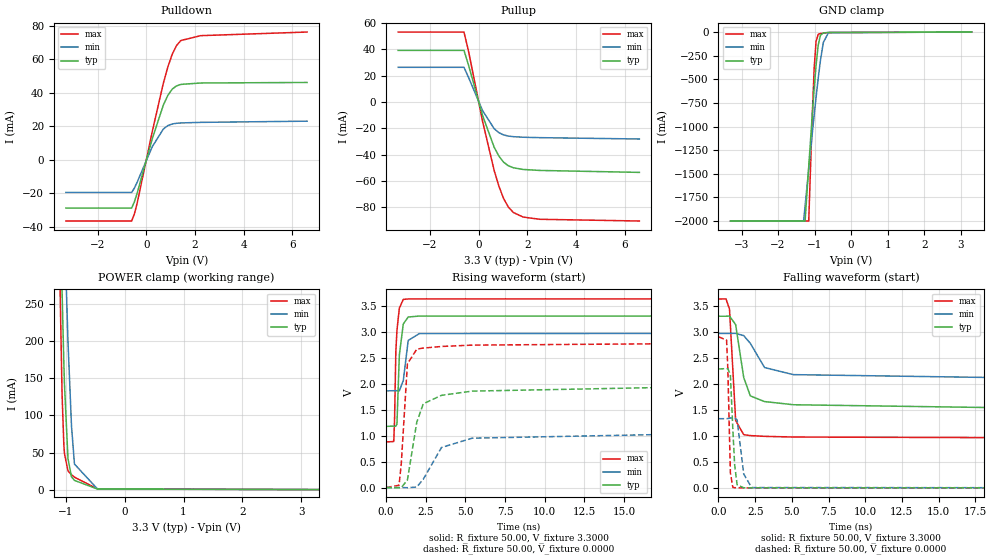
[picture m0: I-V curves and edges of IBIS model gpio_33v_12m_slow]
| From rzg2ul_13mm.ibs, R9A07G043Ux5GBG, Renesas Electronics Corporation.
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[Model]   gpio_33v_12m_slow
Model_type   I/O
Polarity   Non-Inverting
Enable   Active-Low
Vinl  =   0.8000V
Vinh  =   2.0000V
Vmeas =   1.6500V
Cref  =   15.00pF
| variable   typ   min   max
C_comp   2.126e-12  1.947e-12  2.126e-12
[Model Spec]
| Subparameter   typ   min   max
| Thresholds
Vinh   2.0000   NA   NA
Vinl   0.8000   NA   NA
| Timing Thresholds
Vmeas   1.6500   1.4850   1.8150
| variable   typ   min   max
[Temperature Range]   25.000   125.000   -40.000
| variable   typ   min   max
[Voltage Range]   3.300V   2.970V   3.630V
| variable   typ   min   max
[Pullup Reference]   3.300V   2.970V   3.630V
| variable   typ   min   max
[Pulldown Reference]   0.000V   0.000V   0.000V
| variable   typ   min   max
[POWER Clamp Reference] 3.300V   2.970V   3.630V
| variable   typ   min   max
[GND Clamp Reference]   0.000V   0.000V   0.000V
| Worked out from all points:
|   slope of the pulldown table from 0 to 0.495 V, typ, clamps not added: 20.4 ohm
|   slope of the pullup table from 0 to 0.495 V, typ, clamps not added: 17.6 ohm
|   GND clamp passes 1 mA (typ) near -0.48 V on its own axis
|   POWER clamp passes 1 mA (typ) near -0.48 V on its own axis
|   rising waveform, R_fixture 50.00, V_fixture 3.3000: 20-80 % time 190ps typ, 235ps min, 155ps max; typ from 1.18 V to 3.3 V
|   rising waveform, R_fixture 50.00, V_fixture 0.0000: 20-80 % time 3.08ns typ, 11ns min, 341ps max; typ from 0 V to 2.29 V
|   falling waveform, R_fixture 50.00, V_fixture 3.3000: 20-80 % time 3.61ns typ, 14.9ns min, 289ps max; typ from 3.3 V to 1.18 V
|   falling waveform, R_fixture 50.00, V_fixture 0.0000: 20-80 % time 209ps typ, 312ps min, 143ps max; typ from 2.29 V to 0 V
[Pulldown]
| gpio_33v_12m_slow Pulldown S28FDSIO_IBIS
| Wed Sep  2 14:14:57 2020
| voltage   I(typ)   I(min)   I(max)
-3.3V     -28.69mA   -19.38mA   -36.41mA
-600mV    -28.69mA   -19.38mA   -36.41mA
-490mV    -25.1mA    -16.85mA   -32.31mA
-380mV    -20.16mA   -13.49mA   -26.24mA
250mV     12.74mA    7.933mA    17.12mA
700mV     32.62mA    18.36mA    45.59mA
890mV     38.56mA    20.47mA    55.56mA
1.07V     42.21mA    21.4mA     63.08mA
1.24V     44.05mA    21.79mA    68.06mA
1.42V     44.96mA    22mA       71.09mA
2.23V     45.79mA    22.34mA    73.99mA
6.6V      46.12mA    23.06mA    76.15mA
[Pullup]
| gpio_33v_12m_slow Pullup S28FDSIO_IBIS
| Wed Sep  2 14:14:57 2020
| voltage   I(typ)   I(min)   I(max)
-3.3V     39.32mA    26.46mA    53.29mA
-600mV    39.32mA    26.46mA    53.29mA
-410mV    27.92mA    18.66mA    38.41mA
160mV     -10.03mA   -6.399mA   -14.38mA
640mV     -34.41mA   -20.27mA   -52.11mA
840mV     -41.31mA   -23.36mA   -64.39mA
1.03V     -45.78mA   -25.01mA   -73.49mA
1.22V     -48.45mA   -25.86mA   -79.84mA
1.43V     -50.01mA   -26.33mA   -84.05mA
1.83V     -51.27mA   -26.75mA   -87.5mA
2.51V     -52.02mA   -27.07mA   -89.19mA
6.6V      -53.5mA    -28.1mA    -90.5mA
[GND Clamp]
| gpio_33v_12m_slow GNDClamp S28FDSIO_IBIS
| Wed Sep  2 14:14:57 2020
| voltage   I(typ)   I(min)   I(max)
-3.3V     -2A        -2A        -2A
-1.3V     -2A        -2A        -2A
-1.26V    -2A        -1.843A    -2A
-1.16V    -1.422A    -1.447A    -2A
-1.06V    -856.1mA   -1.062A    -851.2mA
-1.01V    -593.2mA   -874.6mA   -376.4mA
-960mV    -356.1mA   -693.5mA   -100.4mA
-900mV    -137mA     -487.4mA   -24.05mA
-840mV    -34mA      -301mA     -16.13mA
-760mV    -9.995mA   -109.9mA   -12.09mA
-620mV    -4.238mA   -6.791mA   -5.995mA
3.3V      0A         0A         0A
[POWER Clamp]
| gpio_33v_12m_slow PWRClamp S28FDSIO_IBIS
| Wed Sep  2 14:14:57 2020
| voltage   I(typ)   I(min)   I(max)
-3.3V     2A         2A         2A
-1.12V    504.1mA    667.9mA    429.5mA
-1.1V     420.1mA    602.4mA    307.9mA
-1.09V    379.7mA    570.1mA    254.2mA
-1.06V    266.9mA    475.7mA    128.4mA
-1.03V    170.6mA    385.5mA    60.65mA
-1.02V    143.4mA    356.6mA    48.83mA
-960mV    41.76mA    199.8mA    25.26mA
-900mV    17.19mA    85.7mA     20.05mA
-850mV    12.44mA    34.48mA    16.76mA
-460mV    730.6uA    884.4uA    935.7uA
3.3V      0A         0A         0A
[Ramp]
dV/dt_r   1.372/3.069n   0.798/10.939n   1.743/340.627p
dV/dt_f   1.274/3.587n   0.667/14.805n   1.652/287.868p
R_load = 50.00ohm
[Rising Waveform]
| gpio_33v_12m_slow Rising-High S28FDSIO_IBIS
| Wed Sep  2 14:14:57 2020
R_fixture = 50.00
V_fixture = 3.3000
V_fixture_min = 2.9700
V_fixture_max = 3.6300
C_fixture = 0.00pF
| Time   V(typ)   V(min)   V(max)
0s        1.177V     1.859V     876.6mV
480ps     1.181V     1.863V     885.3mV
530ps     1.18V      1.864V     1.312V
610ps     1.18V      1.864V     2.619V
680ps     1.221V     1.862V     3.022V
830ps     2.547V     1.862V     3.449V
1.08ns    3.147V     2.057V     3.62V
1.39ns    3.281V     2.83V      3.628V
2.09ns    3.299V     2.962V     3.63V
40ns      3.3V       2.97V      3.63V
[Rising Waveform]
| gpio_33v_12m_slow Rising-Low S28FDSIO_IBIS
| Wed Sep  2 14:14:57 2020
R_fixture = 50.00
V_fixture = 0.0000
C_fixture = 0.00pF
| Time   V(typ)   V(min)   V(max)
0s        0V         0V         0V
810ps     -6.5mV     0V         42.6mV
950ps     -3.5mV     100uV      444.3mV
1.34ns    143.8mV    -4.1mV     2.38V
1.93ns    1.256V     8.5mV      2.662V
2.34ns    1.612V     159.3mV    2.683V
3.49ns    1.774V     771mV      2.714V
5.42ns    1.855V     949.2mV    2.74V
40ns      2.057V     1.155V     2.815V
40ns      2.286V     1.33V      2.904V
[Falling Waveform]
| gpio_33v_12m_slow Falling-High S28FDSIO_IBIS
| Wed Sep  2 14:14:57 2020
R_fixture = 50.00
V_fixture = 3.3000
V_fixture_min = 2.9700
V_fixture_max = 3.6300
C_fixture = 0.00pF
| Time   V(typ)   V(min)   V(max)
0s        3.3V       2.97V      3.63V
510ps     3.3V       2.97V      3.634V
750ps     3.303V     2.97V      3.438V
1.17ns    3.138V     2.971V     1.293V
1.72ns    2.121V     2.927V     1.023V
2.17ns    1.769V     2.779V     1.005V
3.14ns    1.659V     2.313V     990.3mV
5.11ns    1.598V     2.177V     977.2mV
40ns      1.457V     2.034V     945.7mV
40ns      1.177V     1.859V     876.6mV
[Falling Waveform]
| gpio_33v_12m_slow Falling-Low S28FDSIO_IBIS
| Wed Sep  2 14:14:57 2020
R_fixture = 50.00
V_fixture = 0.0000
C_fixture = 0.00pF
| Time   V(typ)   V(min)   V(max)
0s        2.286V     1.33V      2.904V
550ps     2.293V     1.33V      2.84V
640ps     2.292V     1.332V     2.268V
810ps     2.177V     1.343V     291.8mV
980ps     1.111V     1.34V      7.63mV
1.1ns     449.1mV    1.34V      3.08mV
1.27ns    56.35mV    1.307V     1.23mV
1.72ns    1.367mV    266.2mV    200uV
2.26ns    320uV      5.782mV    100uV
40ns      0V         0V         0V
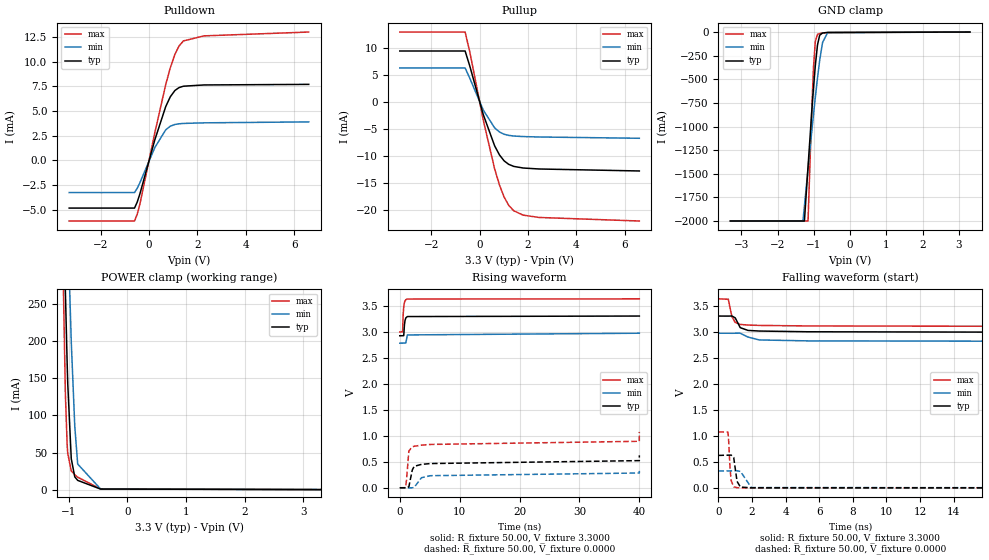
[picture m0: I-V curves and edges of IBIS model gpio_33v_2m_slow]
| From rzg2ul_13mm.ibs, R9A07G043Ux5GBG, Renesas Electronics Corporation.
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[Model]   gpio_33v_2m_slow
Model_type   I/O
Polarity   Non-Inverting
Enable   Active-Low
Vinl  =   0.8000V
Vinh  =   2.0000V
Vmeas =   1.6500V
Cref  =   15.00pF
| variable   typ   min   max
C_comp   2.126e-12  1.947e-12  2.126e-12
[Model Spec]
| Subparameter   typ   min   max
| Thresholds
Vinh   2.0000   NA   NA
Vinl   0.8000   NA   NA
| Timing Thresholds
Vmeas   1.6500   1.4850   1.8150
| variable   typ   min   max
[Temperature Range]   25.000   125.000   -40.000
| variable   typ   min   max
[Voltage Range]   3.300V   2.970V   3.630V
| variable   typ   min   max
[Pullup Reference]   3.300V   2.970V   3.630V
| variable   typ   min   max
[Pulldown Reference]   0.000V   0.000V   0.000V
| variable   typ   min   max
[POWER Clamp Reference] 3.300V   2.970V   3.630V
| variable   typ   min   max
[GND Clamp Reference]   0.000V   0.000V   0.000V
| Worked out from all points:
|   slope of the pulldown table from 0 to 0.495 V, typ, clamps not added: 120 ohm
|   slope of the pullup table from 0 to 0.495 V, typ, clamps not added: 72.9 ohm
|   GND clamp passes 1 mA (typ) near -0.48 V on its own axis
|   POWER clamp passes 1 mA (typ) near -0.48 V on its own axis
|   rising waveform, R_fixture 50.00, V_fixture 3.3000: 20-80 % time 192ps typ, 199ps min, 176ps max; typ from 2.92 V to 3.3 V
|   rising waveform, R_fixture 50.00, V_fixture 0.0000: 20-80 % time 14.7ns typ, 9.12ns min, 10.6ns max; typ from 0 V to 0.623 V
|   falling waveform, R_fixture 50.00, V_fixture 3.3000: 20-80 % time 5.13ns typ, 6.85ns min, 1.61ns max; typ from 3.3 V to 2.92 V
|   falling waveform, R_fixture 50.00, V_fixture 0.0000: 20-80 % time 154ps typ, 232ps min, 111ps max; typ from 0.623 V to 0 V
[Pulldown]
| gpio_33v_2m_slow Pulldown S28FDSIO_IBIS
| Wed Sep  2 14:14:57 2020
| voltage   I(typ)   I(min)   I(max)
-3.3V     -4.843mA   -3.271mA   -6.154mA
-600mV    -4.843mA   -3.271mA   -6.154mA
-490mV    -4.248mA   -2.848mA   -5.476mA
-380mV    -3.424mA   -2.285mA   -4.468mA
240mV     2.077mA    1.294mA    2.803mA
690mV     5.444mA    3.087mA    7.674mA
880mV     6.443mA    3.458mA    9.39mA
1.07V     7.077mA    3.631mA    10.75mA
1.24V     7.369mA    3.699mA    11.59mA
1.42V     7.509mA    3.735mA    12.1mA
2.27V     7.636mA    3.796mA    12.61mA
6.6V      7.695mA    3.892mA    13mA
[Pullup]
| gpio_33v_2m_slow Pullup S28FDSIO_IBIS
| Wed Sep  2 14:14:57 2020
| voltage   I(typ)   I(min)   I(max)
-3.3V     9.532mA    6.373mA    13.06mA
-600mV    9.532mA    6.373mA    13.06mA
-410mV    6.783mA    4.5mA      9.437mA
150mV     -2.286mA   -1.45mA    -3.313mA
620mV     -8.112mA   -4.766mA   -12.4mA
820mV     -9.803mA   -5.538mA   -15.41mA
1.01V     -10.9mA    -5.954mA   -17.63mA
1.2V      -11.55mA   -6.168mA   -19.17mA
1.41V     -11.94mA   -6.288mA   -20.19mA
1.8V      -12.24mA   -6.39mA    -21.01mA
2.46V     -12.42mA   -6.468mA   -21.44mA
6.6V      -12.79mA   -6.706mA   -22.1mA
[GND Clamp]
| gpio_33v_2m_slow GNDClamp S28FDSIO_IBIS
| Wed Sep  2 14:14:57 2020
| voltage   I(typ)   I(min)   I(max)
-3.3V     -2A        -2A        -2A
-1.3V     -2A        -2A        -2A
-1.26V    -2A        -1.843A    -2A
-1.16V    -1.422A    -1.447A    -2A
-1.06V    -856.1mA   -1.062A    -851.2mA
-1.01V    -593.2mA   -874.6mA   -376.4mA
-960mV    -356.1mA   -693.5mA   -100.4mA
-900mV    -137mA     -487.4mA   -24.05mA
-840mV    -34mA      -301mA     -16.13mA
-760mV    -9.995mA   -109.9mA   -12.09mA
-620mV    -4.238mA   -6.791mA   -5.995mA
3.3V      0A         0A         0A
[POWER Clamp]
| gpio_33v_2m_slow PWRClamp S28FDSIO_IBIS
| Wed Sep  2 14:14:57 2020
| voltage   I(typ)   I(min)   I(max)
-3.3V     2A         2A         2A
-1.12V    504.1mA    667.9mA    429.5mA
-1.1V     420.1mA    602.4mA    308mA
-1.09V    379.7mA    570.1mA    254.2mA
-1.06V    266.9mA    475.7mA    128.4mA
-1.03V    170.6mA    385.5mA    60.65mA
-1.02V    143.4mA    356.6mA    48.83mA
-960mV    41.76mA    199.8mA    25.26mA
-900mV    17.19mA    85.7mA     20.05mA
-850mV    12.44mA    34.49mA    16.76mA
-460mV    730.7uA    884.4uA    935.7uA
3.3V      0A         0A         0A
[Ramp]
dV/dt_r   0.374/14.433n   0.195/8.962n   0.645/10.520n
dV/dt_f   0.227/4.939n   0.114/6.648n   0.381/1.601n
R_load = 50.00ohm
[Rising Waveform]
| gpio_33v_2m_slow Rising-High S28FDSIO_IBIS
| Wed Sep  2 14:14:57 2020
R_fixture = 50.00
V_fixture = 3.3000
V_fixture_min = 2.9700
V_fixture_max = 3.6300
C_fixture = 0.00pF
| Time   V(typ)   V(min)   V(max)
0s        2.921V     2.779V     2.994V
470ps     2.922V     2.779V     2.997V
570ps     2.923V     2.78V      3.332V
660ps     2.923V     2.78V      3.478V
700ps     2.99V      2.78V      3.515V
780ps     3.131V     2.78V      3.562V
880ps     3.216V     2.781V     3.593V
1.01ns    3.264V     2.784V     3.615V
1.27ns    3.29V      2.937V     3.627V
40ns      3.3V       2.97V      3.63V
[Rising Waveform]
| gpio_33v_2m_slow Rising-Low S28FDSIO_IBIS
| Wed Sep  2 14:14:57 2020
R_fixture = 50.00
V_fixture = 0.0000
C_fixture = 0.00pF
| Time   V(typ)   V(min)   V(max)
0s        0V         0V         0V
960ps     -300uV     100uV      2.8mV
1.11ns    -100uV     -1.4mV     132.7mV
1.52ns    19.6mV     0V         708.6mV
2.09ns    342.2mV    0V         787.9mV
2.4ns     411.4mV    6mV        797.9mV
3.62ns    449.7mV    193.5mV    819.1mV
5.12ns    465.3mV    232.2mV    832.8mV
40ns      521.7mV    283.8mV    893.1mV
40ns      623.3mV    324.2mV    1.074V
[Falling Waveform]
| gpio_33v_2m_slow Falling-High S28FDSIO_IBIS
| Wed Sep  2 14:14:57 2020
R_fixture = 50.00
V_fixture = 3.3000
V_fixture_min = 2.9700
V_fixture_max = 3.6300
C_fixture = 0.00pF
| Time   V(typ)   V(min)   V(max)
0s        3.3V       2.97V      3.63V
590ps     3.299V     2.97V      3.623V
800ps     3.301V     2.969V     3.291V
1ns       3.265V     2.97V      3.178V
1.3ns     3.077V     2.971V     3.139V
1.76ns    3.024V     2.897V     3.127V
2.43ns    3.012V     2.841V     3.12V
5.31ns    2.998V     2.823V     3.11V
40ns      2.977V     2.804V     3.09V
40ns      2.921V     2.779V     2.994V
[Falling Waveform]
| gpio_33v_2m_slow Falling-Low S28FDSIO_IBIS
| Wed Sep  2 14:14:57 2020
R_fixture = 50.00
V_fixture = 0.0000
C_fixture = 0.00pF
| Time   V(typ)   V(min)   V(max)
0s        623.3mV    324.2mV    1.074V
560ps     627.4mV    324.2mV    1.072V
600ps     628.3mV    324mV      973.1mV
690ps     628.3mV    325.4mV    388.1mV
760ps     629.8mV    326.7mV    141mV
910ps     584.6mV    327.5mV    20.39mV
1.11ns    124.4mV    327.2mV    3.78mV
1.31ns    15.06mV    316.6mV    1.39mV
1.96ns    502uV      5.691mV    146uV
40ns      0V         0V         0V
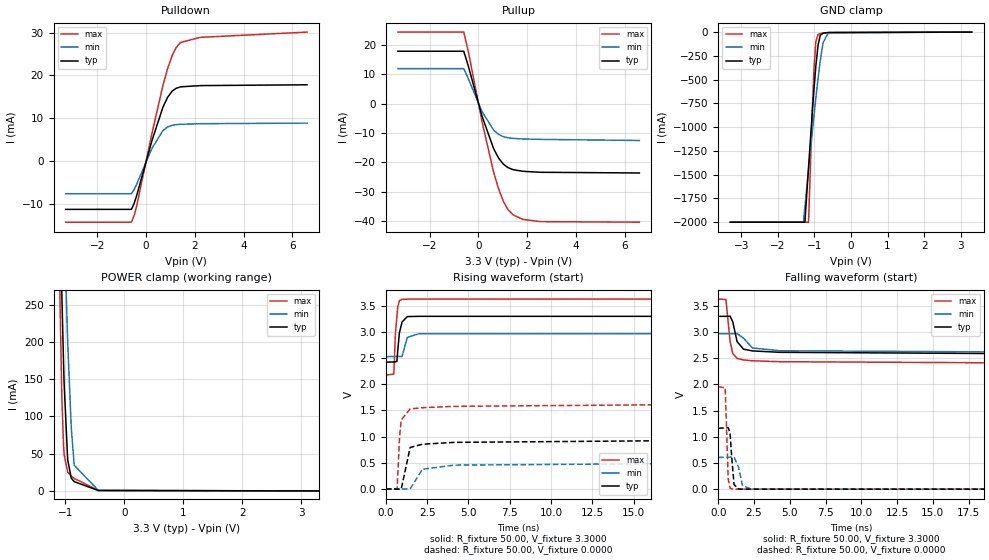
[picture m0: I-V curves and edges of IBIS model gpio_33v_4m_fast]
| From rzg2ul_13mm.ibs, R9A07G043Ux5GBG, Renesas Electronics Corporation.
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[Model]   gpio_33v_4m_fast
Model_type   I/O
Polarity   Non-Inverting
Enable   Active-Low
Vinl  =   0.8000V
Vinh  =   2.0000V
Vmeas =   1.6500V
Cref  =   15.00pF
| variable   typ   min   max
C_comp   2.126e-12  1.947e-12  2.126e-12
[Model Spec]
| Subparameter   typ   min   max
| Thresholds
Vinh   2.0000   NA   NA
Vinl   0.8000   NA   NA
| Timing Thresholds
Vmeas   1.6500   1.4850   1.8150
| variable   typ   min   max
[Temperature Range]   25.000   125.000   -40.000
| variable   typ   min   max
[Voltage Range]   3.300V   2.970V   3.630V
| variable   typ   min   max
[Pullup Reference]   3.300V   2.970V   3.630V
| variable   typ   min   max
[Pulldown Reference]   0.000V   0.000V   0.000V
| variable   typ   min   max
[POWER Clamp Reference] 3.300V   2.970V   3.630V
| variable   typ   min   max
[GND Clamp Reference]   0.000V   0.000V   0.000V
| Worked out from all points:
|   slope of the pulldown table from 0 to 0.495 V, typ, clamps not added: 52.2 ohm
|   slope of the pullup table from 0 to 0.495 V, typ, clamps not added: 38.8 ohm
|   GND clamp passes 1 mA (typ) near -0.48 V on its own axis
|   POWER clamp passes 1 mA (typ) near -0.48 V on its own axis
|   rising waveform, R_fixture 50.00, V_fixture 3.3000: 20-80 % time 199ps typ, 208ps min, 169ps max; typ from 2.42 V to 3.3 V
|   rising waveform, R_fixture 50.00, V_fixture 0.0000: 20-80 % time 10.2ns typ, 6.58ns min, 2.11ns max; typ from 0 V to 1.16 V
|   falling waveform, R_fixture 50.00, V_fixture 3.3000: 20-80 % time 5.57ns typ, 8.04ns min, 1.06ns max; typ from 3.3 V to 2.42 V
|   falling waveform, R_fixture 50.00, V_fixture 0.0000: 20-80 % time 164ps typ, 252ps min, 112ps max; typ from 1.16 V to 0 V
[Pulldown]
| gpio_33v_4m_fast Pulldown S28FDSIO_IBIS
| Wed Sep  2 14:14:57 2020
| voltage   I(typ)   I(min)   I(max)
-3.3V     -11.23mA   -7.582mA   -14.22mA
-600mV    -11.23mA   -7.582mA   -14.22mA
-490mV    -9.838mA   -6.599mA   -12.64mA
-390mV    -8.113mA   -5.423mA   -10.55mA
240mV     4.79mA     2.992mA    6.447mA
690mV     12.57mA    7.131mA    17.63mA
880mV     14.88mA    7.986mA    21.55mA
1.07V     16.35mA    8.381mA    24.65mA
1.24V     17.03mA    8.536mA    26.56mA
1.42V     17.35mA    8.617mA    27.72mA
2.23V     17.64mA    8.751mA    28.89mA
6.6V      17.83mA    8.888mA    30.12mA
[Pullup]
| gpio_33v_4m_fast Pullup S28FDSIO_IBIS
| Wed Sep  2 14:14:57 2020
| voltage   I(typ)   I(min)   I(max)
-3.3V     17.9mA     11.97mA    24.44mA
-600mV    17.9mA     11.97mA    24.44mA
-410mV    12.74mA    8.452mA    17.66mA
150mV     -4.295mA   -2.723mA   -6.199mA
630mV     -15.44mA   -9.049mA   -23.51mA
830mV     -18.57mA   -10.47mA   -29.1mA
1.02V     -20.59mA   -11.22mA   -33.21mA
1.21V     -21.79mA   -11.61mA   -36.05mA
1.42V     -22.49mA   -11.83mA   -37.92mA
1.83V     -23.06mA   -12.02mA   -39.47mA
2.54V     -23.39mA   -12.17mA   -40.23mA
6.6V      -23.63mA   -12.54mA   -40.42mA
[GND Clamp]
| gpio_33v_4m_fast GNDClamp S28FDSIO_IBIS
| Wed Sep  2 14:14:57 2020
| voltage   I(typ)   I(min)   I(max)
-3.3V     -2A        -2A        -2A
-1.3V     -2A        -2A        -2A
-1.26V    -2A        -1.843A    -2A
-1.16V    -1.422A    -1.447A    -2A
-1.06V    -856.1mA   -1.062A    -851.2mA
-1.01V    -593.2mA   -874.6mA   -376.4mA
-960mV    -356.1mA   -693.5mA   -100.4mA
-900mV    -137mA     -487.4mA   -24.05mA
-840mV    -34mA      -301mA     -16.13mA
-760mV    -9.995mA   -109.9mA   -12.09mA
-620mV    -4.238mA   -6.791mA   -5.995mA
3.3V      0A         0A         0A
[POWER Clamp]
| gpio_33v_4m_fast PWRClamp S28FDSIO_IBIS
| Wed Sep  2 14:14:57 2020
| voltage   I(typ)   I(min)   I(max)
-3.3V     2A         2A         2A
-1.12V    504.1mA    667.9mA    429.5mA
-1.1V     420.1mA    602.4mA    307.9mA
-1.09V    379.7mA    570.1mA    254.2mA
-1.06V    266.9mA    475.7mA    128.4mA
-1.03V    170.6mA    385.5mA    60.64mA
-1.02V    143.4mA    356.6mA    48.82mA
-960mV    41.76mA    199.8mA    25.26mA
-900mV    17.19mA    85.7mA     20.04mA
-850mV    12.44mA    34.48mA    16.76mA
-440mV    550.1uA    715.7uA    681.2uA
3.3V      0A         0A         0A
[Ramp]
dV/dt_r   0.698/10.076n   0.364/6.442n   1.173/2.098n
dV/dt_f   0.525/5.465n   0.263/7.921n   0.871/1.062n
R_load = 50.00ohm
[Rising Waveform]
| gpio_33v_4m_fast Rising-High S28FDSIO_IBIS
| Wed Sep  2 14:14:57 2020
R_fixture = 50.00
V_fixture = 3.3000
V_fixture_min = 2.9700
V_fixture_max = 3.6300
C_fixture = 0.00pF
| Time   V(typ)   V(min)   V(max)
0s        2.425V     2.531V     2.178V
480ps     2.428V     2.532V     2.195V
580ps     2.429V     2.533V     2.975V
670ps     2.44V      2.533V     3.305V
720ps     2.647V     2.532V     3.482V
820ps     2.985V     2.533V     3.601V
980ps     3.192V     2.533V     3.624V
1.3ns     3.295V     2.898V     3.629V
2.01ns    3.3V       2.968V     3.63V
40ns      3.3V       2.97V      3.63V
[Rising Waveform]
| gpio_33v_4m_fast Rising-Low S28FDSIO_IBIS
| Wed Sep  2 14:14:57 2020
R_fixture = 50.00
V_fixture = 0.0000
C_fixture = 0.00pF
| Time   V(typ)   V(min)   V(max)
0s        0V         0V         0V
680ps     -2.8mV     200uV      3mV
830ps     -3.7mV     0V         996.1mV
930ps     -1.6mV     200uV      1.319V
1.47ns    793.2mV    -500uV     1.531V
2.21ns    855.2mV    376.8mV    1.553V
4.14ns    890.7mV    455.7mV    1.579V
39ns      977.6mV    532.2mV    1.665V
40ns      993.8mV    544.6mV    1.681V
40ns      1.163V     607.3mV    1.956V
[Falling Waveform]
| gpio_33v_4m_fast Falling-High S28FDSIO_IBIS
| Wed Sep  2 14:14:57 2020
R_fixture = 50.00
V_fixture = 3.3000
V_fixture_min = 2.9700
V_fixture_max = 3.6300
C_fixture = 0.00pF
| Time   V(typ)   V(min)   V(max)
0s        3.3V       2.97V      3.63V
540ps     3.3V       2.97V      3.622V
830ps     3.304V     2.97V      2.823V
1.02ns    3.195V     2.97V      2.59V
1.32ns    2.818V     2.973V     2.498V
1.77ns    2.673V     2.883V     2.467V
2.39ns    2.64V      2.696V     2.452V
4.32ns    2.613V     2.643V     2.434V
40ns      2.557V     2.59V      2.383V
40ns      2.425V     2.531V     2.178V
[Falling Waveform]
| gpio_33v_4m_fast Falling-Low S28FDSIO_IBIS
| Wed Sep  2 14:14:57 2020
R_fixture = 50.00
V_fixture = 0.0000
C_fixture = 0.00pF
| Time   V(typ)   V(min)   V(max)
0s        1.163V     607.3mV    1.956V
490ps     1.17V      607.3mV    1.935V
700ps     1.175V     609.9mV    194.4mV
830ps     1.07V      613.2mV    18.99mV
940ps     626.5mV    613.1mV    5.95mV
1.11ns    87.18mV    613.1mV    2.13mV
1.43ns    3.02mV     413.7mV    577uV
1.7ns     1.005mV    67.87mV    226uV
2.32ns    243uV      1.134mV    100uV
40ns      0V         0V         0V
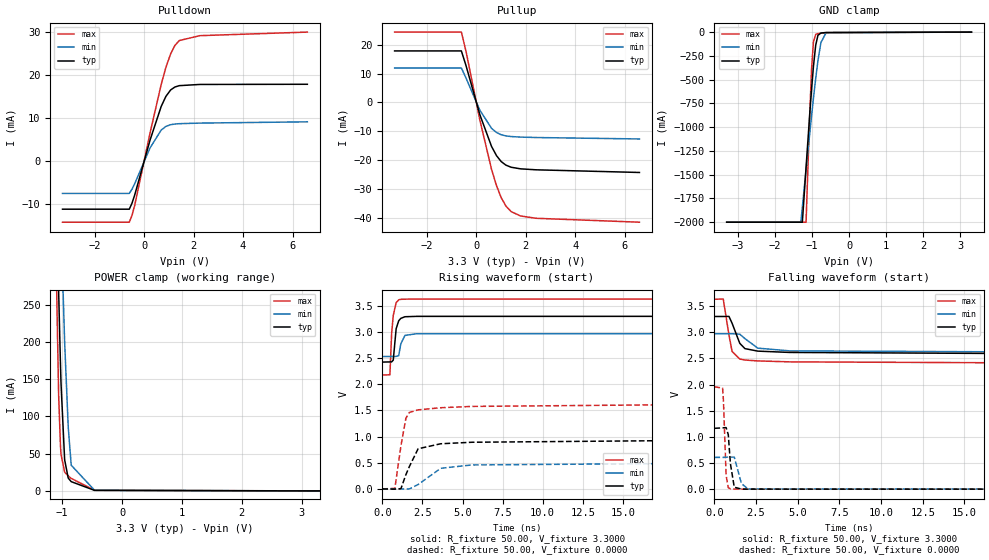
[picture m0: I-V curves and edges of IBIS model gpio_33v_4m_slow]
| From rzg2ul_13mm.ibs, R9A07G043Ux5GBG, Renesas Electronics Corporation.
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[Model]   gpio_33v_4m_slow
Model_type   I/O
Polarity   Non-Inverting
Enable   Active-Low
Vinl  =   0.8000V
Vinh  =   2.0000V
Vmeas =   1.6500V
Cref  =   15.00pF
| variable   typ   min   max
C_comp   2.126e-12  1.947e-12  2.126e-12
[Model Spec]
| Subparameter   typ   min   max
| Thresholds
Vinh   2.0000   NA   NA
Vinl   0.8000   NA   NA
| Timing Thresholds
Vmeas   1.6500   1.4850   1.8150
| variable   typ   min   max
[Temperature Range]   25.000   125.000   -40.000
| variable   typ   min   max
[Voltage Range]   3.300V   2.970V   3.630V
| variable   typ   min   max
[Pullup Reference]   3.300V   2.970V   3.630V
| variable   typ   min   max
[Pulldown Reference]   0.000V   0.000V   0.000V
| variable   typ   min   max
[POWER Clamp Reference] 3.300V   2.970V   3.630V
| variable   typ   min   max
[GND Clamp Reference]   0.000V   0.000V   0.000V
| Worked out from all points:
|   slope of the pulldown table from 0 to 0.495 V, typ, clamps not added: 52 ohm
|   slope of the pullup table from 0 to 0.495 V, typ, clamps not added: 38.8 ohm
|   GND clamp passes 1 mA (typ) near -0.48 V on its own axis
|   POWER clamp passes 1 mA (typ) near -0.48 V on its own axis
|   rising waveform, R_fixture 50.00, V_fixture 3.3000: 20-80 % time 195ps typ, 206ps min, 180ps max; typ from 2.42 V to 3.3 V
|   rising waveform, R_fixture 50.00, V_fixture 0.0000: 20-80 % time 11.2ns typ, 7.52ns min, 3.5ns max; typ from 0 V to 1.16 V
|   falling waveform, R_fixture 50.00, V_fixture 3.3000: 20-80 % time 5.75ns typ, 8.1ns min, 1.12ns max; typ from 3.3 V to 2.42 V
|   falling waveform, R_fixture 50.00, V_fixture 0.0000: 20-80 % time 170ps typ, 252ps min, 121ps max; typ from 1.16 V to 0 V
[Pulldown]
| gpio_33v_4m_slow Pulldown S28FDSIO_IBIS
| Wed Sep  2 14:14:57 2020
| voltage   I(typ)   I(min)   I(max)
-3.3V     -11.24mA   -7.582mA   -14.26mA
-600mV    -11.24mA   -7.582mA   -14.26mA
-490mV    -9.849mA   -6.599mA   -12.68mA
-380mV    -7.929mA   -5.291mA   -10.33mA
240mV     4.812mA    2.992mA    6.477mA
690mV     12.62mA    7.131mA    17.72mA
880mV     14.95mA    7.986mA    21.68mA
1.07V     16.44mA    8.381mA    24.81mA
1.24V     17.12mA    8.536mA    26.75mA
1.42V     17.45mA    8.617mA    27.92mA
2.25V     17.73mA    8.753mA    29.06mA
6.6V      17.77mA    9.048mA    29.89mA
[Pullup]
| gpio_33v_4m_slow Pullup S28FDSIO_IBIS
| Wed Sep  2 14:14:57 2020
| voltage   I(typ)   I(min)   I(max)
-3.3V     17.9mA     11.97mA    24.44mA
-600mV    17.9mA     11.97mA    24.44mA
-410mV    12.74mA    8.452mA    17.66mA
150mV     -4.295mA   -2.723mA   -6.199mA
620mV     -15.25mA   -8.959mA   -23.2mA
820mV     -18.44mA   -10.41mA   -28.85mA
1.01V     -20.51mA   -11.19mA   -33.03mA
1.2V      -21.74mA   -11.6mA    -35.93mA
1.41V     -22.47mA   -11.82mA   -37.86mA
1.79V     -23.03mA   -12.01mA   -39.39mA
2.43V     -23.37mA   -12.16mA   -40.2mA
6.6V      -24.29mA   -12.66mA   -41.55mA
[GND Clamp]
| gpio_33v_4m_slow GNDClamp S28FDSIO_IBIS
| Wed Sep  2 14:14:57 2020
| voltage   I(typ)   I(min)   I(max)
-3.3V     -2A        -2A        -2A
-1.3V     -2A        -2A        -2A
-1.26V    -2A        -1.843A    -2A
-1.16V    -1.422A    -1.447A    -2A
-1.06V    -856.1mA   -1.062A    -851.2mA
-1.01V    -593.2mA   -874.6mA   -376.4mA
-960mV    -356.1mA   -693.5mA   -100.4mA
-900mV    -137mA     -487.4mA   -24.05mA
-840mV    -34mA      -301mA     -16.13mA
-760mV    -9.995mA   -109.9mA   -12.09mA
-620mV    -4.238mA   -6.791mA   -5.995mA
3.3V      0A         0A         0A
[POWER Clamp]
| gpio_33v_4m_slow PWRClamp S28FDSIO_IBIS
| Wed Sep  2 14:14:57 2020
| voltage   I(typ)   I(min)   I(max)
-3.3V     2A         2A         2A
-1.12V    504.1mA    667.9mA    429.5mA
-1.1V     420.1mA    602.4mA    308mA
-1.09V    379.7mA    570.1mA    254.2mA
-1.06V    266.9mA    475.7mA    128.4mA
-1.03V    170.6mA    385.5mA    60.65mA
-1.02V    143.4mA    356.6mA    48.83mA
-960mV    41.76mA    199.8mA    25.26mA
-900mV    17.19mA    85.7mA     20.05mA
-850mV    12.44mA    34.48mA    16.76mA
-460mV    730.6uA    884.4uA    935.7uA
3.3V      0A         0A         0A
[Ramp]
dV/dt_r   0.698/11.167n   0.364/7.274n   1.173/3.495n
dV/dt_f   0.525/5.602n   0.263/8.085n   0.871/1.122n
R_load = 50.00ohm
[Rising Waveform]
| gpio_33v_4m_slow Rising-High S28FDSIO_IBIS
| Wed Sep  2 14:14:57 2020
R_fixture = 50.00
V_fixture = 3.3000
V_fixture_min = 2.9700
V_fixture_max = 3.6300
C_fixture = 0.00pF
| Time   V(typ)   V(min)   V(max)
0s        2.425V     2.531V     2.178V
470ps     2.428V     2.532V     2.182V
580ps     2.429V     2.533V     2.978V
680ps     2.463V     2.533V     3.318V
860ps     3.063V     2.533V     3.561V
1.02ns    3.215V     2.548V     3.616V
1.15ns    3.261V     2.772V     3.625V
1.41ns    3.292V     2.935V     3.628V
2.1ns     3.299V     2.966V     3.63V
40ns      3.3V       2.97V      3.63V
[Rising Waveform]
| gpio_33v_4m_slow Rising-Low S28FDSIO_IBIS
| Wed Sep  2 14:14:57 2020
R_fixture = 50.00
V_fixture = 0.0000
C_fixture = 0.00pF
| Time   V(typ)   V(min)   V(max)
0s        0V         0V         0V
780ps     -5.3mV     0V         8.9mV
1.16ns    5.3mV      -2.9mV     824.2mV
1.47ns    273.6mV    -400uV     1.354V
1.69ns    430.6mV    -100uV     1.463V
2.23ns    767.4mV    83.6mV     1.511V
3.64ns    862.9mV    393.9mV    1.552V
5.58ns    891.8mV    457.7mV    1.577V
40ns      979mV      533.3mV    1.666V
40ns      1.163V     607.3mV    1.956V
[Falling Waveform]
| gpio_33v_4m_slow Falling-High S28FDSIO_IBIS
| Wed Sep  2 14:14:57 2020
R_fixture = 50.00
V_fixture = 3.3000
V_fixture_min = 2.9700
V_fixture_max = 3.6300
C_fixture = 0.00pF
| Time   V(typ)   V(min)   V(max)
0s        3.3V       2.97V      3.63V
530ps     3.3V       2.97V      3.633V
870ps     3.302V     2.97V      2.947V
1.06ns    3.17V      2.97V      2.63V
1.52ns    2.787V     2.962V     2.487V
1.83ns    2.686V     2.877V     2.468V
2.6ns     2.638V     2.695V     2.451V
4.51ns    2.613V     2.643V     2.433V
40ns      2.557V     2.591V     2.383V
40ns      2.425V     2.531V     2.178V
[Falling Waveform]
| gpio_33v_4m_slow Falling-Low S28FDSIO_IBIS
| Wed Sep  2 14:14:57 2020
R_fixture = 50.00
V_fixture = 0.0000
C_fixture = 0.00pF
| Time   V(typ)   V(min)   V(max)
0s        1.163V     607.3mV    1.956V
490ps     1.171V     607.3mV    1.932V
540ps     1.173V     607.3mV    1.689V
700ps     1.177V     611mV      264mV
830ps     1.042V     613.4mV    26.44mV
960ps     482.9mV    612.6mV    5.85mV
1.19ns    37.6mV     612.4mV    1.653mV
1.62ns    1.46mV     107mV      338uV
2.02ns    458uV      4.383mV    113uV
40ns      0V         0V         0V
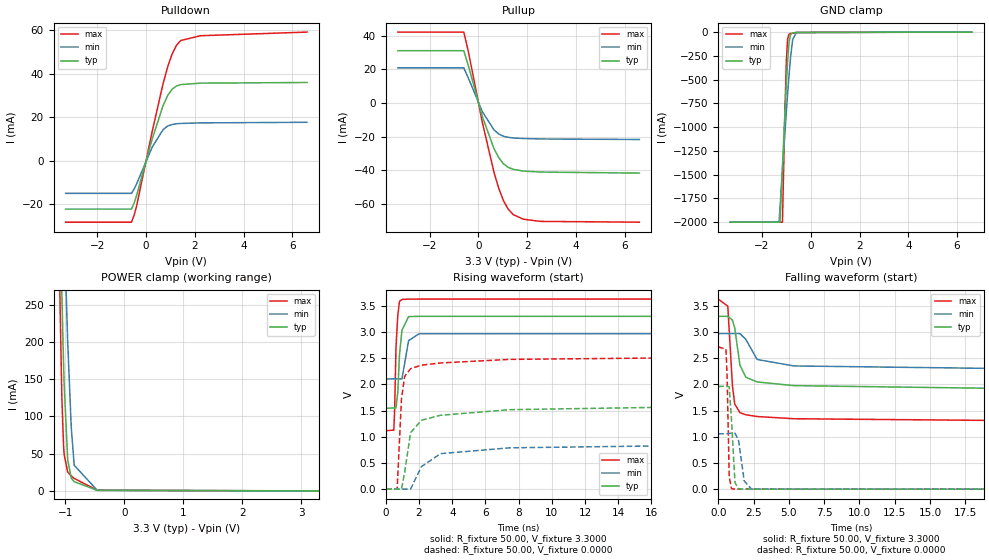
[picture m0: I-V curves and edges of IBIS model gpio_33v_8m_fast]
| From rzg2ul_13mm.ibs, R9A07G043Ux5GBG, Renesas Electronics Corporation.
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[Model]   gpio_33v_8m_fast
Model_type   I/O
Polarity   Non-Inverting
Enable   Active-Low
Vinl  =   0.8000V
Vinh  =   2.0000V
Vmeas =   1.6500V
Cref  =   15.00pF
| variable   typ   min   max
C_comp   2.126e-12  1.947e-12  2.166e-12
[Model Spec]
| Subparameter   typ   min   max
| Thresholds
Vinh   2.0000   NA   NA
Vinl   0.8000   NA   NA
| Timing Thresholds
Vmeas   1.6500   1.4850   1.8150
| variable   typ   min   max
[Temperature Range]   25.000   125.000   -40.000
| variable   typ   min   max
[Voltage Range]   3.300V   2.970V   3.630V
| variable   typ   min   max
[Pullup Reference]   3.300V   2.970V   3.630V
| variable   typ   min   max
[Pulldown Reference]   0.000V   0.000V   0.000V
| variable   typ   min   max
[POWER Clamp Reference] 3.300V   2.970V   3.630V
| variable   typ   min   max
[GND Clamp Reference]   0.000V   0.000V   0.000V
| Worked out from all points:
|   slope of the pulldown table from 0 to 0.495 V, typ, clamps not added: 26.1 ohm
|   slope of the pullup table from 0 to 0.495 V, typ, clamps not added: 22.3 ohm
|   GND clamp passes 1 mA (typ) near -0.48 V on its own axis
|   POWER clamp passes 1 mA (typ) near -0.48 V on its own axis
|   rising waveform, R_fixture 50.00, V_fixture 3.3000: 20-80 % time 205ps typ, 235ps min, 149ps max; typ from 1.54 V to 3.3 V
|   rising waveform, R_fixture 50.00, V_fixture 0.0000: 20-80 % time 11.3ns typ, 14.1ns min, 381ps max; typ from 0 V to 1.96 V
|   falling waveform, R_fixture 50.00, V_fixture 3.3000: 20-80 % time 19.5ns typ, 17.7ns min, 395ps max; typ from 3.3 V to 1.54 V
|   falling waveform, R_fixture 50.00, V_fixture 0.0000: 20-80 % time 196ps typ, 305ps min, 119ps max; typ from 1.96 V to 0 V
[Pulldown]
| gpio_33v_8m_fast Pulldown S28FDSIO_IBIS
| Wed Sep  2 14:14:57 2020
| voltage   I(typ)   I(min)   I(max)
-3.3V     -22.36mA   -15.1mA    -28.39mA
-600mV    -22.36mA   -15.1mA    -28.39mA
-490mV    -19.58mA   -13.14mA   -25.22mA
-390mV    -16.13mA   -10.79mA   -21mA
250mV     9.951mA    6.188mA    13.38mA
700mV     25.45mA    14.31mA    35.6mA
890mV     30.07mA    15.94mA    43.36mA
1.07V     32.91mA    16.66mA    49.19mA
1.24V     34.33mA    16.96mA    53.02mA
1.42V     35.03mA    17.12mA    55.34mA
2.23V     35.7mA     17.38mA    57.55mA
6.6V      36mA       17.66mA    59.23mA
[Pullup]
| gpio_33v_8m_fast Pullup S28FDSIO_IBIS
| Wed Sep  2 14:14:57 2020
| voltage   I(typ)   I(min)   I(max)
-3.3V     31.13mA    20.95mA    42.21mA
-600mV    31.13mA    20.95mA    42.21mA
-410mV    22.13mA    14.78mA    30.48mA
160mV     -7.943mA   -5.066mA   -11.41mA
640mV     -27.21mA   -16.02mA   -41.3mA
840mV     -32.65mA   -18.46mA   -51mA
1.03V     -36.17mA   -19.76mA   -58.16mA
1.22V     -38.26mA   -20.42mA   -63.13mA
1.43V     -39.48mA   -20.79mA   -66.42mA
1.84V     -40.48mA   -21.13mA   -69.13mA
2.55V     -41.08mA   -21.39mA   -70.44mA
6.6V      -41.7mA    -21.7mA    -70.91mA
[GND Clamp]
| gpio_33v_8m_fast GNDClamp S28FDSIO_IBIS
| Wed Sep  2 14:14:57 2020
| voltage   I(typ)   I(min)   I(max)
-3.3V     -2A        -2A        -2A
-1.3V     -2A        -2A        -2A
-1.26V    -2A        -1.843A    -2A
-1.16V    -1.422A    -1.447A    -2A
-1.06V    -856.1mA   -1.062A    -851.2mA
-1V       -543.2mA   -837.9mA   -301.9mA
-950mV    -313.4mA   -658.1mA   -73.98mA
-890mV    -111.1mA   -454.6mA   -21.52mA
-830mV    -27.1mA    -272.8mA   -15.54mA
-740mV    -8.672mA   -77.77mA   -11.17mA
-590mV    -3.392mA   -4.191mA   -4.835mA
6.6V      0A         0A         0A
[POWER Clamp]
| gpio_33v_8m_fast PWRClamp S28FDSIO_IBIS
| Wed Sep  2 14:14:57 2020
| voltage   I(typ)   I(min)   I(max)
-3.3V     2A         2A         2A
-1.12V    504.1mA    667.9mA    429.5mA
-1.1V     420.1mA    602.4mA    307.9mA
-1.09V    379.7mA    570.1mA    254.2mA
-1.06V    266.9mA    475.7mA    128.4mA
-1.03V    170.6mA    385.5mA    60.65mA
-1.02V    143.4mA    356.6mA    48.83mA
-960mV    41.76mA    199.8mA    25.26mA
-900mV    17.19mA    85.7mA     20.05mA
-850mV    12.44mA    34.48mA    16.76mA
-460mV    730.6uA    884.4uA    935.7uA
3.3V      0A         0A         0A
[Ramp]
dV/dt_r   1.175/11.175n   0.635/13.897n   1.630/381.116p
dV/dt_f   1.030/10.398n   0.521/17.515n   1.510/394.120p
R_load = 50.00ohm
[Rising Waveform]
| gpio_33v_8m_fast Rising-High S28FDSIO_IBIS
| Wed Sep  2 14:14:57 2020
R_fixture = 50.00
V_fixture = 3.3000
V_fixture_min = 2.9700
V_fixture_max = 3.6300
C_fixture = 0.00pF
| Time   V(typ)   V(min)   V(max)
0s        1.543V     2.102V     1.114V
480ps     1.548V     2.105V     1.125V
530ps     1.548V     2.106V     1.53V
610ps     1.548V     2.106V     2.709V
720ps     1.85V      2.105V     3.322V
820ps     2.562V     2.105V     3.586V
970ps     3.035V     2.104V     3.623V
1.37ns    3.295V     2.836V     3.629V
2ns       3.3V       2.966V     3.63V
40ns      3.3V       2.97V      3.63V
[Rising Waveform]
| gpio_33v_8m_fast Rising-Low S28FDSIO_IBIS
| Wed Sep  2 14:14:57 2020
R_fixture = 50.00
V_fixture = 0.0000
C_fixture = 0.00pF
| Time   V(typ)   V(min)   V(max)
0s        0V         0V         0V
680ps     -2.8mV     100uV      500uV
940ps     -3.3mV     100uV      1.719V
1.13ns    313.3mV    -3.1mV     2.151V
1.49ns    1.078V     -1.2mV     2.301V
2.14ns    1.313V     426.3mV    2.366V
3.29ns    1.409V     674.9mV    2.409V
7.46ns    1.516V     786.9mV    2.477V
40ns      1.678V     919.9mV    2.574V
40ns      1.958V     1.058V     2.717V
[Falling Waveform]
| gpio_33v_8m_fast Falling-High S28FDSIO_IBIS
| Wed Sep  2 14:14:57 2020
R_fixture = 50.00
V_fixture = 3.3000
V_fixture_min = 2.9700
V_fixture_max = 3.6300
C_fixture = 0.00pF
| Time   V(typ)   V(min)   V(max)
0s        3.3V       2.97V      3.63V
680ps     3.3V       2.97V      3.494V
1.01ns    3.228V     2.97V      1.973V
1.17ns    3.076V     2.97V      1.625V
1.54ns    2.368V     2.971V     1.461V
1.95ns    2.139V     2.862V     1.421V
2.76ns    2.047V     2.476V     1.387V
5.36ns    1.977V     2.353V     1.345V
40ns      1.85V      2.236V     1.264V
40ns      1.543V     2.102V     1.114V
[Falling Waveform]
| gpio_33v_8m_fast Falling-Low S28FDSIO_IBIS
| Wed Sep  2 14:14:57 2020
R_fixture = 50.00
V_fixture = 0.0000
C_fixture = 0.00pF
| Time   V(typ)   V(min)   V(max)
0s        1.958V     1.058V     2.717V
550ps     1.971V     1.058V     2.674V
630ps     1.968V     1.058V     2.165V
780ps     1.954V     1.066V     234.6mV
950ps     1.289V     1.068V     8.23mV
1.19ns    122mV      1.067V     1.79mV
1.45ns    4.5mV      922.5mV    645uV
1.84ns    900uV      157.3mV    200uV
2.35ns    298uV      3.188mV    110uV
40ns      0V         0V         0V
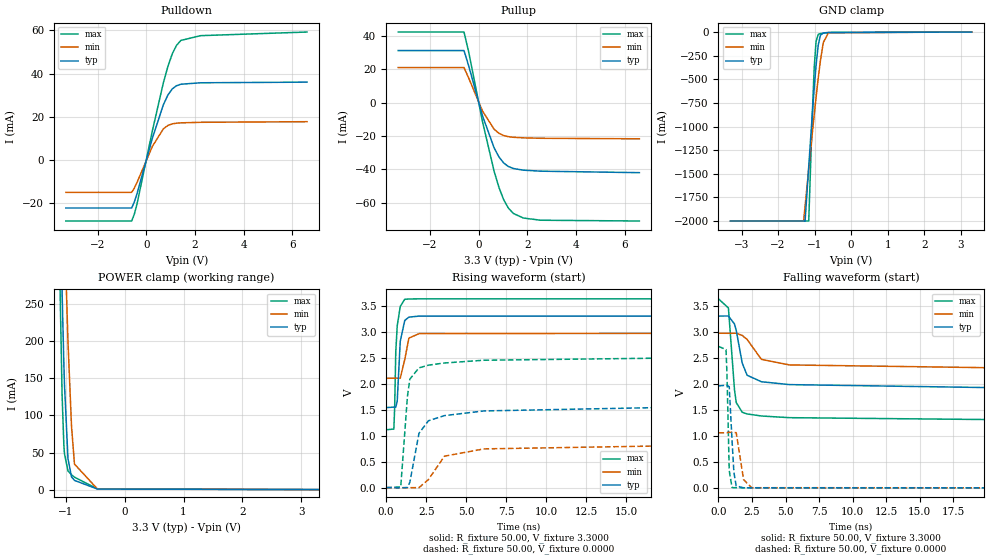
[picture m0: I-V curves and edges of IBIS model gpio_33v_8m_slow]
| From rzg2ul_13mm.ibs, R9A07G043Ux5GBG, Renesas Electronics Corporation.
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[Model]   gpio_33v_8m_slow
Model_type   I/O
Polarity   Non-Inverting
Enable   Active-Low
Vinl  =   0.8000V
Vinh  =   2.0000V
Vmeas =   1.6500V
Cref  =   15.00pF
| variable   typ   min   max
C_comp   2.126e-12  1.947e-12  2.166e-12
[Model Spec]
| Subparameter   typ   min   max
| Thresholds
Vinh   2.0000   NA   NA
Vinl   0.8000   NA   NA
| Timing Thresholds
Vmeas   1.6500   1.4850   1.8150
| variable   typ   min   max
[Temperature Range]   25.000   125.000   -40.000
| variable   typ   min   max
[Voltage Range]   3.300V   2.970V   3.630V
| variable   typ   min   max
[Pullup Reference]   3.300V   2.970V   3.630V
| variable   typ   min   max
[Pulldown Reference]   0.000V   0.000V   0.000V
| variable   typ   min   max
[POWER Clamp Reference] 3.300V   2.970V   3.630V
| variable   typ   min   max
[GND Clamp Reference]   0.000V   0.000V   0.000V
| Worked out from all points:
|   slope of the pulldown table from 0 to 0.495 V, typ, clamps not added: 26.1 ohm
|   slope of the pullup table from 0 to 0.495 V, typ, clamps not added: 22.3 ohm
|   GND clamp passes 1 mA (typ) near -0.48 V on its own axis
|   POWER clamp passes 1 mA (typ) near -0.48 V on its own axis
|   rising waveform, R_fixture 50.00, V_fixture 3.3000: 20-80 % time 203ps typ, 234ps min, 158ps max; typ from 1.54 V to 3.3 V
|   rising waveform, R_fixture 50.00, V_fixture 0.0000: 20-80 % time 11.7ns typ, 14.3ns min, 489ps max; typ from 0 V to 1.96 V
|   falling waveform, R_fixture 50.00, V_fixture 3.3000: 20-80 % time 20.7ns typ, 17.9ns min, 479ps max; typ from 3.3 V to 1.54 V
|   falling waveform, R_fixture 50.00, V_fixture 0.0000: 20-80 % time 203ps typ, 307ps min, 137ps max; typ from 1.96 V to 0 V
[Pulldown]
| gpio_33v_8m_slow Pulldown S28FDSIO_IBIS
| Wed Sep  2 14:14:57 2020
| voltage   I(typ)   I(min)   I(max)
-3.3V     -22.36mA   -15.1mA    -28.39mA
-600mV    -22.36mA   -15.1mA    -28.39mA
-490mV    -19.58mA   -13.14mA   -25.22mA
-380mV    -15.74mA   -10.53mA   -20.5mA
250mV     9.951mA    6.188mA    13.38mA
700mV     25.45mA    14.31mA    35.6mA
890mV     30.07mA    15.94mA    43.36mA
1.07V     32.91mA    16.66mA    49.19mA
1.24V     34.33mA    16.96mA    53.02mA
1.42V     35.03mA    17.12mA    55.34mA
2.23V     35.7mA     17.38mA    57.55mA
6.6V      36mA       17.66mA    59.23mA
[Pullup]
| gpio_33v_8m_slow Pullup S28FDSIO_IBIS
| Wed Sep  2 14:14:57 2020
| voltage   I(typ)   I(min)   I(max)
-3.3V     31.13mA    20.95mA    42.21mA
-600mV    31.13mA    20.95mA    42.21mA
-410mV    22.13mA    14.78mA    30.48mA
160mV     -7.943mA   -5.066mA   -11.41mA
640mV     -27.21mA   -16.02mA   -41.3mA
840mV     -32.65mA   -18.46mA   -51mA
1.03V     -36.17mA   -19.76mA   -58.16mA
1.22V     -38.26mA   -20.42mA   -63.13mA
1.43V     -39.48mA   -20.79mA   -66.42mA
1.84V     -40.48mA   -21.13mA   -69.13mA
2.55V     -41.08mA   -21.39mA   -70.44mA
6.6V      -41.97mA   -21.7mA    -70.91mA
[GND Clamp]
| gpio_33v_8m_slow GNDClamp S28FDSIO_IBIS
| Wed Sep  2 14:14:57 2020
| voltage   I(typ)   I(min)   I(max)
-3.3V     -2A        -2A        -2A
-1.3V     -2A        -2A        -2A
-1.26V    -2A        -1.843A    -2A
-1.16V    -1.422A    -1.447A    -2A
-1.06V    -856.1mA   -1.062A    -851.2mA
-1.01V    -593.2mA   -874.6mA   -376.4mA
-960mV    -356.1mA   -693.5mA   -100.4mA
-900mV    -137mA     -487.4mA   -24.05mA
-840mV    -34mA      -301mA     -16.13mA
-760mV    -9.995mA   -109.9mA   -12.09mA
-620mV    -4.238mA   -6.791mA   -5.995mA
3.3V      0A         0A         0A
[POWER Clamp]
| gpio_33v_8m_slow PWRClamp S28FDSIO_IBIS
| Wed Sep  2 14:14:57 2020
| voltage   I(typ)   I(min)   I(max)
-3.3V     2A         2A         2A
-1.12V    504.1mA    667.9mA    429.5mA
-1.1V     420.1mA    602.4mA    307.9mA
-1.09V    379.7mA    570.1mA    254.2mA
-1.06V    266.9mA    475.7mA    128.4mA
-1.03V    170.6mA    385.5mA    60.65mA
-1.02V    143.4mA    356.6mA    48.83mA
-960mV    41.76mA    199.8mA    25.26mA
-900mV    17.19mA    85.7mA     20.05mA
-850mV    12.44mA    34.48mA    16.76mA
-460mV    730.6uA    884.4uA    935.7uA
3.3V      0A         0A         0A
[Ramp]
dV/dt_r   1.175/11.596n   0.635/14.180n   1.630/488.874p
dV/dt_f   1.030/10.553n   0.521/17.687n   1.510/476.300p
R_load = 50.00ohm
[Rising Waveform]
| gpio_33v_8m_slow Rising-High S28FDSIO_IBIS
| Wed Sep  2 14:14:57 2020
R_fixture = 50.00
V_fixture = 3.3000
V_fixture_min = 2.9700
V_fixture_max = 3.6300
C_fixture = 0.00pF
| Time   V(typ)   V(min)   V(max)
0s        1.54V      2.102V     1.114V
480ps     1.548V     2.105V     1.126V
530ps     1.548V     2.106V     1.531V
600ps     1.548V     2.106V     2.608V
690ps     1.658V     2.105V     3.109V
880ps     2.814V     2.105V     3.484V
1.16ns    3.214V     2.462V     3.622V
1.42ns    3.279V     2.876V     3.628V
2.07ns    3.299V     2.963V     3.63V
40ns      3.3V       2.97V      3.63V
[Rising Waveform]
| gpio_33v_8m_slow Rising-Low S28FDSIO_IBIS
| Wed Sep  2 14:14:57 2020
R_fixture = 50.00
V_fixture = 0.0000
C_fixture = 0.00pF
| Time   V(typ)   V(min)   V(max)
0s        0V         0V         0V
910ps     -4.1mV     100uV      14.3mV
1.33ns    2.6mV      -3.6mV     1.76V
1.48ns    103.6mV    -1.4mV     2.088V
2.05ns    1.045V     200uV      2.303V
2.64ns    1.286V     155.2mV    2.355V
3.64ns    1.385V     605.1mV    2.397V
6.11ns    1.475V     745.2mV    2.45V
40ns      1.676V     917.9mV    2.573V
40ns      1.958V     1.058V     2.717V
[Falling Waveform]
| gpio_33v_8m_slow Falling-High S28FDSIO_IBIS
| Wed Sep  2 14:14:57 2020
R_fixture = 50.00
V_fixture = 3.3000
V_fixture_min = 2.9700
V_fixture_max = 3.6300
C_fixture = 0.00pF
| Time   V(typ)   V(min)   V(max)
0s        3.3V       2.97V      3.63V
740ps     3.301V     2.969V     3.455V
1.19ns    3.148V     2.97V      1.89V
1.32ns    3.027V     2.971V     1.639V
1.77ns    2.395V     2.927V     1.452V
2.13ns    2.163V     2.851V     1.42V
3.2ns     2.038V     2.467V     1.38V
5.29ns    1.983V     2.361V     1.348V
40ns      1.849V     2.236V     1.263V
40ns      1.54V      2.102V     1.114V
[Falling Waveform]
| gpio_33v_8m_slow Falling-Low S28FDSIO_IBIS
| Wed Sep  2 14:14:57 2020
R_fixture = 50.00
V_fixture = 0.0000
C_fixture = 0.00pF
| Time   V(typ)   V(min)   V(max)
0s        1.958V     1.058V     2.717V
560ps     1.97V      1.058V     2.656V
630ps     1.969V     1.058V     2.203V
800ps     1.942V     1.066V     327.5mV
1.01ns    906.6mV    1.068V     6.895mV
1.15ns    293mV      1.065V     2.645mV
1.32ns    36.84mV    1.06V      1.122mV
1.87ns    964uV      156.7mV    200uV
2.47ns    244uV      2.758mV    100uV
40ns      0V         0V         0V
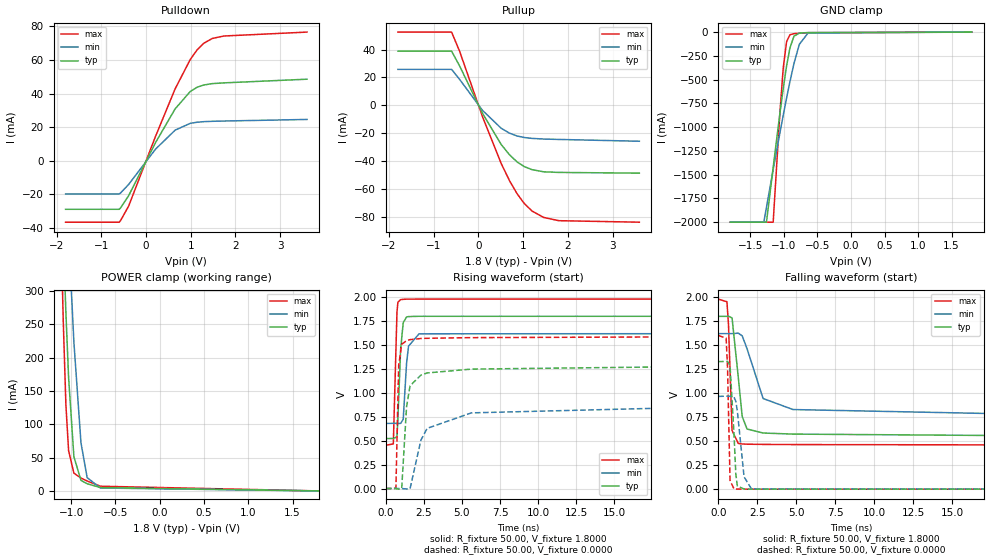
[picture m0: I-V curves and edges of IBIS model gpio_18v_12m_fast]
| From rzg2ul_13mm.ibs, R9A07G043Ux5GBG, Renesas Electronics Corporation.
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[Model]   gpio_18v_12m_fast
Model_type   I/O
Polarity   Non-Inverting
Enable   Active-Low
Vinl  =   0.6300V
Vinh  =   1.1700V
Vmeas =   0.9000V
Cref  =   10.00pF
| variable   typ   min   max
C_comp   2.470pF   2.346pF   2.470pF
[Model Spec]
| Subparameter   typ   min   max
| Thresholds
Vinh   1.1700   1.0530   1.2870
Vinl   0.6300   0.5670   0.6930
| Timing Thresholds
Vmeas   0.9000   0.8100   0.9900
| variable   typ   min   max
[Temperature Range]   25.000   125.000   -40.000
| variable   typ   min   max
[Voltage Range]   1.800V   1.620V   1.980V
| variable   typ   min   max
[Pullup Reference]   1.800V   1.620V   1.980V
| variable   typ   min   max
[Pulldown Reference]   0.000V   0.000V   0.000V
| variable   typ   min   max
[POWER Clamp Reference] 1.800V   1.620V   1.980V
| variable   typ   min   max
[GND Clamp Reference]   0.000V   0.000V   0.000V
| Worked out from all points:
|   slope of the pulldown table from 0 to 0.27 V, typ, clamps not added: 19.6 ohm
|   slope of the pullup table from 0 to 0.27 V, typ, clamps not added: 16.7 ohm
|   GND clamp passes 1 mA (typ) near -0.48 V on its own axis
|   POWER clamp passes 1 mA (typ) near -0.48 V on its own axis
|   rising waveform, R_fixture 50.00, V_fixture 1.8000: 20-80 % time 214ps typ, 231ps min, 146ps max; typ from 0.522 V to 1.8 V
|   rising waveform, R_fixture 50.00, V_fixture 0.0000: 20-80 % time 400ps typ, 2.92ns min, 122ps max; typ from 0 V to 1.33 V
|   falling waveform, R_fixture 50.00, V_fixture 1.8000: 20-80 % time 403ps typ, 1.71ns min, 167ps max; typ from 1.8 V to 0.522 V
|   falling waveform, R_fixture 50.00, V_fixture 0.0000: 20-80 % time 210ps typ, 340ps min, 121ps max; typ from 1.33 V to 0 V
[Pulldown]
| gpio_18v_12m_fast Pulldown S28FDSIO_IBIS
| Fri Apr  9 09:21:15 2021
| voltage   I(typ)   I(min)   I(max)
-1.8V     -28.82mA   -19.69mA   -36.5mA
-600mV    -28.82mA   -19.69mA   -36.5mA
-570mV    -27.95mA   -19.1mA    -35.52mA
-390mV    -20.73mA   -14.05mA   -26.92mA
210mV     10.78mA    6.906mA    14.45mA
650mV     30.92mA    18.27mA    42.84mA
990mV     41.31mA    22.33mA    60.37mA
1.14V     43.77mA    22.97mA    65.97mA
1.29V     45.14mA    23.31mA    69.94mA
1.48V     45.95mA    23.53mA    72.8mA
1.74V     46.39mA    23.69mA    74.28mA
3.6V      48.58mA    24.63mA    76.61mA
[Pullup]
| gpio_18v_12m_fast Pullup S28FDSIO_IBIS
| Fri Apr  9 09:21:15 2021
| voltage   I(typ)   I(min)   I(max)
-1.8V     38.85mA    25.8mA     52.54mA
-600mV    38.85mA    25.8mA     52.54mA
-420mV    28.23mA    18.61mA    38.74mA
90mV      -5.638mA   -3.557mA   -8.016mA
510mV     -28.11mA   -16.47mA   -41.76mA
700mV     -35.64mA   -20.03mA   -54.3mA
870mV     -40.72mA   -22.03mA   -63.64mA
1.03V     -44mA      -23.1mA    -70.55mA
1.2V      -46.14mA   -23.72mA   -75.83mA
1.46V     -47.69mA   -24.18mA   -80.42mA
1.8V      -48.13mA   -24.47mA   -82.75mA
3.6V      -48.66mA   -25.76mA   -83.83mA
[GND Clamp]
| gpio_18v_12m_fast GNDClamp S28FDSIO_IBIS
| Fri Apr  9 09:21:15 2021
| voltage   I(typ)   I(min)   I(max)
-1.8V     -2A        -2A        -2A
-1.3V     -2A        -2A        -2A
-1.26V    -2A        -1.843A    -2A
-1.16V    -1.422A    -1.447A    -2A
-1.06V    -856.1mA   -1.062A    -851.2mA
-1.01V    -593.2mA   -874.6mA   -376.3mA
-960mV    -356.1mA   -693.5mA   -100.4mA
-910mV    -166.4mA   -520.6mA   -27.8mA
-850mV    -43.16mA   -330.2mA   -16.77mA
-770mV    -10.89mA   -128.7mA   -12.54mA
-640mV    -4.841mA   -9.855mA   -6.797mA
1.8V      0A         0A         0A
[POWER Clamp]
| gpio_18v_12m_fast PWRClamp S28FDSIO_IBIS
| Fri Apr  9 09:21:15 2021
| voltage   I(typ)   I(min)   I(max)
-1.8V     2A         2A         2A
-1.12V    504.1mA    667.8mA    429.5mA
-1.11V    461.6mA    634.9mA    366.6mA
-1.1V     420.1mA    602.4mA    307.9mA
-1.09V    379.7mA    570.1mA    254.2mA
-1.06V    266.8mA    475.7mA    128.4mA
-1.03V    170.6mA    385.5mA    60.63mA
-970mV    51.47mA    223.5mA    26.69mA
-890mV    15.8mA     72.19mA    19.35mA
-820mV    10.79mA    19.94mA    14.9mA
-670mV    5.013mA    4.364mA    7.038mA
1.8V      0A         0A         0A
[Ramp]
dV/dt_r   0.797/399.522p  0.580/2.911n   0.961/121.879p
dV/dt_f   0.767/401.914p  0.564/1.704n   0.916/166.819p
R_load = 50.00ohm
[Rising Waveform]
| gpio_18v_12m_fast Rising-High S28FDSIO_IBIS
| Fri Apr  9 09:21:15 2021
R_fixture = 50.00
V_fixture = 1.8000
V_fixture_min = 1.6200
V_fixture_max = 1.9800
C_fixture = 0.00pF
| Time   V(typ)   V(min)   V(max)
0s        522.5mV    680.3mV    452.6mV
490ps     522.9mV    681.6mV    466.3mV
730ps     540.4mV    680.9mV    1.845V
790ps     731mV      680.3mV    1.946V
970ps     1.454V     680.8mV    1.974V
1.14ns    1.733V     722.8mV    1.977V
1.36ns    1.793V     1.31V      1.979V
1.49ns    1.797V     1.488V     1.979V
2.18ns    1.8V       1.617V     1.98V
50ns      1.8V       1.62V      1.98V
[Rising Waveform]
| gpio_18v_12m_fast Rising-Low S28FDSIO_IBIS
| Fri Apr  9 09:21:15 2021
R_fixture = 50.00
V_fixture = 0.0000
C_fixture = 0.00pF
| Time   V(typ)   V(min)   V(max)
0s        0V         0V         0V
660ps     100uV      200uV      3mV
840ps     -6.6mV     0V         1.284V
1.04ns    2.6mV      100uV      1.508V
1.36ns    855.2mV    -4.7mV     1.545V
1.59ns    1.074V     -1.1mV     1.556V
2.3ns     1.185V     505.1mV    1.568V
2.71ns    1.208V     628.8mV    1.57V
5.62ns    1.248V     790.7mV    1.577V
50ns      1.329V     965.9mV    1.602V
[Falling Waveform]
| gpio_18v_12m_fast Falling-High S28FDSIO_IBIS
| Fri Apr  9 09:21:15 2021
R_fixture = 50.00
V_fixture = 1.8000
V_fixture_min = 1.6200
V_fixture_max = 1.9800
C_fixture = 0.00pF
| Time   V(typ)   V(min)   V(max)
0s        1.8V       1.62V      1.98V
560ps     1.8V       1.62V      1.952V
660ps     1.802V     1.62V      1.718V
890ps     1.783V     1.62V      610.9mV
1.29ns    1.163V     1.625V     475.9mV
1.54ns    757.8mV    1.597V     470.8mV
1.85ns    626.7mV    1.464V     468.5mV
2.88ns    584.8mV    944.3mV    466.1mV
4.8ns     573.5mV    829.3mV    464.6mV
50ns      522.5mV    680.3mV    452.6mV
[Falling Waveform]
| gpio_18v_12m_fast Falling-Low S28FDSIO_IBIS
| Fri Apr  9 09:21:15 2021
R_fixture = 50.00
V_fixture = 0.0000
C_fixture = 0.00pF
| Time   V(typ)   V(min)   V(max)
0s        1.329V     965.9mV    1.602V
510ps     1.33V      968.9mV    1.572V
600ps     1.331V     968.7mV    1.263V
760ps     1.288V     966.8mV    89.92mV
1.01ns    589.4mV    962.5mV    4.437mV
1.13ns    160.1mV    913.2mV    2.02mV
1.23ns    32.79mV    812.6mV    1.21mV
1.66ns    1.457mV    129mV      600uV
2.13ns    426uV      3.745mV    201uV
50ns      0V         0V         0V
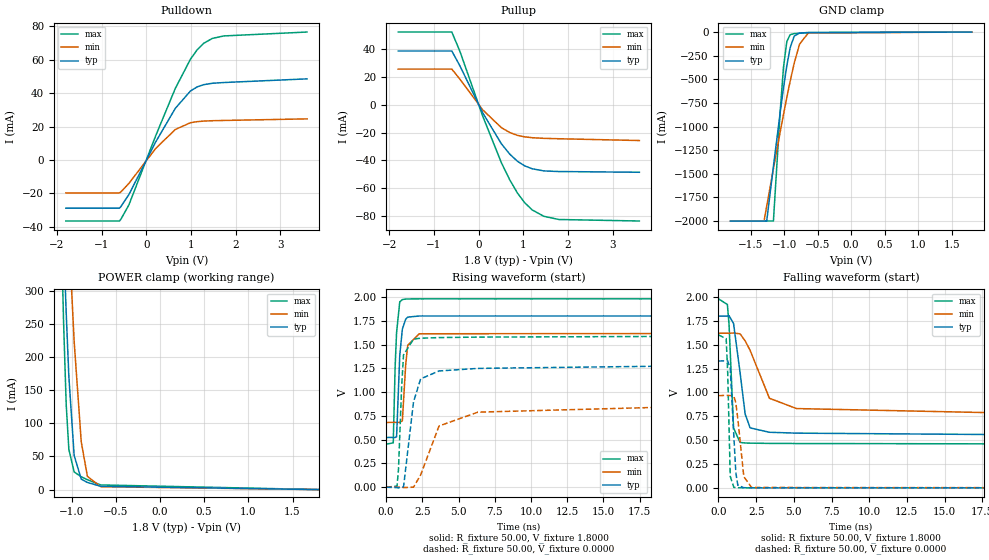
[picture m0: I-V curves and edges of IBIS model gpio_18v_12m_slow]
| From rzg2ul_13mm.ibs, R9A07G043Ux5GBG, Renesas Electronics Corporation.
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[Model]   gpio_18v_12m_slow
Model_type   I/O
Polarity   Non-Inverting
Enable   Active-Low
Vinl  =   0.6300V
Vinh  =   1.1700V
Vmeas =   0.9000V
Cref  =   10.00pF
| variable   typ   min   max
C_comp   2.470pF   2.346pF   2.470pF
[Model Spec]
| Subparameter   typ   min   max
| Thresholds
Vinh   1.1700   1.0530   1.2870
Vinl   0.6300   0.5670   0.6930
| Timing Thresholds
Vmeas   0.9000   0.8100   0.9900
| variable   typ   min   max
[Temperature Range]   25.000   125.000   -40.000
| variable   typ   min   max
[Voltage Range]   1.800V   1.620V   1.980V
| variable   typ   min   max
[Pullup Reference]   1.800V   1.620V   1.980V
| variable   typ   min   max
[Pulldown Reference]   0.000V   0.000V   0.000V
| variable   typ   min   max
[POWER Clamp Reference] 1.800V   1.620V   1.980V
| variable   typ   min   max
[GND Clamp Reference]   0.000V   0.000V   0.000V
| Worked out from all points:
|   slope of the pulldown table from 0 to 0.27 V, typ, clamps not added: 19.6 ohm
|   slope of the pullup table from 0 to 0.27 V, typ, clamps not added: 16.7 ohm
|   GND clamp passes 1 mA (typ) near -0.48 V on its own axis
|   POWER clamp passes 1 mA (typ) near -0.48 V on its own axis
|   rising waveform, R_fixture 50.00, V_fixture 1.8000: 20-80 % time 214ps typ, 229ps min, 191ps max; typ from 0.522 V to 1.8 V
|   rising waveform, R_fixture 50.00, V_fixture 0.0000: 20-80 % time 630ps typ, 3.15ns min, 254ps max; typ from 0 V to 1.33 V
|   falling waveform, R_fixture 50.00, V_fixture 1.8000: 20-80 % time 566ps typ, 1.96ns min, 230ps max; typ from 1.8 V to 0.522 V
|   falling waveform, R_fixture 50.00, V_fixture 0.0000: 20-80 % time 235ps typ, 345ps min, 144ps max; typ from 1.33 V to 0 V
[Pulldown]
| gpio_18v_12m_slow Pulldown S28FDSIO_IBIS
| Fri Apr  9 09:21:15 2021
| voltage   I(typ)   I(min)   I(max)
-1.8V     -28.82mA   -19.69mA   -36.5mA
-600mV    -28.82mA   -19.69mA   -36.5mA
-570mV    -27.95mA   -19.1mA    -35.52mA
-390mV    -20.73mA   -14.05mA   -26.92mA
210mV     10.78mA    6.906mA    14.45mA
650mV     30.92mA    18.27mA    42.84mA
990mV     41.31mA    22.33mA    60.37mA
1.14V     43.77mA    22.97mA    65.97mA
1.29V     45.14mA    23.31mA    69.94mA
1.48V     45.95mA    23.53mA    72.8mA
1.74V     46.39mA    23.69mA    74.28mA
3.6V      48.58mA    24.63mA    76.61mA
[Pullup]
| gpio_18v_12m_slow Pullup S28FDSIO_IBIS
| Fri Apr  9 09:21:15 2021
| voltage   I(typ)   I(min)   I(max)
-1.8V     38.85mA    25.8mA     52.54mA
-600mV    38.85mA    25.8mA     52.54mA
-420mV    28.23mA    18.61mA    38.74mA
90mV      -5.638mA   -3.557mA   -8.016mA
510mV     -28.11mA   -16.47mA   -41.76mA
700mV     -35.64mA   -20.03mA   -54.3mA
870mV     -40.72mA   -22.03mA   -63.64mA
1.03V     -44mA      -23.1mA    -70.55mA
1.2V      -46.14mA   -23.72mA   -75.83mA
1.46V     -47.69mA   -24.18mA   -80.42mA
1.8V      -48.13mA   -24.47mA   -82.75mA
3.6V      -48.66mA   -25.76mA   -83.84mA
[GND Clamp]
| gpio_18v_12m_slow GNDClamp S28FDSIO_IBIS
| Fri Apr  9 09:21:15 2021
| voltage   I(typ)   I(min)   I(max)
-1.8V     -2A        -2A        -2A
-1.3V     -2A        -2A        -2A
-1.26V    -2A        -1.843A    -2A
-1.16V    -1.422A    -1.447A    -2A
-1.06V    -856.1mA   -1.062A    -851.2mA
-1.01V    -593.2mA   -874.6mA   -376.3mA
-960mV    -356.1mA   -693.5mA   -100.4mA
-910mV    -166.4mA   -520.6mA   -27.8mA
-850mV    -43.16mA   -330.2mA   -16.77mA
-770mV    -10.89mA   -128.7mA   -12.54mA
-640mV    -4.841mA   -9.855mA   -6.797mA
1.8V      0A         0A         0A
[POWER Clamp]
| gpio_18v_12m_slow PWRClamp S28FDSIO_IBIS
| Fri Apr  9 09:21:15 2021
| voltage   I(typ)   I(min)   I(max)
-1.8V     2A         2A         2A
-1.12V    504.1mA    667.8mA    429.5mA
-1.11V    461.6mA    634.9mA    366.6mA
-1.1V     420.1mA    602.4mA    307.9mA
-1.09V    379.7mA    570.1mA    254.2mA
-1.06V    266.8mA    475.7mA    128.4mA
-1.03V    170.6mA    385.5mA    60.63mA
-970mV    51.47mA    223.5mA    26.69mA
-890mV    15.8mA     72.19mA    19.35mA
-820mV    10.79mA    19.94mA    14.9mA
-670mV    5.013mA    4.364mA    7.038mA
1.8V      0A         0A         0A
[Ramp]
dV/dt_r   0.797/628.808p  0.580/3.141n   0.961/253.910p
dV/dt_f   0.767/565.547p  0.564/1.947n   0.916/230.152p
R_load = 50.00ohm
[Rising Waveform]
| gpio_18v_12m_slow Rising-High S28FDSIO_IBIS
| Fri Apr  9 09:21:15 2021
R_fixture = 50.00
V_fixture = 1.8000
V_fixture_min = 1.6200
V_fixture_max = 1.9800
C_fixture = 0.00pF
| Time   V(typ)   V(min)   V(max)
0s        522.5mV    680.3mV    452.6mV
490ps     522.9mV    681.6mV    466.3mV
620ps     522.7mV    681.8mV    1.268V
720ps     530mV      681mV      1.627V
940ps     1.387V     680.8mV    1.949V
1.12ns    1.663V     698.9mV    1.973V
1.35ns    1.767V     1.289V     1.978V
1.49ns    1.788V     1.492V     1.979V
2.29ns    1.8V       1.613V     1.98V
50ns      1.8V       1.62V      1.98V
[Rising Waveform]
| gpio_18v_12m_slow Rising-Low S28FDSIO_IBIS
| Fri Apr  9 09:21:15 2021
R_fixture = 50.00
V_fixture = 0.0000
C_fixture = 0.00pF
| Time   V(typ)   V(min)   V(max)
0s        0V         0V         0V
750ps     -4.9mV     100uV      11.5mV
850ps     -6.9mV     0V         183.1mV
1.07ns    -1.5mV     -300uV     1.059V
1.2ns     3.4mV      -4.2mV     1.391V
1.89ns    896.8mV    100uV      1.557V
2.38ns    1.139V     128.2mV    1.566V
3.65ns    1.222V     643.2mV    1.573V
6.34ns    1.249V     789.1mV    1.578V
50ns      1.329V     965.9mV    1.602V
[Falling Waveform]
| gpio_18v_12m_slow Falling-High S28FDSIO_IBIS
| Fri Apr  9 09:21:15 2021
R_fixture = 50.00
V_fixture = 1.8000
V_fixture_min = 1.6200
V_fixture_max = 1.9800
C_fixture = 0.00pF
| Time   V(typ)   V(min)   V(max)
0s        1.8V       1.62V      1.98V
590ps     1.8V       1.62V      1.921V
700ps     1.804V     1.62V      1.711V
1ns       1.722V     1.622V     627.8mV
1.43ns    1.21V      1.614V     475.8mV
1.77ns    772.3mV    1.54V      469.8mV
2.1ns     628.1mV    1.44V      468.3mV
3.38ns    582.2mV    938.5mV    465.7mV
5.18ns    573.1mV    830.6mV    464.5mV
50ns      522.5mV    680.3mV    452.6mV
[Falling Waveform]
| gpio_18v_12m_slow Falling-Low S28FDSIO_IBIS
| Fri Apr  9 09:21:15 2021
R_fixture = 50.00
V_fixture = 0.0000
C_fixture = 0.00pF
| Time   V(typ)   V(min)   V(max)
0s        1.329V     965.9mV    1.602V
510ps     1.33V      968.9mV    1.563V
610ps     1.331V     968.6mV    1.213V
780ps     1.253V     966.3mV    121.2mV
1.02ns    539.8mV    959mV      4.91mV
1.15ns    162.1mV    890.8mV    2.255mV
1.28ns    27.32mV    727.2mV    1.185mV
1.68ns    1.64mV     116.3mV    600uV
2.2ns     409uV      3.55mV     199uV
50ns      0V         0V         0V
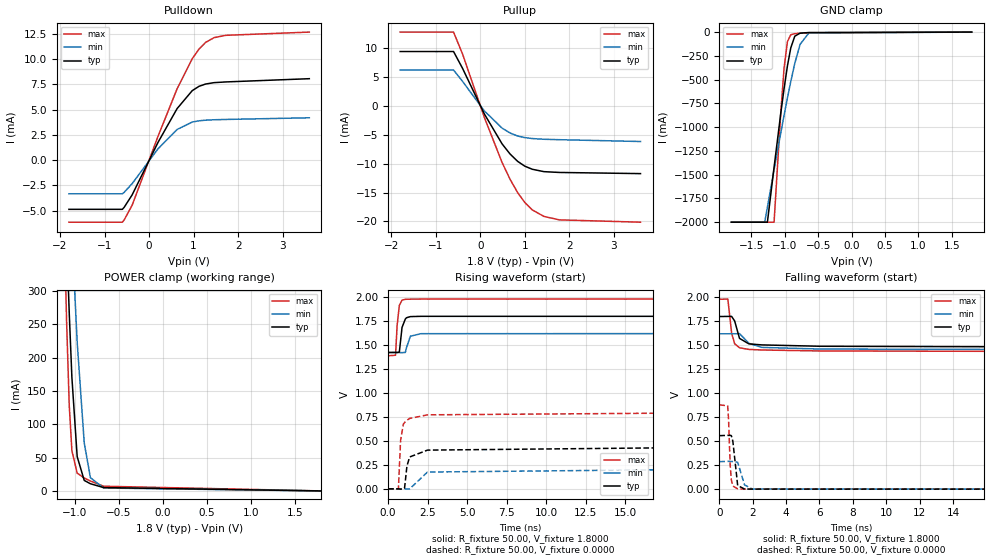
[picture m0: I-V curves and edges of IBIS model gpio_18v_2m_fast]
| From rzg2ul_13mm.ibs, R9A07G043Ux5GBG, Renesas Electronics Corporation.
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[Model]   gpio_18v_2m_fast
Model_type   I/O
Polarity   Non-Inverting
Enable   Active-Low
Vinl  =   0.6300V
Vinh  =   1.1700V
Vmeas =   0.9000V
Cref  =   10.00pF
| variable   typ   min   max
C_comp   2.470pF   2.346pF   2.470pF
[Model Spec]
| Subparameter   typ   min   max
| Thresholds
Vinh   1.1700   1.0530   1.2870
Vinl   0.6300   0.5670   0.6930
| Timing Thresholds
Vmeas   0.9000   0.8100   0.9900
| variable   typ   min   max
[Temperature Range]   25.000   125.000   -40.000
| variable   typ   min   max
[Voltage Range]   1.800V   1.620V   1.980V
| variable   typ   min   max
[Pullup Reference]   1.800V   1.620V   1.980V
| variable   typ   min   max
[Pulldown Reference]   0.000V   0.000V   0.000V
| variable   typ   min   max
[POWER Clamp Reference] 1.800V   1.620V   1.980V
| variable   typ   min   max
[GND Clamp Reference]   0.000V   0.000V   0.000V
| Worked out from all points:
|   slope of the pulldown table from 0 to 0.27 V, typ, clamps not added: 116 ohm
|   slope of the pullup table from 0 to 0.27 V, typ, clamps not added: 69.2 ohm
|   GND clamp passes 1 mA (typ) near -0.48 V on its own axis
|   POWER clamp passes 1 mA (typ) near -0.48 V on its own axis
|   rising waveform, R_fixture 50.00, V_fixture 1.8000: 20-80 % time 199ps typ, 197ps min, 160ps max; typ from 1.42 V to 1.8 V
|   rising waveform, R_fixture 50.00, V_fixture 0.0000: 20-80 % time 7.6ns typ, 9.96ns min, 418ps max; typ from 0 V to 0.558 V
|   falling waveform, R_fixture 50.00, V_fixture 1.8000: 20-80 % time 2.52ns typ, 4.93ns min, 356ps max; typ from 1.8 V to 1.42 V
|   falling waveform, R_fixture 50.00, V_fixture 0.0000: 20-80 % time 159ps typ, 251ps min, 119ps max; typ from 0.558 V to 0 V
[Pulldown]
| gpio_18v_2m_fast Pulldown S28FDSIO_IBIS
| Fri Apr  9 09:21:15 2021
| voltage   I(typ)   I(min)   I(max)
-1.8V     -4.861mA   -3.322mA   -6.131mA
-600mV    -4.861mA   -3.322mA   -6.131mA
-560mV    -4.667mA   -3.186mA   -5.915mA
-380mV    -3.434mA   -2.322mA   -4.456mA
200mV     1.744mA    1.116mA    2.336mA
630mV     5.091mA    3.031mA    7.047mA
970mV     6.865mA    3.763mA    10.02mA
1.12V     7.286mA    3.884mA    10.96mA
1.27V     7.519mA    3.947mA    11.63mA
1.46V     7.655mA    3.988mA    12.1mA
1.72V     7.725mA    4.018mA    12.33mA
3.6V      8.046mA    4.184mA    12.65mA
[Pullup]
| gpio_18v_2m_fast Pullup S28FDSIO_IBIS
| Fri Apr  9 09:21:15 2021
| voltage   I(typ)   I(min)   I(max)
-1.8V     9.413mA    6.213mA    12.78mA
-600mV    9.413mA    6.213mA    12.78mA
-400mV    6.535mA    4.274mA    9.025mA
90mV      -1.367mA   -856.5uA   -1.955mA
490mV     -6.571mA   -3.844mA   -9.795mA
670mV     -8.332mA   -4.692mA   -12.71mA
840mV     -9.599mA   -5.209mA   -15.01mA
1V        -10.43mA   -5.49mA    -16.71mA
1.17V     -10.97mA   -5.653mA   -18.01mA
1.43V     -11.38mA   -5.774mA   -19.13mA
1.78V     -11.52mA   -5.849mA   -19.73mA
3.6V      -11.72mA   -6.163mA   -20.13mA
[GND Clamp]
| gpio_18v_2m_fast GNDClamp S28FDSIO_IBIS
| Fri Apr  9 09:21:15 2021
| voltage   I(typ)   I(min)   I(max)
-1.8V     -2A        -2A        -2A
-1.3V     -2A        -2A        -2A
-1.26V    -2A        -1.843A    -2A
-1.16V    -1.422A    -1.447A    -2A
-1.06V    -856.1mA   -1.062A    -851.2mA
-1.01V    -593.2mA   -874.6mA   -376.3mA
-960mV    -356.1mA   -693.5mA   -100.4mA
-910mV    -166.4mA   -520.6mA   -27.8mA
-850mV    -43.16mA   -330.2mA   -16.77mA
-770mV    -10.89mA   -128.7mA   -12.54mA
-640mV    -4.841mA   -9.855mA   -6.797mA
1.8V      0A         0A         0A
[POWER Clamp]
| gpio_18v_2m_fast PWRClamp S28FDSIO_IBIS
| Fri Apr  9 09:21:15 2021
| voltage   I(typ)   I(min)   I(max)
-1.8V     2A         2A         2A
-1.12V    504.1mA    667.8mA    429.5mA
-1.11V    461.6mA    634.9mA    366.6mA
-1.1V     420.1mA    602.4mA    307.9mA
-1.09V    379.7mA    570.1mA    254.2mA
-1.06V    266.8mA    475.7mA    128.4mA
-1.03V    170.6mA    385.5mA    60.63mA
-970mV    51.47mA    223.5mA    26.69mA
-890mV    15.8mA     72.19mA    19.35mA
-820mV    10.79mA    19.94mA    14.9mA
-670mV    5.013mA    4.364mA    7.038mA
1.8V      0A         0A         0A
[Ramp]
dV/dt_r   0.335/7.564n   0.172/9.830n   0.528/418.177p
dV/dt_f   0.227/2.517n   0.119/4.838n   0.355/356.255p
R_load = 50.00ohm
[Rising Waveform]
| gpio_18v_2m_fast Rising-High S28FDSIO_IBIS
| Fri Apr  9 09:21:15 2021
R_fixture = 50.00
V_fixture = 1.8000
V_fixture_min = 1.6200
V_fixture_max = 1.9800
C_fixture = 0.00pF
| Time   V(typ)   V(min)   V(max)
0s        1.423V     1.421V     1.388V
470ps     1.424V     1.421V     1.394V
570ps     1.423V     1.422V     1.707V
710ps     1.427V     1.422V     1.914V
880ps     1.684V     1.421V     1.969V
1.09ns    1.772V     1.423V     1.977V
1.16ns    1.785V     1.472V     1.978V
1.41ns    1.797V     1.593V     1.979V
2.09ns    1.8V       1.619V     1.98V
50ns      1.8V       1.62V      1.98V
[Rising Waveform]
| gpio_18v_2m_fast Rising-Low S28FDSIO_IBIS
| Fri Apr  9 09:21:15 2021
R_fixture = 50.00
V_fixture = 0.0000
C_fixture = 0.00pF
| Time   V(typ)   V(min)   V(max)
0s        0V         0V         0V
650ps     200uV      400uV      -100uV
790ps     -3.2mV     100uV      506mV
960ps     -700uV     100uV      673.7mV
1.04ns    8.4mV      100uV      691.8mV
1.19ns    236.7mV    -1.8mV     715.4mV
1.36ns    332.5mV    -700uV     734.5mV
2.49ns    404.2mV    175.3mV    772.3mV
50ns      479.9mV    252mV      826.9mV
50ns      557.8mV    287mV      879.3mV
[Falling Waveform]
| gpio_18v_2m_fast Falling-High S28FDSIO_IBIS
| Fri Apr  9 09:21:15 2021
R_fixture = 50.00
V_fixture = 1.8000
V_fixture_min = 1.6200
V_fixture_max = 1.9800
C_fixture = 0.00pF
| Time   V(typ)   V(min)   V(max)
0s        1.8V       1.62V      1.98V
510ps     1.801V     1.62V      1.982V
740ps     1.801V     1.621V     1.625V
920ps     1.753V     1.62V      1.516V
1.21ns    1.572V     1.622V     1.474V
1.77ns    1.515V     1.521V     1.457V
2.55ns    1.504V     1.478V     1.451V
6ns       1.49V      1.461V     1.441V
50ns      1.469V     1.443V     1.425V
50ns      1.423V     1.421V     1.388V
[Falling Waveform]
| gpio_18v_2m_fast Falling-Low S28FDSIO_IBIS
| Fri Apr  9 09:21:15 2021
R_fixture = 50.00
V_fixture = 0.0000
C_fixture = 0.00pF
| Time   V(typ)   V(min)   V(max)
0s        557.8mV    287mV      879.3mV
500ps     561mV      289.3mV    868.7mV
550ps     560.1mV    289.6mV    739.4mV
650ps     561.2mV    289.3mV    256mV
720ps     558.2mV    288.8mV    95.4mV
810ps     500.6mV    287.5mV    32.6mV
1.1ns     37.47mV    280.4mV    3.6mV
1.51ns    1.798mV    44.98mV    900uV
1.98ns    625uV      1.54mV     400uV
50ns      0V         0V         0V
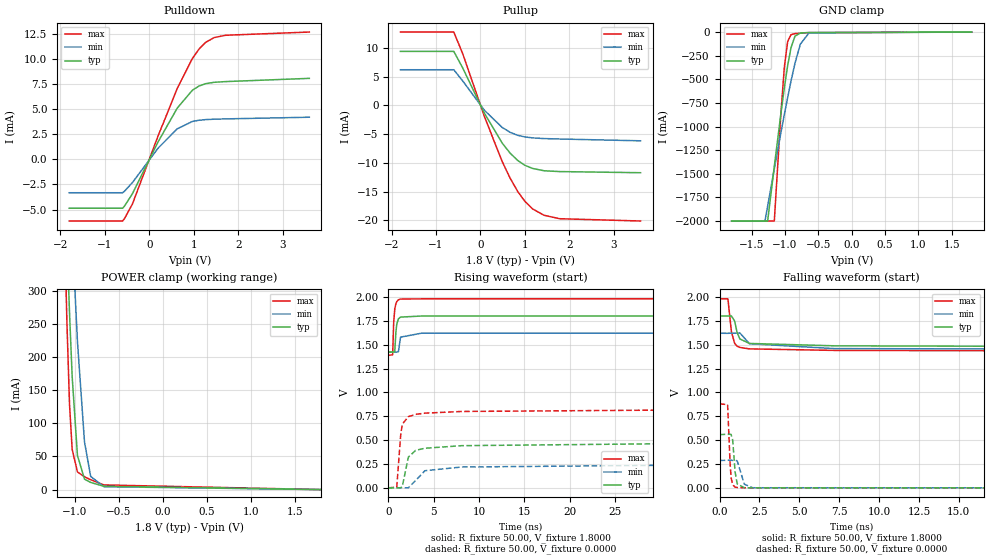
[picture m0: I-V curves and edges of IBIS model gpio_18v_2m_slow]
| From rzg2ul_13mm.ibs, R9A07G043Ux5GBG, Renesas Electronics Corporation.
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[Model]   gpio_18v_2m_slow
Model_type   I/O
Polarity   Non-Inverting
Enable   Active-Low
Vinl  =   0.6300V
Vinh  =   1.1700V
Vmeas =   0.9000V
Cref  =   10.00pF
| variable   typ   min   max
C_comp   2.470pF   2.346pF   2.470pF
[Model Spec]
| Subparameter   typ   min   max
| Thresholds
Vinh   1.1700   1.0530   1.2870
Vinl   0.6300   0.5670   0.6930
| Timing Thresholds
Vmeas   0.9000   0.8100   0.9900
| variable   typ   min   max
[Temperature Range]   25.000   125.000   -40.000
| variable   typ   min   max
[Voltage Range]   1.800V   1.620V   1.980V
| variable   typ   min   max
[Pullup Reference]   1.800V   1.620V   1.980V
| variable   typ   min   max
[Pulldown Reference]   0.000V   0.000V   0.000V
| variable   typ   min   max
[POWER Clamp Reference] 1.800V   1.620V   1.980V
| variable   typ   min   max
[GND Clamp Reference]   0.000V   0.000V   0.000V
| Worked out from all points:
|   slope of the pulldown table from 0 to 0.27 V, typ, clamps not added: 116 ohm
|   slope of the pullup table from 0 to 0.27 V, typ, clamps not added: 69.2 ohm
|   GND clamp passes 1 mA (typ) near -0.48 V on its own axis
|   POWER clamp passes 1 mA (typ) near -0.48 V on its own axis
|   rising waveform, R_fixture 50.00, V_fixture 1.8000: 20-80 % time 192ps typ, 195ps min, 180ps max; typ from 1.42 V to 1.8 V
|   rising waveform, R_fixture 50.00, V_fixture 0.0000: 20-80 % time 7.85ns typ, 10.3ns min, 635ps max; typ from 0 V to 0.558 V
|   falling waveform, R_fixture 50.00, V_fixture 1.8000: 20-80 % time 2.52ns typ, 4.93ns min, 358ps max; typ from 1.8 V to 1.42 V
|   falling waveform, R_fixture 50.00, V_fixture 0.0000: 20-80 % time 160ps typ, 252ps min, 120ps max; typ from 0.558 V to 0 V
[Pulldown]
| gpio_18v_2m_slow Pulldown S28FDSIO_IBIS
| Fri Apr  9 09:21:15 2021
| voltage   I(typ)   I(min)   I(max)
-1.8V     -4.861mA   -3.322mA   -6.131mA
-600mV    -4.861mA   -3.322mA   -6.131mA
-560mV    -4.667mA   -3.186mA   -5.915mA
-380mV    -3.434mA   -2.322mA   -4.456mA
200mV     1.744mA    1.116mA    2.336mA
630mV     5.091mA    3.031mA    7.047mA
970mV     6.865mA    3.763mA    10.02mA
1.12V     7.286mA    3.884mA    10.96mA
1.27V     7.519mA    3.947mA    11.63mA
1.46V     7.655mA    3.988mA    12.1mA
1.72V     7.725mA    4.018mA    12.33mA
3.6V      8.046mA    4.184mA    12.65mA
[Pullup]
| gpio_18v_2m_slow Pullup S28FDSIO_IBIS
| Fri Apr  9 09:21:15 2021
| voltage   I(typ)   I(min)   I(max)
-1.8V     9.413mA    6.213mA    12.78mA
-600mV    9.413mA    6.213mA    12.78mA
-400mV    6.535mA    4.274mA    9.025mA
90mV      -1.367mA   -856.5uA   -1.955mA
490mV     -6.571mA   -3.844mA   -9.795mA
670mV     -8.332mA   -4.692mA   -12.71mA
840mV     -9.599mA   -5.209mA   -15.01mA
1V        -10.43mA   -5.49mA    -16.71mA
1.17V     -10.97mA   -5.653mA   -18.01mA
1.43V     -11.38mA   -5.774mA   -19.13mA
1.78V     -11.52mA   -5.849mA   -19.73mA
3.6V      -11.72mA   -6.163mA   -20.13mA
[GND Clamp]
| gpio_18v_2m_slow GNDClamp S28FDSIO_IBIS
| Fri Apr  9 09:21:15 2021
| voltage   I(typ)   I(min)   I(max)
-1.8V     -2A        -2A        -2A
-1.3V     -2A        -2A        -2A
-1.26V    -2A        -1.843A    -2A
-1.16V    -1.422A    -1.447A    -2A
-1.06V    -856.1mA   -1.062A    -851.2mA
-1.01V    -593.2mA   -874.6mA   -376.3mA
-960mV    -356.1mA   -693.5mA   -100.4mA
-910mV    -166.4mA   -520.6mA   -27.8mA
-850mV    -43.16mA   -330.2mA   -16.77mA
-770mV    -10.89mA   -128.7mA   -12.54mA
-640mV    -4.841mA   -9.855mA   -6.797mA
1.8V      0A         0A         0A
[POWER Clamp]
| gpio_18v_2m_slow PWRClamp S28FDSIO_IBIS
| Fri Apr  9 09:21:15 2021
| voltage   I(typ)   I(min)   I(max)
-1.8V     2A         2A         2A
-1.12V    504.1mA    667.8mA    429.5mA
-1.11V    461.6mA    634.9mA    366.6mA
-1.1V     420.1mA    602.4mA    307.9mA
-1.09V    379.7mA    570.1mA    254.2mA
-1.06V    266.8mA    475.7mA    128.4mA
-1.03V    170.6mA    385.5mA    60.63mA
-970mV    51.47mA    223.5mA    26.69mA
-890mV    15.8mA     72.19mA    19.35mA
-820mV    10.79mA    19.94mA    14.9mA
-670mV    5.013mA    4.364mA    7.038mA
1.8V      0A         0A         0A
[Ramp]
dV/dt_r   0.335/7.857n   0.172/10.164n   0.528/635.088p
dV/dt_f   0.227/2.515n   0.119/4.838n   0.355/356.138p
R_load = 50.00ohm
[Rising Waveform]
| gpio_18v_2m_slow Rising-High S28FDSIO_IBIS
| Fri Apr  9 09:21:15 2021
R_fixture = 50.00
V_fixture = 1.8000
V_fixture_min = 1.6200
V_fixture_max = 1.9800
C_fixture = 0.00pF
| Time   V(typ)   V(min)   V(max)
0s        1.423V     1.421V     1.388V
470ps     1.424V     1.421V     1.394V
580ps     1.423V     1.422V     1.731V
700ps     1.425V     1.422V     1.873V
820ps     1.624V     1.421V     1.927V
920ps     1.713V     1.422V     1.951V
1.1ns     1.77V      1.426V     1.971V
1.34ns    1.789V     1.579V     1.978V
3.64ns    1.8V       1.62V      1.98V
50ns      1.8V       1.62V      1.98V
[Rising Waveform]
| gpio_18v_2m_slow Rising-Low S28FDSIO_IBIS
| Fri Apr  9 09:21:15 2021
R_fixture = 50.00
V_fixture = 0.0000
C_fixture = 0.00pF
| Time   V(typ)   V(min)   V(max)
0s        0V         0V         0V
920ps     -700uV     0V         6mV
1.35ns    100uV      -700uV     548.7mV
1.53ns    14mV       -100uV     666.2mV
2.2ns     320.9mV    100uV      745.5mV
3ns       392.2mV    76.1mV     769.5mV
4.02ns    414.3mV    178.7mV    782.2mV
8.08ns    441.4mV    217.7mV    799.9mV
50ns      479.6mV    251.6mV    826.7mV
50ns      557.8mV    287mV      879.3mV
[Falling Waveform]
| gpio_18v_2m_slow Falling-High S28FDSIO_IBIS
| Fri Apr  9 09:21:15 2021
R_fixture = 50.00
V_fixture = 1.8000
V_fixture_min = 1.6200
V_fixture_max = 1.9800
C_fixture = 0.00pF
| Time   V(typ)   V(min)   V(max)
0s        1.8V       1.62V      1.98V
520ps     1.801V     1.619V     1.98V
740ps     1.801V     1.621V     1.636V
940ps     1.748V     1.62V      1.514V
1.1ns     1.626V     1.621V     1.484V
1.27ns    1.56V      1.623V     1.471V
1.87ns    1.513V     1.51V      1.456V
7.2ns     1.488V     1.459V     1.44V
50ns      1.469V     1.443V     1.425V
50ns      1.423V     1.421V     1.388V
[Falling Waveform]
| gpio_18v_2m_slow Falling-Low S28FDSIO_IBIS
| Fri Apr  9 09:21:15 2021
R_fixture = 50.00
V_fixture = 0.0000
C_fixture = 0.00pF
| Time   V(typ)   V(min)   V(max)
0s        557.8mV    287mV      879.3mV
500ps     561mV      289.1mV    872.9mV
660ps     561.5mV    289.3mV    245.1mV
720ps     559.2mV    289mV      106.8mV
820ps     499.6mV    287.6mV    31.3mV
970ps     169mV      289mV      8mV
1.1ns     41.29mV    283.6mV    3.72mV
1.55ns    1.605mV    38.63mV    830uV
2.07ns    529uV      1.109mV    304uV
50ns      0V         0V         0V
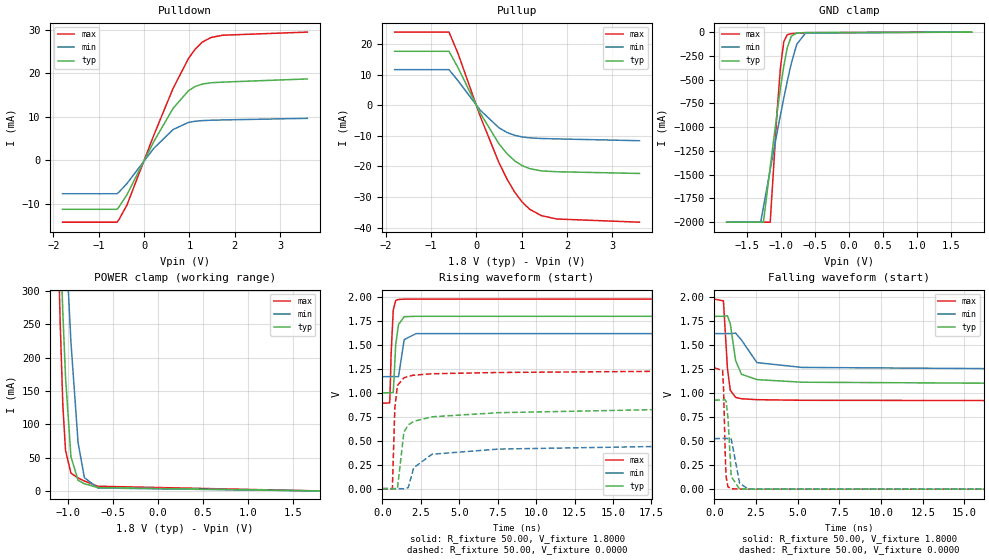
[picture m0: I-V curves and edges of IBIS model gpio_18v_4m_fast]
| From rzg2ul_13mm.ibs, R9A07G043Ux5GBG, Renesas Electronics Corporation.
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[Model]   gpio_18v_4m_fast
Model_type   I/O
Polarity   Non-Inverting
Enable   Active-Low
Vinl  =   0.6300V
Vinh  =   1.1700V
Vmeas =   0.9000V
Cref  =   10.00pF
| variable   typ   min   max
C_comp   2.470pF   2.346pF   2.470pF
[Model Spec]
| Subparameter   typ   min   max
| Thresholds
Vinh   1.1700   1.0530   1.2870
Vinl   0.6300   0.5670   0.6930
| Timing Thresholds
Vmeas   0.9000   0.8100   0.9900
| variable   typ   min   max
[Temperature Range]   25.000   125.000   -40.000
| variable   typ   min   max
[Voltage Range]   1.800V   1.620V   1.980V
| variable   typ   min   max
[Pullup Reference]   1.800V   1.620V   1.980V
| variable   typ   min   max
[Pulldown Reference]   0.000V   0.000V   0.000V
| variable   typ   min   max
[POWER Clamp Reference] 1.800V   1.620V   1.980V
| variable   typ   min   max
[GND Clamp Reference]   0.000V   0.000V   0.000V
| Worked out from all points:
|   slope of the pulldown table from 0 to 0.27 V, typ, clamps not added: 49.9 ohm
|   slope of the pullup table from 0 to 0.27 V, typ, clamps not added: 36.8 ohm
|   GND clamp passes 1 mA (typ) near -0.48 V on its own axis
|   POWER clamp passes 1 mA (typ) near -0.48 V on its own axis
|   rising waveform, R_fixture 50.00, V_fixture 1.8000: 20-80 % time 202ps typ, 203ps min, 156ps max; typ from 1 V to 1.8 V
|   rising waveform, R_fixture 50.00, V_fixture 0.0000: 20-80 % time 1.77ns typ, 7.34ns min, 197ps max; typ from 0 V to 0.927 V
|   falling waveform, R_fixture 50.00, V_fixture 1.8000: 20-80 % time 985ps typ, 5.36ns min, 235ps max; typ from 1.8 V to 1 V
|   falling waveform, R_fixture 50.00, V_fixture 0.0000: 20-80 % time 170ps typ, 269ps min, 112ps max; typ from 0.927 V to 0 V
[Pulldown]
| gpio_18v_4m_fast Pulldown S28FDSIO_IBIS
| Fri Apr  9 09:21:15 2021
| voltage   I(typ)   I(min)   I(max)
-1.8V     -11.28mA   -7.703mA   -14.25mA
-600mV    -11.28mA   -7.703mA   -14.25mA
-560mV    -10.83mA   -7.386mA   -13.75mA
-380mV    -7.955mA   -5.377mA   -10.33mA
210mV     4.237mA    2.706mA    5.679mA
640mV     11.96mA    7.081mA    16.57mA
980mV     16.03mA    8.716mA    23.44mA
1.13V     16.99mA    8.983mA    25.61mA
1.28V     17.52mA    9.119mA    27.15mA
1.47V     17.83mA    9.209mA    28.23mA
1.73V     17.98mA    9.275mA    28.77mA
3.6V      18.71mA    9.648mA    29.49mA
[Pullup]
| gpio_18v_4m_fast Pullup S28FDSIO_IBIS
| Fri Apr  9 09:21:15 2021
| voltage   I(typ)   I(min)   I(max)
-1.8V     17.68mA    11.67mA    23.97mA
-600mV    17.68mA    11.67mA    23.97mA
-400mV    12.27mA    8.028mA    16.92mA
90mV      -2.569mA   -1.609mA   -3.667mA
500mV     -12.56mA   -7.328mA   -18.72mA
680mV     -15.84mA   -8.89mA    -24.16mA
850mV     -18.19mA   -9.833mA   -28.45mA
1.01V     -19.71mA   -10.34mA   -31.62mA
1.18V     -20.72mA   -10.64mA   -34.03mA
1.44V     -21.46mA   -10.86mA   -36.12mA
1.78V     -21.74mA   -10.99mA   -37.21mA
3.6V      -22.3mA    -11.58mA   -38.25mA
[GND Clamp]
| gpio_18v_4m_fast GNDClamp S28FDSIO_IBIS
| Fri Apr  9 09:21:15 2021
| voltage   I(typ)   I(min)   I(max)
-1.8V     -2A        -2A        -2A
-1.3V     -2A        -2A        -2A
-1.26V    -2A        -1.843A    -2A
-1.16V    -1.422A    -1.447A    -2A
-1.06V    -856.1mA   -1.062A    -851.2mA
-1.01V    -593.2mA   -874.6mA   -376.3mA
-960mV    -356.1mA   -693.5mA   -100.4mA
-910mV    -166.4mA   -520.6mA   -27.8mA
-850mV    -43.16mA   -330.2mA   -16.77mA
-770mV    -10.89mA   -128.7mA   -12.54mA
-640mV    -4.841mA   -9.855mA   -6.797mA
1.8V      0A         0A         0A
[POWER Clamp]
| gpio_18v_4m_fast PWRClamp S28FDSIO_IBIS
| Fri Apr  9 09:21:15 2021
| voltage   I(typ)   I(min)   I(max)
-1.8V     2A         2A         2A
-1.12V    504.1mA    667.8mA    429.5mA
-1.11V    461.6mA    634.9mA    366.6mA
-1.1V     420.1mA    602.4mA    307.9mA
-1.09V    379.7mA    570.1mA    254.2mA
-1.06V    266.8mA    475.7mA    128.4mA
-1.03V    170.6mA    385.5mA    60.63mA
-970mV    51.47mA    223.5mA    26.69mA
-890mV    15.8mA     72.19mA    19.35mA
-820mV    10.79mA    19.94mA    14.9mA
-670mV    5.013mA    4.364mA    7.038mA
1.8V      0A         0A         0A
[Ramp]
dV/dt_r   0.556/1.769n   0.315/7.326n   0.758/197.018p
dV/dt_f   0.480/981.259p  0.271/5.289n   0.653/234.693p
R_load = 50.00ohm
[Rising Waveform]
| gpio_18v_4m_fast Rising-High S28FDSIO_IBIS
| Fri Apr  9 09:21:15 2021
R_fixture = 50.00
V_fixture = 1.8000
V_fixture_min = 1.6200
V_fixture_max = 1.9800
C_fixture = 0.00pF
| Time   V(typ)   V(min)   V(max)
0s        1V         1.169V     891.6mV
470ps     1.002V     1.17V      895.7mV
490ps     1.002V     1.17V      936mV
570ps     1.001V     1.171V     1.409V
710ps     1.005V     1.17V      1.866V
870ps     1.508V     1.169V     1.966V
1.05ns    1.714V     1.169V     1.976V
1.42ns    1.796V     1.557V     1.979V
2.19ns    1.8V       1.619V     1.98V
50ns      1.8V       1.62V      1.98V
[Rising Waveform]
| gpio_18v_4m_fast Rising-Low S28FDSIO_IBIS
| Fri Apr  9 09:21:15 2021
R_fixture = 50.00
V_fixture = 0.0000
C_fixture = 0.00pF
| Time   V(typ)   V(min)   V(max)
0s        0V         0V         0V
650ps     200uV      300uV      -1.5mV
810ps     -5.7mV     0V         838.7mV
980ps     -1.3mV     100uV      1.077V
1.4ns     590.5mV    -1.5mV     1.157V
1.68ns    665.2mV    9.4mV      1.173V
2.04ns    702.8mV    218.2mV    1.185V
3.23ns    750.3mV    359.1mV    1.2V
7.54ns    793mV      413mV      1.213V
50ns      926.7mV    525.7mV    1.263V
[Falling Waveform]
| gpio_18v_4m_fast Falling-High S28FDSIO_IBIS
| Fri Apr  9 09:21:15 2021
R_fixture = 50.00
V_fixture = 1.8000
V_fixture_min = 1.6200
V_fixture_max = 1.9800
C_fixture = 0.00pF
| Time   V(typ)   V(min)   V(max)
0s        1.8V       1.62V      1.98V
540ps     1.801V     1.62V      1.961V
780ps     1.806V     1.621V     1.258V
950ps     1.724V     1.62V      1.03V
1.27ns    1.34V      1.625V     956mV
1.62ns    1.197V     1.554V     941.7mV
2.55ns    1.141V     1.318V     932.1mV
5.26ns    1.114V     1.268V     925.8mV
50ns      1.072V     1.218V     914.8mV
50ns      1V         1.169V     891.6mV
[Falling Waveform]
| gpio_18v_4m_fast Falling-Low S28FDSIO_IBIS
| Fri Apr  9 09:21:15 2021
R_fixture = 50.00
V_fixture = 0.0000
C_fixture = 0.00pF
| Time   V(typ)   V(min)   V(max)
0s        926.7mV    525.7mV    1.263V
490ps     929.7mV    529.1mV    1.236V
550ps     928.7mV    529.5mV    1.032V
650ps     929.5mV    528.9mV    341.8mV
700ps     914mV      528.4mV    129.4mV
810ps     750.1mV    526.4mV    24.25mV
1.01ns    129.6mV    523.4mV    4.69mV
1.51ns    1.9mV      61.91mV    1.2mV
2.02ns    622uV      1.922mV    503uV
50ns      0V         0V         0V
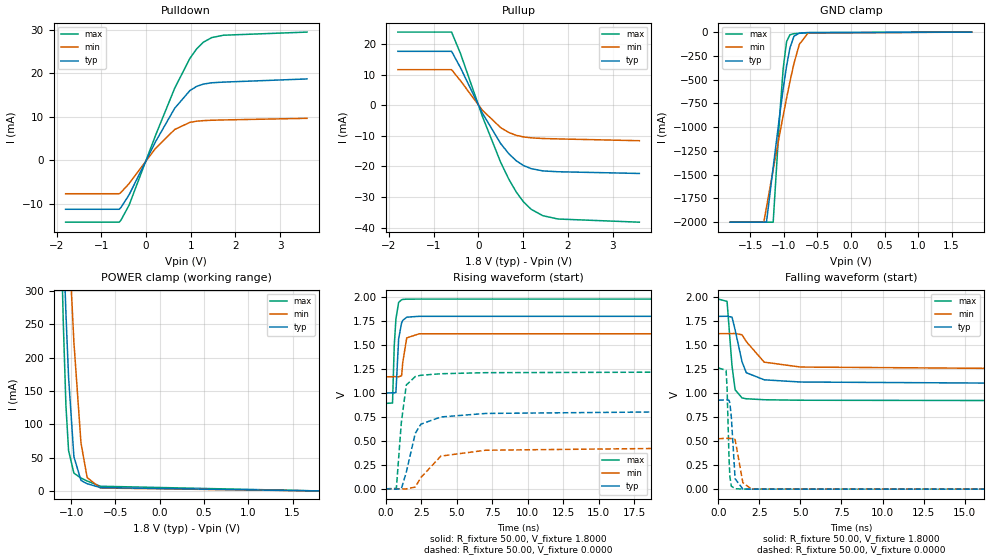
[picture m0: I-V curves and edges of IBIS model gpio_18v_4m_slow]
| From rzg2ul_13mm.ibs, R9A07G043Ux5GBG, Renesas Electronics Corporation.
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[Model]   gpio_18v_4m_slow
Model_type   I/O
Polarity   Non-Inverting
Enable   Active-Low
Vinl  =   0.6300V
Vinh  =   1.1700V
Vmeas =   0.9000V
Cref  =   10.00pF
| variable   typ   min   max
C_comp   2.470pF   2.346pF   2.470pF
[Model Spec]
| Subparameter   typ   min   max
| Thresholds
Vinh   1.1700   1.0530   1.2870
Vinl   0.6300   0.5670   0.6930
| Timing Thresholds
Vmeas   0.9000   0.8100   0.9900
| variable   typ   min   max
[Temperature Range]   25.000   125.000   -40.000
| variable   typ   min   max
[Voltage Range]   1.800V   1.620V   1.980V
| variable   typ   min   max
[Pullup Reference]   1.800V   1.620V   1.980V
| variable   typ   min   max
[Pulldown Reference]   0.000V   0.000V   0.000V
| variable   typ   min   max
[POWER Clamp Reference] 1.800V   1.620V   1.980V
| variable   typ   min   max
[GND Clamp Reference]   0.000V   0.000V   0.000V
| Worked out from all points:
|   slope of the pulldown table from 0 to 0.27 V, typ, clamps not added: 49.9 ohm
|   slope of the pullup table from 0 to 0.27 V, typ, clamps not added: 36.8 ohm
|   GND clamp passes 1 mA (typ) near -0.48 V on its own axis
|   POWER clamp passes 1 mA (typ) near -0.48 V on its own axis
|   rising waveform, R_fixture 50.00, V_fixture 1.8000: 20-80 % time 198ps typ, 203ps min, 187ps max; typ from 1 V to 1.8 V
|   rising waveform, R_fixture 50.00, V_fixture 0.0000: 20-80 % time 2.12ns typ, 7.8ns min, 458ps max; typ from 0 V to 0.927 V
|   falling waveform, R_fixture 50.00, V_fixture 1.8000: 20-80 % time 1.13ns typ, 5.49ns min, 301ps max; typ from 1.8 V to 1 V
|   falling waveform, R_fixture 50.00, V_fixture 0.0000: 20-80 % time 180ps typ, 269ps min, 126ps max; typ from 0.927 V to 0 V
[Pulldown]
| gpio_18v_4m_slow Pulldown S28FDSIO_IBIS
| Fri Apr  9 09:21:15 2021
| voltage   I(typ)   I(min)   I(max)
-1.8V     -11.28mA   -7.703mA   -14.25mA
-600mV    -11.28mA   -7.703mA   -14.25mA
-560mV    -10.83mA   -7.386mA   -13.75mA
-380mV    -7.955mA   -5.377mA   -10.33mA
210mV     4.237mA    2.706mA    5.679mA
640mV     11.96mA    7.081mA    16.57mA
980mV     16.03mA    8.716mA    23.44mA
1.13V     16.99mA    8.983mA    25.61mA
1.28V     17.52mA    9.119mA    27.15mA
1.47V     17.83mA    9.209mA    28.23mA
1.73V     17.98mA    9.275mA    28.77mA
3.6V      18.71mA    9.648mA    29.49mA
[Pullup]
| gpio_18v_4m_slow Pullup S28FDSIO_IBIS
| Fri Apr  9 09:21:15 2021
| voltage   I(typ)   I(min)   I(max)
-1.8V     17.68mA    11.67mA    23.97mA
-600mV    17.68mA    11.67mA    23.97mA
-400mV    12.27mA    8.028mA    16.92mA
90mV      -2.569mA   -1.609mA   -3.667mA
500mV     -12.56mA   -7.328mA   -18.72mA
680mV     -15.84mA   -8.89mA    -24.16mA
850mV     -18.19mA   -9.833mA   -28.45mA
1.01V     -19.71mA   -10.34mA   -31.62mA
1.18V     -20.72mA   -10.64mA   -34.03mA
1.44V     -21.46mA   -10.86mA   -36.12mA
1.78V     -21.74mA   -10.99mA   -37.21mA
3.6V      -22.3mA    -11.58mA   -38.25mA
[GND Clamp]
| gpio_18v_4m_slow GNDClamp S28FDSIO_IBIS
| Fri Apr  9 09:21:15 2021
| voltage   I(typ)   I(min)   I(max)
-1.8V     -2A        -2A        -2A
-1.3V     -2A        -2A        -2A
-1.26V    -2A        -1.843A    -2A
-1.16V    -1.422A    -1.447A    -2A
-1.06V    -856.1mA   -1.062A    -851.2mA
-1.01V    -593.2mA   -874.6mA   -376.3mA
-960mV    -356.1mA   -693.5mA   -100.4mA
-910mV    -166.4mA   -520.6mA   -27.8mA
-850mV    -43.16mA   -330.2mA   -16.77mA
-770mV    -10.89mA   -128.7mA   -12.54mA
-640mV    -4.841mA   -9.855mA   -6.797mA
1.8V      0A         0A         0A
[POWER Clamp]
| gpio_18v_4m_slow PWRClamp S28FDSIO_IBIS
| Fri Apr  9 09:21:15 2021
| voltage   I(typ)   I(min)   I(max)
-1.8V     2A         2A         2A
-1.12V    504.1mA    667.8mA    429.5mA
-1.11V    461.6mA    634.9mA    366.6mA
-1.1V     420.1mA    602.4mA    307.9mA
-1.09V    379.7mA    570.1mA    254.2mA
-1.06V    266.8mA    475.7mA    128.4mA
-1.03V    170.6mA    385.5mA    60.63mA
-970mV    51.47mA    223.5mA    26.69mA
-890mV    15.8mA     72.19mA    19.35mA
-820mV    10.79mA    19.94mA    14.9mA
-670mV    5.013mA    4.364mA    7.038mA
1.8V      0A         0A         0A
[Ramp]
dV/dt_r   0.556/2.118n   0.315/7.721n   0.758/458.397p
dV/dt_f   0.480/1.124n   0.271/5.486n   0.653/300.589p
R_load = 50.00ohm
[Rising Waveform]
| gpio_18v_4m_slow Rising-High S28FDSIO_IBIS
| Fri Apr  9 09:21:15 2021
R_fixture = 50.00
V_fixture = 1.8000
V_fixture_min = 1.6200
V_fixture_max = 1.9800
C_fixture = 0.00pF
| Time   V(typ)   V(min)   V(max)
0s        1V         1.169V     891.6mV
470ps     1.002V     1.17V      895.3mV
590ps     1.001V     1.171V     1.489V
710ps     1.006V     1.17V      1.773V
900ps     1.563V     1.169V     1.945V
1.11ns    1.732V     1.18V      1.973V
1.19ns    1.757V     1.317V     1.976V
1.47ns    1.791V     1.575V     1.979V
2.34ns    1.8V       1.617V     1.98V
50ns      1.8V       1.62V      1.98V
[Rising Waveform]
| gpio_18v_4m_slow Rising-Low S28FDSIO_IBIS
| Fri Apr  9 09:21:15 2021
R_fixture = 50.00
V_fixture = 0.0000
C_fixture = 0.00pF
| Time   V(typ)   V(min)   V(max)
0s        0V         0V         0V
740ps     -3.4mV     200uV      5.5mV
1.09ns    -300uV     -600uV     690.1mV
1.44ns    173.1mV    -900uV     1.083V
2.07ns    578.2mV    18.6mV     1.171V
2.47ns    675mV      118mV      1.185V
3.88ns    749.8mV    341.9mV    1.201V
7.04ns    786.7mV    403mV      1.212V
50ns      841.8mV    468.6mV    1.23V
50ns      926.7mV    525.7mV    1.263V
[Falling Waveform]
| gpio_18v_4m_slow Falling-High S28FDSIO_IBIS
| Fri Apr  9 09:21:15 2021
R_fixture = 50.00
V_fixture = 1.8000
V_fixture_min = 1.6200
V_fixture_max = 1.9800
C_fixture = 0.00pF
| Time   V(typ)   V(min)   V(max)
0s        1.8V       1.62V      1.98V
540ps     1.801V     1.62V      1.956V
840ps     1.792V     1.62V      1.285V
1.03ns    1.659V     1.622V     1.035V
1.45ns    1.327V     1.608V     950.4mV
1.71ns    1.213V     1.537V     941.6mV
2.8ns     1.139V     1.323V     931.4mV
5.01ns    1.116V     1.272V     926.2mV
50ns      1.072V     1.218V     914.9mV
50ns      1V         1.169V     891.6mV
[Falling Waveform]
| gpio_18v_4m_slow Falling-Low S28FDSIO_IBIS
| Fri Apr  9 09:21:15 2021
R_fixture = 50.00
V_fixture = 0.0000
C_fixture = 0.00pF
| Time   V(typ)   V(min)   V(max)
0s        926.7mV    525.7mV    1.263V
480ps     929.7mV    529mV      1.238V
540ps     928.7mV    529.6mV    1.053V
660ps     925.4mV    528.8mV    322.1mV
710ps     899.8mV    528.2mV    130.3mV
800ps     747.7mV    526.5mV    31.29mV
1.03ns    107.8mV    517.6mV    4.34mV
1.5ns     2.15mV     67.5mV     1.2mV
2.02ns    608uV      2.17mV     498uV
50ns      0V         0V         0V
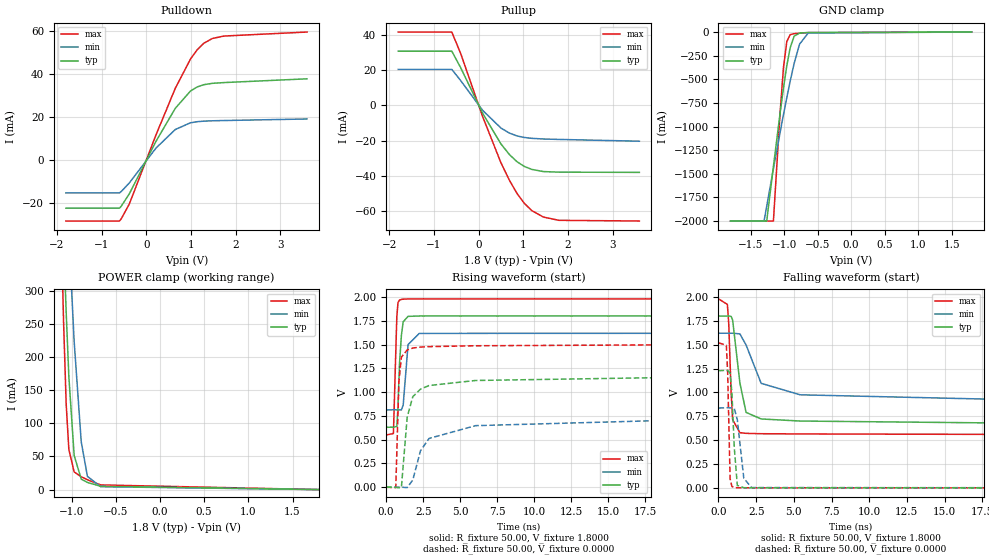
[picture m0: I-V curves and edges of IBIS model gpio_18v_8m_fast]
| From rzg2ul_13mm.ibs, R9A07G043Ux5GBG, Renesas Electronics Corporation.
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[Model]   gpio_18v_8m_fast
Model_type   I/O
Polarity   Non-Inverting
Enable   Active-Low
Vinl  =   0.6300V
Vinh  =   1.1700V
Vmeas =   0.9000V
Cref  =   10.00pF
| variable   typ   min   max
C_comp   2.470pF   2.346pF   2.470pF
[Model Spec]
| Subparameter   typ   min   max
| Thresholds
Vinh   1.1700   1.0530   1.2870
Vinl   0.6300   0.5670   0.6930
| Timing Thresholds
Vmeas   0.9000   0.8100   0.9900
| variable   typ   min   max
[Temperature Range]   25.000   125.000   -40.000
| variable   typ   min   max
[Voltage Range]   1.800V   1.620V   1.980V
| variable   typ   min   max
[Pullup Reference]   1.800V   1.620V   1.980V
| variable   typ   min   max
[Pulldown Reference]   0.000V   0.000V   0.000V
| variable   typ   min   max
[POWER Clamp Reference] 1.800V   1.620V   1.980V
| variable   typ   min   max
[GND Clamp Reference]   0.000V   0.000V   0.000V
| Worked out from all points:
|   slope of the pulldown table from 0 to 0.27 V, typ, clamps not added: 25.1 ohm
|   slope of the pullup table from 0 to 0.27 V, typ, clamps not added: 21.2 ohm
|   GND clamp passes 1 mA (typ) near -0.48 V on its own axis
|   POWER clamp passes 1 mA (typ) near -0.48 V on its own axis
|   rising waveform, R_fixture 50.00, V_fixture 1.8000: 20-80 % time 209ps typ, 228ps min, 147ps max; typ from 0.63 V to 1.8 V
|   rising waveform, R_fixture 50.00, V_fixture 0.0000: 20-80 % time 773ps typ, 5.76ns min, 174ps max; typ from 0 V to 1.23 V
|   falling waveform, R_fixture 50.00, V_fixture 1.8000: 20-80 % time 503ps typ, 3.57ns min, 202ps max; typ from 1.8 V to 0.63 V
|   falling waveform, R_fixture 50.00, V_fixture 0.0000: 20-80 % time 204ps typ, 322ps min, 119ps max; typ from 1.23 V to 0 V
[Pulldown]
| gpio_18v_8m_fast Pulldown S28FDSIO_IBIS
| Fri Apr  9 09:21:15 2021
| voltage   I(typ)   I(min)   I(max)
-1.8V     -22.46mA   -15.34mA   -28.46mA
-600mV    -22.46mA   -15.34mA   -28.46mA
-560mV    -21.55mA   -14.71mA   -27.44mA
-380mV    -15.79mA   -10.7mA    -20.54mA
220mV     8.807mA    5.63mA     11.83mA
650mV     24.13mA    14.24mA    33.47mA
990mV     32.2mA     17.38mA    47.12mA
1.14V     34.1mA     17.88mA    51.45mA
1.29V     35.16mA    18.14mA    54.52mA
1.48V     35.79mA    18.31mA    56.72mA
1.74V     36.14mA    18.43mA    57.86mA
3.6V      37.9mA     19.16mA    59.73mA
[Pullup]
| gpio_18v_8m_fast Pullup S28FDSIO_IBIS
| Fri Apr  9 09:21:15 2021
| voltage   I(typ)   I(min)   I(max)
-1.8V     30.76mA    20.42mA    41.64mA
-600mV    30.76mA    20.42mA    41.64mA
-400mV    21.33mA    14.04mA    29.36mA
90mV      -4.466mA   -2.816mA   -6.363mA
500mV     -21.88mA   -12.85mA   -32.54mA
690mV     -27.91mA   -15.72mA   -42.53mA
860mV     -31.98mA   -17.33mA   -49.98mA
1.02V     -34.62mA   -18.21mA   -55.5mA
1.19V     -36.34mA   -18.71mA   -59.72mA
1.45V     -37.58mA   -19.09mA   -63.4mA
1.8V      -37.91mA   -19.33mA   -65.27mA
3.6V      -38.04mA   -20.34mA   -65.65mA
[GND Clamp]
| gpio_18v_8m_fast GNDClamp S28FDSIO_IBIS
| Fri Apr  9 09:21:15 2021
| voltage   I(typ)   I(min)   I(max)
-1.8V     -2A        -2A        -2A
-1.3V     -2A        -2A        -2A
-1.26V    -2A        -1.843A    -2A
-1.16V    -1.422A    -1.447A    -2A
-1.06V    -856.1mA   -1.062A    -851.2mA
-1.01V    -593.2mA   -874.6mA   -376.3mA
-960mV    -356.1mA   -693.5mA   -100.4mA
-910mV    -166.4mA   -520.6mA   -27.8mA
-850mV    -43.16mA   -330.2mA   -16.77mA
-770mV    -10.89mA   -128.7mA   -12.54mA
-640mV    -4.841mA   -9.855mA   -6.797mA
1.8V      0A         0A         0A
[POWER Clamp]
| gpio_18v_8m_fast PWRClamp S28FDSIO_IBIS
| Fri Apr  9 09:21:15 2021
| voltage   I(typ)   I(min)   I(max)
-1.8V     2A         2A         2A
-1.12V    504.1mA    667.8mA    429.5mA
-1.11V    461.6mA    634.9mA    366.6mA
-1.1V     420.1mA    602.4mA    307.9mA
-1.09V    379.7mA    570.1mA    254.2mA
-1.06V    266.8mA    475.7mA    128.4mA
-1.03V    170.6mA    385.5mA    60.63mA
-970mV    51.47mA    223.5mA    26.69mA
-890mV    15.8mA     72.19mA    19.35mA
-820mV    10.79mA    19.94mA    14.9mA
-670mV    5.013mA    4.364mA    7.038mA
1.8V      0A         0A         0A
[Ramp]
dV/dt_r   0.737/771.926p  0.502/5.751n   0.912/173.381p
dV/dt_f   0.702/501.821p  0.485/3.558n   0.859/200.750p
R_load = 50.00ohm
[Rising Waveform]
| gpio_18v_8m_fast Rising-High S28FDSIO_IBIS
| Fri Apr  9 09:21:15 2021
R_fixture = 50.00
V_fixture = 1.8000
V_fixture_min = 1.6200
V_fixture_max = 1.9800
C_fixture = 0.00pF
| Time   V(typ)   V(min)   V(max)
0s        630.2mV    812.3mV    549mV
490ps     631.1mV    814mV      564.2mV
720ps     638.1mV    813.4mV    1.79V
800ps     845.7mV    812.3mV    1.941V
900ps     1.295V     812.8mV    1.968V
1.03ns    1.596V     812.4mV    1.974V
1.15ns    1.739V     862.8mV    1.977V
1.48ns    1.796V     1.499V     1.979V
2.24ns    1.8V       1.617V     1.98V
50ns      1.8V       1.62V      1.98V
[Rising Waveform]
| gpio_18v_8m_fast Rising-Low S28FDSIO_IBIS
| Fri Apr  9 09:21:15 2021
R_fixture = 50.00
V_fixture = 0.0000
C_fixture = 0.00pF
| Time   V(typ)   V(min)   V(max)
0s        0V         0V         0V
650ps     100uV      200uV      -4.8mV
860ps     -6.7mV     0V         1.108V
1.03ns    -1.3mV     100uV      1.368V
1.42ns    735.5mV    -3.7mV     1.442V
1.8ns     951.8mV    75.9mV     1.463V
2.32ns    1.031V     383.2mV    1.473V
2.9ns     1.069V     512.9mV    1.478V
6.04ns    1.122V     647.1mV    1.487V
50ns      1.228V     836mV      1.52V
[Falling Waveform]
| gpio_18v_8m_fast Falling-High S28FDSIO_IBIS
| Fri Apr  9 09:21:15 2021
R_fixture = 50.00
V_fixture = 1.8000
V_fixture_min = 1.6200
V_fixture_max = 1.9800
C_fixture = 0.00pF
| Time   V(typ)   V(min)   V(max)
0s        1.8V       1.62V      1.98V
590ps     1.8V       1.62V      1.922V
680ps     1.801V     1.62V      1.718V
840ps     1.796V     1.62V      997.7mV
940ps     1.756V     1.62V      713.6mV
1.42ns    1.099V     1.613V     578mV
1.83ns    790.4mV    1.497V     571mV
2.83ns    721.7mV    1.095V     567.2mV
5.42ns    700mV      974.8mV    564.7mV
50ns      630.2mV    812.3mV    549mV
[Falling Waveform]
| gpio_18v_8m_fast Falling-Low S28FDSIO_IBIS
| Fri Apr  9 09:21:15 2021
R_fixture = 50.00
V_fixture = 0.0000
C_fixture = 0.00pF
| Time   V(typ)   V(min)   V(max)
0s        1.228V     836mV      1.52V
520ps     1.23V      839.6mV    1.494V
610ps     1.23V      839.5mV    1.202V
770ps     1.202V     837.3mV    95.44mV
890ps     998.9mV    837.1mV    13.66mV
1.05ns    416.2mV    831.5mV    4.09mV
1.25ns    25.7mV     712.4mV    1.4mV
1.68ns    1.467mV    99.41mV    710uV
2.2ns     512uV      2.715mV    202uV
50ns      0V         0V         0V
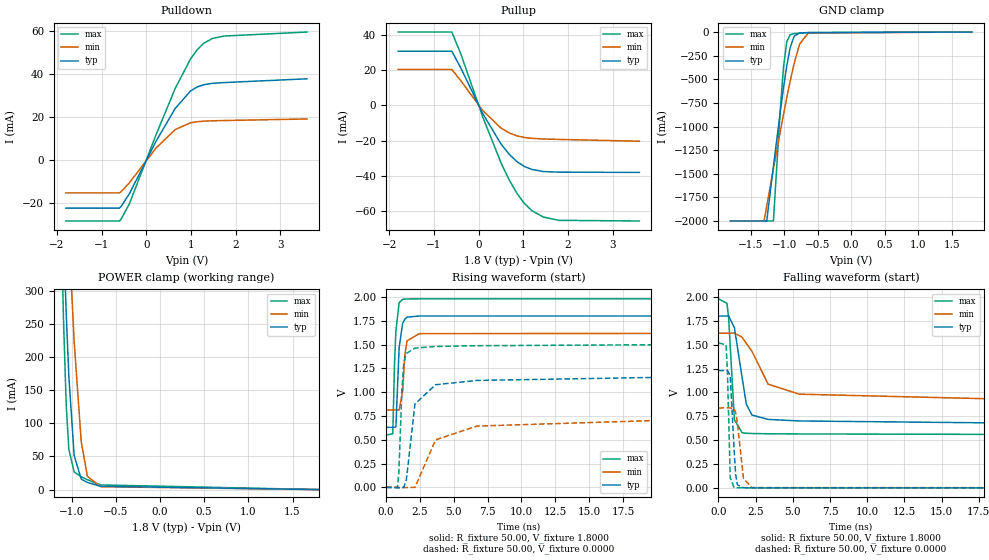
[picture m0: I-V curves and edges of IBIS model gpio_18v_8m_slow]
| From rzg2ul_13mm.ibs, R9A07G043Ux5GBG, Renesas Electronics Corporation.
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[Model]   gpio_18v_8m_slow
Model_type   I/O
Polarity   Non-Inverting
Enable   Active-Low
Vinl  =   0.6300V
Vinh  =   1.1700V
Vmeas =   0.9000V
Cref  =   10.00pF
| variable   typ   min   max
C_comp   2.470pF   2.346pF   2.470pF
[Model Spec]
| Subparameter   typ   min   max
| Thresholds
Vinh   1.1700   1.0530   1.2870
Vinl   0.6300   0.5670   0.6930
| Timing Thresholds
Vmeas   0.9000   0.8100   0.9900
| variable   typ   min   max
[Temperature Range]   25.000   125.000   -40.000
| variable   typ   min   max
[Voltage Range]   1.800V   1.620V   1.980V
| variable   typ   min   max
[Pullup Reference]   1.800V   1.620V   1.980V
| variable   typ   min   max
[Pulldown Reference]   0.000V   0.000V   0.000V
| variable   typ   min   max
[POWER Clamp Reference] 1.800V   1.620V   1.980V
| variable   typ   min   max
[GND Clamp Reference]   0.000V   0.000V   0.000V
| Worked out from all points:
|   slope of the pulldown table from 0 to 0.27 V, typ, clamps not added: 25.1 ohm
|   slope of the pullup table from 0 to 0.27 V, typ, clamps not added: 21.2 ohm
|   GND clamp passes 1 mA (typ) near -0.48 V on its own axis
|   POWER clamp passes 1 mA (typ) near -0.48 V on its own axis
|   rising waveform, R_fixture 50.00, V_fixture 1.8000: 20-80 % time 209ps typ, 227ps min, 194ps max; typ from 0.63 V to 1.8 V
|   rising waveform, R_fixture 50.00, V_fixture 0.0000: 20-80 % time 847ps typ, 5.85ns min, 253ps max; typ from 0 V to 1.23 V
|   falling waveform, R_fixture 50.00, V_fixture 1.8000: 20-80 % time 686ps typ, 3.84ns min, 290ps max; typ from 1.8 V to 0.63 V
|   falling waveform, R_fixture 50.00, V_fixture 0.0000: 20-80 % time 220ps typ, 324ps min, 141ps max; typ from 1.23 V to 0 V
[Pulldown]
| gpio_18v_8m_slow Pulldown S28FDSIO_IBIS
| Fri Apr  9 09:21:15 2021
| voltage   I(typ)   I(min)   I(max)
-1.8V     -22.46mA   -15.34mA   -28.46mA
-600mV    -22.46mA   -15.34mA   -28.46mA
-560mV    -21.55mA   -14.71mA   -27.44mA
-380mV    -15.79mA   -10.7mA    -20.54mA
220mV     8.807mA    5.63mA     11.83mA
650mV     24.13mA    14.24mA    33.47mA
990mV     32.2mA     17.38mA    47.12mA
1.14V     34.1mA     17.88mA    51.45mA
1.29V     35.16mA    18.14mA    54.52mA
1.48V     35.79mA    18.31mA    56.72mA
1.74V     36.14mA    18.43mA    57.86mA
3.6V      37.9mA     19.16mA    59.73mA
[Pullup]
| gpio_18v_8m_slow Pullup S28FDSIO_IBIS
| Fri Apr  9 09:21:15 2021
| voltage   I(typ)   I(min)   I(max)
-1.8V     30.76mA    20.42mA    41.64mA
-600mV    30.76mA    20.42mA    41.64mA
-400mV    21.33mA    14.04mA    29.36mA
90mV      -4.466mA   -2.816mA   -6.363mA
500mV     -21.88mA   -12.85mA   -32.54mA
690mV     -27.91mA   -15.72mA   -42.53mA
860mV     -31.98mA   -17.33mA   -49.98mA
1.02V     -34.62mA   -18.21mA   -55.5mA
1.19V     -36.34mA   -18.71mA   -59.72mA
1.45V     -37.58mA   -19.09mA   -63.4mA
1.8V      -37.91mA   -19.33mA   -65.27mA
3.6V      -38.05mA   -20.35mA   -65.65mA
[GND Clamp]
| gpio_18v_8m_slow GNDClamp S28FDSIO_IBIS
| Fri Apr  9 09:21:15 2021
| voltage   I(typ)   I(min)   I(max)
-1.8V     -2A        -2A        -2A
-1.3V     -2A        -2A        -2A
-1.26V    -2A        -1.843A    -2A
-1.16V    -1.422A    -1.447A    -2A
-1.06V    -856.1mA   -1.062A    -851.2mA
-1.01V    -593.2mA   -874.6mA   -376.3mA
-960mV    -356.1mA   -693.5mA   -100.4mA
-910mV    -166.4mA   -520.6mA   -27.8mA
-850mV    -43.16mA   -330.2mA   -16.77mA
-770mV    -10.89mA   -128.7mA   -12.54mA
-640mV    -4.841mA   -9.855mA   -6.797mA
1.8V      0A         0A         0A
[POWER Clamp]
| gpio_18v_8m_slow PWRClamp S28FDSIO_IBIS
| Fri Apr  9 09:21:15 2021
| voltage   I(typ)   I(min)   I(max)
-1.8V     2A         2A         2A
-1.12V    504.1mA    667.8mA    429.5mA
-1.11V    461.6mA    634.9mA    366.6mA
-1.1V     420.1mA    602.4mA    307.9mA
-1.09V    379.7mA    570.1mA    254.2mA
-1.06V    266.8mA    475.7mA    128.4mA
-1.03V    170.6mA    385.5mA    60.63mA
-970mV    51.47mA    223.5mA    26.69mA
-890mV    15.8mA     72.19mA    19.35mA
-820mV    10.79mA    19.94mA    14.9mA
-670mV    5.013mA    4.364mA    7.038mA
1.8V      0A         0A         0A
[Ramp]
dV/dt_r   0.737/844.801p  0.502/5.841n   0.912/252.880p
dV/dt_f   0.702/684.389p  0.485/3.774n   0.859/289.639p
R_load = 50.00ohm
[Rising Waveform]
| gpio_18v_8m_slow Rising-High S28FDSIO_IBIS
| Fri Apr  9 09:21:15 2021
R_fixture = 50.00
V_fixture = 1.8000
V_fixture_min = 1.6200
V_fixture_max = 1.9800
C_fixture = 0.00pF
| Time   V(typ)   V(min)   V(max)
0s        630.2mV    812.3mV    549mV
490ps     631.1mV    814mV      564.2mV
620ps     630.7mV    814.3mV    1.307V
720ps     638.2mV    813.4mV    1.644V
960ps     1.469V     813mV      1.939V
1.22ns    1.724V     1.009V     1.976V
1.38ns    1.766V     1.387V     1.978V
1.54ns    1.788V     1.539V     1.979V
2.45ns    1.8V       1.615V     1.98V
50ns      1.8V       1.62V      1.98V
[Rising Waveform]
| gpio_18v_8m_slow Rising-Low S28FDSIO_IBIS
| Fri Apr  9 09:21:15 2021
R_fixture = 50.00
V_fixture = 0.0000
C_fixture = 0.00pF
| Time   V(typ)   V(min)   V(max)
0s        0V         0V         0V
840ps     -5.1mV     0V         1.2mV
940ps     -4.4mV     0V         163mV
1.16ns    -600uV     -2.8mV     1.014V
1.3ns     500uV      -3mV       1.309V
1.49ns    77.5mV     -2.2mV     1.407V
2.13ns    876.5mV    300uV      1.463V
3.65ns    1.078V     498.6mV    1.48V
6.68ns    1.123V     643.6mV    1.488V
50ns      1.228V     836mV      1.52V
[Falling Waveform]
| gpio_18v_8m_slow Falling-High S28FDSIO_IBIS
| Fri Apr  9 09:21:15 2021
R_fixture = 50.00
V_fixture = 1.8000
V_fixture_min = 1.6200
V_fixture_max = 1.9800
C_fixture = 0.00pF
| Time   V(typ)   V(min)   V(max)
0s        1.8V       1.62V      1.98V
570ps     1.8V       1.62V      1.934V
680ps     1.802V     1.62V      1.788V
1.07ns    1.678V     1.622V     713.5mV
1.59ns    1.155V     1.578V     576.9mV
1.87ns    877.3mV    1.515V     571.9mV
2.25ns    762.9mV    1.43V      569.5mV
3.34ns    717.1mV    1.086V     566.6mV
5.44ns    700.9mV    981.4mV    564.7mV
50ns      630.2mV    812.3mV    549mV
[Falling Waveform]
| gpio_18v_8m_slow Falling-Low S28FDSIO_IBIS
| Fri Apr  9 09:21:15 2021
R_fixture = 50.00
V_fixture = 0.0000
C_fixture = 0.00pF
| Time   V(typ)   V(min)   V(max)
0s        1.228V     836mV      1.52V
510ps     1.23V      839.5mV    1.497V
600ps     1.23V      839.5mV    1.223V
790ps     1.174V     836.8mV    106.1mV
1.04ns    427.9mV    831.8mV    5.05mV
1.15ns    144.9mV    792.7mV    2.6mV
1.27ns    31.1mV     679.3mV    1.4mV
1.68ns    1.827mV    100.3mV    700uV
2.23ns    506uV      2.958mV    199uV
50ns      0V         0V         0V
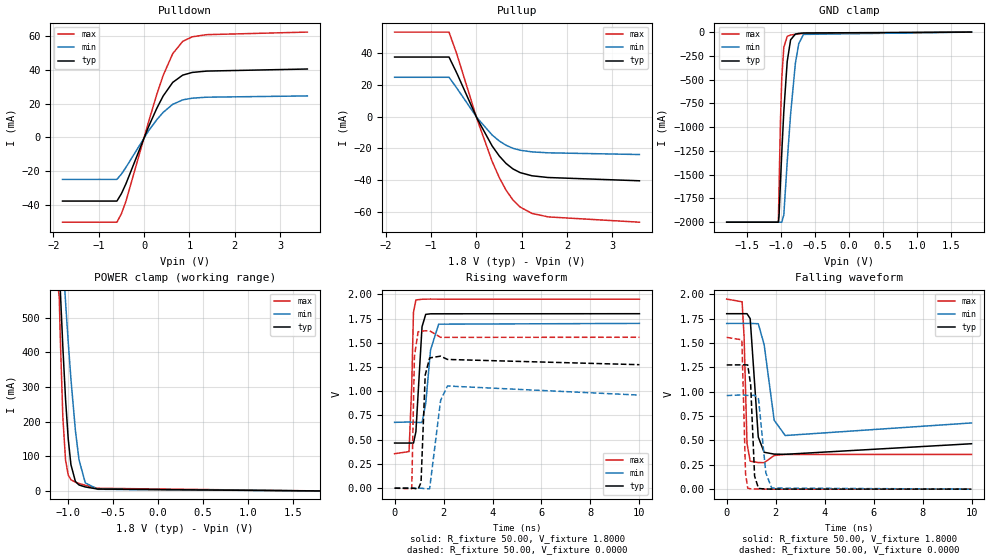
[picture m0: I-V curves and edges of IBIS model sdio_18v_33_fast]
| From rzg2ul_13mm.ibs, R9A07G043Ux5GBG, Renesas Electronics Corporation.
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[Model]   sdio_18v_33_fast
Model_type   I/O
Polarity   Non-Inverting
Enable   Active-Low
Vinl  =   0.5800V
Vinh  =   1.2700V
Vmeas =   0.9000V
Cref  =   10.00pF
| variable   typ   min   max
C_comp   3.085e-12  2.97e-12  3.085e-12
[Model Spec]
| Subparameter   typ   min   max
| Thresholds
Vinh   0.5800   NA   NA
Vinl   1.2700   NA   NA
| Timing Thresholds
Vmeas   0.9000   0.8500   0.9750
| variable   typ   min   max
[Temperature Range]   25.000   125.000   -40.000
| variable   typ   min   max
[Voltage Range]   1.800V   1.700V   1.950V
| variable   typ   min   max
[Pullup Reference]   1.800V   1.700V   1.950V
| variable   typ   min   max
[Pulldown Reference]   0.000V   0.000V   0.000V
| variable   typ   min   max
[POWER Clamp Reference] 1.800V   1.700V   1.950V
| variable   typ   min   max
[GND Clamp Reference]   0.000V   0.000V   0.000V
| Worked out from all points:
|   slope of the pulldown table from 0 to 0.27 V, typ, clamps not added: 16.1 ohm
|   slope of the pullup table from 0 to 0.27 V, typ, clamps not added: 18.3 ohm
|   GND clamp passes 1 mA (typ) near -0.46 V on its own axis
|   POWER clamp passes 1 mA (typ) near -0.48 V on its own axis
|   rising waveform, R_fixture 50.00, V_fixture 1.8000: 20-80 % time 185ps typ, 246ps min, 103ps max; typ from 0.466 V to 1.8 V
|   rising waveform, R_fixture 50.00, V_fixture 0.0000: 20-80 % time 103ps typ, 164ps min, 63.9ps max; typ from 0 V to 1.27 V
|   falling waveform, R_fixture 50.00, V_fixture 1.8000: 20-80 % time 177ps typ, 298ps min, 101ps max; typ from 1.8 V to 0.466 V
|   falling waveform, R_fixture 50.00, V_fixture 0.0000: 20-80 % time 121ps typ, 190ps min, 76.9ps max; typ from 1.27 V to 0 V
[Pulldown]
| sdio_18v_33_fast Pulldown S28FDSIO_IBIS
| Wed Sep  2 14:14:58 2020
| voltage   I(typ)   I(min)   I(max)
-1.8V     -37.81mA   -24.93mA   -50.35mA
-600mV    -37.81mA   -24.93mA   -50.35mA
-500mV    -33.35mA   -21.72mA   -45.26mA
-400mV    -27.47mA   -17.75mA   -37.86mA
100mV     6.496mA    4.008mA    9.445mA
280mV     17.32mA    10.54mA    25.61mA
420mV     24.61mA    14.87mA    36.84mA
630mV     32.65mA    19.64mA    49.7mA
850mV     36.98mA    22.27mA    57.02mA
1.06V     38.58mA    23.31mA    59.74mA
1.38V     39.39mA    23.88mA    61.03mA
3.6V      40.62mA    24.64mA    62.55mA
[Pullup]
| sdio_18v_33_fast Pullup S28FDSIO_IBIS
| Wed Sep  2 14:14:58 2020
| voltage   I(typ)   I(min)   I(max)
-1.8V     37.72mA    24.92mA    53.51mA
-600mV    37.72mA    24.92mA    53.51mA
-430mV    27.66mA    18.17mA    39.79mA
20mV      -1.188mA   -764.7uA   -1.764mA
350mV     -18.46mA   -11.57mA   -28.17mA
510mV     -24.91mA   -15.41mA   -38.59mA
660mV     -29.64mA   -18.11mA   -46.59mA
810mV     -33.05mA   -19.99mA   -52.7mA
970mV     -35.41mA   -21.24mA   -57.2mA
1.23V     -37.4mA    -22.28mA   -61.2mA
1.59V     -38.5mA    -22.87mA   -63.42mA
3.6V      -40.56mA   -23.95mA   -66.76mA
[GND Clamp]
| sdio_18v_33_fast GNDClamp S28FDSIO_IBIS
| Wed Sep  2 14:14:58 2020
| voltage   I(typ)   I(min)   I(max)
-1.8V     -2A        -2A        -2A
-1.04V    -2A        -2A        -2A
-1.03V    -1.932A    -2A        -1.644A
-1.01V    -1.591A    -2A        -948.5mA
-990mV    -1.27A     -2A        -485.9mA
-960mV    -836.4mA   -1.924A    -160.7mA
-910mV    -308.8mA   -1.364A    -45.24mA
-860mV    -81.11mA   -862.2mA   -30.85mA
-790mV    -20.98mA   -328.8mA   -23.83mA
-740mV    -14.08mA   -121mA     -19.54mA
-670mV    -9.363mA   -24.28mA   -13.84mA
1.8V      0A         0A         0A
[POWER Clamp]
| sdio_18v_33_fast PWRClamp S28FDSIO_IBIS
| Wed Sep  2 14:14:58 2020
| voltage   I(typ)   I(min)   I(max)
-1.8V     2A         2A         2A
-1.1V     651.8mA    840.5mA    559.9mA
-1.09V    589.6mA    796.8mA    454.6mA
-1.06V    415.3mA    668.7mA    212.9mA
-1.03V    265.3mA    545.8mA    89.35mA
-1V       149.8mA    429.9mA    45.65mA
-970mV    76.02mA    323.1mA    32.36mA
-920mV    27.24mA    174mA      25.09mA
-880mV    17.2mA     90.23mA    21.57mA
-810mV    11.45mA    23.27mA    16.22mA
-670mV    5.368mA    4.716mA    7.629mA
1.8V      0A         0A         0A
[Ramp]
dV/dt_r   0.764/103.253p  0.576/164.296p  0.934/63.888p
dV/dt_f   0.801/176.705p  0.613/295.128p  0.957/101.078p
R_load = 50.00ohm
[Rising Waveform]
| sdio_18v_33_fast Rising-High S28FDSIO_IBIS
| Wed Sep  2 14:14:58 2020
R_fixture = 50.00
V_fixture = 1.8000
V_fixture_min = 1.7000
V_fixture_max = 1.9500
C_fixture = 0.00pF
| Time   V(typ)   V(min)   V(max)
0s        465.7mV    679mV      355.7mV
590ps     465.7mV    682.7mV    377.7mV
700ps     465.2mV    681.1mV    1.058V
770ps     464.6mV    679.9mV    1.812V
870ps     581.7mV    678.9mV    1.942V
1.12ns    1.665V     677.4mV    1.949V
1.27ns    1.793V     870.9mV    1.95V
1.47ns    1.799V     1.428V     1.951V
1.8ns     1.799V     1.692V     1.95V
10ns      1.8V       1.7V       1.95V
[Rising Waveform]
| sdio_18v_33_fast Rising-Low S28FDSIO_IBIS
| Wed Sep  2 14:14:58 2020
R_fixture = 50.00
V_fixture = 0.0000
C_fixture = 0.00pF
| Time   V(typ)   V(min)   V(max)
0s        0V         0V         0V
700ps     100uV      300uV      -6.5mV
810ps     -2.3mV     100uV      1.36V
960ps     -10.2mV    100uV      1.613V
1.08ns    58.9mV     100uV      1.62V
1.25ns    1.167V     -5.7mV     1.623V
1.43ns    1.344V     -6.4mV     1.624V
1.88ns    1.362V     906.9mV    1.556V
2.16ns    1.328V     1.054V     1.556V
10ns      1.274V     960.3mV    1.557V
[Falling Waveform]
| sdio_18v_33_fast Falling-High S28FDSIO_IBIS
| Wed Sep  2 14:14:58 2020
R_fixture = 50.00
V_fixture = 1.8000
V_fixture_min = 1.7000
V_fixture_max = 1.9500
C_fixture = 0.00pF
| Time   V(typ)   V(min)   V(max)
0s        1.8V       1.7V       1.95V
630ps     1.8V       1.7V       1.922V
710ps     1.8V       1.7V       1.569V
830ps     1.8V       1.7V       468.9mV
960ps     1.749V     1.7V       287mV
1.29ns    534.5mV    1.697V     272.6mV
1.53ns    378.2mV    1.483V     271.5mV
1.94ns    359.2mV    707.1mV    345mV
2.39ns    357.2mV    550mV      355.9mV
10ns      465.7mV    679mV      355.7mV
[Falling Waveform]
| sdio_18v_33_fast Falling-Low S28FDSIO_IBIS
| Wed Sep  2 14:14:58 2020
R_fixture = 50.00
V_fixture = 0.0000
C_fixture = 0.00pF
| Time   V(typ)   V(min)   V(max)
0s        1.274V     960.3mV    1.557V
620ps     1.275V     966.3mV    1.532V
770ps     1.275V     963.6mV    159mV
860ps     1.274V     961.1mV    10.2mV
980ps     1.068V     960.6mV    2.5mV
1.14ns    134.5mV    963.1mV    900uV
1.3ns     6.8mV      926.4mV    500uV
1.6ns     1mV        165.7mV    300uV
1.84ns    500uV      10.9mV     -400uV
10ns      0V         0V         0V
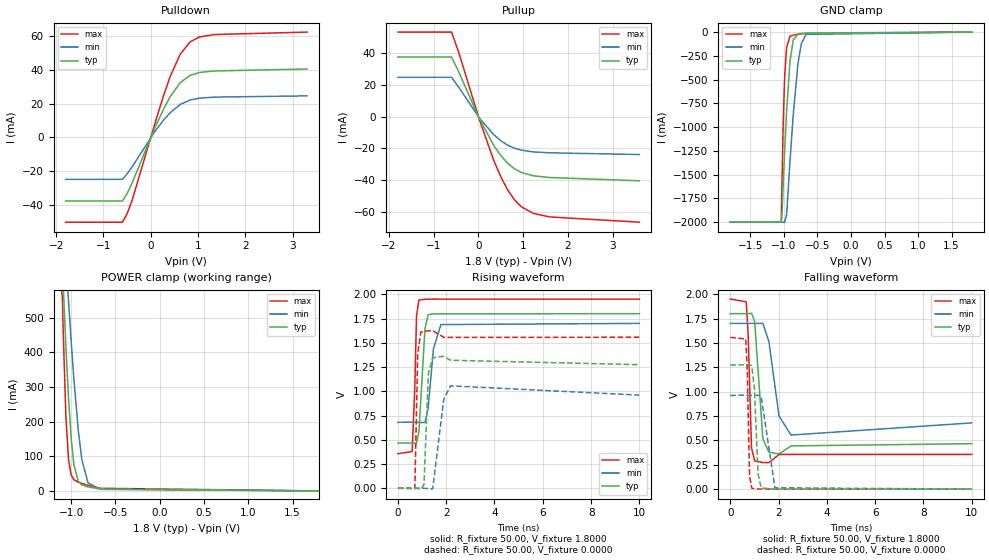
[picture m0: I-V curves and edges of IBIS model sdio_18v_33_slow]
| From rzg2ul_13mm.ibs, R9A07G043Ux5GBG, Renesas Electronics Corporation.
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[Model]   sdio_18v_33_slow
Model_type   I/O
Polarity   Non-Inverting
Enable   Active-Low
Vinl  =   0.5800V
Vinh  =   1.2700V
Vmeas =   0.9000V
Cref  =   10.00pF
| variable   typ   min   max
C_comp   3.085e-12  2.97e-12  3.085e-12
[Model Spec]
| Subparameter   typ   min   max
| Thresholds
Vinh   0.5800   NA   NA
Vinl   1.2700   NA   NA
| Timing Thresholds
Vmeas   0.9000   0.8500   0.9750
| variable   typ   min   max
[Temperature Range]   25.000   125.000   -40.000
| variable   typ   min   max
[Voltage Range]   1.800V   1.700V   1.950V
| variable   typ   min   max
[Pullup Reference]   1.800V   1.700V   1.950V
| variable   typ   min   max
[Pulldown Reference]   0.000V   0.000V   0.000V
| variable   typ   min   max
[POWER Clamp Reference] 1.800V   1.700V   1.950V
| variable   typ   min   max
[GND Clamp Reference]   0.000V   0.000V   0.000V
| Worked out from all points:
|   slope of the pulldown table from 0 to 0.27 V, typ, clamps not added: 16.1 ohm
|   slope of the pullup table from 0 to 0.27 V, typ, clamps not added: 18.3 ohm
|   GND clamp passes 1 mA (typ) near -0.46 V on its own axis
|   POWER clamp passes 1 mA (typ) near -0.48 V on its own axis
|   rising waveform, R_fixture 50.00, V_fixture 1.8000: 20-80 % time 191ps typ, 246ps min, 108ps max; typ from 0.466 V to 1.8 V
|   rising waveform, R_fixture 50.00, V_fixture 0.0000: 20-80 % time 103ps typ, 162ps min, 64.4ps max; typ from 0 V to 1.27 V
|   falling waveform, R_fixture 50.00, V_fixture 1.8000: 20-80 % time 186ps typ, 312ps min, 107ps max; typ from 1.8 V to 0.466 V
|   falling waveform, R_fixture 50.00, V_fixture 0.0000: 20-80 % time 127ps typ, 191ps min, 78.6ps max; typ from 1.27 V to 0 V
[Pulldown]
| sdio_18v_33_slow Pulldown S28FDSIO_IBIS
| Wed Sep  2 14:14:58 2020
| voltage   I(typ)   I(min)   I(max)
-1.8V     -37.81mA   -24.93mA   -50.35mA
-600mV    -37.81mA   -24.93mA   -50.35mA
-500mV    -33.35mA   -21.72mA   -45.26mA
-400mV    -27.47mA   -17.75mA   -37.86mA
90mV      5.86mA     3.619mA    8.512mA
270mV     16.75mA    10.2mA     24.75mA
410mV     24.13mA    14.59mA    36.1mA
620mV     32.36mA    19.47mA    49.22mA
830mV     36.73mA    22.11mA    56.58mA
1.03V     38.44mA    23.21mA    59.5mA
1.34V     39.34mA    23.83mA    60.94mA
3.3V      40.48mA    24.56mA    62.39mA
[Pullup]
| sdio_18v_33_slow Pullup S28FDSIO_IBIS
| Wed Sep  2 14:14:58 2020
| voltage   I(typ)   I(min)   I(max)
-1.8V     37.72mA    24.92mA    53.51mA
-600mV    37.72mA    24.92mA    53.51mA
-430mV    27.66mA    18.17mA    39.79mA
20mV      -1.188mA   -764.7uA   -1.764mA
350mV     -18.46mA   -11.57mA   -28.17mA
510mV     -24.91mA   -15.41mA   -38.59mA
660mV     -29.64mA   -18.11mA   -46.59mA
810mV     -33.05mA   -19.99mA   -52.7mA
970mV     -35.41mA   -21.24mA   -57.2mA
1.23V     -37.4mA    -22.28mA   -61.2mA
1.59V     -38.5mA    -22.87mA   -63.42mA
3.6V      -40.56mA   -23.95mA   -66.76mA
[GND Clamp]
| sdio_18v_33_slow GNDClamp S28FDSIO_IBIS
| Wed Sep  2 14:14:58 2020
| voltage   I(typ)   I(min)   I(max)
-1.8V     -2A        -2A        -2A
-1.04V    -2A        -2A        -2A
-1.03V    -1.932A    -2A        -1.644A
-1.01V    -1.591A    -2A        -948.5mA
-990mV    -1.27A     -2A        -485.9mA
-960mV    -836.4mA   -1.924A    -160.7mA
-910mV    -308.8mA   -1.364A    -45.24mA
-860mV    -81.11mA   -862.2mA   -30.85mA
-790mV    -20.98mA   -328.8mA   -23.83mA
-740mV    -14.08mA   -121mA     -19.54mA
-670mV    -9.363mA   -24.28mA   -13.84mA
1.8V      0A         0A         0A
[POWER Clamp]
| sdio_18v_33_slow PWRClamp S28FDSIO_IBIS
| Wed Sep  2 14:14:58 2020
| voltage   I(typ)   I(min)   I(max)
-1.8V     2A         2A         2A
-1.1V     651.8mA    840.5mA    559.9mA
-1.09V    589.6mA    796.8mA    454.6mA
-1.06V    415.3mA    668.7mA    212.9mA
-1.03V    265.3mA    545.8mA    89.35mA
-1V       149.8mA    429.9mA    45.65mA
-970mV    76.02mA    323.1mA    32.36mA
-920mV    27.24mA    174mA      25.09mA
-880mV    17.2mA     90.23mA    21.57mA
-810mV    11.45mA    23.27mA    16.22mA
-670mV    5.368mA    4.716mA    7.629mA
1.8V      0A         0A         0A
[Ramp]
dV/dt_r   0.764/102.905p  0.576/162.150p  0.934/64.383p
dV/dt_f   0.801/184.958p  0.613/311.913p  0.957/106.533p
R_load = 50.00ohm
[Rising Waveform]
| sdio_18v_33_slow Rising-High S28FDSIO_IBIS
| Wed Sep  2 14:14:58 2020
R_fixture = 50.00
V_fixture = 1.8000
V_fixture_min = 1.7000
V_fixture_max = 1.9500
C_fixture = 0.00pF
| Time   V(typ)   V(min)   V(max)
0s        465.7mV    679mV      355.7mV
590ps     465.8mV    682.7mV    378.9mV
700ps     465.3mV    681mV      1.047V
770ps     464.3mV    679.8mV    1.779V
870ps     582.9mV    678.9mV    1.941V
1.12ns    1.645V     677.7mV    1.949V
1.25ns    1.789V     823.1mV    1.949V
1.47ns    1.799V     1.436V     1.951V
1.78ns    1.799V     1.688V     1.95V
10ns      1.8V       1.7V       1.95V
[Rising Waveform]
| sdio_18v_33_slow Rising-Low S28FDSIO_IBIS
| Wed Sep  2 14:14:58 2020
R_fixture = 50.00
V_fixture = 0.0000
C_fixture = 0.00pF
| Time   V(typ)   V(min)   V(max)
0s        0V         0V         0V
700ps     100uV      300uV      -4.6mV
820ps     -3.5mV     100uV      1.389V
950ps     -9.8mV     100uV      1.611V
1.08ns    38.5mV     100uV      1.62V
1.26ns    1.18V      -6mV       1.623V
1.44ns    1.345V     -6mV       1.625V
1.9ns     1.361V     916.7mV    1.556V
2.18ns    1.32V      1.056V     1.556V
10ns      1.274V     960.3mV    1.557V
[Falling Waveform]
| sdio_18v_33_slow Falling-High S28FDSIO_IBIS
| Wed Sep  2 14:14:58 2020
R_fixture = 50.00
V_fixture = 1.8000
V_fixture_min = 1.7000
V_fixture_max = 1.9500
C_fixture = 0.00pF
| Time   V(typ)   V(min)   V(max)
0s        1.8V       1.7V       1.95V
660ps     1.8V       1.7V       1.922V
740ps     1.8V       1.7V       1.591V
880ps     1.804V     1.7V       423.7mV
1.01ns    1.722V     1.7V       288.4mV
1.35ns    516.8mV    1.701V     272.8mV
1.6ns     379.6mV    1.514V     271.5mV
2.02ns    359.8mV    748.4mV    355mV
2.52ns    442.9mV    554.3mV    355.9mV
10ns      465.7mV    679mV      355.7mV
[Falling Waveform]
| sdio_18v_33_slow Falling-Low S28FDSIO_IBIS
| Wed Sep  2 14:14:58 2020
R_fixture = 50.00
V_fixture = 0.0000
C_fixture = 0.00pF
| Time   V(typ)   V(min)   V(max)
0s        1.274V     960.3mV    1.557V
640ps     1.275V     966.1mV    1.54V
700ps     1.275V     965.2mV    1.244V
800ps     1.276V     963mV      133.6mV
890ps     1.266V     960.8mV    9.5mV
1ns       1.034V     960.8mV    2.6mV
1.15ns    160.9mV    963.5mV    1.033mV
1.28ns    10.3mV     951.3mV    600uV
1.85ns    575uV      12.6mV     -1.017mV
10ns      0V         0V         0V
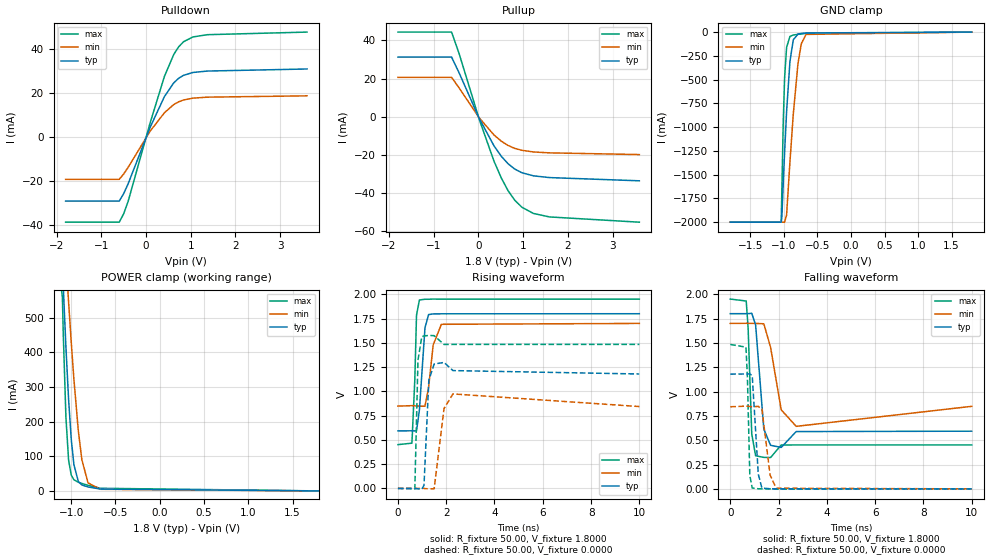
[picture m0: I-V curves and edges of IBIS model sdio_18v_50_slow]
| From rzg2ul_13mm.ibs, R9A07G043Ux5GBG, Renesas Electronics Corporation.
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[Model]   sdio_18v_50_slow
Model_type   I/O
Polarity   Non-Inverting
Enable   Active-Low
Vinl  =   0.5800V
Vinh  =   1.2700V
Vmeas =   0.9000V
Cref  =   10.00pF
| variable   typ   min   max
C_comp   3.085e-12  2.97e-12  3.085e-12
[Model Spec]
| Subparameter   typ   min   max
| Thresholds
Vinh   0.5800   NA   NA
Vinl   1.2700   NA   NA
| Timing Thresholds
Vmeas   0.9000   0.8500   0.9750
| variable   typ   min   max
[Temperature Range]   25.000   125.000   -40.000
| variable   typ   min   max
[Voltage Range]   1.800V   1.700V   1.950V
| variable   typ   min   max
[Pullup Reference]   1.800V   1.700V   1.950V
| variable   typ   min   max
[Pulldown Reference]   0.000V   0.000V   0.000V
| variable   typ   min   max
[POWER Clamp Reference] 1.800V   1.700V   1.950V
| variable   typ   min   max
[GND Clamp Reference]   0.000V   0.000V   0.000V
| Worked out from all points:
|   slope of the pulldown table from 0 to 0.27 V, typ, clamps not added: 21 ohm
|   slope of the pullup table from 0 to 0.27 V, typ, clamps not added: 22.2 ohm
|   GND clamp passes 1 mA (typ) near -0.46 V on its own axis
|   POWER clamp passes 1 mA (typ) near -0.48 V on its own axis
|   rising waveform, R_fixture 50.00, V_fixture 1.8000: 20-80 % time 196ps typ, 245ps min, 112ps max; typ from 0.593 V to 1.8 V
|   rising waveform, R_fixture 50.00, V_fixture 0.0000: 20-80 % time 111ps typ, 165ps min, 70.7ps max; typ from 0 V to 1.18 V
|   falling waveform, R_fixture 50.00, V_fixture 1.8000: 20-80 % time 200ps typ, 313ps min, 118ps max; typ from 1.8 V to 0.593 V
|   falling waveform, R_fixture 50.00, V_fixture 0.0000: 20-80 % time 130ps typ, 201ps min, 83.4ps max; typ from 1.18 V to 0 V
[Pulldown]
| sdio_18v_50_slow Pulldown S28FDSIO_IBIS
| Wed Sep  2 14:14:58 2020
| voltage   I(typ)   I(min)   I(max)
-1.8V     -28.98mA   -19.11mA   -38.59mA
-600mV    -28.98mA   -19.11mA   -38.59mA
-500mV    -25.57mA   -16.65mA   -34.71mA
-400mV    -21.07mA   -13.61mA   -29.05mA
90mV      4.496mA    2.775mA    6.532mA
410mV     18.51mA    11.18mA    27.68mA
620mV     24.79mA    14.91mA    37.72mA
730mV     26.87mA    16.16mA    41.19mA
840mV     28.22mA    16.99mA    43.49mA
1.05V     29.5mA     17.82mA    45.66mA
1.37V     30.14mA    18.27mA    46.68mA
3.6V      31.08mA    18.87mA    47.86mA
[Pullup]
| sdio_18v_50_slow Pullup S28FDSIO_IBIS
| Wed Sep  2 14:14:58 2020
| voltage   I(typ)   I(min)   I(max)
-1.8V     31.2mA     20.61mA    44.27mA
-600mV    31.2mA     20.61mA    44.27mA
-430mV    22.88mA    15.02mA    32.92mA
20mV      -982.9uA   -632.3uA   -1.46mA
350mV     -15.26mA   -9.564mA   -23.3mA
510mV     -20.6mA    -12.74mA   -31.91mA
660mV     -24.5mA    -14.97mA   -38.52mA
810mV     -27.31mA   -16.52mA   -43.56mA
970mV     -29.26mA   -17.55mA   -47.27mA
1.23V     -30.9mA    -18.41mA   -50.56mA
1.59V     -31.81mA   -18.89mA   -52.39mA
3.6V      -33.5mA    -19.78mA   -55.14mA
[GND Clamp]
| sdio_18v_50_slow GNDClamp S28FDSIO_IBIS
| Wed Sep  2 14:14:58 2020
| voltage   I(typ)   I(min)   I(max)
-1.8V     -2A        -2A        -2A
-1.04V    -2A        -2A        -2A
-1.03V    -1.932A    -2A        -1.644A
-1.01V    -1.591A    -2A        -948.5mA
-990mV    -1.27A     -2A        -485.9mA
-960mV    -836.4mA   -1.924A    -160.7mA
-910mV    -308.8mA   -1.364A    -45.24mA
-860mV    -81.11mA   -862.2mA   -30.85mA
-790mV    -20.98mA   -328.8mA   -23.83mA
-740mV    -14.08mA   -121mA     -19.54mA
-670mV    -9.363mA   -24.28mA   -13.84mA
1.8V      0A         0A         0A
[POWER Clamp]
| sdio_18v_50_slow PWRClamp S28FDSIO_IBIS
| Wed Sep  2 14:14:58 2020
| voltage   I(typ)   I(min)   I(max)
-1.8V     2A         2A         2A
-1.1V     651.8mA    840.5mA    559.9mA
-1.09V    589.6mA    796.8mA    454.6mA
-1.06V    415.3mA    668.7mA    212.9mA
-1.03V    265.3mA    545.8mA    89.35mA
-1V       149.8mA    429.9mA    45.65mA
-970mV    76.02mA    323.1mA    32.36mA
-920mV    27.24mA    174mA      25.09mA
-880mV    17.2mA     90.23mA    21.57mA
-810mV    11.45mA    23.27mA    16.22mA
-670mV    5.368mA    4.716mA    7.629mA
1.8V      0A         0A         0A
[Ramp]
dV/dt_r   0.708/110.582p  0.506/164.541p  0.890/70.689p
dV/dt_f   0.724/198.562p  0.511/311.967p  0.899/117.905p
R_load = 50.00ohm
[Rising Waveform]
| sdio_18v_50_slow Rising-High S28FDSIO_IBIS
| Wed Sep  2 14:14:58 2020
R_fixture = 50.00
V_fixture = 1.8000
V_fixture_min = 1.7000
V_fixture_max = 1.9500
C_fixture = 0.00pF
| Time   V(typ)   V(min)   V(max)
0s        592.7mV    848mV      451.2mV
580ps     593.7mV    852.7mV    466.2mV
700ps     592.7mV    851mV      1.125V
770ps     591.7mV    849.6mV    1.786V
890ps     808.7mV    848.2mV    1.942V
1.12ns    1.655V     847.1mV    1.949V
1.27ns    1.791V     1.039V     1.949V
1.46ns    1.798V     1.478V     1.951V
1.8ns     1.799V     1.691V     1.95V
10ns      1.8V       1.7V       1.95V
[Rising Waveform]
| sdio_18v_50_slow Rising-Low S28FDSIO_IBIS
| Wed Sep  2 14:14:58 2020
R_fixture = 50.00
V_fixture = 0.0000
C_fixture = 0.00pF
| Time   V(typ)   V(min)   V(max)
0s        0V         0V         0V
700ps     100uV      300uV      -4.4mV
830ps     -3.8mV     100uV      1.321V
990ps     -7.7mV     100uV      1.564V
1.08ns    32.9mV     100uV      1.571V
1.28ns    1.114V     -5.6mV     1.576V
1.5ns     1.282V     -3.5mV     1.574V
1.91ns    1.298V     823.2mV    1.483V
2.28ns    1.214V     973.6mV    1.484V
10ns      1.179V     843.6mV    1.484V
[Falling Waveform]
| sdio_18v_50_slow Falling-High S28FDSIO_IBIS
| Wed Sep  2 14:14:58 2020
R_fixture = 50.00
V_fixture = 1.8000
V_fixture_min = 1.7000
V_fixture_max = 1.9500
C_fixture = 0.00pF
| Time   V(typ)   V(min)   V(max)
0s        1.8V       1.7V       1.95V
660ps     1.8V       1.701V     1.93V
740ps     1.8V       1.701V     1.653V
890ps     1.804V     1.7V       564.8mV
1.05ns    1.684V     1.7V       340.2mV
1.39ns    613.8mV    1.696V     323.5mV
1.67ns    447.6mV    1.454V     321.9mV
2.11ns    425.7mV    812.4mV    450.6mV
2.73ns    588.7mV    642.3mV    451.3mV
10ns      592.7mV    848mV      451.2mV
[Falling Waveform]
| sdio_18v_50_slow Falling-Low S28FDSIO_IBIS
| Wed Sep  2 14:14:58 2020
R_fixture = 50.00
V_fixture = 0.0000
C_fixture = 0.00pF
| Time   V(typ)   V(min)   V(max)
0s        1.179V     843.6mV    1.484V
650ps     1.18V      849.9mV    1.456V
710ps     1.18V      849mV      1.148V
810ps     1.182V     846.5mV    137.2mV
910ps     1.163V     844.1mV    8.9mV
1.16ns    152.2mV    847.1mV    1.1mV
1.31ns    8.633mV    821.2mV    600uV
1.65ns    1.06mV     142.7mV    300uV
1.9ns     583uV      6.8mV      -2.98mV
10ns      0V         0V         0V
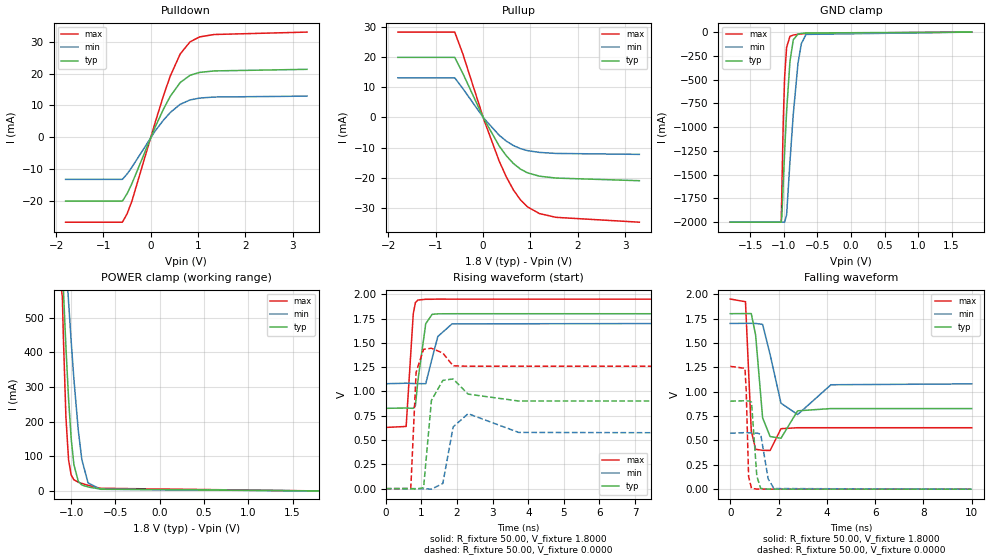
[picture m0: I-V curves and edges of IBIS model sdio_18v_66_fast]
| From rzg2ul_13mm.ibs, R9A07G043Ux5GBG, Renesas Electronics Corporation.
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[Model]   sdio_18v_66_fast
Model_type   I/O
Polarity   Non-Inverting
Enable   Active-Low
Vinl  =   0.5800V
Vinh  =   1.2700V
Vmeas =   0.9000V
Cref  =   10.00pF
| variable   typ   min   max
C_comp   3.085e-12  2.97e-12  3.085e-12
[Model Spec]
| Subparameter   typ   min   max
| Thresholds
Vinh   0.5800   NA   NA
Vinl   1.2700   NA   NA
| Timing Thresholds
Vmeas   0.9000   0.8500   0.9750
| variable   typ   min   max
[Temperature Range]   25.000   125.000   -40.000
| variable   typ   min   max
[Voltage Range]   1.800V   1.700V   1.950V
| variable   typ   min   max
[Pullup Reference]   1.800V   1.700V   1.950V
| variable   typ   min   max
[Pulldown Reference]   0.000V   0.000V   0.000V
| variable   typ   min   max
[POWER Clamp Reference] 1.800V   1.700V   1.950V
| variable   typ   min   max
[GND Clamp Reference]   0.000V   0.000V   0.000V
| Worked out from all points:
|   slope of the pulldown table from 0 to 0.27 V, typ, clamps not added: 30.3 ohm
|   slope of the pullup table from 0 to 0.27 V, typ, clamps not added: 34.9 ohm
|   GND clamp passes 1 mA (typ) near -0.46 V on its own axis
|   POWER clamp passes 1 mA (typ) near -0.48 V on its own axis
|   rising waveform, R_fixture 50.00, V_fixture 1.8000: 20-80 % time 199ps typ, 234ps min, 124ps max; typ from 0.827 V to 1.8 V
|   rising waveform, R_fixture 50.00, V_fixture 0.0000: 20-80 % time 109ps typ, 142ps min, 78.9ps max; typ from 0 V to 0.902 V
|   falling waveform, R_fixture 50.00, V_fixture 1.8000: 20-80 % time 183ps typ, 263ps min, 115ps max; typ from 1.8 V to 0.827 V
|   falling waveform, R_fixture 50.00, V_fixture 0.0000: 20-80 % time 119ps typ, 184ps min, 78.3ps max; typ from 0.902 V to 0 V
[Pulldown]
| sdio_18v_66_fast Pulldown S28FDSIO_IBIS
| Wed Sep  2 14:14:58 2020
| voltage   I(typ)   I(min)   I(max)
-1.8V     -20.09mA   -13.25mA   -26.72mA
-600mV    -20.09mA   -13.25mA   -26.72mA
-500mV    -17.73mA   -11.55mA   -24.05mA
-400mV    -14.62mA   -9.439mA   -20.14mA
90mV      3.118mA    1.924mA    4.529mA
270mV     8.911mA    5.422mA    13.17mA
410mV     12.83mA    7.753mA    19.19mA
620mV     17.18mA    10.34mA    26.14mA
830mV     19.49mA    11.73mA    30.01mA
1.03V     20.38mA    12.31mA    31.54mA
1.34V     20.85mA    12.64mA    32.3mA
3.3V      21.35mA    12.92mA    33.06mA
[Pullup]
| sdio_18v_66_fast Pullup S28FDSIO_IBIS
| Wed Sep  2 14:14:58 2020
| voltage   I(typ)   I(min)   I(max)
-1.8V     19.83mA    13.07mA    28.18mA
-600mV    19.83mA    13.07mA    28.18mA
-430mV    14.58mA    9.542mA    21.03mA
20mV      -626uA     -401.5uA   -932.6uA
340mV     -9.468mA   -5.922mA   -14.48mA
490mV     -12.7mA    -7.847mA   -19.69mA
640mV     -15.25mA   -9.317mA   -23.99mA
790mV     -17.11mA   -10.34mA   -27.29mA
940mV     -18.34mA   -11mA      -29.61mA
1.19V     -19.44mA   -11.58mA   -31.79mA
1.54V     -20.06mA   -11.92mA   -33.04mA
3.3V      -20.93mA   -12.23mA   -34.64mA
[GND Clamp]
| sdio_18v_66_fast GNDClamp S28FDSIO_IBIS
| Wed Sep  2 14:14:58 2020
| voltage   I(typ)   I(min)   I(max)
-1.8V     -2A        -2A        -2A
-1.04V    -2A        -2A        -2A
-1.03V    -1.932A    -2A        -1.644A
-1.01V    -1.591A    -2A        -948.5mA
-990mV    -1.27A     -2A        -485.9mA
-960mV    -836.4mA   -1.924A    -160.7mA
-910mV    -308.8mA   -1.364A    -45.24mA
-860mV    -81.11mA   -862.2mA   -30.85mA
-790mV    -20.98mA   -328.8mA   -23.83mA
-740mV    -14.08mA   -120.9mA   -19.54mA
-670mV    -9.363mA   -24.28mA   -13.84mA
1.8V      0A         0A         0A
[POWER Clamp]
| sdio_18v_66_fast PWRClamp S28FDSIO_IBIS
| Wed Sep  2 14:14:58 2020
| voltage   I(typ)   I(min)   I(max)
-1.8V     2A         2A         2A
-1.1V     651.8mA    840.5mA    559.9mA
-1.09V    589.6mA    796.8mA    454.6mA
-1.06V    415.3mA    668.7mA    212.9mA
-1.03V    265.3mA    545.8mA    89.35mA
-1V       149.8mA    429.9mA    45.65mA
-970mV    76.02mA    323.1mA    32.36mA
-920mV    27.24mA    174mA      25.09mA
-880mV    17.2mA     90.23mA    21.57mA
-810mV    11.45mA    23.27mA    16.22mA
-670mV    5.368mA    4.716mA    7.629mA
1.8V      0A         0A         0A
[Ramp]
dV/dt_r   0.541/109.388p  0.344/141.938p  0.756/78.912p
dV/dt_f   0.584/182.736p  0.372/261.324p  0.792/115.025p
R_load = 50.00ohm
[Rising Waveform]
| sdio_18v_66_fast Rising-High S28FDSIO_IBIS
| Wed Sep  2 14:14:58 2020
R_fixture = 50.00
V_fixture = 1.8000
V_fixture_min = 1.7000
V_fixture_max = 1.9500
C_fixture = 0.00pF
| Time   V(typ)   V(min)   V(max)
0s        826.8mV    1.08V      630.2mV
570ps     829.8mV    1.085V     640.1mV
770ps     826.6mV    1.082V     1.8V
830ps     854.2mV    1.081V     1.915V
900ps     1.11V      1.081V     1.941V
1.12ns    1.697V     1.08V      1.949V
1.3ns     1.794V     1.342V     1.949V
1.46ns    1.799V     1.566V     1.951V
1.86ns    1.8V       1.696V     1.95V
10ns      1.8V       1.7V       1.95V
[Rising Waveform]
| sdio_18v_66_fast Rising-Low S28FDSIO_IBIS
| Wed Sep  2 14:14:58 2020
R_fixture = 50.00
V_fixture = 0.0000
C_fixture = 0.00pF
| Time   V(typ)   V(min)   V(max)
0s        0V         0V         0V
700ps     100uV      400uV      2.3mV
850ps     -5.1mV     100uV      1.198V
1.06ns    10.5mV     100uV      1.434V
1.28ns    908.2mV    -5.1mV     1.445V
1.6ns     1.114V     53.5mV     1.396V
1.89ns    1.129V     635.5mV    1.264V
2.31ns    972.8mV    771.5mV    1.26V
3.73ns    902.1mV    578.9mV    1.26V
10ns      902.4mV    573.7mV    1.26V
[Falling Waveform]
| sdio_18v_66_fast Falling-High S28FDSIO_IBIS
| Wed Sep  2 14:14:58 2020
R_fixture = 50.00
V_fixture = 1.8000
V_fixture_min = 1.7000
V_fixture_max = 1.9500
C_fixture = 0.00pF
| Time   V(typ)   V(min)   V(max)
0s        1.8V       1.7V       1.95V
630ps     1.801V     1.701V     1.923V
870ps     1.801V     1.701V     598.7mV
1.05ns    1.581V     1.7V       409.2mV
1.34ns    731.8mV    1.69V      398.3mV
1.65ns    539.8mV    1.381V     397.2mV
2.1ns     522.3mV    882.4mV    620.4mV
2.79ns    803.5mV    765.3mV    630.2mV
4.17ns    826.8mV    1.071V     630.2mV
10ns      826.8mV    1.08V      630.2mV
[Falling Waveform]
| sdio_18v_66_fast Falling-Low S28FDSIO_IBIS
| Wed Sep  2 14:14:58 2020
R_fixture = 50.00
V_fixture = 0.0000
C_fixture = 0.00pF
| Time   V(typ)   V(min)   V(max)
0s        902.4mV    573.7mV    1.26V
610ps     907mV      580mV      1.239V
660ps     905mV      579.8mV    1.013V
760ps     904.3mV    578.5mV    129mV
880ps     893.1mV    575.3mV    7.2mV
1.1ns     133.5mV    575.4mV    1.2mV
1.26ns    7mV        565.3mV    600uV
1.57ns    1mV        105.5mV    300uV
1.81ns    500uV      6.175mV    100uV
10ns      0V         0V         0V
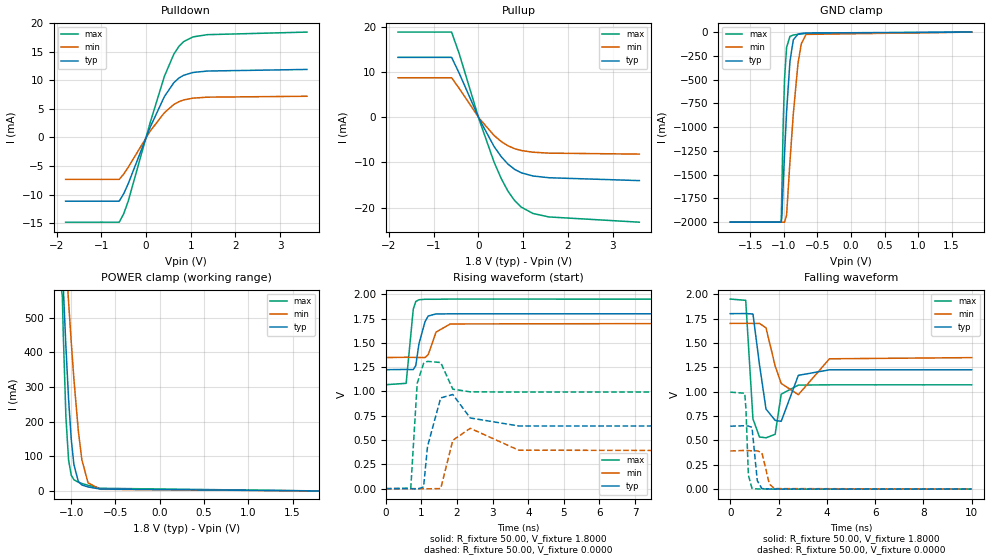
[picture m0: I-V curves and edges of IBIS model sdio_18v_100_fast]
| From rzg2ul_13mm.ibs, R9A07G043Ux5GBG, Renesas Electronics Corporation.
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[Model]   sdio_18v_100_fast
Model_type   I/O
Polarity   Non-Inverting
Enable   Active-Low
Vinl  =   0.5800V
Vinh  =   1.2700V
Vmeas =   0.9000V
Cref  =   10.00pF
| variable   typ   min   max
C_comp   3.085e-12  2.97e-12  3.085e-12
[Model Spec]
| Subparameter   typ   min   max
| Thresholds
Vinh   0.5800   NA   NA
Vinl   1.2700   NA   NA
| Timing Thresholds
Vmeas   0.9000   0.8500   0.9750
| variable   typ   min   max
[Temperature Range]   25.000   125.000   -40.000
| variable   typ   min   max
[Voltage Range]   1.800V   1.700V   1.950V
| variable   typ   min   max
[Pullup Reference]   1.800V   1.700V   1.950V
| variable   typ   min   max
[Pulldown Reference]   0.000V   0.000V   0.000V
| variable   typ   min   max
[POWER Clamp Reference] 1.800V   1.700V   1.950V
| variable   typ   min   max
[GND Clamp Reference]   0.000V   0.000V   0.000V
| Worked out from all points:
|   slope of the pulldown table from 0 to 0.27 V, typ, clamps not added: 54.5 ohm
|   slope of the pullup table from 0 to 0.27 V, typ, clamps not added: 52.2 ohm
|   GND clamp passes 1 mA (typ) near -0.46 V on its own axis
|   POWER clamp passes 1 mA (typ) near -0.48 V on its own axis
|   rising waveform, R_fixture 50.00, V_fixture 1.8000: 20-80 % time 203ps typ, 230ps min, 129ps max; typ from 1.22 V to 1.8 V
|   rising waveform, R_fixture 50.00, V_fixture 0.0000: 20-80 % time 94.2ps typ, 124ps min, 74.8ps max; typ from 0 V to 0.645 V
|   falling waveform, R_fixture 50.00, V_fixture 1.8000: 20-80 % time 145ps typ, 203ps min, 104ps max; typ from 1.8 V to 1.22 V
|   falling waveform, R_fixture 50.00, V_fixture 0.0000: 20-80 % time 122ps typ, 203ps min, 83.2ps max; typ from 0.645 V to 0 V
[Pulldown]
| sdio_18v_100_fast Pulldown S28FDSIO_IBIS
| Wed Sep  2 14:14:58 2020
| voltage   I(typ)   I(min)   I(max)
-1.8V     -11.16mA   -7.359mA   -14.84mA
-600mV    -11.16mA   -7.359mA   -14.84mA
-500mV    -9.853mA   -6.416mA   -13.36mA
-400mV    -8.125mA   -5.246mA   -11.19mA
90mV      1.733mA    1.069mA    2.518mA
410mV     7.129mA    4.306mA    10.67mA
620mV     9.543mA    5.738mA    14.52mA
730mV     10.34mA    6.217mA    15.85mA
840mV     10.85mA    6.534mA    16.73mA
1.05V     11.34mA    6.849mA    17.56mA
1.37V     11.59mA    7.022mA    17.95mA
3.6V      11.87mA    7.18mA     18.4mA
[Pullup]
| sdio_18v_100_fast Pullup S28FDSIO_IBIS
| Wed Sep  2 14:14:58 2020
| voltage   I(typ)   I(min)   I(max)
-1.8V     13.25mA    8.73mA     18.84mA
-600mV    13.25mA    8.73mA     18.84mA
-430mV    9.747mA    6.375mA    14.07mA
20mV      -418.5uA   -268.2uA   -624.1uA
350mV     -6.483mA   -4.049mA   -9.935mA
510mV     -8.735mA   -5.387mA   -13.58mA
660mV     -10.38mA   -6.326mA   -16.36mA
810mV     -11.55mA   -6.973mA   -18.47mA
960mV     -12.32mA   -7.384mA   -19.92mA
1.22V     -13.02mA   -7.754mA   -21.32mA
1.58V     -13.41mA   -7.963mA   -22.09mA
3.6V      -14.04mA   -8.177mA   -23.25mA
[GND Clamp]
| sdio_18v_100_fast GNDClamp S28FDSIO_IBIS
| Wed Sep  2 14:14:58 2020
| voltage   I(typ)   I(min)   I(max)
-1.8V     -2A        -2A        -2A
-1.04V    -2A        -2A        -2A
-1.03V    -1.932A    -2A        -1.644A
-1.01V    -1.591A    -2A        -948.5mA
-990mV    -1.27A     -2A        -485.9mA
-960mV    -836.4mA   -1.924A    -160.7mA
-910mV    -308.8mA   -1.364A    -45.24mA
-860mV    -81.11mA   -862.2mA   -30.85mA
-790mV    -20.98mA   -328.8mA   -23.83mA
-740mV    -14.08mA   -120.9mA   -19.54mA
-670mV    -9.363mA   -24.28mA   -13.84mA
1.8V      0A         0A         0A
[POWER Clamp]
| sdio_18v_100_fast PWRClamp S28FDSIO_IBIS
| Wed Sep  2 14:14:58 2020
| voltage   I(typ)   I(min)   I(max)
-1.8V     2A         2A         2A
-1.1V     651.8mA    840.5mA    559.9mA
-1.09V    589.6mA    796.8mA    454.6mA
-1.06V    415.3mA    668.7mA    212.9mA
-1.03V    265.3mA    545.8mA    89.35mA
-1V       149.8mA    429.9mA    45.65mA
-970mV    76.02mA    323.1mA    32.36mA
-920mV    27.24mA    174mA      25.09mA
-880mV    17.2mA     90.23mA    21.57mA
-810mV    11.45mA    23.27mA    16.22mA
-670mV    5.368mA    4.716mA    7.629mA
1.8V      0A         0A         0A
[Ramp]
dV/dt_r   0.387/94.079p   0.235/123.871p  0.597/74.751p
dV/dt_f   0.345/145.135p  0.210/202.038p  0.528/102.295p
R_load = 50.00ohm
[Rising Waveform]
| sdio_18v_100_fast Rising-High S28FDSIO_IBIS
| Wed Sep  2 14:14:58 2020
R_fixture = 50.00
V_fixture = 1.8000
V_fixture_min = 1.7000
V_fixture_max = 1.9500
C_fixture = 0.00pF
| Time   V(typ)   V(min)   V(max)
0s        1.224V     1.349V     1.07V
570ps     1.227V     1.352V     1.084V
770ps     1.225V     1.351V     1.848V
840ps     1.266V     1.35V      1.926V
930ps     1.491V     1.35V      1.944V
1.1ns     1.718V     1.349V     1.949V
1.19ns    1.777V     1.379V     1.949V
1.41ns    1.798V     1.611V     1.949V
1.81ns    1.799V     1.695V     1.951V
10ns      1.8V       1.7V       1.95V
[Rising Waveform]
| sdio_18v_100_fast Rising-Low S28FDSIO_IBIS
| Wed Sep  2 14:14:58 2020
R_fixture = 50.00
V_fixture = 0.0000
C_fixture = 0.00pF
| Time   V(typ)   V(min)   V(max)
0s        0V         0V         0V
700ps     200uV      500uV      5.5mV
880ps     -5.1mV     100uV      1.084V
1.06ns    17.3mV     100uV      1.289V
1.17ns    434.1mV    -1.6mV     1.31V
1.54ns    933.8mV    1.3mV      1.298V
1.88ns    969mV      497.9mV    1.024V
2.37ns    727.6mV    621mV      996.1mV
3.73ns    645mV      396.3mV    994.3mV
10ns      645mV      391.2mV    994.5mV
[Falling Waveform]
| sdio_18v_100_fast Falling-High S28FDSIO_IBIS
| Wed Sep  2 14:14:58 2020
R_fixture = 50.00
V_fixture = 1.8000
V_fixture_min = 1.7000
V_fixture_max = 1.9500
C_fixture = 0.00pF
| Time   V(typ)   V(min)   V(max)
0s        1.8V       1.7V       1.95V
640ps     1.801V     1.701V     1.937V
940ps     1.797V     1.7V       720.2mV
1.21ns    1.278V     1.7V       534.4mV
1.48ns    821.4mV    1.655V     526.2mV
1.86ns    705mV      1.263V     561.9mV
2.11ns    695.1mV    1.084V     974mV
2.82ns    1.167V     968.6mV    1.067V
4.11ns    1.224V     1.337V     1.07V
10ns      1.224V     1.349V     1.07V
[Falling Waveform]
| sdio_18v_100_fast Falling-Low S28FDSIO_IBIS
| Wed Sep  2 14:14:58 2020
R_fixture = 50.00
V_fixture = 0.0000
C_fixture = 0.00pF
| Time   V(typ)   V(min)   V(max)
0s        645mV      391.2mV    994.5mV
600ps     649.9mV    396.4mV    983.9mV
650ps     648.1mV    396.2mV    820.4mV
750ps     646.8mV    395.1mV    144.5mV
900ps     633.5mV    391.8mV    6.5mV
1.12ns    86.7mV     392.7mV    1.083mV
1.31ns    4.5mV      373.5mV    525uV
1.62ns    800uV      51.6mV     300uV
1.83ns    500uV      5mV        -1.071mV
10ns      0V         0V         0V
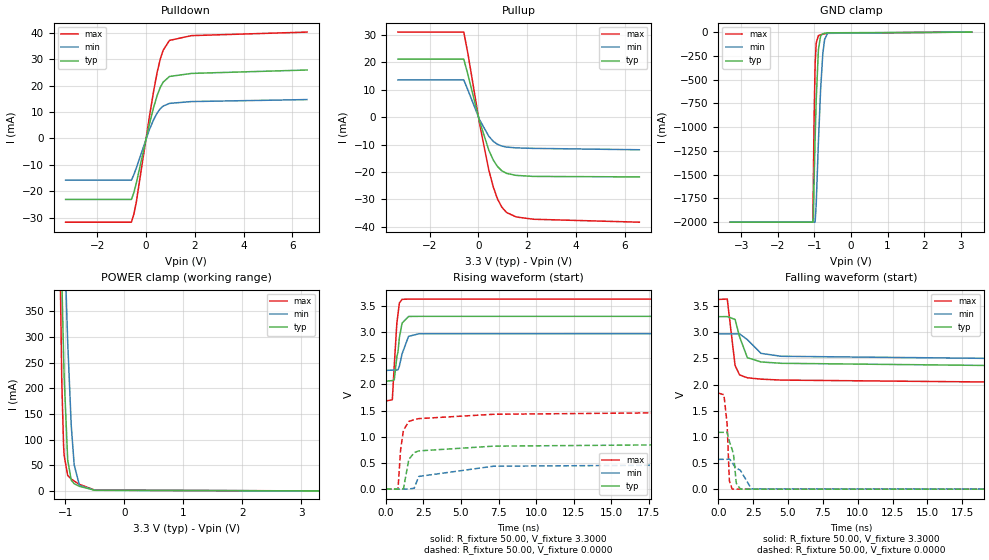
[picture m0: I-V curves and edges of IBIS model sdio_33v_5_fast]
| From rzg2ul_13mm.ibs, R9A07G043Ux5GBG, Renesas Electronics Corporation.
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[Model]   sdio_33v_5_fast
Model_type   I/O
Polarity   Non-Inverting
Enable   Active-Low
Vinl  =   0.8250V
Vinh  =   2.0625V
Vmeas =   1.6500V
Cref  =   10.00pF
| variable   typ   min   max
C_comp   2.652e-12  2.638e-12  2.667e-12
[Model Spec]
| Subparameter   typ   min   max
| Thresholds
Vinh   2.0625   1.8563   2.2688
Vinl   0.8250   0.7425   0.9075
| Timing Thresholds
Vmeas   1.6500   1.4850   1.8150
| variable   typ   min   max
[Temperature Range]   25.000   125.000   -40.000
| variable   typ   min   max
[Voltage Range]   3.300V   2.970V   3.630V
| variable   typ   min   max
[Pullup Reference]   3.300V   2.970V   3.630V
| variable   typ   min   max
[Pulldown Reference]   0.000V   0.000V   0.000V
| variable   typ   min   max
[POWER Clamp Reference] 3.300V   2.970V   3.630V
| variable   typ   min   max
[GND Clamp Reference]   0.000V   0.000V   0.000V
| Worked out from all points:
|   slope of the pulldown table from 0 to 0.495 V, typ, clamps not added: 28.6 ohm
|   slope of the pullup table from 0 to 0.495 V, typ, clamps not added: 36.7 ohm
|   GND clamp passes 1 mA (typ) near -0.46 V on its own axis
|   POWER clamp passes 1 mA (typ) near -0.48 V on its own axis
|   rising waveform, R_fixture 50.00, V_fixture 3.3000: 20-80 % time 345ps typ, 424ps min, 264ps max; typ from 2.06 V to 3.3 V
|   rising waveform, R_fixture 50.00, V_fixture 0.0000: 20-80 % time 24ns typ, 11.6ns min, 16.4ns max; typ from 0 V to 1.09 V
|   falling waveform, R_fixture 50.00, V_fixture 3.3000: 20-80 % time 38.6ns typ, 37.8ns min, 5.88ns max; typ from 3.3 V to 2.06 V
|   falling waveform, R_fixture 50.00, V_fixture 0.0000: 20-80 % time 407ps typ, 939ps min, 212ps max; typ from 1.09 V to 0 V
[Pulldown]
| sdio_33v_5_fast Pulldown S28FDSIO_IBIS
| Wed Sep  2 14:14:57 2020
| voltage   I(typ)   I(min)   I(max)
-3.3V     -23.12mA   -15.8mA    -31.72mA
-600mV    -23.12mA   -15.8mA    -31.72mA
-500mV    -20.5mA    -13.74mA   -28.68mA
-400mV    -16.94mA   -11.2mA    -24.08mA
130mV     5.186mA    3.183mA    7.782mA
310mV     11.76mA    7.08mA     17.91mA
460mV     16.37mA    9.682mA    25.22mA
580mV     19.24mA    11.2mA     29.9mA
700mV     21.28mA    12.21mA    33.34mA
960mV     23.42mA    13.24mA    37.07mA
1.86V     24.58mA    13.93mA    38.88mA
6.6V      25.87mA    14.68mA    40.22mA
[Pullup]
| sdio_33v_5_fast Pullup S28FDSIO_IBIS
| Wed Sep  2 14:14:57 2020
| voltage   I(typ)   I(min)   I(max)
-3.3V     21.11mA    13.53mA    30.96mA
-600mV    21.11mA    13.53mA    30.96mA
-430mV    15.5mA     9.851mA    23.1mA
50mV      -1.64mA    -1.004mA   -2.542mA
430mV     -12.1mA    -7.023mA   -19.4mA
610mV     -15.61mA   -8.81mA    -25.44mA
780mV     -17.97mA   -9.898mA   -29.74mA
960mV     -19.55mA   -10.55mA   -32.8mA
1.16V     -20.5mA    -10.92mA   -34.76mA
1.55V     -21.23mA   -11.21mA   -36.36mA
2.26V     -21.6mA    -11.39mA   -37.2mA
6.6V      -21.78mA   -11.89mA   -38.27mA
[GND Clamp]
| sdio_33v_5_fast GNDClamp S28FDSIO_IBIS
| Wed Sep  2 14:14:57 2020
| voltage   I(typ)   I(min)   I(max)
-3.3V     -2A        -2A        -2A
-1.04V    -2A        -2A        -2A
-1.03V    -1.932A    -2A        -1.644A
-1.01V    -1.591A    -2A        -948.6mA
-980mV    -1.118A    -2A        -336.7mA
-950mV    -708.6mA   -1.808A    -114.2mA
-890mV    -184.6mA   -1.154A    -36.66mA
-830mV    -39.24mA   -603.6mA   -27.52mA
-770mV    -17.34mA   -227.2mA   -22.11mA
-720mV    -12.52mA   -76.57mA   -17.89mA
-640mV    -7.709mA   -13.11mA   -11.55mA
3.3V      0A         0A         0A
[POWER Clamp]
| sdio_33v_5_fast PWRClamp S28FDSIO_IBIS
| Wed Sep  2 14:14:57 2020
| voltage   I(typ)   I(min)   I(max)
-3.3V     2A         2A         2A
-1.1V     651.8mA    840.5mA    559.9mA
-1.09V    589.7mA    796.8mA    454.6mA
-1.06V    415.3mA    668.7mA    212.9mA
-1.03V    265.3mA    545.8mA    89.35mA
-1.02V    222.5mA    506.3mA    68.83mA
-960mV    60.28mA    290mA      30.23mA
-900mV    20.85mA    127.6mA    23.26mA
-850mV    14.07mA    50.77mA    19.19mA
-760mV    8.961mA    10.58mA    12.81mA
-500mV    1.247mA    1.344mA    1.633mA
3.3V      0A         0A         0A
[Ramp]
dV/dt_r   0.652/23.758n   0.342/11.414n   1.104/16.397n
dV/dt_f   0.743/73.127n   0.422/600.749n  1.169/5.843n
R_load = 50.00ohm
[Rising Waveform]
| sdio_33v_5_fast Rising-High S28FDSIO_IBIS
| Wed Sep  2 14:14:57 2020
R_fixture = 50.00
V_fixture = 3.3000
V_fixture_min = 2.9700
V_fixture_max = 3.6300
C_fixture = 0.00pF
| Time   V(typ)   V(min)   V(max)
0s        2.061V     2.267V     1.682V
430ps     2.071V     2.271V     1.706V
560ps     2.087V     2.276V     2.362V
730ps     2.52V      2.274V     3.164V
810ps     2.628V     2.279V     3.344V
900ps     2.893V     2.348V     3.555V
1.08ns    3.171V     2.583V     3.625V
1.51ns    3.297V     2.917V     3.629V
2.21ns    3.3V       2.967V     3.63V
40ns      3.3V       2.97V      3.63V
[Rising Waveform]
| sdio_33v_5_fast Rising-Low S28FDSIO_IBIS
| Wed Sep  2 14:14:57 2020
R_fixture = 50.00
V_fixture = 0.0000
C_fixture = 0.00pF
| Time   V(typ)   V(min)   V(max)
0s        0V         0V         0V
810ps     -3.3mV     -1.9mV     2.8mV
980ps     -2mV       -2.8mV     746.7mV
1.17ns    3.1mV      -800uV     1.122V
1.53ns    566.6mV    -700uV     1.29V
1.89ns    695mV      15.8mV     1.327V
2.19ns    728.4mV    239.8mV    1.345V
7.17ns    818.8mV    435.6mV    1.428V
40ns      892.3mV    491.8mV    1.511V
40ns      1.087V     570.7mV    1.839V
[Falling Waveform]
| sdio_33v_5_fast Falling-High S28FDSIO_IBIS
| Wed Sep  2 14:14:57 2020
R_fixture = 50.00
V_fixture = 3.3000
V_fixture_min = 2.9700
V_fixture_max = 3.6300
C_fixture = 0.00pF
| Time   V(typ)   V(min)   V(max)
0s        3.3V       2.97V      3.63V
650ps     3.301V     2.97V      3.637V
1.21ns    3.248V     2.972V     2.368V
1.53ns    2.918V     2.972V     2.187V
2.09ns    2.516V     2.861V     2.131V
3.07ns    2.434V     2.598V     2.105V
4.52ns    2.408V     2.542V     2.087V
31ns      2.334V     2.471V     2.021V
40ns      2.325V     2.463V     1.682V
40ns      2.061V     2.267V     1.682V
[Falling Waveform]
| sdio_33v_5_fast Falling-Low S28FDSIO_IBIS
| Wed Sep  2 14:14:57 2020
R_fixture = 50.00
V_fixture = 0.0000
C_fixture = 0.00pF
| Time   V(typ)   V(min)   V(max)
0s        1.087V     570.7mV    1.839V
410ps     1.087V     570.7mV    1.807V
640ps     1.09V      570.7mV    1.247V
800ps     914.5mV    577mV      163mV
1ns       759.2mV    519.6mV    4.067mV
1.1ns     660.7mV    465.6mV    1.5mV
1.3ns     111.2mV    402.3mV    600uV
1.59ns    2.75mV     361.3mV    400uV
2.38ns    391uV      6.587mV    200uV
40ns      0V         0V         0V
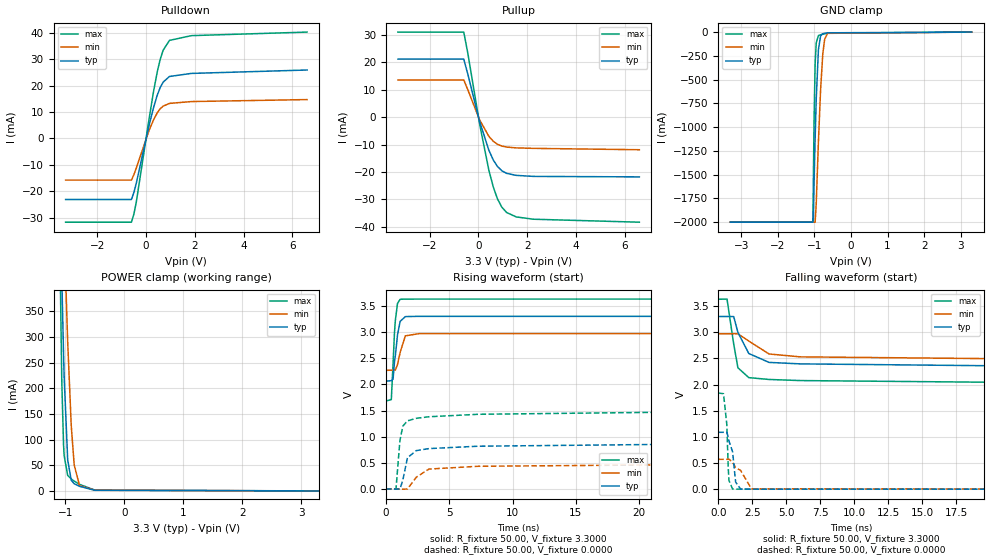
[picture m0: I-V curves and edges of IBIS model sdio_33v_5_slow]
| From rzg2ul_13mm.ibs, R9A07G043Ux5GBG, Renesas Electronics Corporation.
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[Model]   sdio_33v_5_slow
Model_type   I/O
Polarity   Non-Inverting
Enable   Active-Low
Vinl  =   0.8250V
Vinh  =   2.0625V
Vmeas =   1.6500V
Cref  =   10.00pF
| variable   typ   min   max
C_comp   2.652e-12  2.638e-12  2.667e-12
[Model Spec]
| Subparameter   typ   min   max
| Thresholds
Vinh   2.0625   1.8563   2.2688
Vinl   0.8250   0.7425   0.9075
| Timing Thresholds
Vmeas   1.6500   1.4850   1.8150
| variable   typ   min   max
[Temperature Range]   25.000   125.000   -40.000
| variable   typ   min   max
[Voltage Range]   3.300V   2.970V   3.630V
| variable   typ   min   max
[Pullup Reference]   3.300V   2.970V   3.630V
| variable   typ   min   max
[Pulldown Reference]   0.000V   0.000V   0.000V
| variable   typ   min   max
[POWER Clamp Reference] 3.300V   2.970V   3.630V
| variable   typ   min   max
[GND Clamp Reference]   0.000V   0.000V   0.000V
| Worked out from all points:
|   slope of the pulldown table from 0 to 0.495 V, typ, clamps not added: 28.6 ohm
|   slope of the pullup table from 0 to 0.495 V, typ, clamps not added: 36.7 ohm
|   GND clamp passes 1 mA (typ) near -0.46 V on its own axis
|   POWER clamp passes 1 mA (typ) near -0.48 V on its own axis
|   rising waveform, R_fixture 50.00, V_fixture 3.3000: 20-80 % time 344ps typ, 420ps min, 263ps max; typ from 2.06 V to 3.3 V
|   rising waveform, R_fixture 50.00, V_fixture 0.0000: 20-80 % time 24.7ns typ, 11.6ns min, 16.8ns max; typ from 0 V to 1.09 V
|   falling waveform, R_fixture 50.00, V_fixture 3.3000: 20-80 % time 38.6ns typ, 37.7ns min, 6.08ns max; typ from 3.3 V to 2.06 V
|   falling waveform, R_fixture 50.00, V_fixture 0.0000: 20-80 % time 409ps typ, 936ps min, 212ps max; typ from 1.09 V to 0 V
[Pulldown]
| sdio_33v_5_slow Pulldown S28FDSIO_IBIS
| Wed Sep  2 14:14:57 2020
| voltage   I(typ)   I(min)   I(max)
-3.3V     -23.12mA   -15.8mA    -31.72mA
-600mV    -23.12mA   -15.8mA    -31.72mA
-500mV    -20.5mA    -13.74mA   -28.68mA
-400mV    -16.94mA   -11.2mA    -24.08mA
130mV     5.187mA    3.183mA    7.785mA
310mV     11.76mA    7.08mA     17.91mA
460mV     16.38mA    9.682mA    25.23mA
580mV     19.24mA    11.2mA     29.91mA
700mV     21.28mA    12.21mA    33.35mA
960mV     23.43mA    13.24mA    37.08mA
1.86V     24.58mA    13.93mA    38.88mA
6.6V      25.87mA    14.68mA    40.22mA
[Pullup]
| sdio_33v_5_slow Pullup S28FDSIO_IBIS
| Wed Sep  2 14:14:57 2020
| voltage   I(typ)   I(min)   I(max)
-3.3V     21.11mA    13.53mA    30.96mA
-600mV    21.11mA    13.53mA    30.96mA
-430mV    15.5mA     9.851mA    23.1mA
50mV      -1.64mA    -1.004mA   -2.542mA
430mV     -12.1mA    -7.023mA   -19.4mA
610mV     -15.61mA   -8.81mA    -25.44mA
780mV     -17.97mA   -9.898mA   -29.74mA
960mV     -19.55mA   -10.55mA   -32.8mA
1.16V     -20.5mA    -10.92mA   -34.76mA
1.55V     -21.23mA   -11.21mA   -36.36mA
2.26V     -21.6mA    -11.39mA   -37.2mA
6.6V      -21.78mA   -11.89mA   -38.28mA
[GND Clamp]
| sdio_33v_5_slow GNDClamp S28FDSIO_IBIS
| Wed Sep  2 14:14:57 2020
| voltage   I(typ)   I(min)   I(max)
-3.3V     -2A        -2A        -2A
-1.04V    -2A        -2A        -2A
-1.03V    -1.932A    -2A        -1.644A
-1.01V    -1.591A    -2A        -948.6mA
-980mV    -1.118A    -2A        -336.7mA
-950mV    -708.6mA   -1.808A    -114.2mA
-890mV    -184.6mA   -1.154A    -36.66mA
-830mV    -39.24mA   -603.6mA   -27.52mA
-770mV    -17.34mA   -227.2mA   -22.11mA
-720mV    -12.52mA   -76.57mA   -17.89mA
-640mV    -7.709mA   -13.11mA   -11.55mA
3.3V      0A         0A         0A
[POWER Clamp]
| sdio_33v_5_slow PWRClamp S28FDSIO_IBIS
| Wed Sep  2 14:14:57 2020
| voltage   I(typ)   I(min)   I(max)
-3.3V     2A         2A         2A
-1.1V     651.8mA    840.5mA    559.9mA
-1.09V    589.7mA    796.8mA    454.6mA
-1.06V    415.3mA    668.7mA    212.9mA
-1.03V    265.3mA    545.8mA    89.35mA
-1.02V    222.5mA    506.3mA    68.83mA
-960mV    60.28mA    290mA      30.23mA
-900mV    20.85mA    127.6mA    23.26mA
-850mV    14.07mA    50.77mA    19.19mA
-760mV    8.961mA    10.58mA    12.81mA
-500mV    1.247mA    1.344mA    1.633mA
3.3V      0A         0A         0A
[Ramp]
dV/dt_r   0.652/23.771n   0.342/11.507n   1.104/16.397n
dV/dt_f   0.743/71.411n   0.422/600.338n  1.169/5.996n
R_load = 50.00ohm
[Rising Waveform]
| sdio_33v_5_slow Rising-High S28FDSIO_IBIS
| Wed Sep  2 14:14:57 2020
R_fixture = 50.00
V_fixture = 3.3000
V_fixture_min = 2.9700
V_fixture_max = 3.6300
C_fixture = 0.00pF
| Time   V(typ)   V(min)   V(max)
0s        2.061V     2.267V     1.682V
430ps     2.071V     2.271V     1.709V
570ps     2.102V     2.276V     2.398V
680ps     2.432V     2.275V     2.987V
750ps     2.549V     2.274V     3.225V
920ps     2.947V     2.379V     3.547V
1.13ns    3.205V     2.614V     3.626V
1.54ns    3.295V     2.927V     3.629V
2.62ns    3.3V       2.969V     3.63V
40ns      3.3V       2.97V      3.63V
[Rising Waveform]
| sdio_33v_5_slow Rising-Low S28FDSIO_IBIS
| Wed Sep  2 14:14:57 2020
R_fixture = 50.00
V_fixture = 0.0000
C_fixture = 0.00pF
| Time   V(typ)   V(min)   V(max)
0s        0V         0V         0V
800ps     -2.1mV     -1.7mV     3mV
1.11ns    -1.3mV     -800uV     928mV
1.34ns    169.2mV    -2.7mV     1.202V
1.7ns     597mV      -400uV     1.302V
2.4ns     734.1mV    226.5mV    1.351V
3.4ns     772.7mV    381.2mV    1.381V
7.27ns    817.9mV    434.7mV    1.428V
40ns      896.5mV    495mV      1.516V
40ns      1.087V     570.7mV    1.839V
[Falling Waveform]
| sdio_33v_5_slow Falling-High S28FDSIO_IBIS
| Wed Sep  2 14:14:57 2020
R_fixture = 50.00
V_fixture = 3.3000
V_fixture_min = 2.9700
V_fixture_max = 3.6300
C_fixture = 0.00pF
| Time   V(typ)   V(min)   V(max)
0s        3.3V       2.97V      3.63V
650ps     3.301V     2.97V      3.634V
1.14ns    3.299V     2.972V     2.774V
1.45ns    2.997V     2.971V     2.32V
2.25ns    2.593V     2.831V     2.132V
3.74ns    2.423V     2.584V     2.097V
6.04ns    2.395V     2.529V     2.076V
29ns      2.336V     2.473V     2.023V
40ns      2.323V     2.463V     1.682V
40ns      2.061V     2.267V     1.682V
[Falling Waveform]
| sdio_33v_5_slow Falling-Low S28FDSIO_IBIS
| Wed Sep  2 14:14:57 2020
R_fixture = 50.00
V_fixture = 0.0000
C_fixture = 0.00pF
| Time   V(typ)   V(min)   V(max)
0s        1.087V     570.7mV    1.839V
390ps     1.087V     570.7mV    1.825V
630ps     1.093V     570.7mV    1.244V
740ps     992.3mV    570mV      403.4mV
790ps     922.7mV    574.8mV    165.7mV
1.06ns    710.8mV    508.6mV    2.5mV
1.28ns    136.9mV    413.9mV    1.033mV
1.65ns    2.406mV    357.9mV    433uV
2.44ns    379uV      7.026mV    200uV
40ns      0V         0V         0V
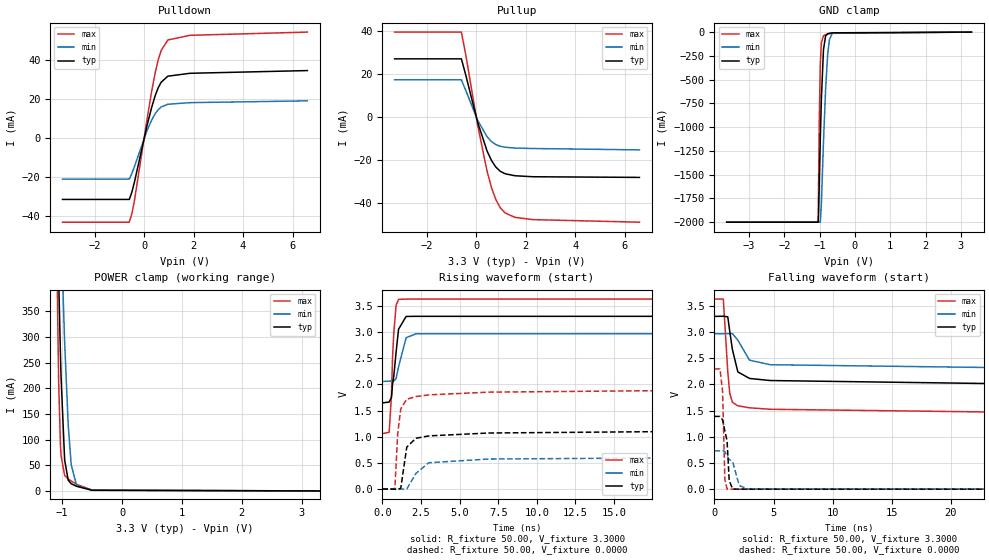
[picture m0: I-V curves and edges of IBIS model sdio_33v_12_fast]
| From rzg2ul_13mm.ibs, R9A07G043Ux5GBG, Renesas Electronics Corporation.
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[Model]   sdio_33v_12_fast
Model_type   I/O
Polarity   Non-Inverting
Enable   Active-Low
Vinl  =   0.8250V
Vinh  =   2.0625V
Vmeas =   1.6500V
Cref  =   10.00pF
| variable   typ   min   max
C_comp   2.652e-12  2.638e-12  2.667e-12
[Model Spec]
| Subparameter   typ   min   max
| Thresholds
Vinh   2.0625   1.8563   2.2688
Vinl   0.8250   0.7425   0.9075
| Timing Thresholds
Vmeas   1.6500   1.4850   1.8150
| variable   typ   min   max
[Temperature Range]   25.000   125.000   -40.000
| variable   typ   min   max
[Voltage Range]   3.300V   2.970V   3.630V
| variable   typ   min   max
[Pullup Reference]   3.300V   2.970V   3.630V
| variable   typ   min   max
[Pulldown Reference]   0.000V   0.000V   0.000V
| variable   typ   min   max
[POWER Clamp Reference] 3.300V   2.970V   3.630V
| variable   typ   min   max
[GND Clamp Reference]   0.000V   0.000V   0.000V
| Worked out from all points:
|   slope of the pulldown table from 0 to 0.495 V, typ, clamps not added: 21.1 ohm
|   slope of the pullup table from 0 to 0.495 V, typ, clamps not added: 28.5 ohm
|   GND clamp passes 1 mA (typ) near -0.46 V on its own axis
|   POWER clamp passes 1 mA (typ) near -0.48 V on its own axis
|   rising waveform, R_fixture 50.00, V_fixture 3.3000: 20-80 % time 352ps typ, 438ps min, 244ps max; typ from 1.65 V to 3.3 V
|   rising waveform, R_fixture 50.00, V_fixture 0.0000: 20-80 % time 15.9ns typ, 7.58ns min, 4.42ns max; typ from 0 V to 1.39 V
|   falling waveform, R_fixture 50.00, V_fixture 3.3000: 20-80 % time 33.7ns typ, 37.9ns min, 1.5ns max; typ from 3.3 V to 1.65 V
|   falling waveform, R_fixture 50.00, V_fixture 0.0000: 20-80 % time 333ps typ, 832ps min, 140ps max; typ from 1.39 V to 0 V
[Pulldown]
| sdio_33v_12_fast Pulldown S28FDSIO_IBIS
| Wed Sep  2 14:14:58 2020
| voltage   I(typ)   I(min)   I(max)
-3.3V     -31.5mA    -21.04mA   -43.19mA
-600mV    -31.5mA    -21.04mA   -43.19mA
-500mV    -27.92mA   -18.31mA   -39.05mA
-400mV    -23.07mA   -14.93mA   -32.78mA
120mV     6.529mA    3.916mA    9.795mA
300mV     15.53mA    9.105mA    23.65mA
450mV     21.88mA    12.57mA    33.71mA
570mV     25.85mA    14.61mA    40.19mA
690mV     28.7mA     15.97mA    44.99mA
960mV     31.78mA    17.37mA    50.37mA
1.85V     33.26mA    18.19mA    52.76mA
6.6V      34.66mA    19.11mA    54.42mA
[Pullup]
| sdio_33v_12_fast Pullup S28FDSIO_IBIS
| Wed Sep  2 14:14:58 2020
| voltage   I(typ)   I(min)   I(max)
-3.3V     27.19mA    17.41mA    39.67mA
-600mV    27.19mA    17.41mA    39.67mA
-430mV    19.95mA    12.67mA    29.55mA
60mV      -2.524mA   -1.542mA   -3.891mA
440mV     -15.85mA   -9.185mA   -25.31mA
620mV     -20.29mA   -11.44mA   -32.96mA
790mV     -23.28mA   -12.8mA    -38.4mA
970mV     -25.26mA   -13.61mA   -42.27mA
1.17V     -26.44mA   -14.06mA   -44.75mA
1.57V     -27.37mA   -14.43mA   -46.79mA
2.29V     -27.83mA   -14.66mA   -47.84mA
6.6V      -28.14mA   -15.29mA   -49.04mA
[GND Clamp]
| sdio_33v_12_fast GNDClamp S28FDSIO_IBIS
| Wed Sep  2 14:14:58 2020
| voltage   I(typ)   I(min)   I(max)
-3.63V    -2A        -2A        -2A
-1.04V    -2A        -2A        -2A
-1.03V    -1.932A    -2A        -1.644A
-1.01V    -1.591A    -2A        -948.6mA
-980mV    -1.118A    -2A        -336.7mA
-950mV    -708.6mA   -1.808A    -114.2mA
-890mV    -184.6mA   -1.154A    -36.66mA
-830mV    -39.24mA   -603.6mA   -27.52mA
-770mV    -17.34mA   -227.2mA   -22.11mA
-720mV    -12.52mA   -76.57mA   -17.89mA
-640mV    -7.709mA   -13.11mA   -11.55mA
3.3V      0A         0A         0A
[POWER Clamp]
| sdio_33v_12_fast PWRClamp S28FDSIO_IBIS
| Wed Sep  2 14:14:58 2020
| voltage   I(typ)   I(min)   I(max)
-3.3V     2A         2A         2A
-1.1V     651.8mA    840.5mA    559.9mA
-1.09V    589.7mA    796.8mA    454.6mA
-1.06V    415.3mA    668.7mA    212.9mA
-1.03V    265.3mA    545.8mA    89.35mA
-1.02V    222.5mA    506.3mA    68.83mA
-960mV    60.28mA    290mA      30.23mA
-900mV    20.85mA    127.6mA    23.26mA
-850mV    14.07mA    50.77mA    19.19mA
-760mV    8.961mA    10.58mA    12.81mA
-500mV    1.247mA    1.344mA    1.633mA
3.3V      0A         0A         0A
[Ramp]
dV/dt_r   0.834/15.824n   0.439/7.594n   1.378/4.406n
dV/dt_f   0.993/38.051n   0.549/167.583n  1.544/1.494n
R_load = 50.00ohm
[Rising Waveform]
| sdio_33v_12_fast Rising-High S28FDSIO_IBIS
| Wed Sep  2 14:14:58 2020
R_fixture = 50.00
V_fixture = 3.3000
V_fixture_min = 2.9700
V_fixture_max = 3.6300
C_fixture = 0.00pF
| Time   V(typ)   V(min)   V(max)
0s        1.645V     2.055V     1.058V
440ps     1.662V     2.06V      1.083V
590ps     1.751V     2.066V     1.789V
660ps     2.004V     2.065V     2.524V
740ps     2.156V     2.063V     2.973V
890ps     2.614V     2.109V     3.512V
1.05ns    3.055V     2.337V     3.624V
1.54ns    3.298V     2.892V     3.629V
2.18ns    3.3V       2.966V     3.63V
40ns      3.3V       2.97V      3.63V
[Rising Waveform]
| sdio_33v_12_fast Rising-Low S28FDSIO_IBIS
| Wed Sep  2 14:14:58 2020
R_fixture = 50.00
V_fixture = 0.0000
C_fixture = 0.00pF
| Time   V(typ)   V(min)   V(max)
0s        0V         0V         0V
810ps     -3.3mV     -1.7mV     2.4mV
990ps     -3.4mV     -2.2mV     1.044V
1.19ns    11.8mV     -1.6mV     1.532V
1.58ns    799.8mV    -1.2mV     1.715V
2.17ns    969.5mV    296.5mV    1.767V
3.01ns    1.015V     502.2mV    1.799V
6.89ns    1.07V      572.8mV    1.851V
40ns      1.149V     632.8mV    1.937V
40ns      1.39V      732.4mV    2.296V
[Falling Waveform]
| sdio_33v_12_fast Falling-High S28FDSIO_IBIS
| Wed Sep  2 14:14:58 2020
R_fixture = 50.00
V_fixture = 3.3000
V_fixture_min = 2.9700
V_fixture_max = 3.6300
C_fixture = 0.00pF
| Time   V(typ)   V(min)   V(max)
0s        3.3V       2.97V      3.63V
750ps     3.303V     2.968V     3.631V
1.13ns    3.291V     2.972V     2.24V
1.29ns    3.023V     2.97V      1.838V
1.52ns    2.668V     2.972V     1.659V
1.98ns    2.24V      2.845V     1.592V
2.97ns    2.115V     2.464V     1.554V
4.71ns    2.075V     2.377V     1.526V
40ns      1.965V     2.275V     1.427V
40ns      1.645V     2.055V     1.058V
[Falling Waveform]
| sdio_33v_12_fast Falling-Low S28FDSIO_IBIS
| Wed Sep  2 14:14:58 2020
R_fixture = 50.00
V_fixture = 0.0000
C_fixture = 0.00pF
| Time   V(typ)   V(min)   V(max)
0s        1.39V      732.4mV    2.296V
470ps     1.39V      732.4mV    2.298V
690ps     1.323V     734.3mV    1.867V
880ps     1.113V     721.6mV    187.9mV
1.07ns    921.7mV    629.2mV    2.8mV
1.25ns    163.9mV    569.1mV    900uV
1.54ns    2.577mV    526.7mV    500uV
2.1ns     400uV      69.06mV    300uV
2.85ns    230uV      819uV      200uV
40ns      0V         0V         0V
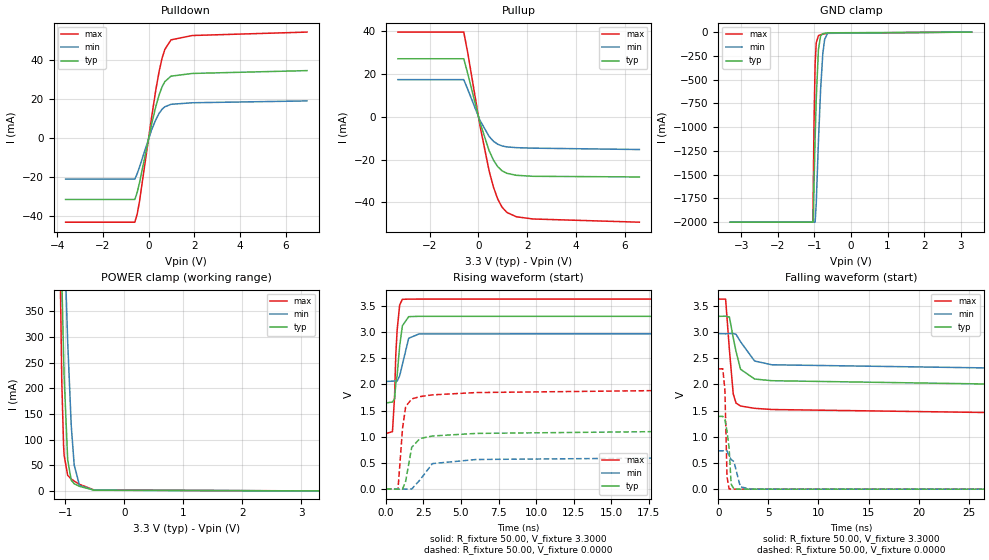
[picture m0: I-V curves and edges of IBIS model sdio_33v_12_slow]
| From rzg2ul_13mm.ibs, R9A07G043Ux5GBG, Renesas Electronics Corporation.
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[Model]   sdio_33v_12_slow
Model_type   I/O
Polarity   Non-Inverting
Enable   Active-Low
Vinl  =   0.8250V
Vinh  =   2.0625V
Vmeas =   1.6500V
Cref  =   10.00pF
| variable   typ   min   max
C_comp   2.652e-12  2.638e-12  2.667e-12
[Model Spec]
| Subparameter   typ   min   max
| Thresholds
Vinh   2.0625   1.8563   2.2688
Vinl   0.8250   0.7425   0.9075
| Timing Thresholds
Vmeas   1.6500   1.5000   1.8000
| variable   typ   min   max
[Temperature Range]   25.000   125.000   -40.000
| variable   typ   min   max
[Voltage Range]   3.300V   2.970V   3.630V
| variable   typ   min   max
[Pullup Reference]   3.300V   2.970V   3.630V
| variable   typ   min   max
[Pulldown Reference]   0.000V   0.000V   0.000V
| variable   typ   min   max
[POWER Clamp Reference] 3.300V   2.970V   3.630V
| variable   typ   min   max
[GND Clamp Reference]   0.000V   0.000V   0.000V
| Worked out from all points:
|   slope of the pulldown table from 0 to 0.495 V, typ, clamps not added: 21.1 ohm
|   slope of the pullup table from 0 to 0.495 V, typ, clamps not added: 28.5 ohm
|   GND clamp passes 1 mA (typ) near -0.46 V on its own axis
|   POWER clamp passes 1 mA (typ) near -0.48 V on its own axis
|   rising waveform, R_fixture 50.00, V_fixture 3.3000: 20-80 % time 355ps typ, 444ps min, 244ps max; typ from 1.65 V to 3.3 V
|   rising waveform, R_fixture 50.00, V_fixture 0.0000: 20-80 % time 16.1ns typ, 7.85ns min, 4.51ns max; typ from 0 V to 1.39 V
|   falling waveform, R_fixture 50.00, V_fixture 3.3000: 20-80 % time 37.1ns typ, 37.7ns min, 1.62ns max; typ from 3.3 V to 1.65 V
|   falling waveform, R_fixture 50.00, V_fixture 0.0000: 20-80 % time 340ps typ, 866ps min, 153ps max; typ from 1.39 V to 0 V
[Pulldown]
| sdio_33v_12_slow Pulldown S28FDSIO_IBIS
| Wed Sep  2 14:14:58 2020
| voltage   I(typ)   I(min)   I(max)
-3.63V    -31.5mA    -21.04mA   -43.19mA
-600mV    -31.5mA    -21.04mA   -43.19mA
-500mV    -27.92mA   -18.31mA   -39.05mA
-400mV    -23.07mA   -14.93mA   -32.78mA
130mV     7.056mA    4.227mA    10.6mA
310mV     15.99mA    9.364mA    24.37mA
460mV     22.25mA    12.77mA    34.31mA
590mV     26.4mA     14.88mA    41.11mA
710mV     29.07mA    16.14mA    45.63mA
980mV     31.89mA    17.42mA    50.56mA
1.91V     33.29mA    18.22mA    52.8mA
6.93V     34.75mA    19.17mA    54.56mA
[Pullup]
| sdio_33v_12_slow Pullup S28FDSIO_IBIS
| Wed Sep  2 14:14:58 2020
| voltage   I(typ)   I(min)   I(max)
-3.3V     27.19mA    17.41mA    39.67mA
-600mV    27.19mA    17.41mA    39.67mA
-430mV    19.95mA    12.67mA    29.55mA
60mV      -2.524mA   -1.542mA   -3.891mA
440mV     -15.85mA   -9.185mA   -25.31mA
620mV     -20.29mA   -11.44mA   -32.96mA
790mV     -23.28mA   -12.8mA    -38.4mA
970mV     -25.26mA   -13.61mA   -42.27mA
1.17V     -26.44mA   -14.06mA   -44.75mA
1.56V     -27.36mA   -14.42mA   -46.77mA
2.24V     -27.82mA   -14.65mA   -47.8mA
6.6V      -28.13mA   -15.29mA   -49.3mA
[GND Clamp]
| sdio_33v_12_slow GNDClamp S28FDSIO_IBIS
| Wed Sep  2 14:14:58 2020
| voltage   I(typ)   I(min)   I(max)
-3.3V     -2A        -2A        -2A
-1.04V    -2A        -2A        -2A
-1.03V    -1.932A    -2A        -1.644A
-1.01V    -1.591A    -2A        -948.6mA
-980mV    -1.118A    -2A        -336.7mA
-950mV    -708.6mA   -1.808A    -114.2mA
-890mV    -184.6mA   -1.154A    -36.66mA
-830mV    -39.24mA   -603.6mA   -27.52mA
-770mV    -17.34mA   -227.2mA   -22.11mA
-720mV    -12.52mA   -76.57mA   -17.89mA
-640mV    -7.709mA   -13.11mA   -11.55mA
3.3V      0A         0A         0A
[POWER Clamp]
| sdio_33v_12_slow PWRClamp S28FDSIO_IBIS
| Wed Sep  2 14:14:58 2020
| voltage   I(typ)   I(min)   I(max)
-3.3V     2A         2A         2A
-1.1V     651.8mA    840.5mA    559.9mA
-1.09V    589.7mA    796.8mA    454.6mA
-1.06V    415.3mA    668.7mA    212.9mA
-1.03V    265.3mA    545.8mA    89.35mA
-1.02V    222.5mA    506.3mA    68.83mA
-960mV    60.28mA    290mA      30.23mA
-900mV    20.85mA    127.6mA    23.26mA
-850mV    14.07mA    50.77mA    19.19mA
-760mV    8.961mA    10.58mA    12.81mA
-510mV    1.397mA    1.469mA    1.847mA
3.3V      0A         0A         0A
[Ramp]
dV/dt_r   0.834/15.988n   0.439/7.682n   1.378/4.453n
dV/dt_f   0.993/37.036n   0.549/167.248n  1.544/1.622n
R_load = 50.00ohm
[Rising Waveform]
| sdio_33v_12_slow Rising-High S28FDSIO_IBIS
| Wed Sep  2 14:14:58 2020
R_fixture = 50.00
V_fixture = 3.3000
V_fixture_min = 2.9700
V_fixture_max = 3.6300
C_fixture = 0.00pF
| Time   V(typ)   V(min)   V(max)
0s        1.645V     2.055V     1.058V
440ps     1.662V     2.061V     1.097V
580ps     1.722V     2.066V     1.764V
660ps     2.007V     2.065V     2.558V
750ps     2.168V     2.063V     3.033V
920ps     2.732V     2.164V     3.518V
1.1ns     3.119V     2.379V     3.625V
1.52ns    3.294V     2.881V     3.629V
2.21ns    3.3V       2.964V     3.63V
40ns      3.3V       2.97V      3.63V
[Rising Waveform]
| sdio_33v_12_slow Rising-Low S28FDSIO_IBIS
| Wed Sep  2 14:14:58 2020
R_fixture = 50.00
V_fixture = 0.0000
C_fixture = 0.00pF
| Time   V(typ)   V(min)   V(max)
0s        0V         0V         0V
810ps     -3.6mV     -1.7mV     100uV
1.11ns    -2mV       -400uV     1.159V
1.32ns    150.7mV    -3.5mV     1.575V
1.72ns    795.2mV    -500uV     1.721V
2.26ns    962.5mV    170mV      1.765V
3.1ns     1.013V     485.2mV    1.799V
6.02ns    1.062V     563.5mV    1.843V
40ns      1.16V      641.2mV    1.949V
40ns      1.39V      732.4mV    2.296V
[Falling Waveform]
| sdio_33v_12_slow Falling-High S28FDSIO_IBIS
| Wed Sep  2 14:14:58 2020
R_fixture = 50.00
V_fixture = 3.3000
V_fixture_min = 2.9700
V_fixture_max = 3.6300
C_fixture = 0.00pF
| Time   V(typ)   V(min)   V(max)
0s        3.3V       2.97V      3.63V
740ps     3.303V     2.967V     3.629V
1.12ns    3.287V     2.972V     2.657V
1.5ns     2.891V     2.972V     1.82V
1.78ns    2.628V     2.956V     1.643V
2.23ns    2.29V      2.814V     1.588V
3.63ns    2.103V     2.447V     1.544V
5.35ns    2.071V     2.375V     1.521V
40ns      1.969V     2.278V     1.428V
40ns      1.645V     2.055V     1.058V
[Falling Waveform]
| sdio_33v_12_slow Falling-Low S28FDSIO_IBIS
| Wed Sep  2 14:14:58 2020
R_fixture = 50.00
V_fixture = 0.0000
C_fixture = 0.00pF
| Time   V(typ)   V(min)   V(max)
0s        1.39V      732.4mV    2.296V
460ps     1.39V      732.4mV    2.299V
670ps     1.33V      732mV      1.886V
880ps     1.106V     730.3mV    234mV
1.09ns    786mV      631.3mV    4.12mV
1.29ns    97.2mV     566.6mV    1.1mV
1.57ns    3.067mV    526.4mV    500uV
2.21ns    550uV      44.23mV    257uV
3.31ns    230uV      642uV      106uV
40ns      0V         0V         0V
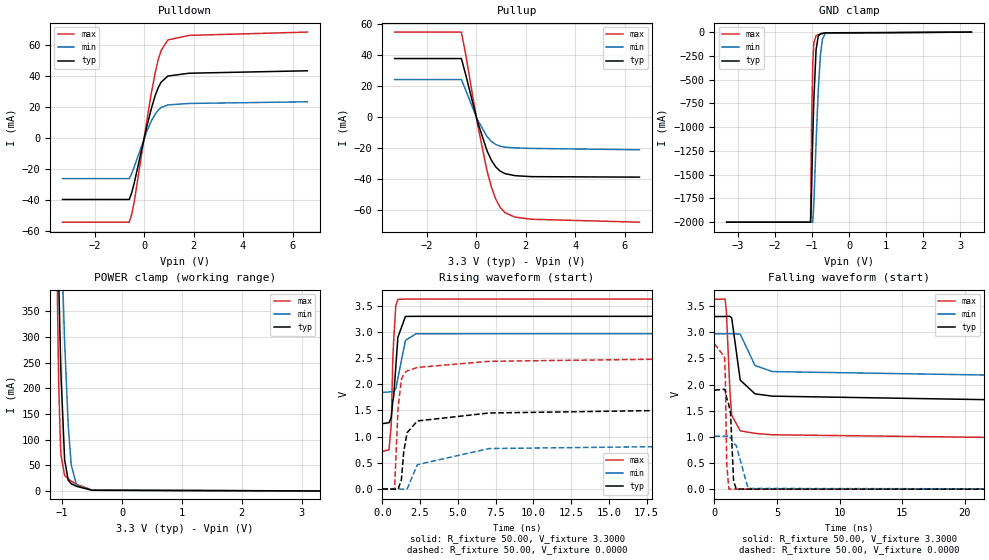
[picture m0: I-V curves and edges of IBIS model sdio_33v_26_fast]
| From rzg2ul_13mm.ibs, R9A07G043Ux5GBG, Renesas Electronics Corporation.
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[Model]   sdio_33v_26_fast
Model_type   I/O
Polarity   Non-Inverting
Enable   Active-Low
Vinl  =   0.8250V
Vinh  =   2.0625V
Vmeas =   1.6500V
Cref  =   10.00pF
| variable   typ   min   max
C_comp   2.652e-12  2.638e-12  2.667e-12
[Model Spec]
| Subparameter   typ   min   max
| Thresholds
Vinh   2.0625   1.8563   2.2688
Vinl   0.8250   0.7425   0.9075
| Timing Thresholds
Vmeas   1.6500   1.4850   1.8150
| variable   typ   min   max
[Temperature Range]   25.000   125.000   -40.000
| variable   typ   min   max
[Voltage Range]   3.300V   2.970V   3.630V
| variable   typ   min   max
[Pullup Reference]   3.300V   2.970V   3.630V
| variable   typ   min   max
[Pulldown Reference]   0.000V   0.000V   0.000V
| variable   typ   min   max
[POWER Clamp Reference] 3.300V   2.970V   3.630V
| variable   typ   min   max
[GND Clamp Reference]   0.000V   0.000V   0.000V
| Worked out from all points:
|   slope of the pulldown table from 0 to 0.495 V, typ, clamps not added: 16.7 ohm
|   slope of the pullup table from 0 to 0.495 V, typ, clamps not added: 20.5 ohm
|   GND clamp passes 1 mA (typ) near -0.46 V on its own axis
|   POWER clamp passes 1 mA (typ) near -0.48 V on its own axis
|   rising waveform, R_fixture 50.00, V_fixture 3.3000: 20-80 % time 343ps typ, 457ps min, 202ps max; typ from 1.25 V to 3.3 V
|   rising waveform, R_fixture 50.00, V_fixture 0.0000: 20-80 % time 14.3ns typ, 10.9ns min, 589ps max; typ from 0 V to 1.89 V
|   falling waveform, R_fixture 50.00, V_fixture 3.3000: 20-80 % time 25.7ns typ, 37.5ns min, 437ps max; typ from 3.3 V to 1.25 V
|   falling waveform, R_fixture 50.00, V_fixture 0.0000: 20-80 % time 215ps typ, 641ps min, 114ps max; typ from 1.89 V to 0 V
[Pulldown]
| sdio_33v_26_fast Pulldown S28FDSIO_IBIS
| Wed Sep  2 14:14:58 2020
| voltage   I(typ)   I(min)   I(max)
-3.3V     -39.77mA   -26.24mA   -54.49mA
-600mV    -39.77mA   -26.24mA   -54.49mA
-500mV    -35.24mA   -22.85mA   -49.26mA
-400mV    -29.1mA    -18.63mA   -41.35mA
120mV     8.242mA    4.883mA    12.37mA
300mV     19.61mA    11.33mA    29.85mA
450mV     27.65mA    15.61mA    42.55mA
570mV     32.67mA    18.12mA    50.72mA
690mV     36.29mA    19.79mA    56.79mA
960mV     40.2mA     21.49mA    63.59mA
1.82V     42.03mA    22.44mA    66.55mA
6.6V      43.61mA    23.52mA    68.68mA
[Pullup]
| sdio_33v_26_fast Pullup S28FDSIO_IBIS
| Wed Sep  2 14:14:58 2020
| voltage   I(typ)   I(min)   I(max)
-3.3V     37.9mA     24.28mA    55.06mA
-600mV    37.9mA     24.28mA    55.06mA
-430mV    27.78mA    17.65mA    40.96mA
50mV      -2.934mA   -1.797mA   -4.503mA
440mV     -22.02mA   -12.78mA   -35.08mA
620mV     -28.19mA   -15.91mA   -45.7mA
790mV     -32.34mA   -17.8mA    -53.26mA
970mV     -35.1mA    -18.93mA   -58.64mA
1.17V     -36.75mA   -19.56mA   -62.1mA
1.56V     -38.03mA   -20.05mA   -64.89mA
2.25V     -38.69mA   -20.37mA   -66.32mA
6.6V      -39mA      -21.25mA   -68.21mA
[GND Clamp]
| sdio_33v_26_fast GNDClamp S28FDSIO_IBIS
| Wed Sep  2 14:14:58 2020
| voltage   I(typ)   I(min)   I(max)
-3.3V     -2A        -2A        -2A
-1.04V    -2A        -2A        -2A
-1.03V    -1.932A    -2A        -1.644A
-1.01V    -1.591A    -2A        -948.6mA
-980mV    -1.118A    -2A        -336.7mA
-950mV    -708.6mA   -1.808A    -114.2mA
-890mV    -184.6mA   -1.154A    -36.66mA
-830mV    -39.24mA   -603.6mA   -27.52mA
-770mV    -17.34mA   -227.2mA   -22.11mA
-720mV    -12.52mA   -76.57mA   -17.89mA
-640mV    -7.709mA   -13.11mA   -11.55mA
3.3V      0A         0A         0A
[POWER Clamp]
| sdio_33v_26_fast PWRClamp S28FDSIO_IBIS
| Wed Sep  2 14:14:58 2020
| voltage   I(typ)   I(min)   I(max)
-3.3V     2A         2A         2A
-1.1V     651.8mA    840.5mA    559.9mA
-1.09V    589.7mA    796.8mA    454.6mA
-1.06V    415.3mA    668.7mA    212.9mA
-1.03V    265.3mA    545.8mA    89.35mA
-1.02V    222.5mA    506.3mA    68.83mA
-960mV    60.28mA    290mA      30.23mA
-900mV    20.85mA    127.6mA    23.26mA
-850mV    14.07mA    50.77mA    19.19mA
-760mV    8.961mA    10.58mA    12.81mA
-500mV    1.247mA    1.344mA    1.633mA
3.3V      0A         0A         0A
[Ramp]
dV/dt_r   1.135/14.245n   0.608/10.929n   1.668/588.764p
dV/dt_f   1.231/25.581n   0.675/100.158n  1.749/436.447p
R_load = 50.00ohm
[Rising Waveform]
| sdio_33v_26_fast Rising-High S28FDSIO_IBIS
| Wed Sep  2 14:14:58 2020
R_fixture = 50.00
V_fixture = 3.3000
V_fixture_min = 2.9700
V_fixture_max = 3.6300
C_fixture = 0.00pF
| Time   V(typ)   V(min)   V(max)
0s        1.248V     1.845V     715.8mV
440ps     1.267V     1.854V     749.6mV
590ps     1.363V     1.858V     1.233V
690ps     1.67V      1.856V     2.469V
750ps     1.767V     1.854V     2.842V
890ps     2.332V     1.917V     3.507V
1.03ns    2.901V     2.12V      3.624V
1.53ns    3.298V     2.841V     3.629V
2.23ns    3.3V       2.966V     3.63V
40ns      3.3V       2.97V      3.63V
[Rising Waveform]
| sdio_33v_26_fast Rising-Low S28FDSIO_IBIS
| Wed Sep  2 14:14:58 2020
R_fixture = 50.00
V_fixture = 0.0000
C_fixture = 0.00pF
| Time   V(typ)   V(min)   V(max)
0s        0V         0V         0V
810ps     -3.8mV     -1.6mV     -100uV
1.04ns    -3.9mV     -1mV       1.545V
1.26ns    174.3mV    -3.6mV     2.093V
1.42ns    721.2mV    -3.7mV     2.201V
1.64ns    1.076V     -1.3mV     2.258V
2.32ns    1.3V       465mV      2.323V
7.06ns    1.452V     772.3mV    2.44V
39.99ns   1.592V     880.7mV    2.558V
40ns      1.892V     1.013V     2.78V
[Falling Waveform]
| sdio_33v_26_fast Falling-High S28FDSIO_IBIS
| Wed Sep  2 14:14:58 2020
R_fixture = 50.00
V_fixture = 3.3000
V_fixture_min = 2.9700
V_fixture_max = 3.6300
C_fixture = 0.00pF
| Time   V(typ)   V(min)   V(max)
0s        3.3V       2.97V      3.63V
850ps     3.301V     2.97V      3.634V
950ps     3.302V     2.97V      3.412V
1.24ns    3.305V     2.972V     1.862V
1.38ns    3.27V      2.971V     1.411V
2.06ns    2.085V     2.964V     1.116V
3.24ns    1.822V     2.364V     1.066V
4.63ns    1.778V     2.248V     1.04V
39.99ns   1.639V     2.11V      936.2mV
40ns      1.248V     1.845V     715.8mV
[Falling Waveform]
| sdio_33v_26_fast Falling-Low S28FDSIO_IBIS
| Wed Sep  2 14:14:58 2020
R_fixture = 50.00
V_fixture = 0.0000
C_fixture = 0.00pF
| Time   V(typ)   V(min)   V(max)
0s        1.892V     1.013V     2.78V
810ps     1.91V      1.013V     2.522V
870ps     1.878V     1.013V     2.129V
980ps     1.743V     1.013V     489.6mV
1.15ns    1.611V     1.026V     4.71mV
1.29ns    1.44V      984.6mV    1.34mV
1.53ns    153.3mV    870.8mV    634uV
1.74ns    3.95mV     836mV      417uV
2.69ns    293uV      13.71mV    200uV
40ns      0V         0V         0V
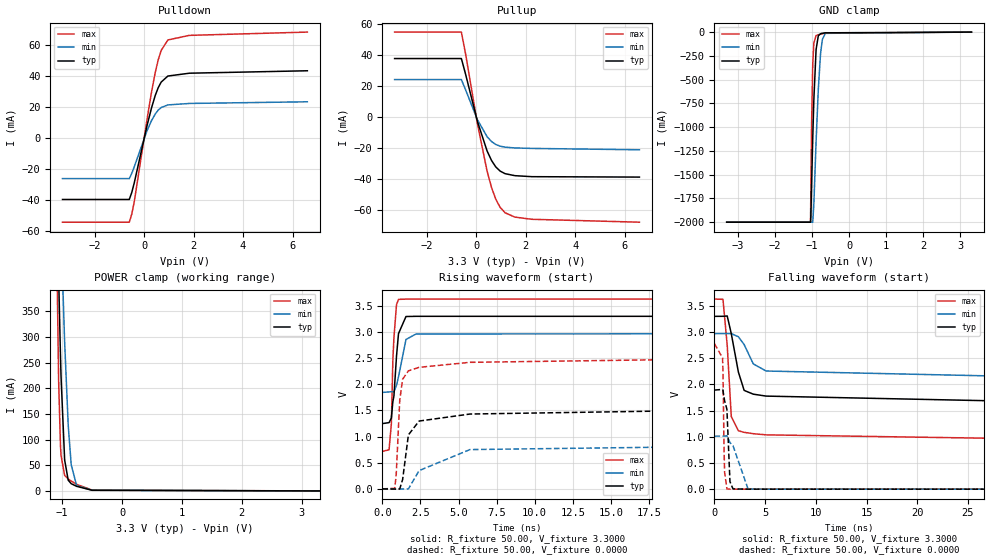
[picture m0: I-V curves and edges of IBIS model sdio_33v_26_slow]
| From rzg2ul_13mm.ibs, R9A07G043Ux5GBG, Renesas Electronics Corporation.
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[Model]   sdio_33v_26_slow
Model_type   I/O
Polarity   Non-Inverting
Enable   Active-Low
Vinl  =   0.8250V
Vinh  =   2.0625V
Vmeas =   1.6500V
Cref  =   10.00pF
| variable   typ   min   max
C_comp   2.652e-12  2.638e-12  2.667e-12
[Model Spec]
| Subparameter   typ   min   max
| Thresholds
Vinh   2.0625   1.8563   2.2688
Vinl   0.8250   0.7425   0.9075
| Timing Thresholds
Vmeas   1.6500   1.4850   1.8150
| variable   typ   min   max
[Temperature Range]   25.000   125.000   -40.000
| variable   typ   min   max
[Voltage Range]   3.300V   2.970V   3.630V
| variable   typ   min   max
[Pullup Reference]   3.300V   2.970V   3.630V
| variable   typ   min   max
[Pulldown Reference]   0.000V   0.000V   0.000V
| variable   typ   min   max
[POWER Clamp Reference] 3.300V   2.970V   3.630V
| variable   typ   min   max
[GND Clamp Reference]   0.000V   0.000V   0.000V
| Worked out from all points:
|   slope of the pulldown table from 0 to 0.495 V, typ, clamps not added: 16.7 ohm
|   slope of the pullup table from 0 to 0.495 V, typ, clamps not added: 20.5 ohm
|   GND clamp passes 1 mA (typ) near -0.46 V on its own axis
|   POWER clamp passes 1 mA (typ) near -0.48 V on its own axis
|   rising waveform, R_fixture 50.00, V_fixture 3.3000: 20-80 % time 341ps typ, 456ps min, 200ps max; typ from 1.25 V to 3.3 V
|   rising waveform, R_fixture 50.00, V_fixture 0.0000: 20-80 % time 14.2ns typ, 11.1ns min, 603ps max; typ from 0 V to 1.89 V
|   falling waveform, R_fixture 50.00, V_fixture 3.3000: 20-80 % time 26.2ns typ, 37ns min, 614ps max; typ from 3.3 V to 1.25 V
|   falling waveform, R_fixture 50.00, V_fixture 0.0000: 20-80 % time 214ps typ, 959ps min, 126ps max; typ from 1.89 V to 0 V
[Pulldown]
| sdio_33v_26_slow Pulldown S28FDSIO_IBIS
| Wed Sep  2 14:14:58 2020
| voltage   I(typ)   I(min)   I(max)
-3.3V     -39.77mA   -26.24mA   -54.49mA
-600mV    -39.77mA   -26.24mA   -54.49mA
-500mV    -35.24mA   -22.85mA   -49.26mA
-400mV    -29.1mA    -18.63mA   -41.35mA
120mV     8.242mA    4.882mA    12.36mA
300mV     19.61mA    11.33mA    29.84mA
450mV     27.65mA    15.61mA    42.54mA
570mV     32.67mA    18.12mA    50.71mA
690mV     36.29mA    19.79mA    56.78mA
960mV     40.2mA     21.49mA    63.57mA
1.83V     42.04mA    22.44mA    66.55mA
6.6V      43.62mA    23.52mA    68.68mA
[Pullup]
| sdio_33v_26_slow Pullup S28FDSIO_IBIS
| Wed Sep  2 14:14:58 2020
| voltage   I(typ)   I(min)   I(max)
-3.3V     37.9mA     24.28mA    55.06mA
-600mV    37.9mA     24.28mA    55.06mA
-430mV    27.78mA    17.65mA    40.96mA
50mV      -2.934mA   -1.797mA   -4.503mA
440mV     -22.02mA   -12.78mA   -35.08mA
620mV     -28.19mA   -15.91mA   -45.7mA
790mV     -32.34mA   -17.8mA    -53.26mA
970mV     -35.1mA    -18.93mA   -58.64mA
1.17V     -36.75mA   -19.56mA   -62.1mA
1.56V     -38.03mA   -20.05mA   -64.89mA
2.25V     -38.69mA   -20.37mA   -66.32mA
6.6V      -38.96mA   -21.25mA   -68.2mA
[GND Clamp]
| sdio_33v_26_slow GNDClamp S28FDSIO_IBIS
| Wed Sep  2 14:14:58 2020
| voltage   I(typ)   I(min)   I(max)
-3.3V     -2A        -2A        -2A
-1.04V    -2A        -2A        -2A
-1.03V    -1.932A    -2A        -1.644A
-1.01V    -1.591A    -2A        -948.6mA
-980mV    -1.118A    -2A        -336.7mA
-950mV    -708.6mA   -1.808A    -114.2mA
-890mV    -184.6mA   -1.154A    -36.66mA
-830mV    -39.24mA   -603.6mA   -27.52mA
-770mV    -17.34mA   -227.2mA   -22.11mA
-720mV    -12.52mA   -76.57mA   -17.89mA
-640mV    -7.709mA   -13.11mA   -11.55mA
3.3V      0A         0A         0A
[POWER Clamp]
| sdio_33v_26_slow PWRClamp S28FDSIO_IBIS
| Wed Sep  2 14:14:58 2020
| voltage   I(typ)   I(min)   I(max)
-3.3V     2A         2A         2A
-1.1V     651.8mA    840.5mA    559.9mA
-1.09V    589.7mA    796.8mA    454.6mA
-1.06V    415.3mA    668.7mA    212.9mA
-1.03V    265.3mA    545.8mA    89.35mA
-1.02V    222.5mA    506.3mA    68.83mA
-960mV    60.28mA    290mA      30.23mA
-900mV    20.85mA    127.6mA    23.26mA
-850mV    14.07mA    50.77mA    19.19mA
-760mV    8.961mA    10.58mA    12.81mA
-500mV    1.247mA    1.344mA    1.633mA
3.3V      0A         0A         0A
[Ramp]
dV/dt_r   1.135/14.140n   0.608/11.039n   1.668/603.338p
dV/dt_f   1.231/25.831n   0.675/102.392n  1.749/613.050p
R_load = 50.00ohm
[Rising Waveform]
| sdio_33v_26_slow Rising-High S28FDSIO_IBIS
| Wed Sep  2 14:14:58 2020
R_fixture = 50.00
V_fixture = 3.3000
V_fixture_min = 2.9700
V_fixture_max = 3.6300
C_fixture = 0.00pF
| Time   V(typ)   V(min)   V(max)
0s        1.248V     1.845V     715.8mV
440ps     1.267V     1.854V     748.2mV
590ps     1.354V     1.858V     1.24V
690ps     1.669V     1.856V     2.467V
760ps     1.778V     1.854V     2.893V
930ps     2.542V     1.982V     3.524V
1.06ns    2.969V     2.144V     3.624V
1.55ns    3.296V     2.857V     3.629V
2.21ns    3.3V       2.962V     3.63V
40ns      3.3V       2.97V      3.63V
[Rising Waveform]
| sdio_33v_26_slow Rising-Low S28FDSIO_IBIS
| Wed Sep  2 14:14:58 2020
R_fixture = 50.00
V_fixture = 0.0000
C_fixture = 0.00pF
| Time   V(typ)   V(min)   V(max)
0s        0V         0V         0V
810ps     -3.9mV     -1.6mV     9.7mV
910ps     -5.8mV     -2.3mV     272.5mV
1.14ns    -1.9mV     -200uV     1.691V
1.33ns    178.6mV    -4.3mV     2.097V
1.71ns    1.032V     -900uV     2.257V
2.41ns    1.297V     349mV      2.324V
5.75ns    1.431V     751.3mV    2.42V
39.99ns   1.587V     876mV      2.555V
40ns      1.892V     1.013V     2.78V
[Falling Waveform]
| sdio_33v_26_slow Falling-High S28FDSIO_IBIS
| Wed Sep  2 14:14:58 2020
R_fixture = 50.00
V_fixture = 3.3000
V_fixture_min = 2.9700
V_fixture_max = 3.6300
C_fixture = 0.00pF
| Time   V(typ)   V(min)   V(max)
0s        3.3V       2.97V      3.63V
840ps     3.301V     2.97V      3.625V
1.26ns    3.307V     2.971V     2.745V
1.66ns    2.971V     2.97V      1.387V
2.36ns    2.237V     2.911V     1.115V
2.93ns    1.886V     2.761V     1.085V
3.83ns    1.814V     2.392V     1.059V
5.1ns     1.777V     2.256V     1.037V
39.99ns   1.636V     2.108V     934mV
40ns      1.248V     1.845V     715.8mV
[Falling Waveform]
| sdio_33v_26_slow Falling-Low S28FDSIO_IBIS
| Wed Sep  2 14:14:58 2020
R_fixture = 50.00
V_fixture = 0.0000
C_fixture = 0.00pF
| Time   V(typ)   V(min)   V(max)
0s        1.892V     1.013V     2.78V
800ps     1.905V     1.013V     2.505V
840ps     1.883V     1.013V     2.261V
940ps     1.76V      1.013V     854.8mV
1ns       1.69V      1.013V     327.2mV
1.23ns    1.525V     1.022V     4.66mV
1.53ns    144mV      888.4mV    895uV
1.83ns    5.006mV    830.6mV    400uV
3.32ns    275uV      1.56mV     117uV
40ns      0V         0V         0V
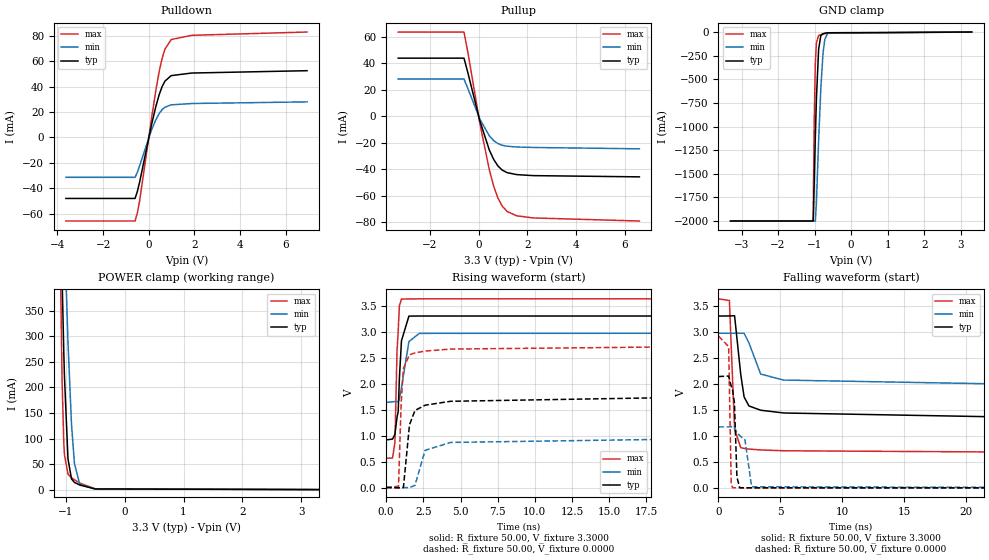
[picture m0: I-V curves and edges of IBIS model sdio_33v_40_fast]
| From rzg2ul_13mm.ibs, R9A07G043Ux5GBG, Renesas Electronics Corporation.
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[Model]   sdio_33v_40_fast
Model_type   I/O
Polarity   Non-Inverting
Enable   Active-Low
Vinl  =   0.8250V
Vinh  =   2.0625V
Vmeas =   1.6500V
Cref  =   10.00pF
| variable   typ   min   max
C_comp   2.652e-12  2.638e-12  2.667e-12
[Model Spec]
| Subparameter   typ   min   max
| Thresholds
Vinh   2.0625   1.8563   2.2688
Vinl   0.8250   0.7425   0.9075
| Timing Thresholds
Vmeas   1.6500   1.4850   1.8150
| variable   typ   min   max
[Temperature Range]   25.000   125.000   -40.000
| variable   typ   min   max
[Voltage Range]   3.300V   2.970V   3.630V
| variable   typ   min   max
[Pullup Reference]   3.300V   2.970V   3.630V
| variable   typ   min   max
[Pulldown Reference]   0.000V   0.000V   0.000V
| variable   typ   min   max
[POWER Clamp Reference] 3.300V   2.970V   3.630V
| variable   typ   min   max
[GND Clamp Reference]   0.000V   0.000V   0.000V
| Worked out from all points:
|   slope of the pulldown table from 0 to 0.495 V, typ, clamps not added: 13.8 ohm
|   slope of the pullup table from 0 to 0.495 V, typ, clamps not added: 17.7 ohm
|   GND clamp passes 1 mA (typ) near -0.46 V on its own axis
|   POWER clamp passes 1 mA (typ) near -0.48 V on its own axis
|   rising waveform, R_fixture 50.00, V_fixture 3.3000: 20-80 % time 255ps typ, 443ps min, 190ps max; typ from 0.916 V to 3.3 V
|   rising waveform, R_fixture 50.00, V_fixture 0.0000: 20-80 % time 6.41ns typ, 8.14ns min, 286ps max; typ from 0 V to 2.14 V
|   falling waveform, R_fixture 50.00, V_fixture 3.3000: 20-80 % time 7.65ns typ, 37.5ns min, 290ps max; typ from 3.3 V to 0.916 V
|   falling waveform, R_fixture 50.00, V_fixture 0.0000: 20-80 % time 186ps typ, 458ps min, 103ps max; typ from 2.14 V to 0 V
[Pulldown]
| sdio_33v_40_fast Pulldown S28FDSIO_IBIS
| Wed Sep  2 14:14:58 2020
| voltage   I(typ)   I(min)   I(max)
-3.63V    -48.07mA   -31.43mA   -65.86mA
-600mV    -48.07mA   -31.43mA   -65.86mA
-500mV    -42.57mA   -27.37mA   -59.51mA
-400mV    -35.15mA   -22.32mA   -49.94mA
130mV     10.75mA    6.302mA    16.14mA
310mV     24.37mA    13.91mA    37.13mA
460mV     33.93mA    18.91mA    52.27mA
590mV     40.27mA    22mA       62.64mA
710mV     44.37mA    23.83mA    69.55mA
980mV     48.68mA    25.66mA    77.11mA
1.88V     50.72mA    26.71mA    80.45mA
6.93V     52.57mA    28mA       83.03mA
[Pullup]
| sdio_33v_40_fast Pullup S28FDSIO_IBIS
| Wed Sep  2 14:14:58 2020
| voltage   I(typ)   I(min)   I(max)
-3.3V     43.92mA    28.14mA    63.68mA
-600mV    43.92mA    28.14mA    63.68mA
-430mV    32.17mA    20.45mA    47.33mA
50mV      -3.399mA   -2.082mA   -5.202mA
440mV     -25.53mA   -14.82mA   -40.57mA
620mV     -32.69mA   -18.45mA   -52.88mA
790mV     -37.52mA   -20.65mA   -61.67mA
970mV     -40.73mA   -21.96mA   -67.96mA
1.17V     -42.65mA   -22.69mA   -72mA
1.56V     -44.14mA   -23.26mA   -75.27mA
2.24V     -44.91mA   -23.62mA   -76.92mA
6.6V      -45.85mA   -24.64mA   -79.24mA
[GND Clamp]
| sdio_33v_40_fast GNDClamp S28FDSIO_IBIS
| Wed Sep  2 14:14:58 2020
| voltage   I(typ)   I(min)   I(max)
-3.3V     -2A        -2A        -2A
-1.04V    -2A        -2A        -2A
-1.03V    -1.932A    -2A        -1.644A
-1.01V    -1.591A    -2A        -948.6mA
-980mV    -1.118A    -2A        -336.7mA
-950mV    -708.6mA   -1.808A    -114.2mA
-890mV    -184.6mA   -1.154A    -36.66mA
-830mV    -39.24mA   -603.6mA   -27.52mA
-770mV    -17.34mA   -227.2mA   -22.11mA
-720mV    -12.52mA   -76.57mA   -17.89mA
-640mV    -7.709mA   -13.11mA   -11.55mA
3.3V      0A         0A         0A
[POWER Clamp]
| sdio_33v_40_fast PWRClamp S28FDSIO_IBIS
| Wed Sep  2 14:14:58 2020
| voltage   I(typ)   I(min)   I(max)
-3.3V     2A         2A         2A
-1.1V     651.8mA    840.5mA    559.9mA
-1.09V    589.7mA    796.8mA    454.6mA
-1.06V    415.3mA    668.7mA    212.9mA
-1.03V    265.3mA    545.8mA    89.35mA
-1.02V    222.5mA    506.3mA    68.83mA
-960mV    60.28mA    290mA      30.23mA
-900mV    20.85mA    127.6mA    23.26mA
-850mV    14.07mA    50.77mA    19.19mA
-760mV    8.961mA    10.58mA    12.81mA
-500mV    1.247mA    1.344mA    1.633mA
3.3V      0A         0A         0A
[Ramp]
dV/dt_r   1.283/6.392n   0.703/7.855n   1.750/286.191p
dV/dt_f   1.430/7.438n   0.799/64.403n   1.840/289.766p
R_load = 50.00ohm
[Rising Waveform]
| sdio_33v_40_fast Rising-High S28FDSIO_IBIS
| Wed Sep  2 14:14:58 2020
R_fixture = 50.00
V_fixture = 3.3000
V_fixture_min = 2.9700
V_fixture_max = 3.6300
C_fixture = 0.00pF
| Time   V(typ)   V(min)   V(max)
0s        916.5mV    1.638V     563mV
430ps     931.5mV    1.649V     568.2mV
590ps     1.023V     1.654V     869.3mV
730ps     1.347V     1.648V     2.619V
810ps     1.463V     1.652V     3.012V
890ps     2.104V     1.703V     3.497V
1.03ns    2.824V     1.923V     3.626V
1.53ns    3.298V     2.808V     3.629V
2.23ns    3.3V       2.966V     3.63V
40ns      3.3V       2.97V      3.63V
[Rising Waveform]
| sdio_33v_40_fast Rising-Low S28FDSIO_IBIS
| Wed Sep  2 14:14:58 2020
R_fixture = 50.00
V_fixture = 0.0000
C_fixture = 0.00pF
| Time   V(typ)   V(min)   V(max)
0s        0V         0V         0V
830ps     -6.5mV     -1.7mV     23.9mV
1.01ns    -5.3mV     -1.2mV     1.628V
1.16ns    -2mV       -500uV     2.292V
1.57ns    1.209V     -2.5mV     2.554V
1.94ns    1.483V     42mV       2.591V
2.62ns    1.584V     715.9mV    2.625V
4.33ns    1.659V     867.2mV    2.664V
40ns      1.831V     1.016V     2.764V
40ns      2.138V     1.171V     2.917V
[Falling Waveform]
| sdio_33v_40_fast Falling-High S28FDSIO_IBIS
| Wed Sep  2 14:14:58 2020
R_fixture = 50.00
V_fixture = 3.3000
V_fixture_min = 2.9700
V_fixture_max = 3.6300
C_fixture = 0.00pF
| Time   V(typ)   V(min)   V(max)
0s        3.3V       2.97V      3.63V
880ps     3.302V     2.97V      3.599V
1.3ns     3.306V     2.971V     1.129V
1.8ns     2.175V     2.971V     771.8mV
2.07ns    1.747V     2.968V     757.2mV
2.46ns    1.573V     2.784V     744.7mV
3.41ns    1.491V     2.185V     728.3mV
5.28ns    1.438V     2.07V      712.2mV
40ns      1.288V     1.921V     665mV
40ns      916.5mV    1.638V     563mV
[Falling Waveform]
| sdio_33v_40_fast Falling-Low S28FDSIO_IBIS
| Wed Sep  2 14:14:58 2020
R_fixture = 50.00
V_fixture = 0.0000
C_fixture = 0.00pF
| Time   V(typ)   V(min)   V(max)
0s        2.138V     1.171V     2.917V
820ps     2.147V     1.171V     2.713V
1.03ns    1.95V      1.171V     74.56mV
1.13ns    1.898V     1.186V     4.84mV
1.29ns    1.625V     1.165V     1.24mV
1.49ns    207.9mV    1.061V     600uV
1.71ns    3.581mV    1.004V     400uV
2.14ns    568uV      922.6mV    260uV
2.68ns    277uV      20.71mV    200uV
40ns      0V         0V         0V
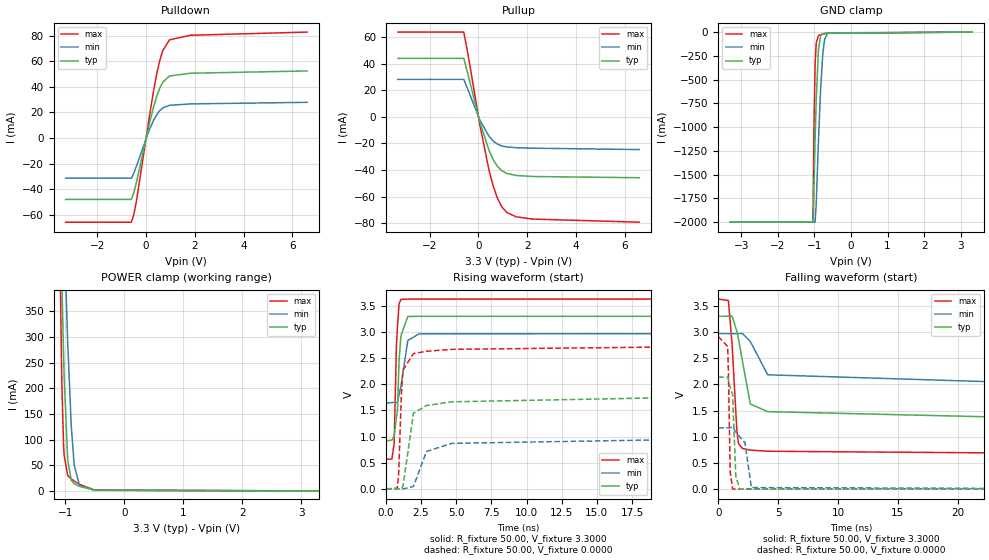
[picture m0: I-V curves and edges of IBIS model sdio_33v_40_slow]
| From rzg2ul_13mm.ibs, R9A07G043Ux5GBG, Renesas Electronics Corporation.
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[Model]   sdio_33v_40_slow
Model_type   I/O
Polarity   Non-Inverting
Enable   Active-Low
Vinl  =   0.8250V
Vinh  =   2.0625V
Vmeas =   1.6500V
Cref  =   10.00pF
| variable   typ   min   max
C_comp   2.652e-12  2.638e-12  2.667e-12
[Model Spec]
| Subparameter   typ   min   max
| Thresholds
Vinh   2.0625   1.8563   2.2688
Vinl   0.8250   0.7425   0.9075
| Timing Thresholds
Vmeas   1.6500   1.4850   1.8150
| variable   typ   min   max
[Temperature Range]   25.000   125.000   -40.000
| variable   typ   min   max
[Voltage Range]   3.300V   2.970V   3.630V
| variable   typ   min   max
[Pullup Reference]   3.300V   2.970V   3.630V
| variable   typ   min   max
[Pulldown Reference]   0.000V   0.000V   0.000V
| variable   typ   min   max
[POWER Clamp Reference] 3.300V   2.970V   3.630V
| variable   typ   min   max
[GND Clamp Reference]   0.000V   0.000V   0.000V
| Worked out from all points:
|   slope of the pulldown table from 0 to 0.495 V, typ, clamps not added: 13.8 ohm
|   slope of the pullup table from 0 to 0.495 V, typ, clamps not added: 17.7 ohm
|   GND clamp passes 1 mA (typ) near -0.46 V on its own axis
|   POWER clamp passes 1 mA (typ) near -0.48 V on its own axis
|   rising waveform, R_fixture 50.00, V_fixture 3.3000: 20-80 % time 255ps typ, 443ps min, 187ps max; typ from 0.916 V to 3.3 V
|   rising waveform, R_fixture 50.00, V_fixture 0.0000: 20-80 % time 6.59ns typ, 7.99ns min, 300ps max; typ from 0 V to 2.14 V
|   falling waveform, R_fixture 50.00, V_fixture 3.3000: 20-80 % time 8.05ns typ, 37.1ns min, 462ps max; typ from 3.3 V to 0.916 V
|   falling waveform, R_fixture 50.00, V_fixture 0.0000: 20-80 % time 199ps typ, 483ps min, 126ps max; typ from 2.14 V to 0 V
[Pulldown]
| sdio_33v_40_slow Pulldown S28FDSIO_IBIS
| Wed Sep  2 14:14:58 2020
| voltage   I(typ)   I(min)   I(max)
-3.3V     -48.07mA   -31.43mA   -65.86mA
-600mV    -48.07mA   -31.43mA   -65.86mA
-500mV    -42.57mA   -27.37mA   -59.51mA
-400mV    -35.15mA   -22.32mA   -49.94mA
120mV     9.948mA    5.839mA    14.92mA
300mV     23.67mA    13.52mA    36.03mA
450mV     33.36mA    18.62mA    51.36mA
570mV     39.43mA    21.6mA     61.23mA
690mV     43.8mA     23.59mA    68.58mA
960mV     48.52mA    25.59mA    76.82mA
1.82V     50.68mA    26.68mA    80.39mA
6.6V      52.46mA    27.92mA    82.87mA
[Pullup]
| sdio_33v_40_slow Pullup S28FDSIO_IBIS
| Wed Sep  2 14:14:58 2020
| voltage   I(typ)   I(min)   I(max)
-3.3V     43.92mA    28.14mA    63.68mA
-600mV    43.92mA    28.14mA    63.68mA
-430mV    32.17mA    20.45mA    47.33mA
50mV      -3.399mA   -2.082mA   -5.202mA
440mV     -25.53mA   -14.82mA   -40.57mA
620mV     -32.69mA   -18.45mA   -52.88mA
790mV     -37.52mA   -20.65mA   -61.67mA
970mV     -40.73mA   -21.96mA   -67.96mA
1.17V     -42.65mA   -22.69mA   -72mA
1.55V     -44.12mA   -23.25mA   -75.23mA
2.23V     -44.9mA    -23.62mA   -76.91mA
6.6V      -45.83mA   -24.64mA   -79.25mA
[GND Clamp]
| sdio_33v_40_slow GNDClamp S28FDSIO_IBIS
| Wed Sep  2 14:14:58 2020
| voltage   I(typ)   I(min)   I(max)
-3.3V     -2A        -2A        -2A
-1.04V    -2A        -2A        -2A
-1.03V    -1.932A    -2A        -1.644A
-1.01V    -1.591A    -2A        -948.6mA
-980mV    -1.118A    -2A        -336.7mA
-950mV    -708.6mA   -1.808A    -114.2mA
-890mV    -184.6mA   -1.154A    -36.66mA
-830mV    -39.24mA   -603.6mA   -27.52mA
-770mV    -17.34mA   -227.2mA   -22.11mA
-720mV    -12.52mA   -76.57mA   -17.89mA
-640mV    -7.709mA   -13.11mA   -11.55mA
3.3V      0A         0A         0A
[POWER Clamp]
| sdio_33v_40_slow PWRClamp S28FDSIO_IBIS
| Wed Sep  2 14:14:58 2020
| voltage   I(typ)   I(min)   I(max)
-3.3V     2A         2A         2A
-1.1V     651.8mA    840.5mA    559.9mA
-1.09V    589.7mA    796.8mA    454.6mA
-1.06V    415.3mA    668.7mA    212.9mA
-1.03V    265.3mA    545.8mA    89.35mA
-1.02V    222.5mA    506.3mA    68.83mA
-960mV    60.28mA    290mA      30.23mA
-900mV    20.85mA    127.6mA    23.26mA
-850mV    14.07mA    50.77mA    19.19mA
-760mV    8.961mA    10.58mA    12.81mA
-500mV    1.247mA    1.344mA    1.633mA
3.3V      0A         0A         0A
[Ramp]
dV/dt_r   1.283/6.510n   0.703/7.983n   1.750/299.670p
dV/dt_f   1.430/7.889n   0.799/61.640n   1.840/461.437p
R_load = 50.00ohm
[Rising Waveform]
| sdio_33v_40_slow Rising-High S28FDSIO_IBIS
| Wed Sep  2 14:14:58 2020
R_fixture = 50.00
V_fixture = 3.3000
V_fixture_min = 2.9700
V_fixture_max = 3.6300
C_fixture = 0.00pF
| Time   V(typ)   V(min)   V(max)
0s        916.5mV    1.638V     563mV
430ps     931.6mV    1.649V     570.2mV
590ps     1.009V     1.654V     865.5mV
750ps     1.365V     1.648V     2.733V
820ps     1.484V     1.655V     3.078V
940ps     2.453V     1.802V     3.539V
1.07ns    2.928V     1.958V     3.624V
1.56ns    3.296V     2.837V     3.629V
2.36ns    3.3V       2.965V     3.63V
40ns      3.3V       2.97V      3.63V
[Rising Waveform]
| sdio_33v_40_slow Rising-Low S28FDSIO_IBIS
| Wed Sep  2 14:14:58 2020
R_fixture = 50.00
V_fixture = 0.0000
C_fixture = 0.00pF
| Time   V(typ)   V(min)   V(max)
0s        0V         0V         0V
810ps     -4.5mV     -1.5mV     9.9mV
910ps     -7.3mV     -2.1mV     282.8mV
1.1ns     -3.3mV     -200uV     1.783V
1.22ns    51.5mV     -3.4mV     2.273V
1.96ns    1.444V     44.2mV     2.587V
2.89ns    1.593V     714.3mV    2.631V
4.69ns    1.664V     869mV      2.668V
40ns      1.846V     1.029V     2.772V
40ns      2.138V     1.171V     2.917V
[Falling Waveform]
| sdio_33v_40_slow Falling-High S28FDSIO_IBIS
| Wed Sep  2 14:14:58 2020
R_fixture = 50.00
V_fixture = 3.3000
V_fixture_min = 2.9700
V_fixture_max = 3.6300
C_fixture = 0.00pF
| Time   V(typ)   V(min)   V(max)
0s        3.3V       2.97V      3.63V
850ps     3.302V     2.97V      3.603V
1.16ns    3.304V     2.968V     2.769V
1.56ns    3.012V     2.971V     1.107V
1.7ns     2.863V     2.97V      868.1mV
2.03ns    2.436V     2.971V     776.1mV
2.68ns    1.626V     2.821V     746.8mV
4.13ns    1.48V      2.184V     724mV
40ns      1.288V     1.928V     664.2mV
40ns      916.5mV    1.638V     563mV
[Falling Waveform]
| sdio_33v_40_slow Falling-Low S28FDSIO_IBIS
| Wed Sep  2 14:14:58 2020
R_fixture = 50.00
V_fixture = 0.0000
C_fixture = 0.00pF
| Time   V(typ)   V(min)   V(max)
0s        2.138V     1.171V     2.917V
790ps     2.142V     1.171V     2.725V
850ps     2.095V     1.171V     2.261V
1ns       1.944V     1.171V     334.4mV
1.2ns     1.809V     1.189V     4.84mV
1.47ns    250mV      1.091V     1.095mV
1.79ns    4.023mV    1V         400uV
2.23ns    900uV      887.6mV    200uV
2.77ns    357uV      31mV       200uV
40ns      0V         0V         0V
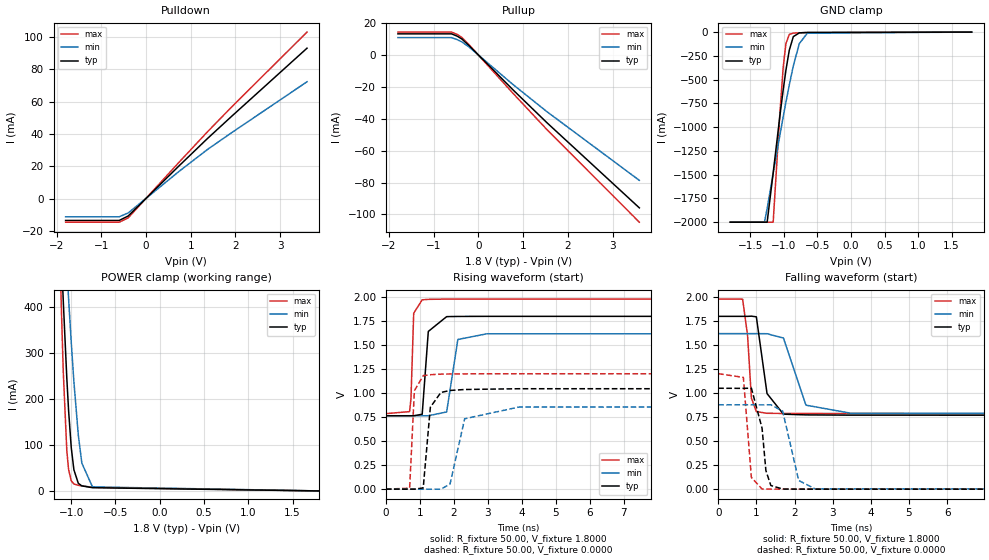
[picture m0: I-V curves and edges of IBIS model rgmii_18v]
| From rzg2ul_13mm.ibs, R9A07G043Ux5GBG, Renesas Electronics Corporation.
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[Model]   rgmii_18v
Model_type   I/O
Polarity   Non-Inverting
Enable   Active-Low
Vinl  =   0.5400V
Vinh  =   1.2600V
Vmeas =   0.9000V
Cref  =   5.00pF
| variable   typ   min   max
C_comp   1.297pF   1.197pF   1.397pF
[Model Spec]
| Subparameter   typ   min   max
| Thresholds
Vinh   1.2600   1.1340   1.3860
Vinl   0.5400   0.4860   0.5940
| Timing Thresholds
Vmeas   0.9000   0.8100   0.9900
| variable   typ   min   max
[Temperature Range]   25.000   125.000   -40.000
| variable   typ   min   max
[Voltage Range]   1.800V   1.620V   1.980V
| variable   typ   min   max
[Pullup Reference]   1.800V   1.620V   1.980V
| variable   typ   min   max
[Pulldown Reference]   0.000V   0.000V   0.000V
| variable   typ   min   max
[POWER Clamp Reference] 1.800V   1.620V   1.980V
| variable   typ   min   max
[GND Clamp Reference]   0.000V   0.000V   0.000V
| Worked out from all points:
|   slope of the pulldown table from 0 to 0.27 V, typ, clamps not added: 36.2 ohm
|   slope of the pullup table from 0 to 0.27 V, typ, clamps not added: 35.2 ohm
|   GND clamp passes 1 mA (typ) near -0.47 V on its own axis
|   POWER clamp passes 1 mA (typ) near -0.43 V on its own axis
|   rising waveform, R_fixture 50.00, V_fixture 1.8000: 20-80 % time 90.9ps typ, 163ps min, 54.8ps max; typ from 0.764 V to 1.8 V
|   rising waveform, R_fixture 50.00, V_fixture 0.0000: 20-80 % time 121ps typ, 297ps min, 64.8ps max; typ from 0 V to 1.05 V
|   falling waveform, R_fixture 50.00, V_fixture 1.8000: 20-80 % time 169ps typ, 344ps min, 123ps max; typ from 1.8 V to 0.764 V
|   falling waveform, R_fixture 50.00, V_fixture 0.0000: 20-80 % time 150ps typ, 261ps min, 113ps max; typ from 1.05 V to 0 V
[Pulldown]
| rgmii_18v Pulldown S28FDSIO_IBIS
| Tue Apr 27 17:21:37 2021
| voltage   I(typ)   I(min)   I(max)
-1.8V     -13.54mA   -11.27mA   -14.63mA
-600mV    -13.54mA   -11.27mA   -14.63mA
-400mV    -10.79mA   -8.912mA   -11.95mA
750mV     20.59mA    17.1mA     22.85mA
1.38V     37.36mA    30.54mA    41.54mA
1.92V     51.09mA    40.91mA    56.89mA
3.6V      93.13mA    72.34mA    103.1mA
[Pullup]
| rgmii_18v Pullup S28FDSIO_IBIS
| Tue Apr 27 17:21:37 2021
| voltage   I(typ)   I(min)   I(max)
-1.8V     13.34mA    10.97mA    14.44mA
-600mV    13.34mA    10.97mA    14.44mA
-470mV    11.82mA    9.662mA    12.94mA
-370mV    10.09mA    8.277mA    11.12mA
-220mV    6.259mA    5.316mA    6.866mA
770mV     -21.71mA   -18.4mA    -23.88mA
1.53V     -42.37mA   -35.45mA   -46.68mA
3.6V      -95.91mA   -78.65mA   -104.9mA
[GND Clamp]
| rgmii_18v GNDClamp S28FDSIO_IBIS
| Tue Apr 27 17:21:37 2021
| voltage   I(typ)   I(min)   I(max)
-1.8V     -2A        -2A        -2A
-1.29V    -2A        -2A        -2A
-1.25V    -2A        -1.857A    -2A
-1.16V    -1.48A     -1.486A    -2A
-1.06V    -881.4mA   -1.084A    -850.7mA
-1.01V    -603.7mA   -889.3mA   -366mA
-970mV    -401.1mA   -738mA     -122.1mA
-920mV    -191.3mA   -556.6mA   -24.31mA
-860mV    -47.87mA   -356.1mA   -10.83mA
-770mV    -8.077mA   -121.1mA   -7.872mA
-650mV    -4.095mA   -10.71mA   -4.933mA
1.8V      0A         0A         0A
[POWER Clamp]
| rgmii_18v PWRClamp S28FDSIO_IBIS
| Tue Apr 27 17:21:37 2021
| voltage   I(typ)   I(min)   I(max)
-1.8V     2A         2A         2A
-1.12V    556.7mA    737.2mA    459.9mA
-1.11V    507.7mA    700mA      388mA
-1.09V    413.6mA    626.9mA    259.9mA
-1.05V    245.5mA    486mA      87.61mA
-1.03V    175.5mA    419mA      46.96mA
-1V       94.69mA    324mA      22.18mA
-970mV    46.08mA    237.8mA    15.2mA
-920mV    16.5mA     121.4mA    12.17mA
-880mV    11mA       60.42mA    11mA
-760mV    7.037mA    8.744mA    7.97mA
1.8V      0A         0A         0A
[Ramp]
dV/dt_r   0.630/120.218p  0.527/296.354p  0.722/64.831p
dV/dt_f   0.621/168.702p  0.513/343.958p  0.716/117.875p
R_load = 50.00ohm
[Rising Waveform]
| rgmii_18v Rising-High S28FDSIO_IBIS
| Tue Apr 27 17:21:37 2021
R_fixture = 50.00
V_fixture = 1.8000
V_fixture_min = 1.6200
V_fixture_max = 1.9800
C_fixture = 0.00pF
| Time   V(typ)   V(min)   V(max)
0s        764.5mV    764.5mV    786.6mV
700ps     764.4mV    764.6mV    807.8mV
740ps     764.4mV    764.6mV    946.9mV
820ps     764.6mV    764.5mV    1.833V
1.07ns    780.4mV    764.4mV    1.972V
1.25ns    1.643V     764.6mV    1.977V
1.79ns    1.797V     804.2mV    1.98V
2.12ns    1.799V     1.559V     1.98V
2.97ns    1.8V       1.618V     1.98V
100ns     1.8V       1.62V      1.98V
[Rising Waveform]
| rgmii_18v Rising-Low S28FDSIO_IBIS
| Tue Apr 27 17:21:37 2021
R_fixture = 50.00
V_fixture = 0.0000
C_fixture = 0.00pF
| Time   V(typ)   V(min)   V(max)
0s        0V         0V         0V
700ps     -100uV     100uV      10.2mV
840ps     100uV      0V         1.025V
1.1ns     12.9mV     -100uV     1.183V
1.31ns    852.9mV    100uV      1.192V
1.62ns    1.007V     0V         1.198V
1.89ns    1.028V     53.4mV     1.2V
2.32ns    1.038V     733mV      1.201V
3.91ns    1.046V     854.8mV    1.202V
100ns     1.05V      878.3mV    1.203V
[Falling Waveform]
| rgmii_18v Falling-High S28FDSIO_IBIS
| Tue Apr 27 17:21:37 2021
R_fixture = 50.00
V_fixture = 1.8000
V_fixture_min = 1.6200
V_fixture_max = 1.9800
C_fixture = 0.00pF
| Time   V(typ)   V(min)   V(max)
0s        1.8V       1.62V      1.98V
640ps     1.8V       1.62V      1.979V
770ps     1.8V       1.62V      1.601V
870ps     1.802V     1.62V      949.5mV
1ns       1.795V     1.62V      807.4mV
1.28ns    995.8mV    1.619V     790.5mV
1.71ns    781mV      1.574V     788.3mV
2.3ns     773.6mV    874.9mV    787.7mV
3.48ns    770.9mV    790.6mV    787.4mV
100ns     764.5mV    764.5mV    786.6mV
[Falling Waveform]
| rgmii_18v Falling-Low S28FDSIO_IBIS
| Tue Apr 27 17:21:37 2021
R_fixture = 50.00
V_fixture = 0.0000
C_fixture = 0.00pF
| Time   V(typ)   V(min)   V(max)
0s        1.051V     878.3mV    1.203V
660ps     1.05V      878.5mV    1.164V
870ps     1.052V     878.3mV    121.8mV
1.15ns    634.6mV    878.1mV    1.5mV
1.25ns    194.1mV    877.9mV    700uV
1.38ns    38.15mV    878.9mV    375uV
1.69ns    1.6mV      812.7mV    100uV
2.11ns    300uV      90.15mV    100uV
2.54ns    100uV      3.352mV    0V
100ns     0V         0V         0V
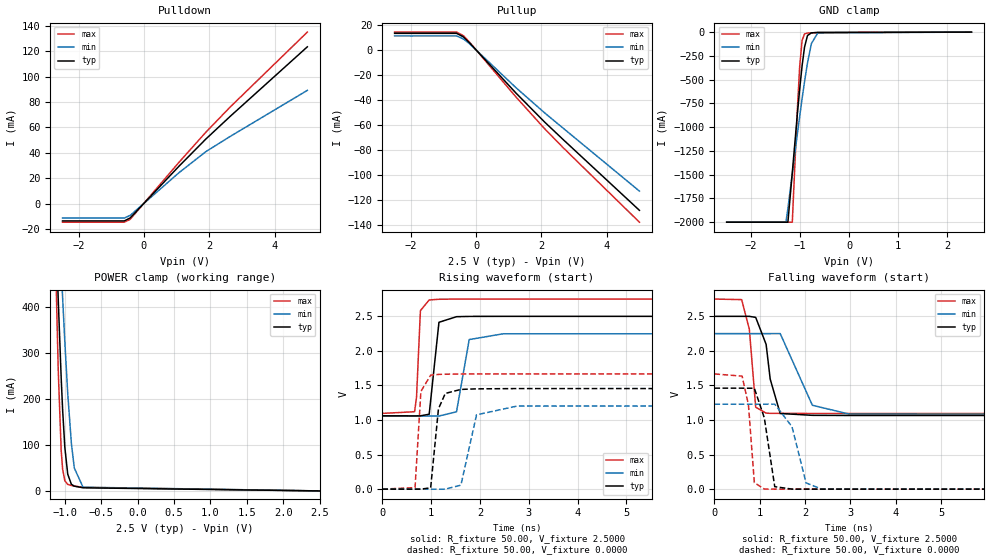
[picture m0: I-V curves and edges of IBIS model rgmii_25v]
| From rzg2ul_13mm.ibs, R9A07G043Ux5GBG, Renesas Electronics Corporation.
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[Model]   rgmii_25v
Model_type   I/O
Polarity   Non-Inverting
Enable   Active-Low
Vinl  =   0.7000V
Vinh  =   1.7000V
Vmeas =   1.2500V
Cref  =   5.00pF
| variable   typ   min   max
C_comp   1.297pF   1.197pF   1.397pF
[Model Spec]
| Subparameter   typ   min   max
| Thresholds
Vinh   1.7000   NA   NA
Vinl   0.7000   NA   NA
| Timing Thresholds
Vmeas   1.2500   1.1250   1.3750
| variable   typ   min   max
[Temperature Range]   25.000   125.000   -40.000
| variable   typ   min   max
[Voltage Range]   2.500V   2.250V   2.750V
| variable   typ   min   max
[Pullup Reference]   2.500V   2.250V   2.750V
| variable   typ   min   max
[Pulldown Reference]   0.000V   0.000V   0.000V
| variable   typ   min   max
[POWER Clamp Reference] 2.500V   2.250V   2.750V
| variable   typ   min   max
[GND Clamp Reference]   0.000V   0.000V   0.000V
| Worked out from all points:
|   slope of the pulldown table from 0 to 0.375 V, typ, clamps not added: 36 ohm
|   slope of the pullup table from 0 to 0.375 V, typ, clamps not added: 34.9 ohm
|   GND clamp passes 1 mA (typ) near -0.47 V on its own axis
|   POWER clamp passes 1 mA (typ) near -0.43 V on its own axis
|   rising waveform, R_fixture 50.00, V_fixture 2.5000: 20-80 % time 79.8ps typ, 137ps min, 50.6ps max; typ from 1.06 V to 2.5 V
|   rising waveform, R_fixture 50.00, V_fixture 0.0000: 20-80 % time 89ps typ, 175ps min, 54.9ps max; typ from 0 V to 1.46 V
|   falling waveform, R_fixture 50.00, V_fixture 2.5000: 20-80 % time 197ps typ, 349ps min, 132ps max; typ from 2.5 V to 1.06 V
|   falling waveform, R_fixture 50.00, V_fixture 0.0000: 20-80 % time 184ps typ, 288ps min, 122ps max; typ from 1.46 V to 0 V
[Pulldown]
| rgmii_25v Pulldown S28FDSIO_IBIS
| Tue Apr 27 17:21:37 2021
| voltage   I(typ)   I(min)   I(max)
-2.49V    -13.63mA   -11.35mA   -14.63mA
-600mV    -13.63mA   -11.35mA   -14.63mA
-420mV    -11.25mA   -9.284mA   -12.37mA
1.07V     29.38mA    24.29mA    32.45mA
1.9V      50.98mA    41.03mA    56.37mA
2.64V     68.73mA    52.92mA    76.09mA
5V        123.5mA    89.2mA     135.1mA
[Pullup]
| rgmii_25v Pullup S28FDSIO_IBIS
| Tue Apr 27 17:21:37 2021
| voltage   I(typ)   I(min)   I(max)
-2.5V     13.46mA    11.41mA    14.47mA
-600mV    13.46mA    11.41mA    14.47mA
-390mV    10.57mA    8.907mA    11.57mA
-210mV    6.026mA    5.265mA    6.566mA
1.22V     -34.42mA   -30.12mA   -37.58mA
2.1V      -57.7mA    -50.33mA   -63.03mA
2.67V     -71.77mA   -62.65mA   -78.29mA
5V        -128.3mA   -112.9mA   -137.8mA
[GND Clamp]
| rgmii_25v GNDClamp S28FDSIO_IBIS
| Tue Apr 27 17:21:37 2021
| voltage   I(typ)   I(min)   I(max)
-2.5V     -2A        -2A        -2A
-1.29V    -2A        -2A        -2A
-1.25V    -2A        -1.857A    -2A
-1.16V    -1.48A     -1.486A    -2A
-1.06V    -881.5mA   -1.084A    -850.7mA
-1.01V    -603.8mA   -889.3mA   -366mA
-960mV    -354.5mA   -701mA     -87.35mA
-910mV    -158mA     -521.7mA   -19.24mA
-850mV    -36.7mA    -325.2mA   -10.31mA
-770mV    -8.081mA   -121.1mA   -7.872mA
-640mV    -3.894mA   -8.824mA   -4.699mA
2.5V      0A         0A         0A
[POWER Clamp]
| rgmii_25v PWRClamp S28FDSIO_IBIS
| Tue Apr 27 17:21:37 2021
| voltage   I(typ)   I(min)   I(max)
-2.5V     2A         2A         2A
-1.12V    556.7mA    737.3mA    459.9mA
-1.11V    507.8mA    700.1mA    388.1mA
-1.09V    413.6mA    627mA      259.9mA
-1.05V    245.5mA    486.1mA    87.62mA
-1.03V    175.5mA    419mA      46.98mA
-1V       94.72mA    324.1mA    22.19mA
-960mV    36.25mA    211.6mA    14.22mA
-910mV    14.46mA    103.4mA    11.87mA
-870mV    10.39mA    49.95mA    10.75mA
-750mV    6.837mA    8.075mA    7.734mA
2.5V      0A         0A         0A
[Ramp]
dV/dt_r   0.876/89.022p   0.737/175.329p  1.000/54.941p
dV/dt_f   0.864/192.241p  0.716/343.449p  0.992/126.965p
R_load = 50.00ohm
[Rising Waveform]
| rgmii_25v Rising-High S28FDSIO_IBIS
| Tue Apr 27 17:21:37 2021
R_fixture = 50.00
V_fixture = 2.5000
V_fixture_min = 2.2500
V_fixture_max = 2.7500
C_fixture = 0.00pF
| Time   V(typ)   V(min)   V(max)
0s        1.061V     1.057V     1.096V
660ps     1.06V      1.058V     1.12V
700ps     1.06V      1.058V     1.324V
780ps     1.061V     1.057V     2.583V
960ps     1.084V     1.057V     2.737V
1.16ns    2.414V     1.058V     2.747V
1.52ns    2.495V     1.119V     2.75V
1.78ns    2.499V     2.164V     2.75V
2.48ns    2.5V       2.248V     2.75V
100ns     2.5V       2.25V      2.75V
[Rising Waveform]
| rgmii_25v Rising-Low S28FDSIO_IBIS
| Tue Apr 27 17:21:37 2021
R_fixture = 50.00
V_fixture = 0.0000
C_fixture = 0.00pF
| Time   V(typ)   V(min)   V(max)
0s        0V         0V         0V
670ps     -100uV     0V         22.6mV
790ps     0V         0V         1.414V
990ps     19.9mV     -100uV     1.649V
1.15ns    1.163V     0V         1.66V
1.29ns    1.385V     0V         1.663V
1.61ns    1.443V     58.3mV     1.666V
1.93ns    1.451V     1.075V     1.667V
2.76ns    1.455V     1.202V     1.667V
100ns     1.461V     1.229V     1.667V
[Falling Waveform]
| rgmii_25v Falling-High S28FDSIO_IBIS
| Tue Apr 27 17:21:37 2021
R_fixture = 50.00
V_fixture = 2.5000
V_fixture_min = 2.2500
V_fixture_max = 2.7500
C_fixture = 0.00pF
| Time   V(typ)   V(min)   V(max)
0s        2.5V       2.25V      2.75V
600ps     2.5V       2.25V      2.742V
770ps     2.5V       2.25V      2.313V
910ps     2.485V     2.25V      1.185V
1.14ns    2.094V     2.25V      1.1V
1.23ns    1.591V     2.25V      1.097V
1.45ns    1.095V     2.251V     1.096V
2.16ns    1.068V     1.214V     1.095V
2.97ns    1.066V     1.086V     1.095V
100ns     1.061V     1.057V     1.096V
[Falling Waveform]
| rgmii_25v Falling-Low S28FDSIO_IBIS
| Tue Apr 27 17:21:37 2021
R_fixture = 50.00
V_fixture = 0.0000
C_fixture = 0.00pF
| Time   V(typ)   V(min)   V(max)
0s        1.461V     1.229V     1.667V
610ps     1.461V     1.229V     1.635V
750ps     1.46V      1.229V     1.22V
880ps     1.46V      1.229V     94.1mV
1.1ns     1.031V     1.229V     1.8mV
1.33ns    36.1mV     1.23V      300uV
1.71ns    867uV      904mV      100uV
2.02ns    200uV      90.8mV     100uV
2.35ns    83uV       4.065mV    87uV
100ns     0V         0V         0V
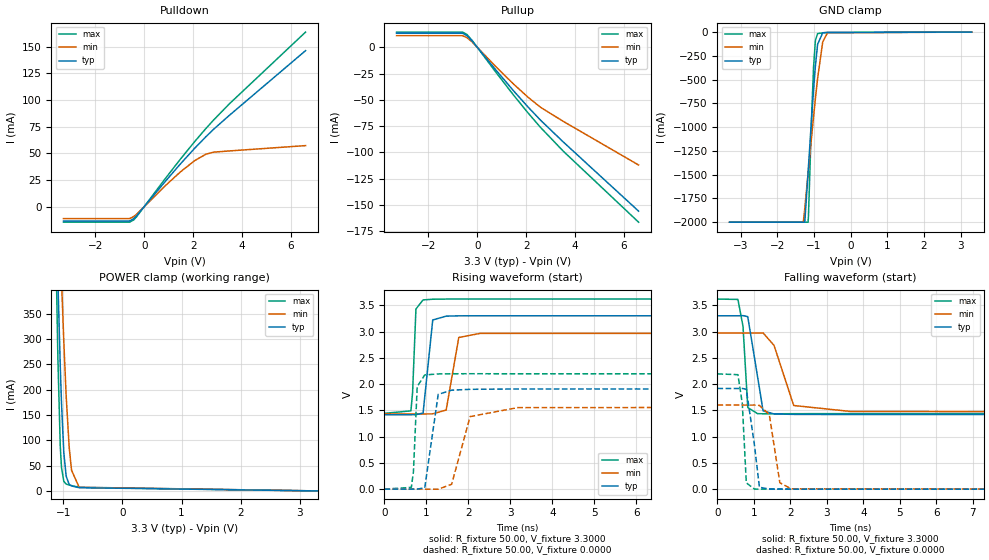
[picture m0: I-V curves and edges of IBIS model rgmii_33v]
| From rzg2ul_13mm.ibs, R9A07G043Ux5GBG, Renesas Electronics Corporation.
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[Model]   rgmii_33v
Model_type   I/O
Polarity   Non-Inverting
Enable   Active-Low
Vinl  =   0.7000V
Vinh  =   1.9000V
Vmeas =   1.6500V
Cref  =   5.00pF
| variable   typ   min   max
C_comp   1.297pF   1.197pF   1.397pF
[Model Spec]
| Subparameter   typ   min   max
| Thresholds
Vinh   1.9000   NA   NA
Vinl   0.7000   NA   NA
| Timing Thresholds
Vmeas   1.6500   1.4850   1.8150
| variable   typ   min   max
[Temperature Range]   25.000   125.000   -40.000
| variable   typ   min   max
[Voltage Range]   3.300V   2.970V   3.630V
| variable   typ   min   max
[Pullup Reference]   3.300V   2.970V   3.630V
| variable   typ   min   max
[Pulldown Reference]   0.000V   0.000V   0.000V
| variable   typ   min   max
[POWER Clamp Reference] 3.300V   2.970V   3.630V
| variable   typ   min   max
[GND Clamp Reference]   0.000V   0.000V   0.000V
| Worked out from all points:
|   slope of the pulldown table from 0 to 0.495 V, typ, clamps not added: 36.2 ohm
|   slope of the pullup table from 0 to 0.495 V, typ, clamps not added: 35.2 ohm
|   GND clamp passes 1 mA (typ) near -0.47 V on its own axis
|   POWER clamp passes 1 mA (typ) near -0.43 V on its own axis
|   rising waveform, R_fixture 50.00, V_fixture 3.3000: 20-80 % time 97.9ps typ, 156ps min, 54.7ps max; typ from 1.42 V to 3.3 V
|   rising waveform, R_fixture 50.00, V_fixture 0.0000: 20-80 % time 119ps typ, 283ps min, 60.7ps max; typ from 0 V to 1.92 V
|   falling waveform, R_fixture 50.00, V_fixture 3.3000: 20-80 % time 181ps typ, 380ps min, 108ps max; typ from 3.3 V to 1.42 V
|   falling waveform, R_fixture 50.00, V_fixture 0.0000: 20-80 % time 130ps typ, 188ps min, 92.4ps max; typ from 1.92 V to 0 V
[Pulldown]
| rgmii_33v Pulldown S28FDSIO_IBIS
| Tue Apr 27 17:21:37 2021
| voltage   I(typ)   I(min)   I(max)
-3.3V     -13.56mA   -11.27mA   -14.64mA
-600mV    -13.56mA   -11.27mA   -14.64mA
-430mV    -11.39mA   -9.379mA   -12.56mA
-320mV    -8.845mA   -7.391mA   -9.797mA
850mV     23.32mA    19.3mA     25.9mA
1.48V     40.02mA    32.54mA    44.52mA
2.07V     54.86mA    43.23mA    61.16mA
2.52V     65.49mA    49.12mA    73.17mA
2.84V     72.61mA    51.1mA     81.29mA
3.49V     85.78mA    52.25mA    96.59mA
6.6V      146.4mA    57.24mA    163.8mA
[Pullup]
| rgmii_33v Pullup S28FDSIO_IBIS
| Tue Apr 27 17:21:37 2021
| voltage   I(typ)   I(min)   I(max)
-3.3V     13.4mA     11.07mA    14.48mA
-600mV    13.4mA     11.07mA    14.48mA
-420mV    11.08mA    9.101mA    12.15mA
-220mV    6.285mA    5.362mA    6.881mA
760mV     -21.53mA   -18.37mA   -23.63mA
1.5V      -41.79mA   -35.3mA    -45.91mA
2.09V     -57.11mA   -47.73mA   -62.78mA
2.59V     -69.36mA   -57.1mA    -76.25mA
3.51V     -89.87mA   -70.34mA   -98.62mA
6.6V      -155.9mA   -112mA     -166.4mA
[GND Clamp]
| rgmii_33v GNDClamp S28FDSIO_IBIS
| Tue Apr 27 17:21:37 2021
| voltage   I(typ)   I(min)   I(max)
-3.3V     -2A        -2A        -2A
-1.29V    -2A        -2A        -2A
-1.25V    -2A        -1.857A    -2A
-1.16V    -1.48A     -1.486A    -2A
-1.15V    -1.419A    -1.445A    -1.941A
-1.06V    -881.4mA   -1.084A    -850.7mA
-1.01V    -603.7mA   -889.3mA   -366mA
-960mV    -354.5mA   -701mA     -87.35mA
-900mV    -128.2mA   -487.3mA   -15.98mA
-760mV    -7.388mA   -102.6mA   -7.618mA
-630mV    -3.693mA   -7.343mA   -4.468mA
3.3V      0A         0A         0A
[POWER Clamp]
| rgmii_33v PWRClamp S28FDSIO_IBIS
| Tue Apr 27 17:21:37 2021
| voltage   I(typ)   I(min)   I(max)
-3.3V     2A         2A         2A
-1.12V    556.7mA    737.2mA    459.9mA
-1.11V    507.8mA    700.1mA    388.1mA
-1.09V    413.6mA    626.9mA    259.9mA
-1.05V    245.5mA    486mA      87.62mA
-1.03V    175.5mA    419mA      46.98mA
-990mV    75mA       294.2mA    18.85mA
-950mV    28.82mA    186.6mA    13.51mA
-900mV    12.95mA    87.11mA    11.57mA
-860mV    9.866mA    41.08mA    10.49mA
-730mV    6.392mA    6.953mA    7.249mA
3.3V      0A         0A         0A
[Ramp]
dV/dt_r   1.150/119.333p  0.960/282.140p  1.317/60.743p
dV/dt_f   1.130/176.305p  0.923/372.613p  1.305/107.575p
R_load = 50.00ohm
[Rising Waveform]
| rgmii_33v Rising-High S28FDSIO_IBIS
| Tue Apr 27 17:21:37 2021
R_fixture = 50.00
V_fixture = 3.3000
V_fixture_min = 2.9700
V_fixture_max = 3.6000
C_fixture = 0.00pF
| Time   V(typ)   V(min)   V(max)
0s        1.416V     1.432V     1.443V
630ps     1.416V     1.432V     1.49V
670ps     1.417V     1.432V     1.834V
750ps     1.416V     1.432V     3.429V
920ps     1.45V      1.432V     3.602V
1.15ns    3.22V      1.433V     3.615V
1.47ns    3.293V     1.506V     3.618V
1.77ns    3.299V     2.887V     3.618V
2.28ns    3.3V       2.965V     3.618V
100ns     3.3V       2.97V      3.618V
[Rising Waveform]
| rgmii_33v Rising-Low S28FDSIO_IBIS
| Tue Apr 27 17:21:37 2021
R_fixture = 50.00
V_fixture = 0.0000
C_fixture = 0.00pF
| Time   V(typ)   V(min)   V(max)
0s        0V         0V         0V
640ps     -100uV     100uV      34.2mV
690ps     100uV      0V         328.3mV
780ps     -200uV     -100uV     1.954V
960ps     26.9mV     -100uV     2.174V
1.28ns    1.804V     -100uV     2.193V
1.6ns     1.884V     92mV       2.196V
2.04ns    1.9V       1.381V     2.197V
3.17ns    1.907V     1.552V     2.196V
100ns     1.917V     1.6V       2.194V
[Falling Waveform]
| rgmii_33v Falling-High S28FDSIO_IBIS
| Tue Apr 27 17:21:37 2021
R_fixture = 50.00
V_fixture = 3.3000
V_fixture_min = 2.9700
V_fixture_max = 3.6000
C_fixture = 0.00pF
| Time   V(typ)   V(min)   V(max)
0s        3.3V       2.97V      3.618V
560ps     3.3V       2.97V      3.611V
700ps     3.303V     2.97V      3.098V
830ps     3.283V     2.97V      1.554V
1.1ns     2.136V     2.972V     1.437V
1.25ns    1.49V      2.974V     1.435V
1.55ns    1.432V     2.737V     1.435V
2.09ns    1.423V     1.592V     1.436V
3.65ns    1.421V     1.479V     1.438V
100ns     1.416V     1.432V     1.443V
[Falling Waveform]
| rgmii_33v Falling-Low S28FDSIO_IBIS
| Tue Apr 27 17:21:37 2021
R_fixture = 50.00
V_fixture = 0.0000
C_fixture = 0.00pF
| Time   V(typ)   V(min)   V(max)
0s        1.917V     1.6V       2.194V
560ps     1.916V     1.601V     2.179V
680ps     1.917V     1.6V       1.633V
790ps     1.903V     1.6V       120.8mV
1.01ns    856.9mV    1.6V       2.3mV
1.15ns    36.4mV     1.593V     700uV
1.42ns    2.05mV     1.422V     200uV
1.71ns    500uV      122mV      100uV
2.02ns    183uV      6.021mV    100uV
100ns     0V         0V         0V
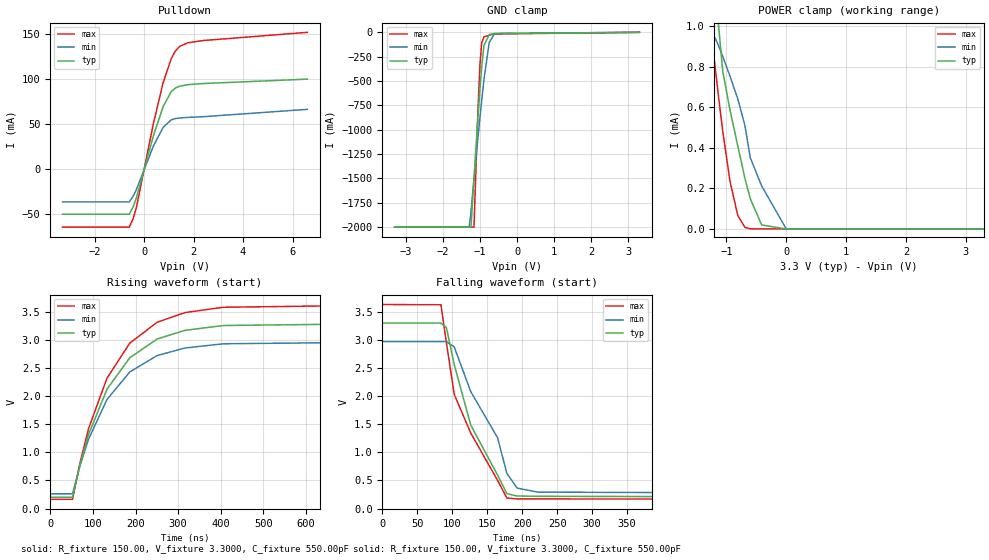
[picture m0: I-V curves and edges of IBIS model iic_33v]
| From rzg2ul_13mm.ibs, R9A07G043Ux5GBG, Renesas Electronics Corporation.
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[Model]   iic_33v
Model_type   I/O_open_drain
Polarity   Non-Inverting
Enable   Active-Low
Vinl  =   0.9900V
Vinh  =   2.3100V
Vmeas =   1.6500V
Rref  =   150.000
Cref  =   150.00pF
Vref  =   3.3000V
| variable   typ   min   max
C_comp   1.977e-12  1.908e-12  2.08e-12
[Model Spec]
| Subparameter   typ   min   max
| Thresholds
Vinh   2.3100   2.0790   2.5410
Vinl   0.9900   0.8910   1.0890
| Timing Thresholds
Vmeas   1.6500   1.4850   1.8150
| variable   typ   min   max
[Temperature Range]   25.000   125.000   -40.000
| variable   typ   min   max
[Voltage Range]   3.300V   2.970V   3.630V
| variable   typ   min   max
[Pullup Reference]   3.300V   2.970V   3.630V
| variable   typ   min   max
[Pulldown Reference]   0.000V   0.000V   0.000V
| variable   typ   min   max
[POWER Clamp Reference] 3.300V   2.970V   3.630V
| variable   typ   min   max
[GND Clamp Reference]   0.000V   0.000V   0.000V
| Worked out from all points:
|   slope of the pulldown table from 0 to 0.495 V, typ, clamps not added: 10.4 ohm
|   GND clamp passes 1 mA (typ) near -0.33 V on its own axis
|   POWER clamp passes 1 mA (typ) near -1.13 V on its own axis
|   rising waveform, R_fixture 150.00, V_fixture 3.3000, C_fixture 550.00pF: 20-80 % time 115ns typ, 115ns min, 115ns max; typ from 0.201 V to 3.3 V
|   falling waveform, R_fixture 150.00, V_fixture 3.3000, C_fixture 550.00pF: 20-80 % time 57.8ns typ, 58.2ns min, 54.8ns max; typ from 3.3 V to 0.202 V
[Pulldown]
| iic_33v Pulldown S28FDSIO_IBIS
| Fri Sep 11 10:40:27 2020
| voltage   I(typ)   I(min)   I(max)
-3.3V     -49.8mA    -36.2mA    -64.1mA
-600mV    -49.8mA    -36.2mA    -64.1mA
-440mV    -41.48mA   -29.7mA    -54.34mA
-310mV    -31.47mA   -22.3mA    -42.04mA
380mV     37.39mA    25.87mA    51.08mA
770mV     69.3mA     46.25mA    95.74mA
1.1V      85.86mA    54.58mA    122.4mA
1.26V     89.67mA    55.93mA    130.5mA
1.43V     91.72mA    56.55mA    135.6mA
1.76V     93.41mA    57.25mA    139.7mA
2.38V     94.68mA    58mA       142.2mA
6.6V      99.55mA    66.12mA    151.3mA
[GND Clamp]
| iic_33v GNDClamp S28FDSIO_IBIS
| Fri Sep 11 10:40:27 2020
| voltage   I(typ)   I(min)   I(max)
-3.3V     -2A        -2A        -2A
-1.29V    -2A        -2A        -2A
-1.25V    -2A        -1.874A    -2A
-1.24V    -1.991A    -1.833A    -2A
-1.16V    -1.499A    -1.506A    -2A
-1.06V    -911.3mA   -1.108A    -867.9mA
-1V       -585.7mA   -877.3mA   -333.7mA
-950mV    -346mA     -691.6mA   -103.1mA
-890mV    -134mA     -481.3mA   -46.04mA
-750mV    -22.98mA   -106.5mA   -29.53mA
-600mV    -12.11mA   -11.76mA   -17.16mA
3.3V      0A         0A         0A
[POWER Clamp]
| iic_33v PWRClamp S28FDSIO_IBIS
| Fri Sep 11 10:40:27 2020
| voltage   I(typ)   I(min)   I(max)
-3.3V     3.665mA    2.907mA    4.955mA
-1.35V    1.311mA    1.052mA    1.208mA
-1.27V    1.208mA    989.5uA    1.01mA
-1.14V    1.03mA     910.3uA    672.8uA
-1.06V    775.1uA    850.5uA    478.4uA
-940mV    586.3uA    752.9uA    235.3uA
-810mV    409.4uA    642uA      66.37uA
-690mV    248.4uA    509.5uA    7.561uA
-600mV    148.3uA    350.2uA    790.5nA
-410mV    19.43uA    211.7uA    295.9nA
0V        0A         0A         0A
3.3V      0A         0A         0A
[Ramp]
dV/dt_r   1.859/114.903n  1.625/114.905n  2.080/114.859n
dV/dt_f   1.859/57.713n   1.625/58.173n   2.079/54.756n
R_load = 150.00ohm
[Rising Waveform]
| iic_33v Rising-High S28FDSIO_IBIS
| Fri Sep 11 10:40:27 2020
R_fixture = 150.00
V_fixture = 3.3000
V_fixture_min = 2.9700
V_fixture_max = 3.6300
C_fixture = 550.00pF
| Time   V(typ)   V(min)   V(max)
0s        200.9mV    262.3mV    164.1mV
52.17ns   201.2mV    263.8mV    164.9mV
70.57ns   798.9mV    781.5mV    844.5mV
90ns      1.321V     1.238V     1.426V
133.2ns   2.125V     1.942V     2.321V
186.7ns   2.684V     2.431V     2.944V
251ns     3.017V     2.722V     3.315V
316ns     3.17V      2.856V     3.486V
406ns     3.256V     2.931V     3.581V
900ns     3.3V       2.97V      3.63V
[Falling Waveform]
| iic_33v Falling-High S28FDSIO_IBIS
| Fri Sep 11 10:40:27 2020
R_fixture = 150.00
V_fixture = 3.3000
V_fixture_min = 2.9700
V_fixture_max = 3.6300
C_fixture = 550.00pF
| Time   V(typ)   V(min)   V(max)
0s        3.3V       2.97V      3.63V
83.79ns   3.3V       2.97V      3.625V
91.58ns   3.221V     2.97V      2.954V
102.8ns   2.562V     2.876V     2.031V
126.4ns   1.485V     2.081V     1.344V
164.7ns   598.7mV    1.263V     505.1mV
178.1ns   265.6mV    627.8mV    186.8mV
192.6ns   224.3mV    365.8mV    173.1mV
222ns     218.2mV    293.3mV    171.8mV
900ns     202.2mV    262.3mV    164.8mV
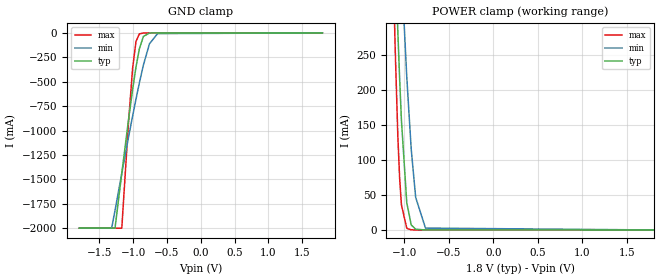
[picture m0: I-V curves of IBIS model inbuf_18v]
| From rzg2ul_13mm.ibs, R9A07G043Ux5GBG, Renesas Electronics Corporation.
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[Model]   inbuf_18v
Model_type   Input
Vinl  =   0.6300V
Vinh  =   1.1700V
| variable   typ   min   max
C_comp   0.789pF   0.740pF   0.884pF
[Model Spec]
| Subparameter   typ   min   max
| Thresholds
Vinh   1.1700   1.0530   1.2870
Vinl   0.6300   0.5670   0.6930
| variable   typ   min   max
[Temperature Range]   25.000   125.000   -40.000
| variable   typ   min   max
[Voltage Range]   1.800V   1.620V   1.980V
| variable   typ   min   max
[POWER Clamp Reference] 1.800V   1.620V   1.980V
| variable   typ   min   max
[GND Clamp Reference]   0.000V   0.000V   0.000V
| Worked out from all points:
|   GND clamp passes 1 mA (typ) near -0.75 V on its own axis
|   POWER clamp passes 1 mA (typ) near -0.87 V on its own axis
[GND Clamp]
| inbuf_18v GNDClamp S28FDSIO_IBIS
| Fri Apr  9 09:21:15 2021
| voltage   I(typ)   I(min)   I(max)
-1.8V     -2A        -2A        -2A
-1.32V    -2A        -2A        -2A
-1.27V    -2A        -1.818A    -2A
-1.17V    -1.436A    -1.439A    -2A
-1.07V    -888.2mA   -1.068A    -911.2mA
-1.01V    -581.6mA   -852.9mA   -363.7mA
-960mV    -351.2mA   -679.1mA   -89.38mA
-910mV    -163.6mA   -512.8mA   -10.38mA
-850mV    -35.82mA   -328.7mA   -550.1uA
-760mV    -1.356mA   -111.5mA   -6.28uA
-640mV    -12.87uA   -7.139mA   -16.87nA
1.8V      0A         0A         0A
[POWER Clamp]
| inbuf_18v PWRClamp S28FDSIO_IBIS
| Fri Apr  9 09:21:15 2021
| voltage   I(typ)   I(min)   I(max)
-1.8V     2A         2A         2A
-1.13V    511.8mA    672.2mA    420.4mA
-1.12V    471.5mA    640.9mA    364.1mA
-1.1V     393.1mA    579.2mA    260.3mA
-1.07V    283.3mA    488.9mA    134mA
-1.05V    216.9mA    430.6mA    74.47mA
-1.03V    157.6mA    374mA      36.15mA
-970mV    38.95mA    219.2mA    2.348mA
-920mV    7.208mA    115.5mA    198.9uA
-870mV    1.086mA    46.58mA    16.55uA
-760mV    15.19uA    2.695mA    69.74nA
1.8V      0A         0A         0A
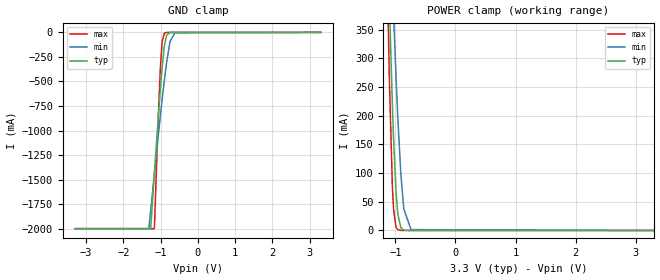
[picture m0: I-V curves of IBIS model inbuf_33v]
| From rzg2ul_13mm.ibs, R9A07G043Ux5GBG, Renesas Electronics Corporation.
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[Model]   inbuf_33v
Model_type   Input
Vinl  =   0.8000V
Vinh  =   2.0000V
| variable   typ   min   max
C_comp   0.776pF   0.713pF   0.858pF
[Model Spec]
| Subparameter   typ   min   max
| Thresholds
Vinh   2.0000   NA   NA
Vinl   0.8000   NA   NA
| variable   typ   min   max
[Temperature Range]   25.000   125.000   -40.000
| variable   typ   min   max
[Voltage Range]   3.300V   2.970V   3.630V
| variable   typ   min   max
[POWER Clamp Reference] 3.300V   2.970V   3.630V
| variable   typ   min   max
[GND Clamp Reference]   0.000V   0.000V   0.000V
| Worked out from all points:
|   GND clamp passes 1 mA (typ) near -0.75 V on its own axis
|   POWER clamp passes 1 mA (typ) near -0.87 V on its own axis
[GND Clamp]
| inbuf_33v GNDClamp S28FDSIO_IBIS
| Fri Apr  9 09:21:15 2021
| voltage   I(typ)   I(min)   I(max)
-3.3V     -2A        -2A        -2A
-1.32V    -2A        -2A        -2A
-1.27V    -2A        -1.818A    -2A
-1.17V    -1.436A    -1.439A    -2A
-1.07V    -888.2mA   -1.068A    -911.2mA
-1.01V    -581.6mA   -852.9mA   -363.7mA
-960mV    -351.2mA   -679.1mA   -89.38mA
-900mV    -133.8mA   -480.8mA   -6.426mA
-840mV    -25.89mA   -300.3mA   -335uA
-750mV    -922uA     -94.25mA   -3.821uA
-620mV    -6.012uA   -4.079mA   0A
3.3V      0A         0A         0A
[POWER Clamp]
| inbuf_33v PWRClamp S28FDSIO_IBIS
| Fri Apr  9 09:21:15 2021
| voltage   I(typ)   I(min)   I(max)
-3.3V     2A         2A         2A
-1.13V    511.8mA    672.2mA    420.4mA
-1.12V    471.5mA    640.9mA    364.1mA
-1.1V     393.1mA    579.2mA    260.3mA
-1.05V    216.9mA    430.6mA    74.47mA
-1.03V    157.6mA    374mA      36.15mA
-990mV    67.51mA    267.9mA    6.164mA
-960mV    28.68mA    196.2mA    1.439mA
-910mV    4.977mA    98.68mA    121uA
-860mV    738.7uA    37.44mA    10.06uA
-740mV    7.076uA    1.52mA     26.15nA
3.3V      0A         0A         0A
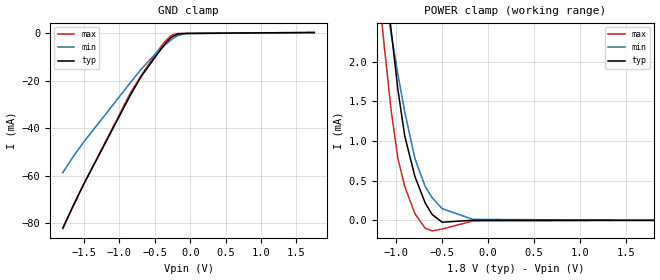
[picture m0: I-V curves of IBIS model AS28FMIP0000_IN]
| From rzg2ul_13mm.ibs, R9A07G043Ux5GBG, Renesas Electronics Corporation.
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[Model]   AS28FMIP0000_IN
Model_type   Input
Polarity   Non-Inverting
Enable   Active-High
Vinl =  0.165V
Vinh =  0.235V
C_comp   3.7pF   3.28pF   3.87pF
[Model Spec]
Vinh   0.235V   0.235V   0.235V
Vinl   0.165V   0.165V   0.165V
[Temperature Range]   25.000   0.125k   -40.000
[Voltage Range]   1.800V   1.650V   1.950V
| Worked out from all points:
|   GND clamp passes 1 mA (typ) near -0.23 V on its own axis
|   POWER clamp passes 1 mA (typ) near -0.89 V on its own axis
[GND_clamp]
|Voltage   I(typ)   I(min)   I(max)
-1.8V     -81.98mA   -58.64mA   -82.25mA
-1.652V   -72.44mA   -51.87mA   -72.68mA
-1.504V   -63.45mA   -45.74mA   -63.52mA
-838mV    -25.62mA   -20.47mA   -24.69mA
-690mV    -18.08mA   -15.02mA   -17.62mA
-468mV    -8.906mA   -7.866mA   -7.753mA
-357mV    -4.45mA    -4.965mA   -3.471mA
-283mV    -2.124mA   -3.072mA   -1.378mA
-246mV    -1.269mA   -2.23mA    -647.3uA
-172mV    -278.6uA   -933.2uA   -110.1uA
-61mV     -64.51uA   -134.3uA   -74.61uA
1.752V    363.3uA    281uA      212.5uA
[POWER_clamp]
|Voltage   I(typ)   I(min)   I(max)
-1.8V     12.2mA     8.475mA    11.38mA
-1.16V    3.69mA     3.18mA     2.637mA
-1.123V   3.246mA    2.899mA    2.197mA
-1.049V   2.402mA    2.356mA    1.393mA
-975mV    1.648mA    1.843mA    779.8uA
-901mV    1.063mA    1.367mA    428.2uA
-790mV    551.3uA    777uA      83.31uA
-679mV    218.7uA    427.1uA    -98.74uA
-605mV    75.27uA    288.1uA    -132.4uA
-494mV    -23.75uA   147.1uA    -109uA
-161mV    1.596uA    12.55uA    -7.984uA
1.8V      0A         0A         0A
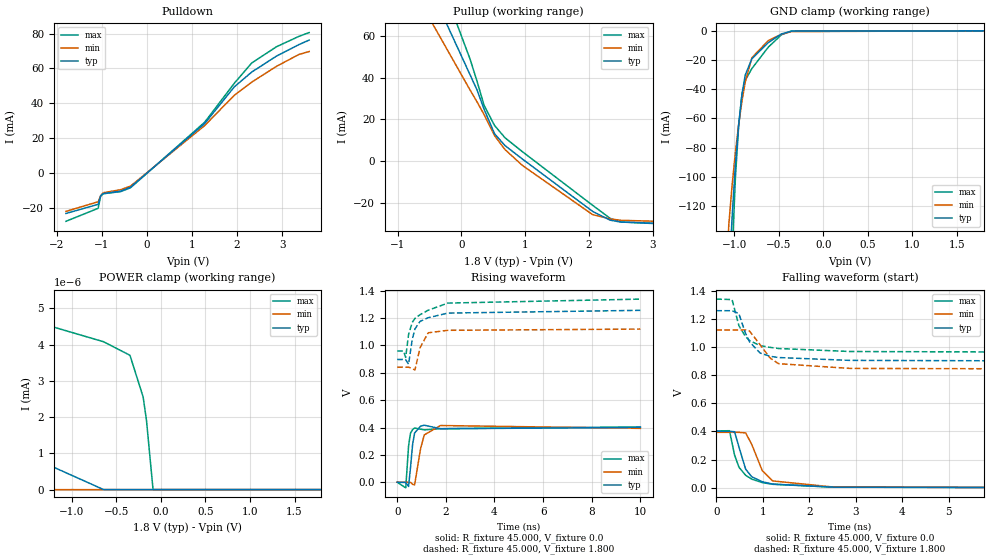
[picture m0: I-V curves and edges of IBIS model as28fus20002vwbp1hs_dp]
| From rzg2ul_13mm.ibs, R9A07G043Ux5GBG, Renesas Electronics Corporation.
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[Model] as28fus20002vwbp1hs_dp
Model_type I/O
Polarity   Non-Inverting
Enable   Active-High
Vinl =  100.000mV
Vinh =  0.300V
Vmeas =  0.200V
C_comp   6.49pF   5.97pF   7.15pF
C_comp_pullup   0.109pF   18.194fF   0.278pF
C_comp_pulldown   0.985pF   0.749pF   1.167pF
[Temperature Range]   25.000   0.125k   -40.000
[Voltage Range]   1.800V   1.650V   1.950V
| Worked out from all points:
|   slope of the pulldown table from 0 to 0.27 V, typ, clamps not added: 44.1 ohm
|   slope of the pullup table from 0 to 0.27 V, typ, clamps not added: 15.1 ohm
|   GND clamp passes 1 mA (typ) near -0.42 V on its own axis
|   rising waveform, R_fixture 45.000, V_fixture 0.0: 20-80 % time 134ps typ, 237ps min, 100ps max; typ from 0 V to 0.401 V
|   rising waveform, R_fixture 45.000, V_fixture 1.800: 20-80 % time 448ps typ, 286ps min, 891ps max; typ from 0.898 V to 1.26 V
|   falling waveform, R_fixture 45.000, V_fixture 0.0: 20-80 % time 292ps typ, 329ps min, 325ps max; typ from 0.401 V to 0 V
|   falling waveform, R_fixture 45.000, V_fixture 1.800: 20-80 % time 344ps typ, 407ps min, 353ps max; typ from 1.26 V to 0.898 V
[Pulldown]
|Voltage   I(typ)   I(min)   I(max)
-1.8V     -23.18mA   -21.99mA   -27.68mA
-1.085V   -17.95mA   -16.46mA   -20.22mA
-1.03V    -13.07mA   -13.08mA   -13.18mA
-975mV    -11.79mA   -11.3mA    -11.86mA
-590mV    -10.42mA   -9.572mA   -10.69mA
-370mV    -8.192mA   -7.546mA   -8.513mA
1.28V     28.41mA    27.23mA    29.15mA
1.94V     49.48mA    44.66mA    51.57mA
2.325V    57.93mA    52.15mA    63.14mA
2.875V    67.08mA    61.2mA     72.45mA
3.37V     73.65mA    67.99mA    78.36mA
3.6V      76.26mA    69.7mA     80.58mA
[Pullup]
|Voltage   I(typ)   I(min)   I(max)
-1.8V     167.9mA    137.6mA    203.4mA
-1.295V   135.7mA    110.8mA    164.9mA
135mV     41.3mA     34.03mA    48.78mA
245mV     34mA       28.35mA    38.14mA
355mV     24.88mA    22.31mA    26.72mA
520mV     13.12mA    12.26mA    17.07mA
685mV     7.483mA    5.571mA    11.2mA
960mV     1.018mA    -2.03mA    4.521mA
2.06V     -23.9mA    -25.45mA   -21mA
2.335V    -28.07mA   -27.47mA   -27.21mA
2.5V      -28.98mA   -28.13mA   -28.89mA
3.6V      -30.21mA   -29.09mA   -30.58mA
[GND_clamp]
|Voltage   I(typ)   I(min)   I(max)
-1.8V     -2.272A    -1.233A    -4.081A
-1.06V    -174.8mA   -133.1mA   -232.6mA
-1.023V   -128.2mA   -106.2mA   -154.6mA
-986mV    -92.15mA   -83.51mA   -101.3mA
-949mV    -64.33mA   -64.32mA   -65.15mA
-912mV    -43.66mA   -48.19mA   -43.58mA
-875mV    -30.27mA   -35.07mA   -33.89mA
-801mV    -19.14mA   -18.43mA   -25.87mA
-616mV    -8.015mA   -6.659mA   -11.15mA
-468mV    -2.115mA   -2.32mA    -2.658mA
-357mV    -214.3uA   -520.4uA   -154uA
1.8V      -3.547nA   -58.07nA   -27.5nA
[POWER_clamp]
|Voltage   I(typ)   I(min)   I(max)
-1.8V     69.51uA    1.637mA    91.62nA
-1.53V    9.042nA    17.15uA    6.903nA
-1.456V   2.114nA    2.393uA    5.723nA
-1.382V   1.201nA    322.3nA    5.068nA
-1.271V   737.5pA    5.358nA    4.594nA
-1.234V   653.5pA    0A         4.508nA
-642mV    1.131pA    0A         4.081nA
-346mV    0A         0A         3.707nA
-198mV    0A         0A         2.555nA
-161mV    0A         0A         1.918nA
-87mV     0A         0A         0A
1.8V      0A         0A         0A
[Ramp]
| variable   typ   min   max
dV/dt_r   0.241/0.137n   0.234/0.230n   0.243/0.117n
dV/dt_f   0.241/0.324n   0.234/0.341n   0.243/0.381n
R_load = 45.000
[Rising Waveform]
R_fixture= 45.000
V_fixture= 0.0
V_fixture_min= 0.0
V_fixture_max= 0.0
|time   V(typ)   V(min)   V(max)
0s        705.1nV    4.678uV    1.966uV
351ps     -1.776mV   4.834uV    -41.13mV
467ps     -30.71mV   -28.1uV    265.2mV
546ps     105.6mV    -710uV     358.7mV
633ps     275.7mV    -15.46mV   385.3mV
715ps     359.9mV    -19.6mV    396.3mV
964ps     410.4mV    248.5mV    388mV
1.114ns   417.1mV    346.4mV    383mV
1.781ns   391.1mV    414.7mV    391.7mV
10ns      401.1mV    394mV      404.3mV
[Rising Waveform]
R_fixture= 45.000
V_fixture= 1.800
V_fixture_min= 1.650
V_fixture_max= 1.950
|time   V(typ)   V(min)   V(max)
0s        897.7mV    841.4mV    959.7mV
256ps     897.7mV    841.4mV    959.5mV
348ps     896.9mV    841.4mV    913.6mV
467ps     862.9mV    841.4mV    1.08V
614ps     1.04V      831.4mV    1.167V
730ps     1.121V     820.8mV    1.198V
938ps     1.176V     983.5mV    1.225V
1.275ns   1.203V     1.093V     1.258V
2.085ns   1.237V     1.111V     1.31V
10ns      1.257V     1.12V      1.339V
[Falling Waveform]
R_fixture= 45.000
V_fixture= 0.0
V_fixture_min= 0.0
V_fixture_max= 0.0
|time   V(typ)   V(min)   V(max)
0s        401.1mV    394.1mV    404.3mV
284ps     401.1mV    394.1mV    405.4mV
393ps     398.1mV    394.1mV    232.9mV
489ps     288mV      393.9mV    145.6mV
632ps     132.1mV    389.9mV    89.1mV
764ps     78.31mV    307.5mV    61.83mV
989ps     43.41mV    121.9mV    37.3mV
1.21ns    26.88mV    49.27mV    25.38mV
2.52ns    5.03mV     5.745mV    5.095mV
10ns      42.16uV    94.21uV    16.23uV
[Falling Waveform]
R_fixture= 45.000
V_fixture= 1.800
V_fixture_min= 1.650
V_fixture_max= 1.950
|time   V(typ)   V(min)   V(max)
0s        1.257V     1.12V      1.339V
339ps     1.257V     1.12V      1.336V
486ps     1.236V     1.12V      1.151V
621ps     1.103V     1.121V     1.077V
713ps     1.037V     1.113V     1.045V
939ps     957.1mV    1.017V     1.01V
1.159ns   933.4mV    920.6mV    996.6mV
1.339ns   924.5mV    881mV      988.7mV
2.876ns   904.4mV    847.5mV    967.4mV
10ns      897.9mV    841.6mV    960mV
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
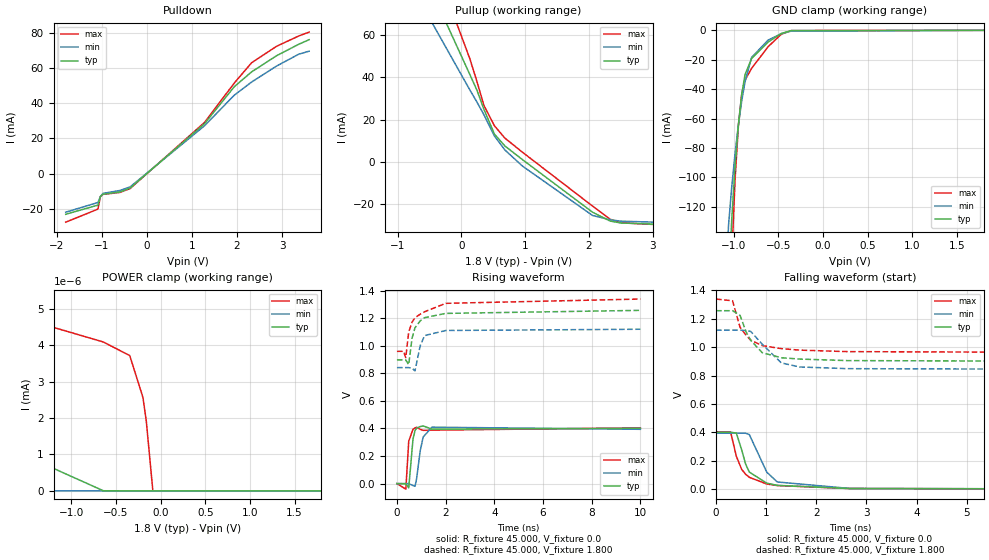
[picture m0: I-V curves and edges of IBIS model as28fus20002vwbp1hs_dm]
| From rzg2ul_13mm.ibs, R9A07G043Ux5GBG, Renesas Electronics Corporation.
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|   Model as28fus20002vwbp1hs_dm
[Model] as28fus20002vwbp1hs_dm
Model_type I/O
Polarity   Inverting
Enable   Active-High
Vinl =  100.000mV
Vinh =  0.300V
Vmeas =  0.200V
C_comp   6.49pF   5.97pF   7.15pF
C_comp_pullup   0.116pF   21.740fF   0.287pF
C_comp_pulldown   0.983pF   0.748pF   1.164pF
[Temperature Range]   25.000   0.125k   -40.000
[Voltage Range]   1.800V   1.650V   1.950V
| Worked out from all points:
|   slope of the pulldown table from 0 to 0.27 V, typ, clamps not added: 44.1 ohm
|   slope of the pullup table from 0 to 0.27 V, typ, clamps not added: 15.1 ohm
|   GND clamp passes 1 mA (typ) near -0.42 V on its own axis
|   rising waveform, R_fixture 45.000, V_fixture 0.0: 20-80 % time 112ps typ, 203ps min, 84ps max; typ from 0 V to 0.401 V
|   rising waveform, R_fixture 45.000, V_fixture 1.800: 20-80 % time 430ps typ, 262ps min, 871ps max; typ from 0.898 V to 1.26 V
|   falling waveform, R_fixture 45.000, V_fixture 0.0: 20-80 % time 290ps typ, 328ps min, 324ps max; typ from 0.401 V to 0 V
|   falling waveform, R_fixture 45.000, V_fixture 1.800: 20-80 % time 367ps typ, 446ps min, 364ps max; typ from 1.26 V to 0.898 V
[Pulldown]
|Voltage   I(typ)   I(min)   I(max)
-1.8V     -23.18mA   -21.99mA   -27.68mA
-1.085V   -17.95mA   -16.46mA   -20.22mA
-1.03V    -13.07mA   -13.08mA   -13.18mA
-975mV    -11.79mA   -11.3mA    -11.86mA
-590mV    -10.42mA   -9.572mA   -10.69mA
-370mV    -8.192mA   -7.546mA   -8.513mA
1.28V     28.41mA    27.23mA    29.15mA
1.94V     49.48mA    44.66mA    51.57mA
2.325V    57.93mA    52.15mA    63.14mA
2.875V    67.08mA    61.2mA     72.45mA
3.37V     73.65mA    67.99mA    78.36mA
3.6V      76.26mA    69.7mA     80.58mA
[Pullup]
|Voltage   I(typ)   I(min)   I(max)
-1.8V     167.9mA    137.6mA    203.4mA
-1.295V   135.7mA    110.8mA    164.9mA
135mV     41.3mA     34.03mA    48.78mA
245mV     34mA       28.35mA    38.14mA
355mV     24.88mA    22.31mA    26.72mA
520mV     13.12mA    12.26mA    17.07mA
685mV     7.483mA    5.571mA    11.2mA
960mV     1.018mA    -2.03mA    4.521mA
2.06V     -23.9mA    -25.45mA   -21mA
2.335V    -28.07mA   -27.47mA   -27.21mA
2.5V      -28.98mA   -28.13mA   -28.89mA
3.6V      -30.21mA   -29.09mA   -30.58mA
[GND_clamp]
|Voltage   I(typ)   I(min)   I(max)
-1.8V     -2.272A    -1.233A    -4.081A
-1.06V    -174.8mA   -133.1mA   -232.6mA
-1.023V   -128.2mA   -106.2mA   -154.6mA
-986mV    -92.15mA   -83.51mA   -101.3mA
-949mV    -64.33mA   -64.32mA   -65.15mA
-912mV    -43.66mA   -48.19mA   -43.58mA
-875mV    -30.27mA   -35.07mA   -33.89mA
-801mV    -19.14mA   -18.43mA   -25.87mA
-616mV    -8.015mA   -6.659mA   -11.15mA
-468mV    -2.115mA   -2.32mA    -2.658mA
-357mV    -214.3uA   -520.4uA   -154uA
1.8V      -3.54nA    -58.06nA   -27.5nA
[POWER_clamp]
|Voltage   I(typ)   I(min)   I(max)
-1.8V     69.5uA     1.636mA    91.61nA
-1.53V    9.041nA    17.14uA    6.903nA
-1.456V   2.114nA    2.392uA    5.723nA
-1.382V   1.202nA    322.2nA    5.069nA
-1.271V   738.6pA    5.364nA    4.595nA
-1.234V   654.7pA    0A         4.509nA
-642mV    4.883pA    0A         4.085nA
-346mV    0A         0A         3.712nA
-198mV    0A         0A         2.562nA
-161mV    0A         0A         1.925nA
-87mV     0A         0A         0A
1.8V      0A         0A         0A
[Ramp]
| variable   typ   min   max
dV/dt_r   0.241/0.118n   0.234/0.200n   0.243/0.101n
dV/dt_f   0.241/0.330n   0.234/0.353n   0.243/0.384n
R_load = 45.000
[Rising Waveform]
R_fixture= 45.000
V_fixture= 0.0
V_fixture_min= 0.0
V_fixture_max= 0.0
|time   V(typ)   V(min)   V(max)
0s        701.6nV    4.677uV    1.95uV
366ps     -671uV     4.327uV    -40.42mV
485ps     -30.64mV   -41.5uV    307.8mV
660ps     322.7mV    -14.35mV   394.7mV
744ps     385.7mV    -19.21mV   403.6mV
807ps     401.7mV    34.01mV    409.1mV
959ps     413.8mV    240.8mV    393.7mV
1.079ns   418.4mV    338.6mV    386.3mV
1.439ns   395.1mV    409.3mV    388mV
10ns      401.1mV    394mV      404.3mV
[Rising Waveform]
R_fixture= 45.000
V_fixture= 1.800
V_fixture_min= 1.650
V_fixture_max= 1.950
|time   V(typ)   V(min)   V(max)
0s        897.7mV    841.4mV    959.7mV
272ps     897.7mV    841.4mV    959.8mV
362ps     897.5mV    841.4mV    913.4mV
483ps     862.8mV    841.4mV    1.099V
621ps     1.055V     838.2mV    1.172V
741ps     1.13V      817.7mV    1.203V
959ps     1.181V     1.002V     1.23V
1.138ns   1.204V     1.074V     1.247V
2.006ns   1.235V     1.111V     1.308V
10ns      1.257V     1.12V      1.339V
[Falling Waveform]
R_fixture= 45.000
V_fixture= 0.0
V_fixture_min= 0.0
V_fixture_max= 0.0
|time   V(typ)   V(min)   V(max)
0s        401.1mV    394.1mV    404.3mV
292ps     401.1mV    394.1mV    401.9mV
406ps     395mV      394.1mV    231.9mV
513ps     276mV      394mV      138.8mV
593ps     174.8mV    393.9mV    104.2mV
665ps     120.2mV    384.3mV    83.59mV
1.013ns   42.25mV    119.7mV    36.43mV
1.223ns   26.88mV    50.63mV    25.34mV
2.67ns    4.419mV    4.983mV    4.433mV
10ns      38.69uV    90.08uV    14.36uV
[Falling Waveform]
R_fixture= 45.000
V_fixture= 1.800
V_fixture_min= 1.650
V_fixture_max= 1.950
|time   V(typ)   V(min)   V(max)
0s        1.257V     1.12V      1.339V
330ps     1.257V     1.12V      1.327V
480ps     1.224V     1.12V      1.14V
602ps     1.107V     1.117V     1.083V
693ps     1.048V     1.111V     1.049V
923ps     960.9mV    1.021V     1.011V
1.303ns   925.7mV    889.2mV    989.7mV
1.67ns    916.3mV    860.8mV    979.3mV
2.62ns    905.6mV    848.8mV    968.8mV
10ns      897.9mV    841.6mV    959.9mV
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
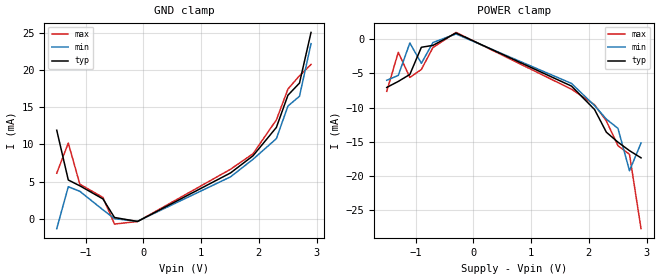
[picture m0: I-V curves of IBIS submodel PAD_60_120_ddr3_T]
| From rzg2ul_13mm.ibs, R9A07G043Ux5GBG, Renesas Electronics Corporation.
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[Submodel]  PAD_60_120_ddr3_T
Submodel_type Dynamic_clamp
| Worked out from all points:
|   GND clamp passes 1 mA (typ) near -0.57 V on its own axis
|   POWER clamp passes 1 mA (typ) near -0.76 V on its own axis
[GND Clamp]
| Voltage   I(typ)   I(min)   I(max)
-1.5V     11.9mA     -1.326mA   6.124mA
-1.3V     5.209mA    4.306mA    10.17mA
-1.1V     4.429mA    3.691mA    4.651mA
-700mV    2.669mA    1.209mA    2.867mA
-500mV    174uA      11.58uA    -704.8uA
-100mV    -358.8uA   -336.9uA   -369.8uA
1.51V     6.158mA    5.632mA    6.651mA
1.9V      8.464mA    7.996mA    8.738mA
2.305V    12.28mA    10.77mA    13.29mA
2.505V    16.6mA     15.15mA    17.43mA
2.705V    18.23mA    16.46mA    19.22mA
2.905V    25.04mA    23.53mA    20.73mA
[POWER Clamp]
| Voltage   I(typ)   I(min)   I(max)
-1.5V     -7.06mA    -6.011mA   -7.629mA
-1.3V     -6.179mA   -5.3mA     -1.931mA
-1.1V     -5.163mA   -563.5uA   -5.601mA
-900mV    -1.188mA   -3.537mA   -4.434mA
-700mV    -914.7uA   -494.2uA   -1.227mA
-300mV    896.4uA    755.2uA    984.8uA
1.7V      -6.861mA   -6.472mA   -7.316mA
2.1V      -10.29mA   -9.72mA    -9.587mA
2.305V    -13.61mA   -11.7mA    -11.97mA
2.505V    -15.06mA   -13.04mA   -15.57mA
2.705V    -16.3mA    -19.23mA   -16.83mA
2.905V    -17.35mA   -15.19mA   -27.7mA
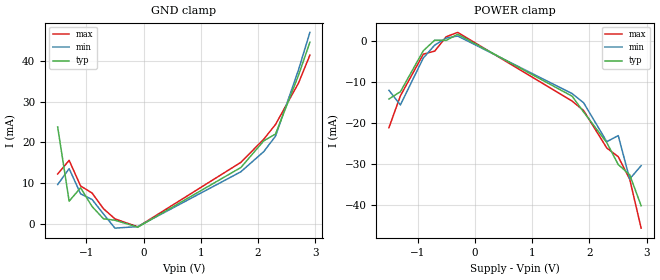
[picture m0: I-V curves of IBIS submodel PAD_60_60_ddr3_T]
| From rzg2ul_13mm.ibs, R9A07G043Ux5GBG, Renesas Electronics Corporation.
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[Submodel]  PAD_60_60_ddr3_T
Submodel_type Dynamic_clamp
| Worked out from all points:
|   GND clamp passes 1 mA (typ) near -0.28 V on its own axis
|   POWER clamp passes 1 mA (typ) near -0.15 V on its own axis
[GND Clamp]
| Voltage   I(typ)   I(min)   I(max)
-1.5V     23.79mA    9.653mA    12.25mA
-1.3V     5.573mA    13.57mA    15.6mA
-1.1V     8.859mA    7.38mA     9.303mA
-900mV    4.266mA    5.994mA    7.577mA
-700mV    1.237mA    2.417mA    3.711mA
-500mV    880uA      -1.056mA   1.222mA
-100mV    -802.7uA   -673.7uA   -739.7uA
1.7V      13.85mA    12.8mA     15.11mA
2.1V      20.4mA     17.76mA    20.81mA
2.305V    22.08mA    21.55mA    24.43mA
2.705V    36.46mA    37.78mA    34.56mA
2.905V    44.62mA    47.05mA    41.46mA
[POWER Clamp]
| Voltage   I(typ)   I(min)   I(max)
-1.5V     -14.13mA   -12.02mA   -21.12mA
-1.3V     -12.36mA   -15.58mA   -13.36mA
-900mV    -2.376mA   -4.137mA   -3.206mA
-700mV    224uA      -987.4uA   -2.453mA
-500mV    160uA      722.8uA    1.041mA
-300mV    1.648mA    1.219mA    2.112mA
1.7V      -13.45mA   -12.81mA   -14.64mA
1.9V      -17.3mA    -15.04mA   -16.94mA
2.305V    -24.77mA   -24.54mA   -26.08mA
2.505V    -30.11mA   -23.05mA   -28.2mA
2.705V    -32.6mA    -33.62mA   -33.66mA
2.905V    -40.15mA   -30.38mA   -45.61mA
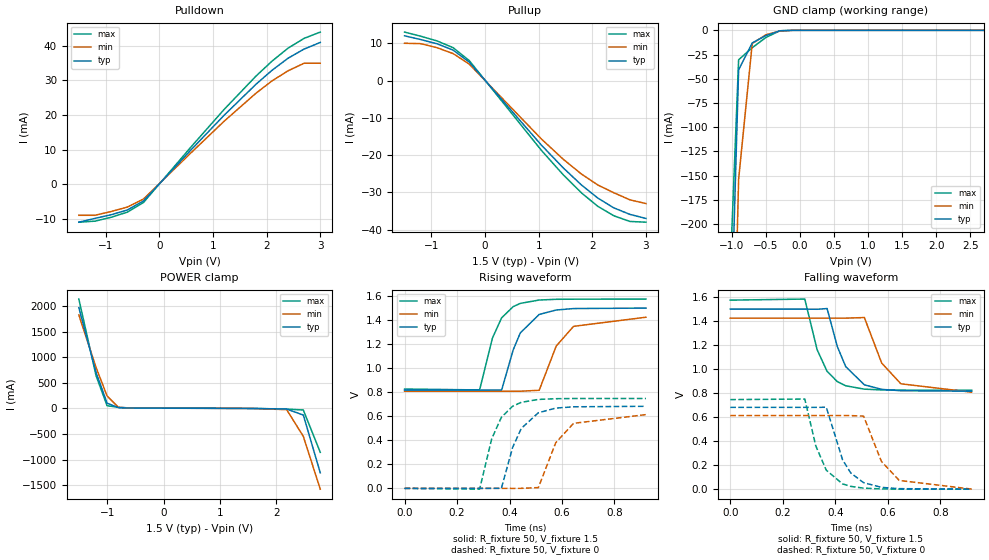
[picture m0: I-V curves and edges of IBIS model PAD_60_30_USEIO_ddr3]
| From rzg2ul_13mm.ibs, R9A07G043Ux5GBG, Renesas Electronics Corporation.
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[Model] PAD_60_30_USEIO_ddr3
Model_type I/O
Polarity   Non-Inverting
Vinl = 0.6250
Vinh = 0.8750
Vmeas= 0.750
| Capacitance   typ   min   max
C_comp   2.092e-12   2.004e-12   2.2e-12
[Model Spec]
| Subparameter   typ   min   max
Vmeas   0.750   0.713   0.787
Vinh   0.8750   0.8375   0.9125
Vinl   0.6250   0.5875   0.6625
| Variables   typ   min   max
[GND Clamp Reference]   0   0   0
[POWER Clamp Reference]   1.5   1.425   1.575
[Pulldown Reference]   0   0   0
[Pullup Reference]   1.5   1.425   1.575
[Temperature Range]   25   125   -40
[Voltage Range]   1.5   1.425   1.575
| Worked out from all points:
|   slope of the pulldown table from 0 to 0.225 V, typ, clamps not added: 59.4 ohm
|   slope of the pullup table from 0 to 0.225 V, typ, clamps not added: 59 ohm
|   GND clamp passes 1 mA (typ) near -0.32 V on its own axis
|   POWER clamp passes 1 mA (typ) near -0.35 V on its own axis
|   rising waveform, R_fixture 50, V_fixture 1.5: 20-80 % time 72.9ps typ, 80.8ps min, 66.2ps max; typ from 0.817 V to 1.5 V
|   rising waveform, R_fixture 50, V_fixture 0: 20-80 % time 74.3ps typ, 83.1ps min, 67.7ps max; typ from 0 V to 0.683 V
|   falling waveform, R_fixture 50, V_fixture 1.5: 20-80 % time 75.2ps typ, 84.1ps min, 68.9ps max; typ from 1.5 V to 0.816 V
|   falling waveform, R_fixture 50, V_fixture 0: 20-80 % time 73.8ps typ, 83.3ps min, 67.8ps max; typ from 0.682 V to 0 V
[GND Clamp]
| Voltage   I(typ)   I(min)   I(max)
-1.5V     -2.259A    -2.122A    -2.425A
-1.1V     -522.9mA   -708mA     -384.4mA
-900mV    -40.76mA   -153.7mA   -30.4mA
-700mV    -13.01mA   -13.6mA    -17.91mA
-500mV    -5.434mA   -4.586mA   -7.41mA
-295mV    -481.7uA   -747.1uA   -477.2uA
-105mV    -692.7nA   -8.729uA   -100nA
2.8V      0A         0A         0A
[POWER Clamp]
| Voltage   I(typ)   I(min)   I(max)
-1.5V     1.972A     1.83A      2.141A
-1.195V   702.3mA    800.9mA    640mA
-1V       103.6mA    244.6mA    53.73mA
-800mV    15.83mA    23.52mA    21.41mA
-600mV    7.48mA     6.225mA    10.31mA
1.58V     -272nA     -34.79uA   -4.532nA
2.18V     -12.19mA   -23.99mA   -12.71mA
2.475V    -129mA     -546.5mA   -30.4mA
2.775V    -1.259A    -1.58A     -858.9mA
[Pulldown]
| Voltage   I(typ)   I(min)   I(max)
-1.5V     -11mA      -9mA       -11mA
-1.2V     -9.9mA     -9mA       -10.7mA
-895mV    -8.84mA    -7.9mA     -9.57mA
-595mV    -7.461mA   -6.625mA   -8.08mA
-295mV    -4.846mA   -4.296mA   -5.298mA
600mV     10.07mA    9.206mA    10.93mA
1.205V    19.89mA    18.17mA    21.57mA
1.8V      28.88mA    26.29mA    31.24mA
2.1V      32.94mA    29.88mA    35.59mA
2.4V      36.44mA    32.8mA     39.35mA
2.7V      39.1mA     35mA       42.2mA
3V        41mA       35mA       44mA
[Pullup]
| Voltage   I(typ)   I(min)   I(max)
-1.5V     12mA       10mA       13mA
-1.2V     11mA       9.9mA      11.9mA
-895mV    9.87mA     8.81mA     10.63mA
-595mV    8.169mA    7.231mA    8.82mA
-295mV    4.957mA    4.422mA    5.372mA
1.055V    -17.39mA   -15.74mA   -18.8mA
1.455V    -23.39mA   -21.08mA   -25.24mA
1.8V      -28.05mA   -25.12mA   -30.17mA
2.1V      -31.5mA    -28mA      -33.72mA
2.4V      -34.16mA   -30.1mA    -36.27mA
2.7V      -35.9mA    -32mA      -37.8mA
3V        -37mA      -33mA      -38mA
[Ramp]
dV/dt_r   0.4095/7.294e-11   0.3698/8.082e-11   0.4491/6.617e-11
dV/dt_f   0.4090/7.380e-11   0.3677/8.333e-11   0.4478/6.785e-11
R_load= 50
[Rising Waveform]
R_fixture = 50
V_fixture = 1.5
V_fixture_min = 1.425
V_fixture_max = 1.575
| Time   V(typ)   V(min)   V(max)
0s        817.5mV    808.1mV    826.4mV
286ps     817.5mV    808.1mV    819mV
335ps     818.2mV    808.1mV    1.251V
370ps     818.6mV    808.1mV    1.419V
414ps     1.152V     808mV      1.512V
441ps     1.293V     808.2mV    1.539V
513ps     1.447V     816.2mV    1.567V
578ps     1.484V     1.184V     1.573V
644ps     1.496V     1.348V     1.574V
920ps     1.5V       1.424V     1.575V
[Rising Waveform]
R_fixture = 50
V_fixture = 0
V_fixture_min = 0
V_fixture_max = 0
| Time   V(typ)   V(min)   V(max)
0s        527.3nV    14.93uV    110.8nV
286ps     5.05uV     15.04uV    -6.621mV
332ps     499.7uV    14.5uV     411.8mV
369ps     1.251mV    23.76uV    591.3mV
412ps     341.4mV    -48.39uV   683.8mV
445ps     499.3mV    170.7uV    715.9mV
510ps     629.2mV    6.634mV    740mV
576ps     667.7mV    379.5mV    746mV
644ps     678.7mV    541.1mV    747.6mV
920ps     682.8mV    613.6mV    748mV
[Falling Waveform]
R_fixture = 50
V_fixture = 1.5
V_fixture_min = 1.425
V_fixture_max = 1.575
| Time   V(typ)   V(min)   V(max)
0s        1.5V       1.425V     1.575V
284ps     1.5V       1.425V     1.584V
331ps     1.499V     1.425V     1.162V
369ps     1.505V     1.425V     981.6mV
408ps     1.188V     1.425V     896.1mV
440ps     1.021V     1.425V     861.5mV
511ps     869.5mV    1.43V      833.4mV
577ps     831.6mV    1.051V     826.9mV
650ps     820.2mV    878mV      825.2mV
920ps     816.3mV    807.9mV    824.7mV
[Falling Waveform]
R_fixture = 50
V_fixture = 0
V_fixture_min = 0
V_fixture_max = 0
| Time   V(typ)   V(min)   V(max)
0s        681.6mV    613.4mV    746.3mV
284ps     681.6mV    613.4mV    750.9mV
326ps     681.4mV    613.4mV    359.9mV
366ps     682.8mV    613.4mV    157.9mV
428ps     244.5mV    613.4mV    43.83mV
459ps     135.4mV    613mV      23.42mV
508ps     54.15mV    608.7mV    8.6mV
576ps     15.17mV    231.1mV    2.133mV
644ps     4.209mV    72.63mV    507.4uV
920ps     18.61uV    654.4uV    1.3uV
[Add Submodel]
| Submodel Name Mode
PAD_60_30_ddr3_T Non-Driving
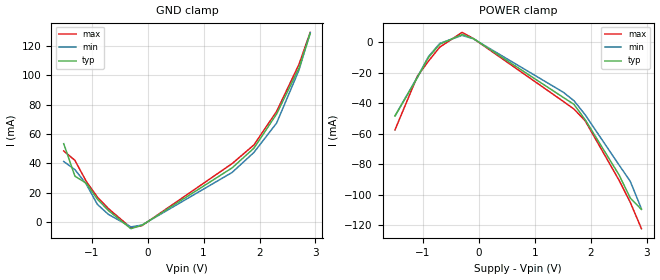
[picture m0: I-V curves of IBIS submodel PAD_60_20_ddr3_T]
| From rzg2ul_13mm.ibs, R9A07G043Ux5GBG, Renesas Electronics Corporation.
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[Submodel]  PAD_60_20_ddr3_T
Submodel_type Dynamic_clamp
[GND Clamp]
| Voltage   I(typ)   I(min)   I(max)
-1.5V     53.39mA    41.26mA    48.45mA
-1.3V     31.27mA    35.76mA    42.06mA
-1.1V     26.58mA    26.04mA    27.9mA
-900mV    15.67mA    12.11mA    17.08mA
-700mV    7.812mA    5.168mA    9.116mA
-300mV    -4.51mA    -3.299mA   -3.855mA
-100mV    -2.195mA   -2.022mA   -2.431mA
1.51V     36.94mA    33.83mA    39.85mA
1.9V      50.38mA    47.47mA    52.58mA
2.305V    73.68mA    67.48mA    75.43mA
2.705V    105mA      103.6mA    107.5mA
2.905V    128.4mA    129.1mA    129.3mA
[POWER Clamp]
| Voltage   I(typ)   I(min)   I(max)
-1.5V     -48.39mA   -48.39mA   -57.5mA
-1.1V     -23.35mA   -22.9mA    -22.38mA
-900mV    -10.01mA   -9.467mA   -12.45mA
-700mV    -1.381mA   -874.4uA   -3.311mA
-300mV    4.946mA    4.385mA    6.337mA
-100mV    2.353mA    2.16mA     2.352mA
1.51V     -36.29mA   -32.9mA    -38.9mA
1.7V      -40.81mA   -38.44mA   -43.9mA
1.9V      -50.89mA   -47.64mA   -51.58mA
2.505V    -86.99mA   -80.49mA   -90.5mA
2.705V    -102.1mA   -91.15mA   -104.9mA
2.905V    -109.6mA   -109.2mA   -122.2mA
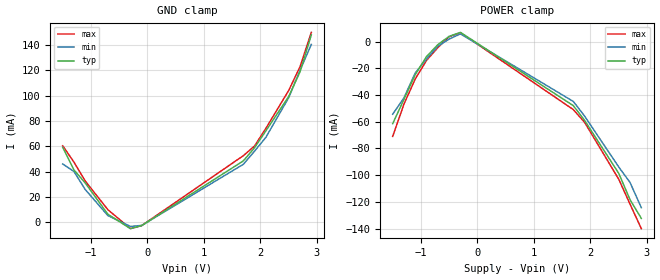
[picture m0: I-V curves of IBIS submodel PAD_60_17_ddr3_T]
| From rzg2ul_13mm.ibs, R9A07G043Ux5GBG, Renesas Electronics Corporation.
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[Submodel]  PAD_60_17_ddr3_T
Submodel_type Dynamic_clamp
[GND Clamp]
| Voltage   I(typ)   I(min)   I(max)
-1.5V     59.29mA    46.08mA    60.43mA
-1.3V     41.33mA    40.07mA    47.49mA
-1.1V     31.01mA    25.84mA    32.55mA
-700mV    6.379mA    5.335mA    9.964mA
-300mV    -5.022mA   -3.244mA   -4.973mA
-100mV    -2.597mA   -2.465mA   -2.589mA
1.7V      48.48mA    45.79mA    52.61mA
1.9V      58.94mA    56.23mA    60.29mA
2.1V      72.24mA    67.14mA    74.24mA
2.505V    99.38mA    98.51mA    104.2mA
2.705V    118.9mA    120mA      122.9mA
2.905V    148mA      140.5mA    150mA
[POWER Clamp]
| Voltage   I(typ)   I(min)   I(max)
-1.5V     -61.46mA   -54.4mA    -71mA
-1.3V     -43.26mA   -42.1mA    -46.77mA
-1.1V     -24.7mA    -23.46mA   -27.99mA
-900mV    -11.2mA    -13mA      -14.05mA
-700mV    -2.296mA   -3.458mA   -4.538mA
-500mV    3.9mA      1.853mA    3.644mA
-300mV    6.852mA    5.722mA    6.678mA
1.7V      -47.99mA   -44.84mA   -50.95mA
1.9V      -59.04mA   -55.8mA    -60.44mA
2.505V    -98.7mA    -93.92mA   -103.1mA
2.705V    -118.4mA   -105.5mA   -121.7mA
2.905V    -132.4mA   -124.4mA   -140.1mA
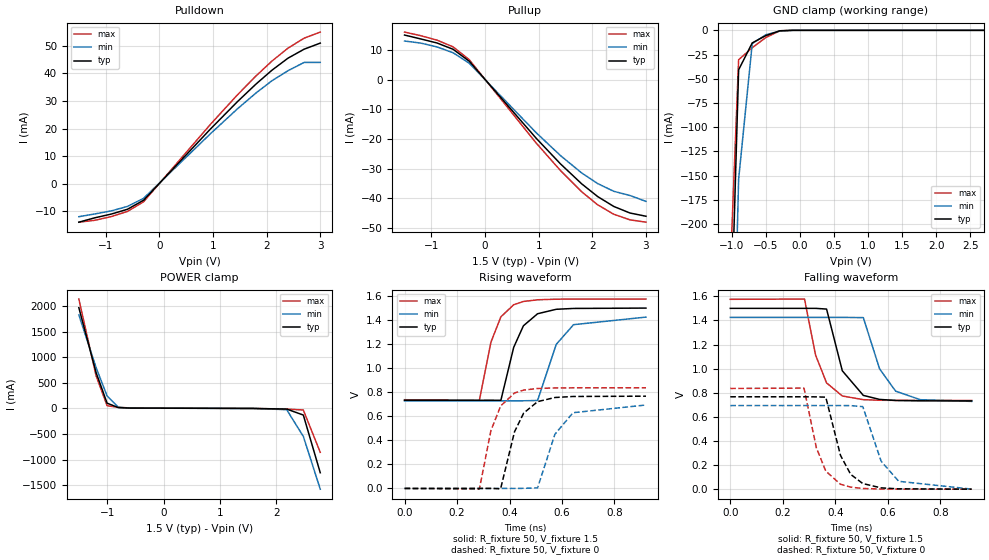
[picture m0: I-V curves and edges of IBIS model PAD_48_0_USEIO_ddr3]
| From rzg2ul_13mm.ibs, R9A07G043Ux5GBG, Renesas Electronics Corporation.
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[Model] PAD_48_0_USEIO_ddr3
Model_type I/O
Polarity   Non-Inverting
Vinl = 0.6250
Vinh = 0.8750
Vmeas= 0.750
| Capacitance   typ   min   max
C_comp   2.092e-12   2.004e-12   2.2e-12
[Model Spec]
| Subparameter   typ   min   max
Vmeas   0.750   0.713   0.787
Vinh   0.8750   0.8375   0.9125
Vinl   0.6250   0.5875   0.6625
| Variables   typ   min   max
[GND Clamp Reference]   0   0   0
[POWER Clamp Reference]   1.5   1.425   1.575
[Pulldown Reference]   0   0   0
[Pullup Reference]   1.5   1.425   1.575
[Temperature Range]   25   125   -40
[Voltage Range]   1.5   1.425   1.575
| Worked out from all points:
|   slope of the pulldown table from 0 to 0.225 V, typ, clamps not added: 47.5 ohm
|   slope of the pullup table from 0 to 0.225 V, typ, clamps not added: 47.2 ohm
|   GND clamp passes 1 mA (typ) near -0.32 V on its own axis
|   POWER clamp passes 1 mA (typ) near -0.35 V on its own axis
|   rising waveform, R_fixture 50, V_fixture 1.5: 20-80 % time 65ps typ, 72.5ps min, 58.9ps max; typ from 0.733 V to 1.5 V
|   rising waveform, R_fixture 50, V_fixture 0: 20-80 % time 66.1ps typ, 74ps min, 60.1ps max; typ from 0 V to 0.767 V
|   falling waveform, R_fixture 50, V_fixture 1.5: 20-80 % time 67.1ps typ, 75.6ps min, 61.7ps max; typ from 1.5 V to 0.732 V
|   falling waveform, R_fixture 50, V_fixture 0: 20-80 % time 66.6ps typ, 75.9ps min, 60.9ps max; typ from 0.766 V to 0 V
[GND Clamp]
| Voltage   I(typ)   I(min)   I(max)
-1.5V     -2.259A    -2.122A    -2.425A
-1.1V     -522.9mA   -708mA     -384.4mA
-900mV    -40.76mA   -153.7mA   -30.4mA
-700mV    -13.01mA   -13.6mA    -17.91mA
-500mV    -5.434mA   -4.586mA   -7.41mA
-295mV    -481.7uA   -747.1uA   -477.2uA
-105mV    -692.7nA   -8.729uA   -100nA
2.8V      0A         0A         0A
[POWER Clamp]
| Voltage   I(typ)   I(min)   I(max)
-1.5V     1.972A     1.83A      2.141A
-1.195V   702.3mA    800.9mA    640mA
-1V       103.6mA    244.6mA    53.73mA
-800mV    15.83mA    23.52mA    21.41mA
-600mV    7.48mA     6.225mA    10.31mA
1.58V     -272nA     -34.79uA   -4.532nA
2.18V     -12.19mA   -23.99mA   -12.71mA
2.475V    -129mA     -546.5mA   -30.4mA
2.775V    -1.259A    -1.58A     -858.9mA
[Pulldown]
| Voltage   I(typ)   I(min)   I(max)
-1.5V     -14mA      -12mA      -14mA
-1.2V     -12.4mA    -11mA      -13.3mA
-895mV    -11.05mA   -9.9mA     -11.96mA
-595mV    -9.321mA   -8.285mA   -10.1mA
-295mV    -6.058mA   -5.37mA    -6.623mA
955mV     19.86mA    18.15mA    21.55mA
1.455V    29.73mA    27.12mA    32.2mA
1.8V      36.1mA     32.86mA    39.05mA
2.1V      41.17mA    37.35mA    44.49mA
2.4V      45.55mA    41mA       49.19mA
2.7V      48.8mA     44mA       52.8mA
3V        51mA       44mA       55mA
[Pullup]
| Voltage   I(typ)   I(min)   I(max)
-1.5V     15mA       13mA       16mA
-1.2V     13.7mA     12.3mA     14.8mA
-895mV    12.33mA    11.01mA    13.29mA
-595mV    10.21mA    9.041mA    11.02mA
-295mV    6.197mA    5.528mA    6.714mA
955mV     -19.77mA   -17.91mA   -21.38mA
1.405V    -28.34mA   -25.55mA   -30.59mA
1.8V      -35.06mA   -31.4mA    -37.72mA
2.1V      -39.38mA   -35mA      -42.15mA
2.4V      -42.7mA    -37.6mA    -45.33mA
2.7V      -44.9mA    -39mA      -47.2mA
3V        -46mA      -41mA      -48mA
[Ramp]
dV/dt_r   0.4600/6.502e-11   0.4177/7.246e-11   0.5023/5.894e-11
dV/dt_f   0.4598/6.664e-11   0.4160/7.594e-11   0.5013/6.093e-11
R_load= 50
[Rising Waveform]
R_fixture = 50
V_fixture = 1.5
V_fixture_min = 1.425
V_fixture_max = 1.575
| Time   V(typ)   V(min)   V(max)
0s        733.3mV    728.4mV    737.8mV
285ps     733.3mV    728.4mV    731.6mV
329ps     733.8mV    728.4mV    1.215V
367ps     732.7mV    728.4mV    1.427V
416ps     1.174V     728.3mV    1.528V
453ps     1.353V     729.1mV    1.555V
507ps     1.453V     731.6mV    1.569V
578ps     1.49V      1.198V     1.574V
644ps     1.497V     1.362V     1.575V
920ps     1.5V       1.425V     1.575V
[Rising Waveform]
R_fixture = 50
V_fixture = 0
V_fixture_min = 0
V_fixture_max = 0
| Time   V(typ)   V(min)   V(max)
0s        472nV      13.46uV    98.99nV
285ps     8.683uV    13.56uV    -5.979mV
329ps     528.3uV    12.94uV    479.7mV
366ps     -2.688mV   23.02uV    685.2mV
419ps     471mV      -99.69uV   793.9mV
454ps     627.1mV    848uV      818.1mV
507ps     722.1mV    4.795mV    831.4mV
573ps     756.2mV    450.7mV    835.8mV
642ps     764.9mV    629.9mV    836.7mV
920ps     767.3mV    694mV      836.9mV
[Falling Waveform]
R_fixture = 50
V_fixture = 1.5
V_fixture_min = 1.425
V_fixture_max = 1.575
| Time   V(typ)   V(min)   V(max)
0s        1.5V       1.425V     1.575V
283ps     1.5V       1.425V     1.577V
325ps     1.5V       1.425V     1.113V
367ps     1.494V     1.425V     881.4mV
427ps     982mV      1.425V     773.2mV
507ps     777.9mV    1.423V     742.4mV
569ps     744.6mV    998.3mV    737.7mV
630ps     735.7mV    813.3mV    736.7mV
724ps     732.7mV    742.2mV    736.4mV
920ps     732.3mV    728.1mV    736.5mV
[Falling Waveform]
R_fixture = 50
V_fixture = 0
V_fixture_min = 0
V_fixture_max = 0
| Time   V(typ)   V(min)   V(max)
0s        766.3mV    693.6mV    835.5mV
281ps     766.3mV    693.6mV    838.4mV
328ps     765.8mV    693.6mV    344mV
364ps     763mV      693.6mV    149.8mV
420ps     280.8mV    693.6mV    40.85mV
459ps     122.3mV    693mV      16.68mV
505ps     46.59mV    684.6mV    5.73mV
575ps     10.66mV    231.6mV    1.158mV
642ps     2.57mV     65.12mV    227.9uV
920ps     5.553uV    325.9uV    312.2nV
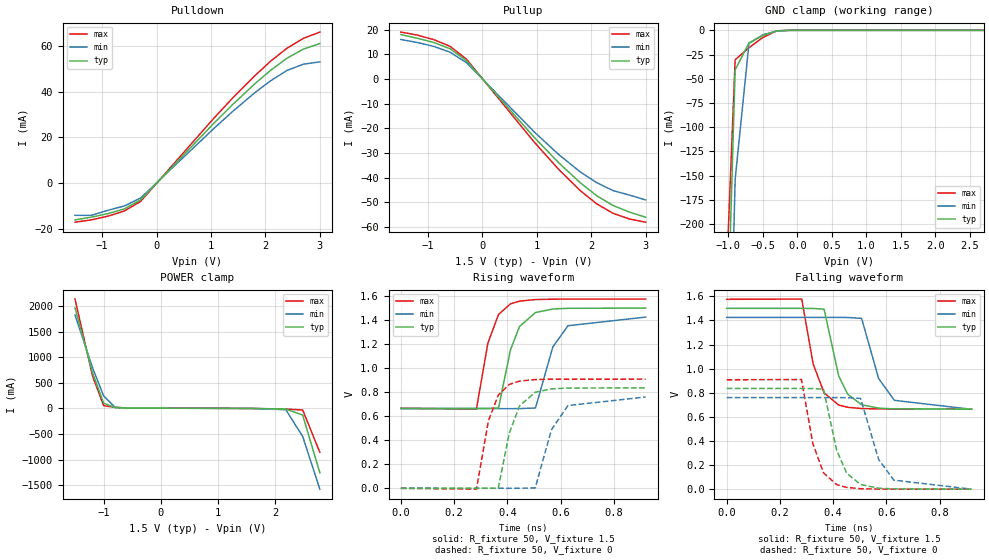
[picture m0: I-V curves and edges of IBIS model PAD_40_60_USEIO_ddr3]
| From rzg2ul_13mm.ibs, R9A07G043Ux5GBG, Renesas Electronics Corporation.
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[Model] PAD_40_60_USEIO_ddr3
Model_type I/O
Polarity   Non-Inverting
Vinl = 0.6250
Vinh = 0.8750
Vmeas= 0.750
| Capacitance   typ   min   max
C_comp   2.092e-12   2.004e-12   2.2e-12
[Model Spec]
| Subparameter   typ   min   max
Vmeas   0.750   0.713   0.787
Vinh   0.8750   0.8375   0.9125
Vinl   0.6250   0.5875   0.6625
| Variables   typ   min   max
[GND Clamp Reference]   0   0   0
[POWER Clamp Reference]   1.5   1.425   1.575
[Pulldown Reference]   0   0   0
[Pullup Reference]   1.5   1.425   1.575
[Temperature Range]   25   125   -40
[Voltage Range]   1.5   1.425   1.575
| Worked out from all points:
|   slope of the pulldown table from 0 to 0.225 V, typ, clamps not added: 39.6 ohm
|   slope of the pullup table from 0 to 0.225 V, typ, clamps not added: 39.3 ohm
|   GND clamp passes 1 mA (typ) near -0.32 V on its own axis
|   POWER clamp passes 1 mA (typ) near -0.35 V on its own axis
|   rising waveform, R_fixture 50, V_fixture 1.5: 20-80 % time 58.9ps typ, 66.1ps min, 52.9ps max; typ from 0.665 V to 1.5 V
|   rising waveform, R_fixture 50, V_fixture 0: 20-80 % time 59.5ps typ, 67.2ps min, 53.7ps max; typ from 0 V to 0.836 V
|   falling waveform, R_fixture 50, V_fixture 1.5: 20-80 % time 60.6ps typ, 69.1ps min, 55.4ps max; typ from 1.5 V to 0.664 V
|   falling waveform, R_fixture 50, V_fixture 0: 20-80 % time 60.6ps typ, 69.9ps min, 55.1ps max; typ from 0.835 V to 0 V
[GND Clamp]
| Voltage   I(typ)   I(min)   I(max)
-1.5V     -2.259A    -2.122A    -2.425A
-1.1V     -522.9mA   -708mA     -384.4mA
-900mV    -40.76mA   -153.7mA   -30.4mA
-700mV    -13.01mA   -13.6mA    -17.91mA
-500mV    -5.434mA   -4.586mA   -7.41mA
-295mV    -481.7uA   -747.1uA   -477.2uA
-105mV    -692.7nA   -8.729uA   -100nA
2.8V      0A         0A         0A
[POWER Clamp]
| Voltage   I(typ)   I(min)   I(max)
-1.5V     1.972A     1.83A      2.141A
-1.195V   702.3mA    800.9mA    640mA
-1V       103.6mA    244.6mA    53.73mA
-800mV    15.83mA    23.52mA    21.41mA
-600mV    7.48mA     6.225mA    10.31mA
1.58V     -272nA     -34.79uA   -4.532nA
2.18V     -12.19mA   -23.99mA   -12.71mA
2.475V    -129mA     -546.5mA   -30.4mA
2.775V    -1.259A    -1.58A     -858.9mA
[Pulldown]
| Voltage   I(typ)   I(min)   I(max)
-1.5V     -16mA      -14mA      -17mA
-1.2V     -14.8mA    -14mA      -16mA
-895mV    -13.26mA   -11.8mA    -14.36mA
-595mV    -11.19mA   -9.935mA   -12.12mA
-295mV    -7.269mA   -6.444mA   -7.947mA
1.055V    26.26mA    23.99mA    28.48mA
1.405V    34.52mA    31.51mA    37.4mA
1.8V      43.32mA    39.44mA    46.85mA
2.1V      49.41mA    44.82mA    53.39mA
2.4V      54.66mA    49.3mA     59.03mA
2.7V      58.6mA     52mA       63.3mA
3V        61mA       53mA       66mA
[Pullup]
| Voltage   I(typ)   I(min)   I(max)
-1.5V     18mA       16mA       19mA
-1.2V     16.5mA     14.8mA     17.8mA
-895mV    14.8mA     13.21mA    15.95mA
-595mV    12.25mA    10.85mA    13.23mA
-295mV    7.436mA    6.633mA    8.058mA
955mV     -23.72mA   -21.5mA    -25.66mA
1.405V    -34mA      -30.67mA   -36.71mA
1.8V      -42.08mA   -37.68mA   -45.26mA
2.1V      -47.26mA   -42mA      -50.58mA
2.4V      -51.24mA   -45.2mA    -54.4mA
2.7V      -53.9mA    -47mA      -56.7mA
3V        -56mA      -49mA      -58mA
[Ramp]
dV/dt_r   0.5012/5.887e-11   0.4571/6.615e-11   0.5452/5.291e-11
dV/dt_f   0.5012/6.063e-11   0.4556/6.991e-11   0.5444/5.509e-11
R_load= 50
[Rising Waveform]
R_fixture = 50
V_fixture = 1.5
V_fixture_min = 1.425
V_fixture_max = 1.575
| Time   V(typ)   V(min)   V(max)
0s        664.7mV    663mV      666.3mV
284ps     664.7mV    663mV      659mV
327ps     665.3mV    663mV      1.208V
367ps     668.5mV    663.1mV    1.447V
412ps     1.153V     662.9mV    1.535V
446ps     1.347V     663.5mV    1.558V
506ps     1.463V     668.5mV    1.571V
571ps     1.492V     1.176V     1.574V
628ps     1.498V     1.353V     1.575V
920ps     1.5V       1.425V     1.575V
[Rising Waveform]
R_fixture = 50
V_fixture = 0
V_fixture_min = 0
V_fixture_max = 0
| Time   V(typ)   V(min)   V(max)
0s        429nV      12.25uV    89.44nV
284ps     13.54uV    12.37uV    -7.229mV
329ps     737.6uV    11.64uV    561.7mV
366ps     666.3uV    23.86uV    774.8mV
407ps     455.8mV    -79.09uV   864.1mV
446ps     685.9mV    530.7uV    892.3mV
505ps     799.3mV    3.401mV    905mV
566ps     827.5mV    488.4mV    907.9mV
628ps     834.1mV    688.7mV    908.4mV
920ps     836.1mV    759.9mV    908.5mV
[Falling Waveform]
R_fixture = 50
V_fixture = 1.5
V_fixture_min = 1.425
V_fixture_max = 1.575
| Time   V(typ)   V(min)   V(max)
0s        1.5V       1.425V     1.575V
282ps     1.5V       1.425V     1.577V
325ps     1.499V     1.425V     1.038V
366ps     1.493V     1.425V     798.9mV
421ps     938.5mV    1.425V     697.8mV
455ps     787.4mV    1.424V     678.9mV
507ps     700.3mV    1.417V     668.8mV
571ps     672mV      917.9mV    665.8mV
630ps     666mV      736.9mV    665.3mV
920ps     664mV      662.6mV    665.2mV
[Falling Waveform]
R_fixture = 50
V_fixture = 0
V_fixture_min = 0
V_fixture_max = 0
| Time   V(typ)   V(min)   V(max)
0s        835.3mV    759.5mV    907.4mV
281ps     835.3mV    759.5mV    909.6mV
324ps     834.8mV    759.5mV    376mV
364ps     828.7mV    759.5mV    135.1mV
413ps     324.7mV    759.6mV    38.06mV
451ps     132mV      758.8mV    14.59mV
503ps     39.02mV    752.9mV    3.878mV
571ps     7.933mV    247.3mV    642.1uV
628ps     2.149mV    74.82mV    135.2uV
920ps     1.788uV    163.1uV    123.6nV
[Add Submodel]
| Submodel Name Mode
PAD_40_60_ddr3_T Non-Driving
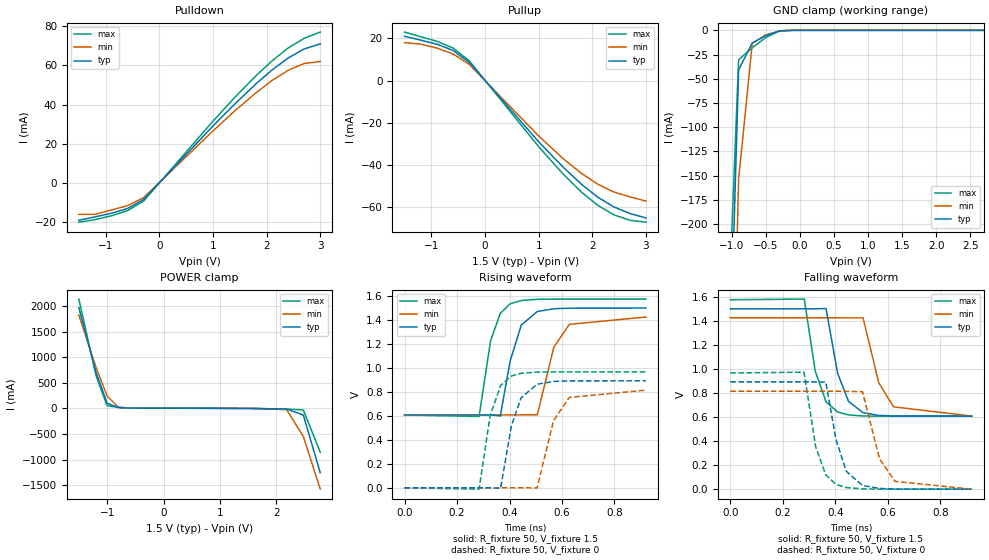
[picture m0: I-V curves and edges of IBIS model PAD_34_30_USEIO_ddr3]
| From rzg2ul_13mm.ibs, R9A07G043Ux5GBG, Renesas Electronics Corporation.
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[Model] PAD_34_30_USEIO_ddr3
Model_type I/O
Polarity   Non-Inverting
Vinl = 0.6250
Vinh = 0.8750
Vmeas= 0.750
| Capacitance   typ   min   max
C_comp   2.092e-12   2.004e-12   2.2e-12
[Model Spec]
| Subparameter   typ   min   max
Vmeas   0.750   0.713   0.787
Vinh   0.8750   0.8375   0.9125
Vinl   0.6250   0.5875   0.6625
| Variables   typ   min   max
[GND Clamp Reference]   0   0   0
[POWER Clamp Reference]   1.5   1.425   1.575
[Pulldown Reference]   0   0   0
[Pullup Reference]   1.5   1.425   1.575
[Temperature Range]   25   125   -40
[Voltage Range]   1.5   1.425   1.575
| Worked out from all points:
|   slope of the pulldown table from 0 to 0.225 V, typ, clamps not added: 33.9 ohm
|   slope of the pullup table from 0 to 0.225 V, typ, clamps not added: 33.7 ohm
|   GND clamp passes 1 mA (typ) near -0.32 V on its own axis
|   POWER clamp passes 1 mA (typ) near -0.35 V on its own axis
|   rising waveform, R_fixture 50, V_fixture 1.5: 20-80 % time 53.3ps typ, 60.1ps min, 47.8ps max; typ from 0.608 V to 1.5 V
|   rising waveform, R_fixture 50, V_fixture 0: 20-80 % time 53.8ps typ, 61.1ps min, 48.6ps max; typ from 0 V to 0.893 V
|   falling waveform, R_fixture 50, V_fixture 1.5: 20-80 % time 55.3ps typ, 63.6ps min, 50.5ps max; typ from 1.5 V to 0.607 V
|   falling waveform, R_fixture 50, V_fixture 0: 20-80 % time 55.6ps typ, 64.6ps min, 50.4ps max; typ from 0.892 V to 0 V
[GND Clamp]
| Voltage   I(typ)   I(min)   I(max)
-1.5V     -2.259A    -2.122A    -2.425A
-1.1V     -522.9mA   -708mA     -384.4mA
-900mV    -40.76mA   -153.7mA   -30.4mA
-700mV    -13.01mA   -13.6mA    -17.91mA
-500mV    -5.434mA   -4.586mA   -7.41mA
-295mV    -481.7uA   -747.1uA   -477.2uA
-105mV    -692.7nA   -8.729uA   -100nA
2.8V      0A         0A         0A
[POWER Clamp]
| Voltage   I(typ)   I(min)   I(max)
-1.5V     1.972A     1.83A      2.141A
-1.195V   702.3mA    800.9mA    640mA
-1V       103.6mA    244.6mA    53.73mA
-800mV    15.83mA    23.52mA    21.41mA
-600mV    7.48mA     6.225mA    10.31mA
1.58V     -272nA     -34.79uA   -4.532nA
2.18V     -12.19mA   -23.99mA   -12.71mA
2.475V    -129mA     -546.5mA   -30.4mA
2.775V    -1.259A    -1.58A     -858.9mA
[Pulldown]
| Voltage   I(typ)   I(min)   I(max)
-1.5V     -19mA      -16mA      -20mA
-1.2V     -17.3mA    -16mA      -18.7mA
-895mV    -15.47mA   -13.8mA    -16.75mA
-595mV    -13.05mA   -11.59mA   -14.14mA
-295mV    -8.481mA   -7.519mA   -9.272mA
1.005V    29.22mA    26.7mA     31.7mA
1.405V    40.27mA    36.76mA    43.63mA
1.8V      50.54mA    46.01mA    54.66mA
2.1V      57.64mA    52.29mA    62.28mA
2.4V      63.77mA    57.5mA     68.86mA
2.7V      68.4mA     61mA       73.8mA
3V        71mA       62mA       77mA
[Pullup]
| Voltage   I(typ)   I(min)   I(max)
-1.5V     21mA       18mA       23mA
-1.2V     19.2mA     17.3mA     20.8mA
-895mV    17.26mA    15.41mA    18.61mA
-595mV    14.29mA    12.66mA    15.43mA
-295mV    8.675mA    7.738mA    9.4mA
1.005V    -29.06mA   -26.32mA   -31.42mA
1.455V    -40.93mA   -36.89mA   -44.17mA
1.8V      -49.09mA   -43.96mA   -52.8mA
2.1V      -55.13mA   -49mA      -59.01mA
2.4V      -59.74mA   -52.7mA    -63.47mA
2.7V      -62.9mA    -55mA      -66.1mA
3V        -65mA      -57mA      -67mA
[Ramp]
dV/dt_r   0.5353/5.330e-11   0.4899/6.015e-11   0.5806/4.784e-11
dV/dt_f   0.5354/5.563e-11   0.4887/6.456e-11   0.5800/5.035e-11
R_load= 50
[Rising Waveform]
R_fixture = 50
V_fixture = 1.5
V_fixture_min = 1.425
V_fixture_max = 1.575
| Time   V(typ)   V(min)   V(max)
0s        607.9mV    608.4mV    607.4mV
284ps     607.9mV    608.4mV    595.7mV
328ps     608.5mV    608.4mV    1.229V
365ps     599.5mV    608.4mV    1.456V
402ps     1.055V     608.3mV    1.535V
445ps     1.359V     608.8mV    1.563V
506ps     1.471V     609.6mV    1.573V
569ps     1.494V     1.174V     1.575V
628ps     1.499V     1.364V     1.575V
920ps     1.5V       1.425V     1.575V
[Rising Waveform]
R_fixture = 50
V_fixture = 0
V_fixture_min = 0
V_fixture_max = 0
| Time   V(typ)   V(min)   V(max)
0s        392.5nV    11.25uV    80.79nV
284ps     12.14uV    11.36uV    -11.37mV
326ps     470.7uV    10.71uV    601.2mV
366ps     -4.142mV   23.29uV    852.5mV
407ps     514.9mV    -88.54uV   933mV
444ps     750.8mV    410.9uV    955.7mV
505ps     864.3mV    -1.251mV   965.7mV
568ps     887.7mV    561.6mV    967.3mV
628ps     891.9mV    754.3mV    967.5mV
920ps     893.1mV    815mV      967.5mV
[Falling Waveform]
R_fixture = 50
V_fixture = 1.5
V_fixture_min = 1.425
V_fixture_max = 1.575
| Time   V(typ)   V(min)   V(max)
0s        1.5V       1.425V     1.575V
282ps     1.5V       1.425V     1.581V
324ps     1.5V       1.425V     980.2mV
365ps     1.502V     1.425V     726.8mV
409ps     965mV      1.425V     641.5mV
451ps     728.1mV    1.424V     617.6mV
506ps     636.6mV    1.424V     608.8mV
566ps     613.4mV    884.5mV    606.9mV
622ps     608.7mV    684.7mV    606.6mV
920ps     607.3mV    608mV      606.5mV
[Falling Waveform]
R_fixture = 50
V_fixture = 0
V_fixture_min = 0
V_fixture_max = 0
| Time   V(typ)   V(min)   V(max)
0s        892.4mV    814.6mV    966.6mV
281ps     892.4mV    814.6mV    972.7mV
326ps     891.8mV    814.6mV    348.2mV
364ps     891mV      814.6mV    119.2mV
403ps     411.8mV    814.6mV    39.38mV
442ps     149mV      814.1mV    13.35mV
504ps     30.59mV    810.1mV    2.352mV
569ps     5.728mV    251.5mV    316uV
628ps     1.302mV    64.83mV    60uV
920ps     740.1nV    82.47uV    88.25nV
[Add Submodel]
| Submodel Name Mode
PAD_34_30_ddr3_T Non-Driving
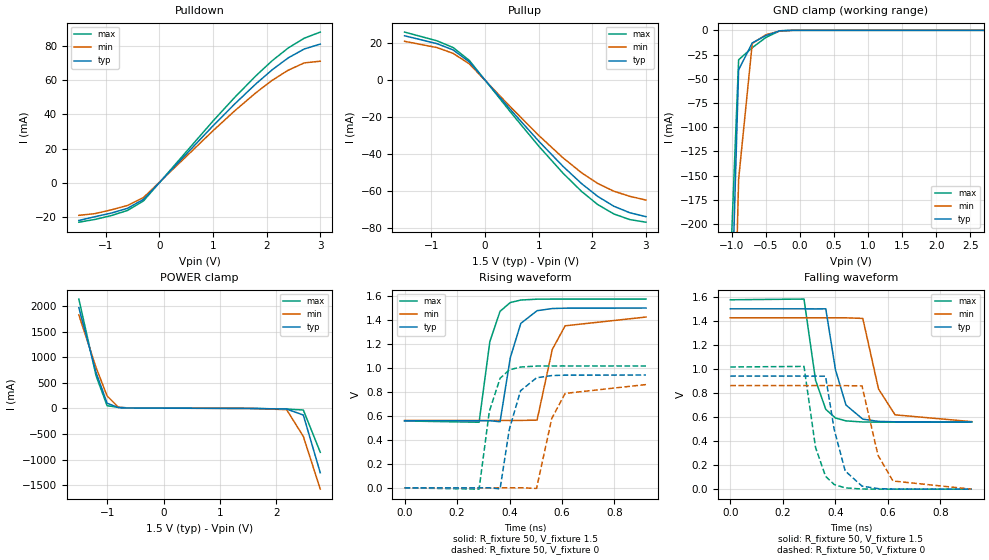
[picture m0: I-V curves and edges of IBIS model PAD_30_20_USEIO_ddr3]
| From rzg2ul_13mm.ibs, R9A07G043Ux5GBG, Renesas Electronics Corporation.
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[Model] PAD_30_20_USEIO_ddr3
Model_type I/O
Polarity   Non-Inverting
Vinl = 0.6250
Vinh = 0.8750
Vmeas= 0.750
| Capacitance   typ   min   max
C_comp   2.092e-12   2.004e-12   2.2e-12
[Model Spec]
| Subparameter   typ   min   max
Vmeas   0.750   0.713   0.787
Vinh   0.8750   0.8375   0.9125
Vinl   0.6250   0.5875   0.6625
| Variables   typ   min   max
[GND Clamp Reference]   0   0   0
[POWER Clamp Reference]   1.5   1.425   1.575
[Pulldown Reference]   0   0   0
[Pullup Reference]   1.5   1.425   1.575
[Temperature Range]   25   125   -40
[Voltage Range]   1.5   1.425   1.575
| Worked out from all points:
|   slope of the pulldown table from 0 to 0.225 V, typ, clamps not added: 29.7 ohm
|   slope of the pullup table from 0 to 0.225 V, typ, clamps not added: 29.5 ohm
|   GND clamp passes 1 mA (typ) near -0.32 V on its own axis
|   POWER clamp passes 1 mA (typ) near -0.35 V on its own axis
|   rising waveform, R_fixture 50, V_fixture 1.5: 20-80 % time 49.1ps typ, 55.4ps min, 43.8ps max; typ from 0.56 V to 1.5 V
|   rising waveform, R_fixture 50, V_fixture 0: 20-80 % time 49.4ps typ, 56ps min, 44.3ps max; typ from 0 V to 0.941 V
|   falling waveform, R_fixture 50, V_fixture 1.5: 20-80 % time 51ps typ, 59.5ps min, 46.5ps max; typ from 1.5 V to 0.559 V
|   falling waveform, R_fixture 50, V_fixture 0: 20-80 % time 51.5ps typ, 60.5ps min, 46.7ps max; typ from 0.941 V to 0 V
[GND Clamp]
| Voltage   I(typ)   I(min)   I(max)
-1.5V     -2.259A    -2.122A    -2.425A
-1.1V     -522.9mA   -708mA     -384.4mA
-900mV    -40.76mA   -153.7mA   -30.4mA
-700mV    -13.01mA   -13.6mA    -17.91mA
-500mV    -5.434mA   -4.586mA   -7.41mA
-295mV    -481.7uA   -747.1uA   -477.2uA
-105mV    -692.7nA   -8.729uA   -100nA
2.8V      0A         0A         0A
[POWER Clamp]
| Voltage   I(typ)   I(min)   I(max)
-1.5V     1.972A     1.83A      2.141A
-1.195V   702.3mA    800.9mA    640mA
-1V       103.6mA    244.6mA    53.73mA
-800mV    15.83mA    23.52mA    21.41mA
-600mV    7.48mA     6.225mA    10.31mA
1.58V     -272nA     -34.79uA   -4.532nA
2.18V     -12.19mA   -23.99mA   -12.71mA
2.475V    -129mA     -546.5mA   -30.4mA
2.775V    -1.259A    -1.58A     -858.9mA
[Pulldown]
| Voltage   I(typ)   I(min)   I(max)
-1.5V     -22mA      -19mA      -23mA
-1.2V     -19.8mA    -18mA      -21.4mA
-895mV    -17.68mA   -15.8mA    -19.14mA
-595mV    -14.92mA   -13.25mA   -16.16mA
-295mV    -9.688mA   -8.593mA   -10.59mA
1.005V    33.4mA     30.52mA    36.23mA
1.405V    46.03mA    42.01mA    49.86mA
1.8V      57.76mA    52.58mA    62.47mA
2.1V      65.88mA    59.76mA    71.18mA
2.4V      72.89mA    65.7mA     78.67mA
2.7V      78.1mA     70mA       84.4mA
3V        81mA       71mA       88mA
[Pullup]
| Voltage   I(typ)   I(min)   I(max)
-1.5V     24mA       21mA       26mA
-895mV    19.73mA    17.61mA    21.27mA
-595mV    16.33mA    14.47mA    17.63mA
-295mV    9.912mA    8.844mA    10.74mA
500mV     -16.84mA   -15.31mA   -18.22mA
1.005V    -33.21mA   -30.08mA   -35.91mA
1.455V    -46.78mA   -42.16mA   -50.48mA
1.8V      -56.1mA    -50.24mA   -60.34mA
2.1V      -63.01mA   -56mA      -67.44mA
2.4V      -68.34mA   -60.2mA    -72.53mA
2.7V      -71.9mA    -63mA      -75.6mA
3V        -74mA      -65mA      -77mA
[Ramp]
dV/dt_r   0.5640/4.912e-11   0.5177/5.538e-11   0.6102/4.383e-11
dV/dt_f   0.5643/5.153e-11   0.5167/6.048e-11   0.6097/4.668e-11
R_load= 50
[Rising Waveform]
R_fixture = 50
V_fixture = 1.5
V_fixture_min = 1.425
V_fixture_max = 1.575
| Time   V(typ)   V(min)   V(max)
0s        560mV      562mV      558mV
284ps     560mV      562mV      547.2mV
325ps     560.5mV    562mV      1.22V
364ps     551.1mV    562mV      1.473V
403ps     1.086V     561.9mV    1.546V
443ps     1.372V     562.5mV    1.567V
505ps     1.478V     565mV      1.574V
563ps     1.496V     1.155V     1.575V
612ps     1.499V     1.352V     1.575V
920ps     1.5V       1.425V     1.575V
[Rising Waveform]
R_fixture = 50
V_fixture = 0
V_fixture_min = 0
V_fixture_max = 0
| Time   V(typ)   V(min)   V(max)
0s        361.7nV    10.39uV    74.97nV
284ps     14.34uV    10.53uV    -11.06mV
323ps     360.5uV    9.786uV    637mV
364ps     -8.952mV   22.58uV    913.9mV
399ps     485.8mV    -54.55uV   983.7mV
442ps     810.1mV    427.2uV    1.008V
503ps     918.2mV    -4.631mV   1.016V
561ps     936.8mV    578.8mV    1.017V
612ps     940.2mV    787.8mV    1.017V
920ps     941.1mV    861.6mV    1.017V
[Falling Waveform]
R_fixture = 50
V_fixture = 1.5
V_fixture_min = 1.425
V_fixture_max = 1.575
| Time   V(typ)   V(min)   V(max)
0s        1.5V       1.425V     1.575V
281ps     1.5V       1.425V     1.581V
325ps     1.499V     1.425V     906.3mV
364ps     1.5V       1.425V     663.7mV
401ps     992.2mV    1.425V     591.8mV
441ps     699.5mV    1.425V     567.8mV
505ps     582.5mV    1.42V      558.8mV
565ps     563.7mV    833.4mV    557.5mV
628ps     560.2mV    618.1mV    557.3mV
920ps     559.5mV    561.7mV    557.3mV
[Falling Waveform]
R_fixture = 50
V_fixture = 0
V_fixture_min = 0
V_fixture_max = 0
| Time   V(typ)   V(min)   V(max)
0s        940.5mV    861.3mV    1.016V
281ps     940.5mV    861.3mV    1.021V
325ps     939.9mV    861.3mV    346.8mV
363ps     939.4mV    861.3mV    107.6mV
396ps     496.9mV    861.3mV    38.56mV
438ps     151.5mV    860.9mV    10.64mV
502ps     25.28mV    858.8mV    1.43mV
563ps     4.571mV    282.5mV    204.5uV
620ps     933.1uV    67.95mV    31.01uV
920ps     443.9nV    44.05uV    77.28nV
[Add Submodel]
| Submodel Name Mode
PAD_30_20_ddr3_T Non-Driving
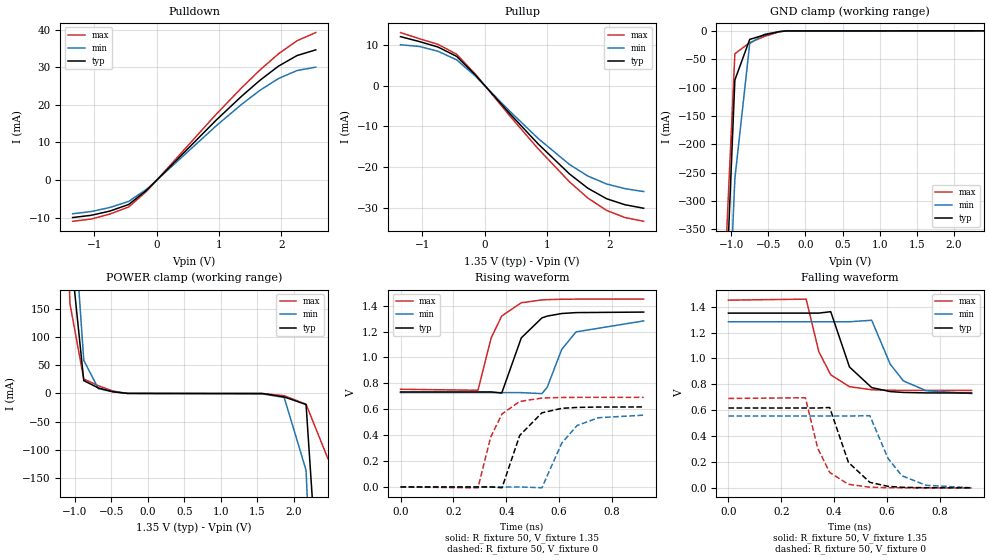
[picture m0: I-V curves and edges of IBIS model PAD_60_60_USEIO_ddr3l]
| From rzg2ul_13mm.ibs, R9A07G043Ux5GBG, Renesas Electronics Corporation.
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[Model] PAD_60_60_USEIO_ddr3l
Model_type I/O
Polarity   Non-Inverting
Vinl = 0.5400
Vinh = 0.8100
Vmeas= 0.675
| Capacitance   typ   min   max
C_comp   2.097e-12   2.007e-12   2.204e-12
[Model Spec]
| Subparameter   typ   min   max
Vmeas   0.675   0.641   0.725
Vinh   0.8100   0.7765   0.8600
Vinl   0.5400   0.5065   0.5900
| Variables   typ   min   max
[GND Clamp Reference]   0   0   0
[POWER Clamp Reference]   1.35   1.283   1.45
[Pulldown Reference]   0   0   0
[Pullup Reference]   1.35   1.283   1.45
[Temperature Range]   25   125   -40
[Voltage Range]   1.35   1.283   1.45
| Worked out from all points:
|   slope of the pulldown table from 0 to 0.203 V, typ, clamps not added: 58.8 ohm
|   slope of the pullup table from 0 to 0.203 V, typ, clamps not added: 58.1 ohm
|   GND clamp passes 1 mA (typ) near -0.32 V on its own axis
|   POWER clamp passes 1 mA (typ) near -0.34 V on its own axis
|   rising waveform, R_fixture 50, V_fixture 1.35: 20-80 % time 72.5ps typ, 80.8ps min, 66.2ps max; typ from 0.733 V to 1.35 V
|   rising waveform, R_fixture 50, V_fixture 0: 20-80 % time 74.9ps typ, 84.5ps min, 68.4ps max; typ from 0 V to 0.618 V
|   falling waveform, R_fixture 50, V_fixture 1.35: 20-80 % time 75.2ps typ, 83.9ps min, 68.4ps max; typ from 1.35 V to 0.733 V
|   falling waveform, R_fixture 50, V_fixture 0: 20-80 % time 74.3ps typ, 82.9ps min, 67.4ps max; typ from 0.617 V to 0 V
[GND Clamp]
| Voltage   I(typ)   I(min)   I(max)
-1.35V    -1.588A    -1.578A    -1.632A
-1.15V    -723.3mA   -875.4mA   -612.6mA
-950mV    -86.72mA   -260.7mA   -40.53mA
-750mV    -15.17mA   -22.59mA   -20.75mA
-550mV    -7.18mA    -5.89mA    -9.856mA
-350mV    -1.329mA   -1.495mA   -1.608mA
-260mV    -191.7uA   -416.3uA   -143.8uA
2.4V      0A         0A         0A
[POWER Clamp]
| Voltage   I(typ)   I(min)   I(max)
-1.35V    1.332A     1.303A     1.384A
-1.07V    261.9mA    413.7mA    159.6mA
-880mV    22.79mA    58.77mA    25.66mA
-680mV    9.824mA    8.594mA    13.78mA
-480mV    3.118mA    2.85mA     4.348mA
-280mV    118.8uA    285.7uA    106.4uA
1.57V     -51.57uA   -692.4uA   -197.8nA
1.87V     -6.117mA   -7.08mA    -3.933mA
2.17V     -19.54mA   -136.1mA   -19.04mA
2.47V     -601.3mA   -1.013A    -115.5mA
[Pulldown]
| Voltage   I(typ)   I(min)   I(max)
-1.35V    -10mA      -9mA       -11mA
-1.05V    -9.4mA     -8.4mA     -10.4mA
-750mV    -8.27mA    -7.32mA    -9.06mA
-450mV    -6.528mA   -5.709mA   -7.182mA
-150mV    -2.555mA   -2.314mA   -2.802mA
955mV     15.94mA    14.43mA    17.51mA
1.36V     22.26mA    20.1mA     24.49mA
1.655V    26.51mA    23.84mA    29.24mA
1.955V    30.3mA     27mA       33.58mA
2.25V     33.09mA    29.1mA     37.03mA
2.55V     34.6mA     30mA       39.2mA
[Pullup]
| Voltage   I(typ)   I(min)   I(max)
-1.35V    12mA       10mA       13mA
-1.05V    10.8mA     9.6mA      11.5mA
-750mV    9.46mA     8.42mA     10.12mA
-450mV    7.16mA     6.31mA     7.684mA
-150mV    2.603mA    2.33mA     2.798mA
400mV     -6.837mA   -6.265mA   -7.381mA
855mV     -14.28mA   -12.95mA   -15.47mA
1.36V     -21.68mA   -19.36mA   -23.62mA
1.655V    -25.19mA   -22.2mA    -27.6mA
1.955V    -27.76mA   -24.14mA   -30.63mA
2.25V     -29.24mA   -25.3mA    -32.38mA
2.55V     -30.1mA    -26mA      -33.3mA
[Ramp]
dV/dt_r   0.3699/7.252e-11   0.3323/8.078e-11   0.4175/6.615e-11
dV/dt_f   0.3701/7.427e-11   0.3323/8.293e-11   0.4143/6.744e-11
R_load= 50
[Rising Waveform]
R_fixture = 50
V_fixture = 1.35
V_fixture_min = 1.283
V_fixture_max = 1.45
| Time   V(typ)   V(min)   V(max)
0s        733.5mV    728.2mV    754.1mV
293ps     733.5mV    728.2mV    746.5mV
343ps     733.8mV    728.2mV    1.151V
383ps     725.1mV    728.2mV    1.32V
457ps     1.151V     728.2mV    1.422V
535ps     1.305V     720.4mV    1.444V
555ps     1.319V     769.8mV    1.446V
610ps     1.339V     1.062V     1.449V
664ps     1.346V     1.197V     1.45V
920ps     1.35V      1.282V     1.45V
[Rising Waveform]
R_fixture = 50
V_fixture = 0
V_fixture_min = 0
V_fixture_max = 0
| Time   V(typ)   V(min)   V(max)
0s        246.4nV    8.619uV    51.97nV
293ps     5.974uV    8.643uV    -6.89mV
341ps     220.9uV    8.186uV    383.8mV
384ps     -5.943mV   18.26uV    564mV
451ps     397.9mV    -62.74uV   660mV
535ps     572.5mV    -5.85mV    686.5mV
610ps     606.9mV    338.4mV    690.8mV
668ps     614.2mV    474mV      691.6mV
748ps     616.9mV    534.4mV    691.8mV
920ps     617.7mV    554.3mV    691.9mV
[Falling Waveform]
R_fixture = 50
V_fixture = 1.35
V_fixture_min = 1.283
V_fixture_max = 1.45
| Time   V(typ)   V(min)   V(max)
0s        1.35V      1.283V     1.45V
294ps     1.35V      1.283V     1.458V
342ps     1.35V      1.283V     1.052V
387ps     1.361V     1.283V     873.4mV
458ps     933.7mV    1.283V     781.4mV
542ps     774.4mV    1.295V     757.8mV
612ps     743.7mV    956.1mV    754mV
662ps     737mV      826.2mV    753.3mV
748ps     733.5mV    750.6mV    752.9mV
920ps     732.7mV    728.8mV    752.9mV
[Falling Waveform]
R_fixture = 50
V_fixture = 0
V_fixture_min = 0
V_fixture_max = 0
| Time   V(typ)   V(min)   V(max)
0s        616.9mV    554.9mV    690.6mV
291ps     616.9mV    554.9mV    696.1mV
338ps     616.7mV    554.9mV    304.8mV
383ps     620.8mV    554.9mV    119.3mV
454ps     196.9mV    554.8mV    27.33mV
535ps     42.77mV    557.5mV    5.151mV
604ps     11.51mV    227.4mV    1.154mV
656ps     4.474mV    93.71mV    422.9uV
748ps     799.7uV    19.58mV    58.62uV
920ps     24.42uV    1.032mV    1.176uV
[Add Submodel]
| Submodel Name Mode
PAD_60_60_ddr3l_T Non-Driving
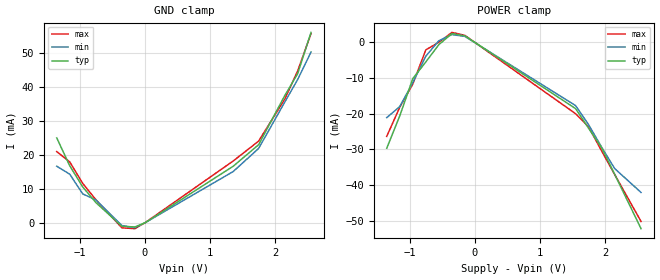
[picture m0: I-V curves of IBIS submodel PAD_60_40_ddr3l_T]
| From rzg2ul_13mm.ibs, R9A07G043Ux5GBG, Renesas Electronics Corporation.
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[Submodel]  PAD_60_40_ddr3l_T
Submodel_type Dynamic_clamp
[GND Clamp]
| Voltage   I(typ)   I(min)   I(max)
-1.35V    25.05mA    16.71mA    21.02mA
-1.15V    16.82mA    14.36mA    17.96mA
-950mV    10.59mA    8.539mA    11.62mA
-750mV    6.028mA    6.811mA    6.89mA
-350mV    -980uA     -739.8uA   -1.417mA
-150mV    -1.167mA   -1.384mA   -1.667mA
10mV      100.4uA    112uA      131uA
1.36V     16.71mA    15.15mA    18.25mA
1.75V     23.04mA    21.94mA    24.1mA
2.15V     37.43mA    35.52mA    36.39mA
2.35V     43.97mA    42.23mA    44.78mA
2.555V    56.1mA     50.33mA    55.75mA
[POWER Clamp]
| Voltage   I(typ)   I(min)   I(max)
-1.35V    -29.64mA   -21.1mA    -26.33mA
-1.15V    -20.61mA   -18.01mA   -18.19mA
-950mV    -10.19mA   -11.33mA   -11.73mA
-750mV    -5.533mA   -3.924mA   -2.162mA
-550mV    -704.8uA   388uA      -53.1uA
-350mV    2.39mA     2.101mA    2.72mA
-150mV    1.756mA    1.598mA    1.885mA
1.55V     -18.58mA   -17.73mA   -20mA
1.75V     -24.06mA   -23.06mA   -23.68mA
1.95V     -29.52mA   -29.36mA   -30.43mA
2.15V     -36.92mA   -35.32mA   -36.98mA
2.555V    -52.12mA   -42.01mA   -50.11mA
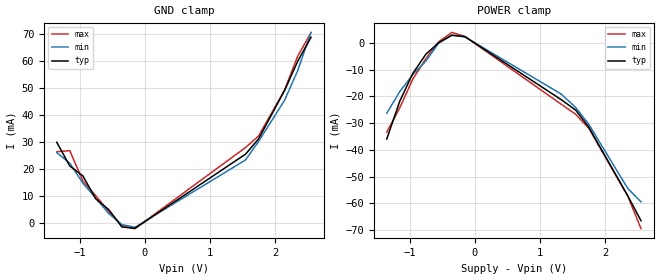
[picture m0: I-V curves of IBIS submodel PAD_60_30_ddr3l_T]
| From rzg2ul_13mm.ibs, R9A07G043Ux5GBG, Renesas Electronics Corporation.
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[Submodel]  PAD_60_30_ddr3l_T
Submodel_type Dynamic_clamp
[GND Clamp]
| Voltage   I(typ)   I(min)   I(max)
-1.35V    29.8mA     25.97mA    26.29mA
-1.15V    21.01mA    22.05mA    26.7mA
-950mV    17.35mA    14.68mA    15.49mA
-750mV    8.811mA    9.082mA    9.941mA
-550mV    4.807mA    3.345mA    4.138mA
-350mV    -1.602mA   -688.5uA   -1.021mA
-150mV    -2.11mA    -1.734mA   -2.222mA
1.55V     25.4mA     23.25mA    27.86mA
1.75V     31.06mA    30.12mA    32.14mA
2.15V     49.05mA    45.41mA    49.21mA
2.35V     59.79mA    56.31mA    61.67mA
2.555V    68.7mA     70.5mA     70.43mA
[POWER Clamp]
| Voltage   I(typ)   I(min)   I(max)
-1.35V    -35.92mA   -26.29mA   -33.37mA
-1.15V    -21.79mA   -18.21mA   -24.26mA
-950mV    -11.43mA   -11.81mA   -13.54mA
-750mV    -4.261mA   -6.812mA   -5.922mA
-550mV    93.7uA     -4.263uA   436.2uA
-350mV    2.893mA    2.802mA    3.915mA
-150mV    2.341mA    2.24mA     2.402mA
1.325V    -21.14mA   -19.06mA   -22.85mA
1.55V     -25.08mA   -24.08mA   -26.66mA
1.75V     -31.4mA    -30.32mA   -31.81mA
2.35V     -57.08mA   -54.36mA   -57.19mA
2.555V    -66.47mA   -59.39mA   -69.41mA
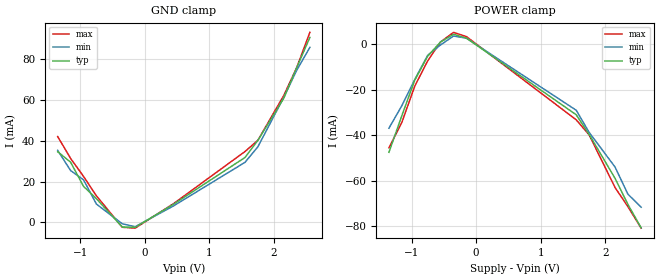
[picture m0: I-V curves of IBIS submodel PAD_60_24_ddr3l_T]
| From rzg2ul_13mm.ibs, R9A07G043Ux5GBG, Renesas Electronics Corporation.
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[Submodel]  PAD_60_24_ddr3l_T
Submodel_type Dynamic_clamp
[GND Clamp]
| Voltage   I(typ)   I(min)   I(max)
-1.35V    34.56mA    35.23mA    41.98mA
-1.15V    29.45mA    25.38mA    31.31mA
-950mV    17.65mA    20.84mA    22.51mA
-750mV    11.6mA     8.975mA    13mA
-350mV    -2.222mA   -640uA     -2.361mA
-150mV    -2.388mA   -2.084mA   -2.778mA
445mV     8.947mA    8.11mA     9.219mA
1.55V     31.75mA    29.38mA    34.66mA
1.75V     40.13mA    37mA       40.18mA
2.15V     60.68mA    61.13mA    62.04mA
2.35V     75.62mA    74.32mA    75.62mA
2.555V    90.45mA    85.59mA    92.91mA
[POWER Clamp]
| Voltage   I(typ)   I(min)   I(max)
-1.35V    -47.6mA    -37.01mA   -45.62mA
-1.15V    -31.5mA    -27.11mA   -34.45mA
-950mV    -15.9mA    -15.59mA   -18.5mA
-750mV    -5.328mA   -4.966mA   -7.402mA
-550mV    892.2uA    -392.2uA   925.5uA
-350mV    4.278mA    3.502mA    5.112mA
-150mV    2.592mA    2.554mA    3.251mA
1.55V     -31.11mA   -29.12mA   -33.33mA
1.75V     -39.76mA   -38.86mA   -39.95mA
2.15V     -58.99mA   -54.02mA   -63.02mA
2.35V     -70.48mA   -65.99mA   -71.49mA
2.555V    -80.79mA   -71.72mA   -80.93mA
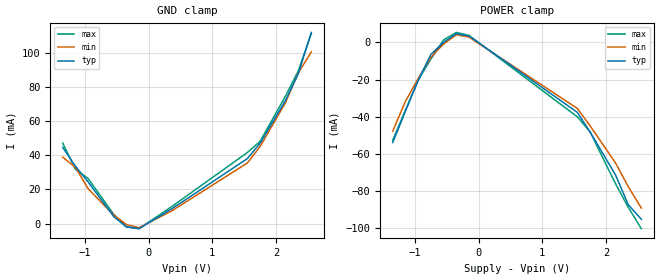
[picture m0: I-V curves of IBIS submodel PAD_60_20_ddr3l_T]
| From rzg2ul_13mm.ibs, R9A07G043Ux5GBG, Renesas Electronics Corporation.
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[Submodel]  PAD_60_20_ddr3l_T
Submodel_type Dynamic_clamp
[GND Clamp]
| Voltage   I(typ)   I(min)   I(max)
-1.35V    44.71mA    38.94mA    47.25mA
-1.15V    33.64mA    33.07mA    31.8mA
-950mV    24.41mA    20.38mA    26.38mA
-550mV    4.119mA    5.022mA    5.447mA
-350mV    -1.963mA   -588.7uA   -1.965mA
-150mV    -2.999mA   -2.433mA   -3.002mA
365mV     8.682mA    7.487mA    10.01mA
1.55V     38.1mA     35.52mA    41.67mA
1.75V     47.12mA    45.18mA    48.22mA
2.15V     72.3mA     71.02mA    74.86mA
2.35V     87.94mA    88.4mA     89.58mA
2.555V    112.2mA    100.7mA    111.5mA
[POWER Clamp]
| Voltage   I(typ)   I(min)   I(max)
-1.35V    -53.88mA   -47.73mA   -52.66mA
-1.15V    -36.95mA   -31.67mA   -36.39mA
-950mV    -20.38mA   -19.36mA   -20.3mA
-750mV    -6.394mA   -7.854mA   -8.881mA
-550mV    142.6uA    -784.5uA   1.415mA
-350mV    4.781mA    4.203mA    5.438mA
-150mV    3.511mA    2.868mA    3.769mA
1.55V     -37.61mA   -35.47mA   -39.99mA
1.75V     -48.12mA   -44.84mA   -48.08mA
2.15V     -71.3mA    -64.82mA   -76.04mA
2.35V     -87.35mA   -77.61mA   -88.7mA
2.555V    -95.14mA   -89.1mA    -100.2mA
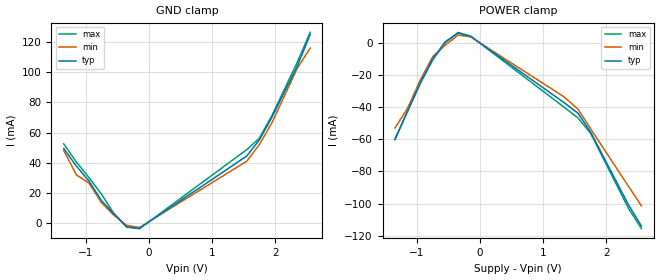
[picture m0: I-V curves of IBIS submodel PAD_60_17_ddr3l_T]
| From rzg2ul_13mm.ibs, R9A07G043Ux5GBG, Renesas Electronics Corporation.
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[Submodel]  PAD_60_17_ddr3l_T
Submodel_type Dynamic_clamp
[GND Clamp]
| Voltage   I(typ)   I(min)   I(max)
-1.35V    49.46mA    48.2mA     52.52mA
-1.15V    37.82mA    32.04mA    40.54mA
-950mV    27.94mA    26.53mA    30.26mA
-750mV    14.84mA    13.52mA    19.11mA
-550mV    6.095mA    5.073mA    6.103mA
-350mV    -2.582mA   -1.428mA   -2.438mA
-150mV    -3.277mA   -2.784mA   -3.558mA
1.55V     44.44mA    41.01mA    48.69mA
1.75V     55.14mA    52.06mA    56.24mA
1.95V     70.2mA     66.54mA    71.3mA
2.35V     103.8mA    102.5mA    106.4mA
2.555V    124.8mA    115.8mA    126.2mA
[POWER Clamp]
| Voltage   I(typ)   I(min)   I(max)
-1.35V    -60.16mA   -52.91mA   -59.7mA
-1.15V    -42.4mA    -40.57mA   -42.45mA
-950mV    -24.86mA   -23.14mA   -25.26mA
-750mV    -9.794mA   -8.372mA   -10.36mA
-550mV    941.1uA    -1.177mA   383.1uA
-350mV    6.168mA    4.903mA    6.636mA
-150mV    4.097mA    3.838mA    4.287mA
1.325V    -36.98mA   -33.39mA   -39.82mA
1.55V     -43.65mA   -41.16mA   -46.66mA
1.75V     -55.46mA   -53.38mA   -56.22mA
2.35V     -100.8mA   -89.26mA   -103mA
2.555V    -114mA     -101.4mA   -115.6mA
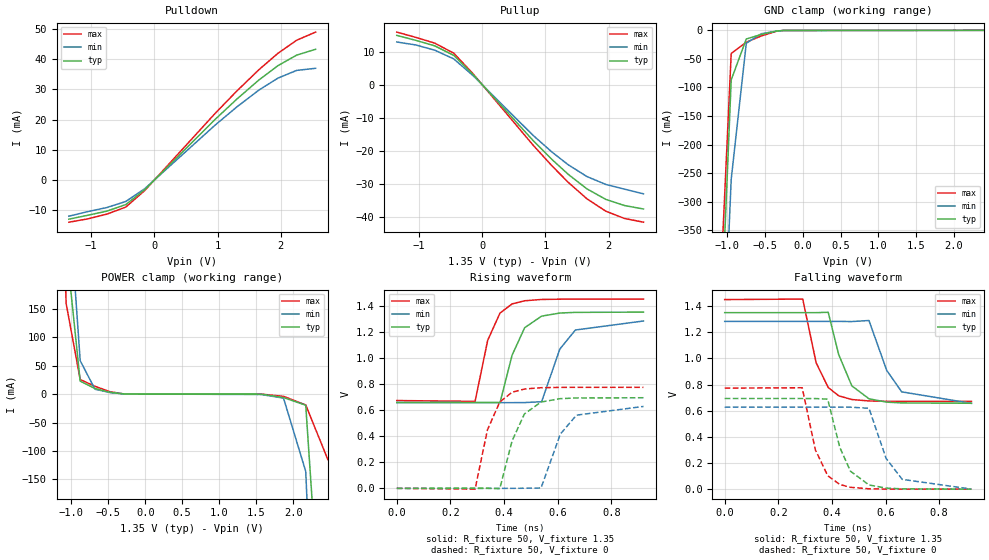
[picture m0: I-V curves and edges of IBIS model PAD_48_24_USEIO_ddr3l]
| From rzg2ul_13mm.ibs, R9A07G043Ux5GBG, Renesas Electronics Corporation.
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[Model] PAD_48_24_USEIO_ddr3l
Model_type I/O
Polarity   Non-Inverting
Vinl = 0.5400
Vinh = 0.8100
Vmeas= 0.675
| Capacitance   typ   min   max
C_comp   2.097e-12   2.007e-12   2.204e-12
[Model Spec]
| Subparameter   typ   min   max
Vmeas   0.675   0.641   0.725
Vinh   0.8100   0.7765   0.8600
Vinl   0.5400   0.5065   0.5900
| Variables   typ   min   max
[GND Clamp Reference]   0   0   0
[POWER Clamp Reference]   1.35   1.283   1.45
[Pulldown Reference]   0   0   0
[Pullup Reference]   1.35   1.283   1.45
[Temperature Range]   25   125   -40
[Voltage Range]   1.35   1.283   1.45
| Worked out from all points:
|   slope of the pulldown table from 0 to 0.203 V, typ, clamps not added: 47.1 ohm
|   slope of the pullup table from 0 to 0.203 V, typ, clamps not added: 46.5 ohm
|   GND clamp passes 1 mA (typ) near -0.32 V on its own axis
|   POWER clamp passes 1 mA (typ) near -0.34 V on its own axis
|   rising waveform, R_fixture 50, V_fixture 1.35: 20-80 % time 64.9ps typ, 73.1ps min, 58.8ps max; typ from 0.658 V to 1.35 V
|   rising waveform, R_fixture 50, V_fixture 0: 20-80 % time 66.8ps typ, 75.7ps min, 60.3ps max; typ from 0 V to 0.694 V
|   falling waveform, R_fixture 50, V_fixture 1.35: 20-80 % time 67.2ps typ, 76.1ps min, 61.1ps max; typ from 1.35 V to 0.657 V
|   falling waveform, R_fixture 50, V_fixture 0: 20-80 % time 66.7ps typ, 75.3ps min, 60.1ps max; typ from 0.693 V to 0 V
[GND Clamp]
| Voltage   I(typ)   I(min)   I(max)
-1.35V    -1.588A    -1.578A    -1.632A
-1.15V    -723.3mA   -875.4mA   -612.6mA
-950mV    -86.72mA   -260.7mA   -40.53mA
-750mV    -15.17mA   -22.59mA   -20.75mA
-550mV    -7.18mA    -5.89mA    -9.856mA
-350mV    -1.329mA   -1.495mA   -1.608mA
-260mV    -191.7uA   -416.3uA   -143.8uA
2.4V      0A         0A         0A
[POWER Clamp]
| Voltage   I(typ)   I(min)   I(max)
-1.35V    1.332A     1.303A     1.384A
-1.07V    261.9mA    413.7mA    159.6mA
-880mV    22.79mA    58.77mA    25.66mA
-680mV    9.824mA    8.594mA    13.78mA
-480mV    3.118mA    2.85mA     4.348mA
-280mV    118.8uA    285.7uA    106.4uA
1.57V     -51.57uA   -692.4uA   -197.8nA
1.87V     -6.117mA   -7.08mA    -3.933mA
2.17V     -19.54mA   -136.1mA   -19.04mA
2.47V     -601.3mA   -1.013A    -115.5mA
[Pulldown]
| Voltage   I(typ)   I(min)   I(max)
-1.35V    -13mA      -12mA      -14mA
-1.05V    -11.7mA    -10.5mA    -12.9mA
-750mV    -10.34mA   -9.14mA    -11.33mA
-450mV    -8.158mA   -7.135mA   -8.982mA
-150mV    -3.194mA   -2.892mA   -3.503mA
955mV     19.92mA    18.04mA    21.89mA
1.305V    26.79mA    24.2mA     29.47mA
1.655V    33.14mA    29.79mA    36.55mA
1.955V    37.87mA    33.75mA    41.97mA
2.25V     41.36mA    36.3mA     46.29mA
2.55V     43.3mA     37mA       49mA
[Pullup]
| Voltage   I(typ)   I(min)   I(max)
-1.35V    15mA       13mA       16mA
-1.05V    13.5mA     12.1mA     14.4mA
-750mV    11.83mA    10.52mA    12.65mA
-450mV    8.945mA    7.882mA    9.614mA
-150mV    3.253mA    2.912mA    3.497mA
805mV     -16.86mA   -15.3mA    -18.26mA
1.105V    -22.63mA   -20.38mA   -24.57mA
1.36V     -27.1mA    -24.2mA    -29.52mA
1.655V    -31.49mA   -27.76mA   -34.5mA
1.955V    -34.7mA    -30.17mA   -38.28mA
2.25V     -36.55mA   -31.6mA    -40.47mA
2.55V     -37.6mA    -33mA      -41.6mA
[Ramp]
dV/dt_r   0.4154/6.494e-11   0.3756/7.309e-11   0.4665/5.879e-11
dV/dt_f   0.4161/6.667e-11   0.3762/7.535e-11   0.4637/6.006e-11
R_load= 50
[Rising Waveform]
R_fixture = 50
V_fixture = 1.35
V_fixture_min = 1.283
V_fixture_max = 1.45
| Time   V(typ)   V(min)   V(max)
0s        657.6mV    656.4mV    672.6mV
292ps     657.6mV    656.4mV    666.2mV
339ps     658mV      656.4mV    1.134V
385ps     657mV      656.4mV    1.343V
430ps     1.02V      656.3mV    1.413V
477ps     1.231V     657.1mV    1.437V
540ps     1.319V     663.5mV    1.447V
608ps     1.343V     1.067V     1.449V
666ps     1.348V     1.213V     1.45V
920ps     1.35V      1.282V     1.45V
[Rising Waveform]
R_fixture = 50
V_fixture = 0
V_fixture_min = 0
V_fixture_max = 0
| Time   V(typ)   V(min)   V(max)
0s        221.5nV    7.772uV    46.37nV
292ps     9.336uV    7.794uV    -6.362mV
338ps     262.1uV    7.207uV    447.5mV
384ps     -2.857mV   20.76uV    661.3mV
430ps     364.1mV    -81.52uV   736.1mV
476ps     570mV      701uV      760.9mV
538ps     661.2mV    2.762mV    770.9mV
610ps     687.1mV    416mV      773.4mV
670ps     692.2mV    560.6mV    773.8mV
920ps     694.1mV    627.5mV    773.8mV
[Falling Waveform]
R_fixture = 50
V_fixture = 1.35
V_fixture_min = 1.283
V_fixture_max = 1.45
| Time   V(typ)   V(min)   V(max)
0s        1.35V      1.283V     1.45V
291ps     1.35V      1.283V     1.454V
341ps     1.35V      1.283V     966.7mV
386ps     1.353V     1.283V     777.6mV
425ps     1.03V      1.283V     714.1mV
474ps     790.5mV    1.282V     685.6mV
538ps     691.4mV    1.29V      674.7mV
604ps     665.5mV    909.2mV    672.2mV
660ps     659.6mV    744.2mV    671.7mV
920ps     657mV      656.5mV    671.6mV
[Falling Waveform]
R_fixture = 50
V_fixture = 0
V_fixture_min = 0
V_fixture_max = 0
| Time   V(typ)   V(min)   V(max)
0s        693.5mV    627.6mV    772.8mV
289ps     693.5mV    627.6mV    775.7mV
338ps     693.1mV    627.6mV    301.4mV
384ps     688.6mV    627.6mV    103.5mV
429ps     320.7mV    627.6mV    35.66mV
469ps     137.2mV    627.2mV    14.3mV
538ps     32.24mV    618.3mV    2.797mV
602ps     8.23mV     234.8mV    576.6uV
662ps     2.367mV    74.93mV    156.5uV
920ps     7.308uV    560.6uV    239.8nV
[Add Submodel]
| Submodel Name Mode
PAD_48_24_ddr3l_T Non-Driving
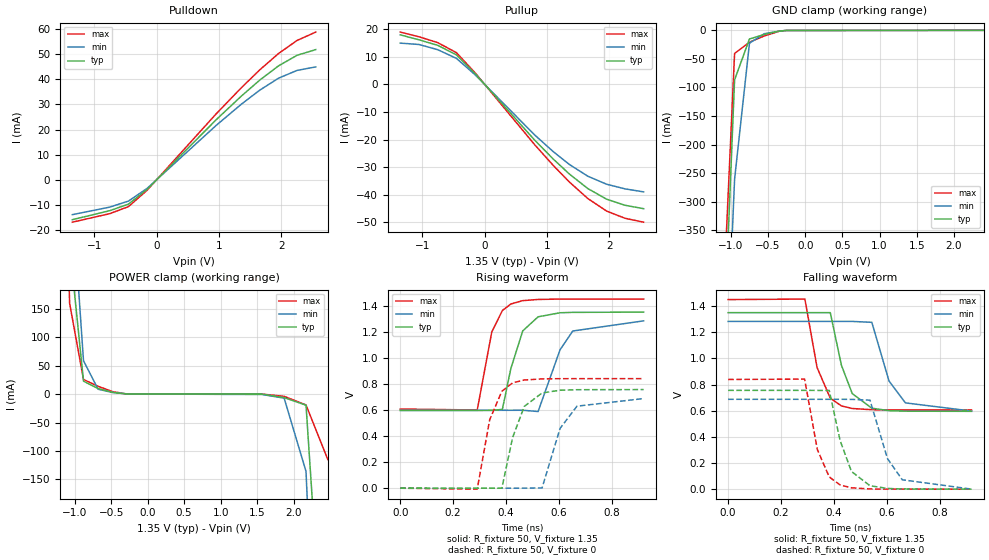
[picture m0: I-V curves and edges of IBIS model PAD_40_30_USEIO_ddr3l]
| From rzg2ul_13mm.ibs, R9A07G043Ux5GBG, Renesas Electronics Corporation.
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[Model] PAD_40_30_USEIO_ddr3l
Model_type I/O
Polarity   Non-Inverting
Vinl = 0.5400
Vinh = 0.8100
Vmeas= 0.675
| Capacitance   typ   min   max
C_comp   2.097e-12   2.007e-12   2.204e-12
[Model Spec]
| Subparameter   typ   min   max
Vmeas   0.675   0.641   0.725
Vinh   0.8100   0.7765   0.8600
Vinl   0.5400   0.5065   0.5900
| Variables   typ   min   max
[GND Clamp Reference]   0   0   0
[POWER Clamp Reference]   1.35   1.283   1.45
[Pulldown Reference]   0   0   0
[Pullup Reference]   1.35   1.283   1.45
[Temperature Range]   25   125   -40
[Voltage Range]   1.35   1.283   1.45
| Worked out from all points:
|   slope of the pulldown table from 0 to 0.203 V, typ, clamps not added: 39.2 ohm
|   slope of the pullup table from 0 to 0.203 V, typ, clamps not added: 38.7 ohm
|   GND clamp passes 1 mA (typ) near -0.32 V on its own axis
|   POWER clamp passes 1 mA (typ) near -0.34 V on its own axis
|   rising waveform, R_fixture 50, V_fixture 1.35: 20-80 % time 58.7ps typ, 66.7ps min, 52.9ps max; typ from 0.596 V to 1.35 V
|   rising waveform, R_fixture 50, V_fixture 0: 20-80 % time 60ps typ, 68.6ps min, 54ps max; typ from 0 V to 0.756 V
|   falling waveform, R_fixture 50, V_fixture 1.35: 20-80 % time 60.9ps typ, 69.6ps min, 54.8ps max; typ from 1.35 V to 0.595 V
|   falling waveform, R_fixture 50, V_fixture 0: 20-80 % time 60.8ps typ, 69.2ps min, 54.4ps max; typ from 0.756 V to 0 V
[GND Clamp]
| Voltage   I(typ)   I(min)   I(max)
-1.35V    -1.588A    -1.578A    -1.632A
-1.15V    -723.3mA   -875.4mA   -612.6mA
-950mV    -86.72mA   -260.7mA   -40.53mA
-750mV    -15.17mA   -22.59mA   -20.75mA
-550mV    -7.18mA    -5.89mA    -9.856mA
-350mV    -1.329mA   -1.495mA   -1.608mA
-260mV    -191.7uA   -416.3uA   -143.8uA
2.4V      0A         0A         0A
[POWER Clamp]
| Voltage   I(typ)   I(min)   I(max)
-1.35V    1.332A     1.303A     1.384A
-1.07V    261.9mA    413.7mA    159.6mA
-880mV    22.79mA    58.77mA    25.66mA
-680mV    9.824mA    8.594mA    13.78mA
-480mV    3.118mA    2.85mA     4.348mA
-280mV    118.8uA    285.7uA    106.4uA
1.57V     -51.57uA   -692.4uA   -197.8nA
1.87V     -6.117mA   -7.08mA    -3.933mA
2.17V     -19.54mA   -136.1mA   -19.04mA
2.47V     -601.3mA   -1.013A    -115.5mA
[Pulldown]
| Voltage   I(typ)   I(min)   I(max)
-1.35V    -16mA      -14mA      -17mA
-750mV    -12.4mA    -10.97mA   -13.59mA
-450mV    -9.788mA   -8.565mA   -10.77mA
-150mV    -3.833mA   -3.471mA   -4.203mA
955mV     23.91mA    21.65mA    26.27mA
1.36V     33.39mA    30.15mA    36.74mA
1.655V    39.77mA    35.75mA    43.86mA
1.955V    45.44mA    40.51mA    50.36mA
2.25V     49.63mA    43.6mA     55.55mA
2.55V     51.9mA     45mA       58.9mA
[Pullup]
| Voltage   I(typ)   I(min)   I(max)
-1.35V    18mA       15mA       19mA
-1.05V    16.2mA     14.5mA     17.3mA
-750mV    14.19mA    12.62mA    15.18mA
-450mV    10.73mA    9.462mA    11.53mA
-150mV    3.904mA    3.494mA    4.197mA
805mV     -20.24mA   -18.36mA   -21.91mA
1.105V    -27.16mA   -24.46mA   -29.48mA
1.36V     -32.52mA   -29.05mA   -35.42mA
1.655V    -37.79mA   -33.31mA   -41.4mA
1.955V    -41.63mA   -36.21mA   -45.94mA
2.25V     -43.85mA   -37.9mA    -48.57mA
2.55V     -45.1mA    -39mA      -50mA
[Ramp]
dV/dt_r   0.4524/5.869e-11   0.4112/6.668e-11   0.5059/5.286e-11
dV/dt_f   0.4534/6.076e-11   0.4122/6.916e-11   0.5034/5.443e-11
R_load= 50
[Rising Waveform]
R_fixture = 50
V_fixture = 1.35
V_fixture_min = 1.283
V_fixture_max = 1.45
| Time   V(typ)   V(min)   V(max)
0s        595.9mV    597.4mV    606.9mV
291ps     595.9mV    597.4mV    599.6mV
346ps     596.9mV    597.4mV    1.198V
386ps     604.1mV    597.5mV    1.362V
418ps     917.3mV    597.4mV    1.412V
463ps     1.206V     597.7mV    1.438V
521ps     1.314V     587.8mV    1.447V
604ps     1.345V     1.061V     1.45V
652ps     1.348V     1.205V     1.45V
920ps     1.35V      1.283V     1.45V
[Rising Waveform]
R_fixture = 50
V_fixture = 0
V_fixture_min = 0
V_fixture_max = 0
| Time   V(typ)   V(min)   V(max)
0s        200.8nV    7.075uV    41.87nV
291ps     13.26uV    7.111uV    -7.272mV
338ps     381.9uV    6.426uV    524.5mV
384ps     64.24uV    23.03uV    743.5mV
425ps     390.6mV    -84.65uV   807.9mV
469ps     627.8mV    537.1uV    829.7mV
536ps     730mV      2.025mV    838.1mV
604ps     751.1mV    458.6mV    839.7mV
668ps     755.1mV    628.9mV    839.9mV
920ps     756.2mV    687.3mV    839.9mV
[Falling Waveform]
R_fixture = 50
V_fixture = 1.35
V_fixture_min = 1.283
V_fixture_max = 1.45
| Time   V(typ)   V(min)   V(max)
0s        1.35V      1.283V     1.45V
290ps     1.35V      1.283V     1.454V
336ps     1.35V      1.283V     930.7mV
386ps     1.35V      1.283V     696.1mV
428ps     948.1mV    1.283V     636.9mV
469ps     730.8mV    1.283V     617mV
543ps     619.4mV    1.276V     607.6mV
608ps     600.5mV    827.1mV    606.3mV
670ps     596.5mV    659.9mV    606.1mV
920ps     595.4mV    597.4mV    606.1mV
[Falling Waveform]
R_fixture = 50
V_fixture = 0
V_fixture_min = 0
V_fixture_max = 0
| Time   V(typ)   V(min)   V(max)
0s        755.6mV    687.2mV    839.1mV
289ps     755.6mV    687.2mV    841.7mV
337ps     755.3mV    687.2mV    303.1mV
382ps     755mV      687.2mV    93.81mV
423ps     373mV      687.3mV    32.03mV
466ps     135.3mV    686.8mV    10.49mV
536ps     26.23mV    680.7mV    1.685mV
602ps     5.578mV    234.2mV    270.9uV
658ps     1.566mV    71.8mV     70.54uV
920ps     2.209uV    284.6uV    75.2nV
[Add Submodel]
| Submodel Name Mode
PAD_40_30_ddr3l_T Non-Driving
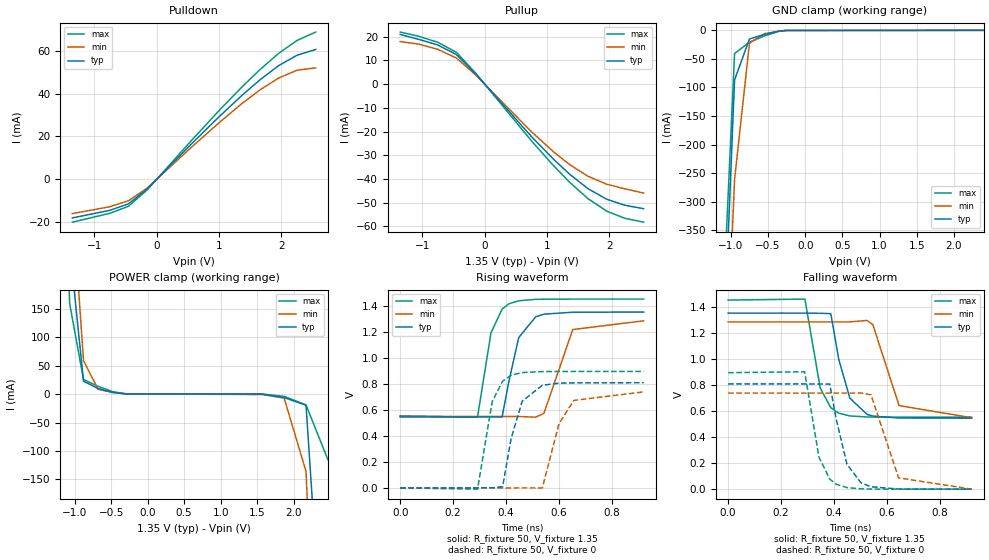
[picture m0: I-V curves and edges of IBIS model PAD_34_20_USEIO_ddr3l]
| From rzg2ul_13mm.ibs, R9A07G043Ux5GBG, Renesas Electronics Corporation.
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[Model] PAD_34_20_USEIO_ddr3l
Model_type I/O
Polarity   Non-Inverting
Vinl = 0.5400
Vinh = 0.8100
Vmeas= 0.675
| Capacitance   typ   min   max
C_comp   2.097e-12   2.007e-12   2.204e-12
[Model Spec]
| Subparameter   typ   min   max
Vmeas   0.675   0.641   0.725
Vinh   0.8100   0.7765   0.8600
Vinl   0.5400   0.5065   0.5900
| Variables   typ   min   max
[GND Clamp Reference]   0   0   0
[POWER Clamp Reference]   1.35   1.283   1.45
[Pulldown Reference]   0   0   0
[Pullup Reference]   1.35   1.283   1.45
[Temperature Range]   25   125   -40
[Voltage Range]   1.35   1.283   1.45
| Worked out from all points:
|   slope of the pulldown table from 0 to 0.203 V, typ, clamps not added: 33.6 ohm
|   slope of the pullup table from 0 to 0.203 V, typ, clamps not added: 33.2 ohm
|   GND clamp passes 1 mA (typ) near -0.32 V on its own axis
|   POWER clamp passes 1 mA (typ) near -0.34 V on its own axis
|   rising waveform, R_fixture 50, V_fixture 1.35: 20-80 % time 53.1ps typ, 60.6ps min, 48ps max; typ from 0.545 V to 1.35 V
|   rising waveform, R_fixture 50, V_fixture 0: 20-80 % time 54.5ps typ, 62.4ps min, 48.8ps max; typ from 0 V to 0.808 V
|   falling waveform, R_fixture 50, V_fixture 1.35: 20-80 % time 55.5ps typ, 63.8ps min, 49.8ps max; typ from 1.35 V to 0.544 V
|   falling waveform, R_fixture 50, V_fixture 0: 20-80 % time 55.5ps typ, 63.4ps min, 49.8ps max; typ from 0.807 V to 0 V
[GND Clamp]
| Voltage   I(typ)   I(min)   I(max)
-1.35V    -1.588A    -1.578A    -1.632A
-1.15V    -723.3mA   -875.4mA   -612.6mA
-950mV    -86.72mA   -260.7mA   -40.53mA
-750mV    -15.17mA   -22.59mA   -20.75mA
-550mV    -7.18mA    -5.89mA    -9.856mA
-350mV    -1.329mA   -1.495mA   -1.608mA
-260mV    -191.7uA   -416.3uA   -143.8uA
2.4V      0A         0A         0A
[POWER Clamp]
| Voltage   I(typ)   I(min)   I(max)
-1.35V    1.332A     1.303A     1.384A
-1.07V    261.9mA    413.7mA    159.6mA
-880mV    22.79mA    58.77mA    25.66mA
-680mV    9.824mA    8.594mA    13.78mA
-480mV    3.118mA    2.85mA     4.348mA
-280mV    118.8uA    285.7uA    106.4uA
1.57V     -51.57uA   -692.4uA   -197.8nA
1.87V     -6.117mA   -7.08mA    -3.933mA
2.17V     -19.54mA   -136.1mA   -19.04mA
2.47V     -601.3mA   -1.013A    -115.5mA
[Pulldown]
| Voltage   I(typ)   I(min)   I(max)
-1.35V    -18mA      -16mA      -20mA
-750mV    -14.47mA   -12.8mA    -15.86mA
-450mV    -11.42mA   -9.995mA   -12.57mA
-150mV    -4.472mA   -4.049mA   -4.904mA
550mV     16.26mA    14.74mA    17.85mA
1.005V    29.3mA     26.52mA    32.2mA
1.36V     38.96mA    35.17mA    42.86mA
1.655V    46.4mA     41.71mA    51.17mA
1.955V    53.02mA    47.26mA    58.76mA
2.25V     57.9mA     50.9mA     64.81mA
2.55V     60.6mA     52mA       68.7mA
[Pullup]
| Voltage   I(typ)   I(min)   I(max)
-1.35V    21mA       18mA       22mA
-1.05V    18.9mA     16.9mA     20.2mA
-750mV    16.56mA    14.73mA    17.71mA
-450mV    12.52mA    11.04mA    13.45mA
-150mV    4.555mA    4.077mA    4.896mA
755mV     -22.21mA   -20.18mA   -24.03mA
1.105V    -31.68mA   -28.54mA   -34.4mA
1.36V     -37.94mA   -33.89mA   -41.33mA
1.655V    -44.09mA   -38.86mA   -48.3mA
1.955V    -48.57mA   -42.24mA   -53.6mA
2.25V     -51.16mA   -44.2mA    -56.66mA
2.55V     -52.6mA    -46mA      -58.3mA
[Ramp]
dV/dt_r   0.4831/5.315e-11   0.4408/6.056e-11   0.5383/4.795e-11
dV/dt_f   0.4843/5.545e-11   0.4421/6.344e-11   0.5361/4.977e-11
R_load= 50
[Rising Waveform]
R_fixture = 50
V_fixture = 1.35
V_fixture_min = 1.283
V_fixture_max = 1.45
| Time   V(typ)   V(min)   V(max)
0s        544.8mV    548.2mV    552.9mV
292ps     544.8mV    548.2mV    543.4mV
343ps     545.6mV    548.2mV    1.191V
385ps     544.4mV    548.2mV    1.373V
411ps     822.6mV    548.1mV    1.414V
448ps     1.155V     548.1mV    1.437V
512ps     1.314V     543.2mV    1.448V
543ps     1.334V     572.3mV    1.449V
652ps     1.349V     1.216V     1.45V
920ps     1.35V      1.283V     1.45V
[Rising Waveform]
R_fixture = 50
V_fixture = 0
V_fixture_min = 0
V_fixture_max = 0
| Time   V(typ)   V(min)   V(max)
0s        183.6nV    6.494uV    38.15nV
292ps     10.17uV    6.492uV    -9.622mV
348ps     1.399mV    6.167uV    665.8mV
387ps     9.046mV    22.81uV    819.9mV
419ps     378.8mV    -61.27uV   865.3mV
461ps     666.1mV    179.5uV    885.6mV
537ps     788.2mV    16.76uV    893.4mV
600ps     804mV      492.6mV    894.1mV
656ps     806.7mV    672mV      894.2mV
920ps     807.6mV    737.2mV    894.2mV
[Falling Waveform]
R_fixture = 50
V_fixture = 1.35
V_fixture_min = 1.283
V_fixture_max = 1.45
| Time   V(typ)   V(min)   V(max)
0s        1.35V      1.283V     1.45V
290ps     1.35V      1.283V     1.458V
348ps     1.349V     1.283V     775.7mV
388ps     1.346V     1.283V     624.6mV
418ps     995.2mV    1.283V     583.1mV
460ps     698.1mV    1.283V     561.8mV
525ps     573mV      1.294V     553.7mV
547ps     560.9mV    1.261V     553mV
646ps     545.7mV    640.8mV    552.2mV
920ps     544.4mV    548mV      552.2mV
[Falling Waveform]
R_fixture = 50
V_fixture = 0
V_fixture_min = 0
V_fixture_max = 0
| Time   V(typ)   V(min)   V(max)
0s        807.1mV    737mV      893.5mV
289ps     807.1mV    737mV      900.2mV
343ps     806.5mV    737mV      246.7mV
384ps     805.8mV    737mV      76.91mV
409ps     531.6mV    737mV      37.04mV
449ps     191.1mV    736.9mV    11.89mV
502ps     48.57mV    737.4mV    2.629mV
540ps     18.3mV     723.1mV    809.1uV
644ps     1.28mV     86.77mV    42.35uV
920ps     713.1nV    146.7uV    43.82nV
[Add Submodel]
| Submodel Name Mode
PAD_34_20_ddr3l_T Non-Driving
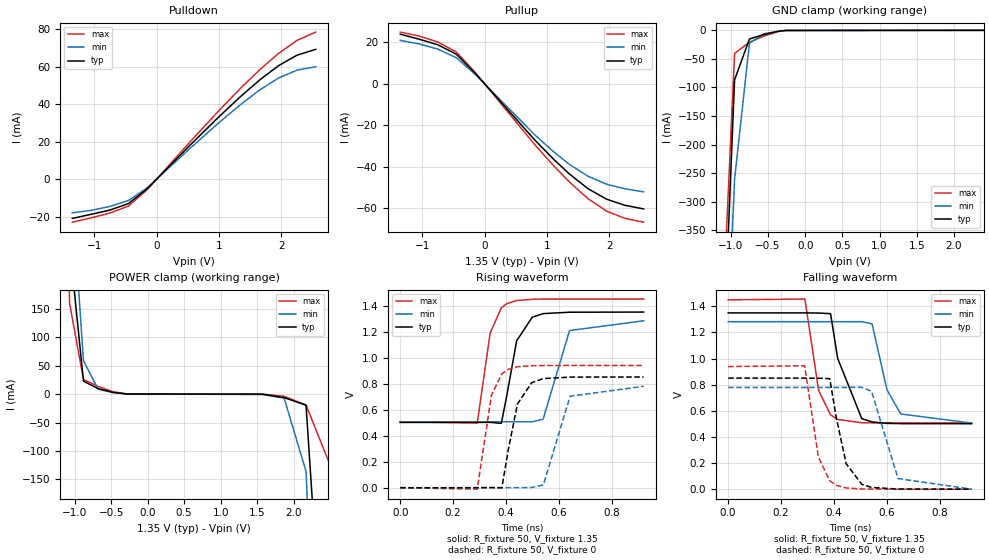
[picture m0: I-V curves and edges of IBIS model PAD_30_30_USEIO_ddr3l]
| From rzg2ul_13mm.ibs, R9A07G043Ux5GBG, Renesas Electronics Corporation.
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[Model] PAD_30_30_USEIO_ddr3l
Model_type I/O
Polarity   Non-Inverting
Vinl = 0.5400
Vinh = 0.8100
Vmeas= 0.675
| Capacitance   typ   min   max
C_comp   2.097e-12   2.007e-12   2.204e-12
[Model Spec]
| Subparameter   typ   min   max
Vmeas   0.675   0.641   0.725
Vinh   0.8100   0.7765   0.8600
Vinl   0.5400   0.5065   0.5900
| Variables   typ   min   max
[GND Clamp Reference]   0   0   0
[POWER Clamp Reference]   1.35   1.283   1.45
[Pulldown Reference]   0   0   0
[Pullup Reference]   1.35   1.283   1.45
[Temperature Range]   25   125   -40
[Voltage Range]   1.35   1.283   1.45
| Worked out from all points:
|   slope of the pulldown table from 0 to 0.203 V, typ, clamps not added: 29.4 ohm
|   slope of the pullup table from 0 to 0.203 V, typ, clamps not added: 29.1 ohm
|   GND clamp passes 1 mA (typ) near -0.32 V on its own axis
|   POWER clamp passes 1 mA (typ) near -0.34 V on its own axis
|   rising waveform, R_fixture 50, V_fixture 1.35: 20-80 % time 49ps typ, 56.1ps min, 43.9ps max; typ from 0.502 V to 1.35 V
|   rising waveform, R_fixture 50, V_fixture 0: 20-80 % time 49.8ps typ, 57.5ps min, 44.6ps max; typ from 0 V to 0.851 V
|   falling waveform, R_fixture 50, V_fixture 1.35: 20-80 % time 51.3ps typ, 59.4ps min, 46ps max; typ from 1.35 V to 0.501 V
|   falling waveform, R_fixture 50, V_fixture 0: 20-80 % time 51.4ps typ, 59.5ps min, 46ps max; typ from 0.85 V to 0 V
[GND Clamp]
| Voltage   I(typ)   I(min)   I(max)
-1.35V    -1.588A    -1.578A    -1.632A
-1.15V    -723.3mA   -875.4mA   -612.6mA
-950mV    -86.72mA   -260.7mA   -40.53mA
-750mV    -15.17mA   -22.59mA   -20.75mA
-550mV    -7.18mA    -5.89mA    -9.856mA
-350mV    -1.329mA   -1.495mA   -1.608mA
-260mV    -191.7uA   -416.3uA   -143.8uA
2.4V      0A         0A         0A
[POWER Clamp]
| Voltage   I(typ)   I(min)   I(max)
-1.35V    1.332A     1.303A     1.384A
-1.07V    261.9mA    413.7mA    159.6mA
-880mV    22.79mA    58.77mA    25.66mA
-680mV    9.824mA    8.594mA    13.78mA
-480mV    3.118mA    2.85mA     4.348mA
-280mV    118.8uA    285.7uA    106.4uA
1.57V     -51.57uA   -692.4uA   -197.8nA
1.87V     -6.117mA   -7.08mA    -3.933mA
2.17V     -19.54mA   -136.1mA   -19.04mA
2.47V     -601.3mA   -1.013A    -115.5mA
[Pulldown]
| Voltage   I(typ)   I(min)   I(max)
-1.35V    -21mA      -18mA      -23mA
-1.05V    -18.8mA    -16.7mA    -20.7mA
-750mV    -16.54mA   -14.63mA   -18.13mA
-450mV    -13.05mA   -11.41mA   -14.36mA
-150mV    -5.11mA    -4.628mA   -5.604mA
550mV     18.58mA    16.85mA    20.4mA
1.005V    33.48mA    30.31mA    36.79mA
1.36V     44.53mA    40.2mA     48.99mA
1.655V    53.03mA    47.67mA    58.48mA
1.955V    60.59mA    54.01mA    67.15mA
2.25V     66.17mA    58.2mA     74.07mA
2.55V     69.3mA     60mA       78.5mA
[Pullup]
| Voltage   I(typ)   I(min)   I(max)
-1.35V    24mA       21mA       25mA
-1.05V    21.6mA     19.3mA     23.1mA
-750mV    18.92mA    16.83mA    20.24mA
-450mV    14.31mA    12.62mA    15.37mA
-150mV    5.205mA    4.659mA    5.596mA
805mV     -26.98mA   -24.48mA   -29.21mA
1.105V    -36.21mA   -32.61mA   -39.31mA
1.36V     -43.36mA   -38.73mA   -47.23mA
1.655V    -50.39mA   -44.41mA   -55.2mA
1.955V    -55.51mA   -48.28mA   -61.25mA
2.25V     -58.47mA   -50.5mA    -64.76mA
2.55V     -60.2mA    -52mA      -66.6mA
[Ramp]
dV/dt_r   0.5090/4.899e-11   0.4659/5.608e-11   0.5654/4.393e-11
dV/dt_f   0.5103/5.137e-11   0.4674/5.950e-11   0.5635/4.596e-11
R_load= 50
[Rising Waveform]
R_fixture = 50
V_fixture = 1.35
V_fixture_min = 1.283
V_fixture_max = 1.45
| Time   V(typ)   V(min)   V(max)
0s        501.7mV    506.4mV    507.7mV
291ps     501.7mV    506.4mV    497mV
340ps     502.4mV    506.4mV    1.19V
382ps     494.4mV    506.4mV    1.382V
402ps     699.8mV    506.4mV    1.414V
440ps     1.129V     506.2mV    1.439V
499ps     1.311V     506.8mV    1.448V
540ps     1.338V     526.9mV    1.45V
640ps     1.349V     1.208V     1.45V
920ps     1.35V      1.283V     1.45V
[Rising Waveform]
R_fixture = 50
V_fixture = 0
V_fixture_min = 0
V_fixture_max = 0
| Time   V(typ)   V(min)   V(max)
0s        169.2nV    6.001uV    34.92nV
291ps     14.6uV     6.016uV    -11.26mV
345ps     1.299mV    5.41uV     712.9mV
384ps     -999.9uV   25uV       874.4mV
408ps     287.5mV    -17.05uV   909.6mV
443ps     643.4mV    -155.3uV   929.7mV
497ps     807.5mV    1.658mV    937.9mV
541ps     838.7mV    21.77mV    939.2mV
642ps     850.2mV    703.2mV    939.7mV
920ps     850.8mV    779.3mV    939.7mV
[Falling Waveform]
R_fixture = 50
V_fixture = 1.35
V_fixture_min = 1.283
V_fixture_max = 1.45
| Time   V(typ)   V(min)   V(max)
0s        1.35V      1.283V     1.45V
290ps     1.35V      1.283V     1.456V
342ps     1.349V     1.283V     755.1mV
387ps     1.344V     1.283V     568.7mV
414ps     1.001V     1.283V     534mV
505ps     540.6mV    1.283V     508.8mV
544ps     514.7mV    1.266V     507.6mV
600ps     504mV      762.1mV    507.2mV
652ps     502mV      576mV      507.1mV
920ps     501.4mV    506.2mV    507.2mV
[Falling Waveform]
R_fixture = 50
V_fixture = 0
V_fixture_min = 0
V_fixture_max = 0
| Time   V(typ)   V(min)   V(max)
0s        850.5mV    779.1mV    939.1mV
289ps     850.4mV    779.1mV    944.8mV
341ps     849.8mV    779.1mV    246.8mV
384ps     846.3mV    779.1mV    63.83mV
409ps     544.9mV    779.2mV    29.17mV
446ps     195.1mV    779.1mV    9.335mV
505ps     37.04mV    780.4mV    1.487mV
542ps     13.38mV    749.8mV    494.5uV
642ps     808.7uV    81.45mV    15.35uV
920ps     308.8nV    75.93uV    36.71nV
[Add Submodel]
| Submodel Name Mode
PAD_30_30_ddr3l_T Non-Driving
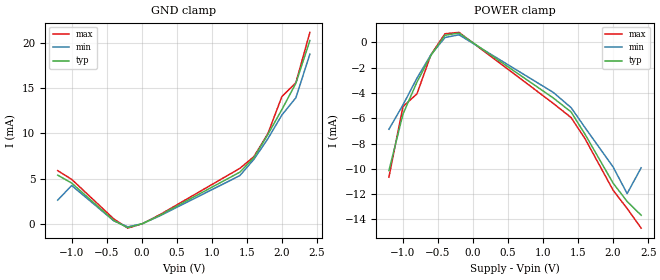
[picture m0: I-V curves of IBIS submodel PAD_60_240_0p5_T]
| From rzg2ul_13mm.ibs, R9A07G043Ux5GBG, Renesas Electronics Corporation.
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[Submodel]  PAD_60_240_0p5_T
Submodel_type Dynamic_clamp
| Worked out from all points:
|   GND clamp passes 1 mA (typ) near -0.49 V on its own axis
[GND Clamp]
| Voltage   I(typ)   I(min)   I(max)
-1.2V     5.395mA    2.632mA    5.893mA
-1V       4.517mA    4.247mA    4.926mA
-400mV    378.3uA    348.8uA    561uA
-200mV    -414.7uA   -328.6uA   -465.6uA
10mV      31.72uA    27.51uA    33.99uA
260mV     967uA      898.6uA    1.027mA
1.4V      5.722mA    5.342mA    6.143mA
1.6V      7.319mA    7.13mA     7.427mA
1.8V      9.895mA    9.417mA    9.98mA
2V        12.64mA    12.04mA    14.08mA
2.2V      15.56mA    13.95mA    15.61mA
2.4V      20.28mA    18.78mA    21.18mA
[POWER Clamp]
| Voltage   I(typ)   I(min)   I(max)
-1.2V     -10.14mA   -6.866mA   -10.66mA
-1V       -5.672mA   -4.946mA   -5.079mA
-800mV    -3.134mA   -2.825mA   -4.063mA
-600mV    -1.018mA   -967.9uA   -969.5uA
-400mV    570.3uA    388.8uA    688.6uA
-200mV    742.5uA    606uA      797.8uA
1.145V    -4.39mA    -3.949mA   -4.817mA
1.4V      -5.497mA   -5.153mA   -5.941mA
1.6V      -7.273mA   -6.745mA   -7.624mA
2V        -11.13mA   -9.849mA   -11.69mA
2.2V      -12.58mA   -11.96mA   -13.14mA
2.4V      -13.67mA   -9.916mA   -14.69mA
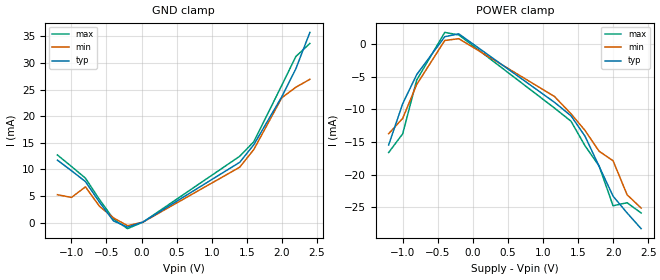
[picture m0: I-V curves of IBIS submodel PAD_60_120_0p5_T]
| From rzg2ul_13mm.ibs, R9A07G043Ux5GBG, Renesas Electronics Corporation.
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[Submodel]  PAD_60_120_0p5_T
Submodel_type Dynamic_clamp
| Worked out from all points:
|   GND clamp passes 1 mA (typ) near -0.44 V on its own axis
|   POWER clamp passes 1 mA (typ) near -0.13 V on its own axis
[GND Clamp]
| Voltage   I(typ)   I(min)   I(max)
-1.2V     11.75mA    5.263mA    12.72mA
-1V       9.767mA    4.746mA    10.57mA
-800mV    7.727mA    6.73mA     8.362mA
-600mV    3.84mA     3.084mA    4.352mA
-400mV    330uA      912.3uA    701.6uA
-200mV    -830uA     -563.2uA   -1.116mA
20mV      126.9uA    114uA      112.4uA
1.4V      11.35mA    10.43mA    12.48mA
1.6V      14.64mA    13.74mA    15.2mA
2V        23.67mA    23.47mA    25.81mA
2.2V      28.91mA    25.44mA    31.22mA
2.4V      35.74mA    26.93mA    33.66mA
[POWER Clamp]
| Voltage   I(typ)   I(min)   I(max)
-1.2V     -15.47mA   -13.74mA   -16.62mA
-1V       -9.142mA   -11.39mA   -13.75mA
-800mV    -4.667mA   -6.196mA   -5.505mA
-400mV    1.14mA     561.4uA    1.8mA
-200mV    1.578mA    835.1uA    1.41mA
1.165V    -8.924mA   -8.035mA   -9.806mA
1.4V      -10.99mA   -10.68mA   -11.82mA
1.6V      -14.12mA   -13.24mA   -15.59mA
1.8V      -18.72mA   -16.42mA   -18.67mA
2V        -23.32mA   -17.89mA   -24.79mA
2.2V      -25.89mA   -23.1mA    -24.32mA
2.4V      -28.3mA    -25.14mA   -25.9mA
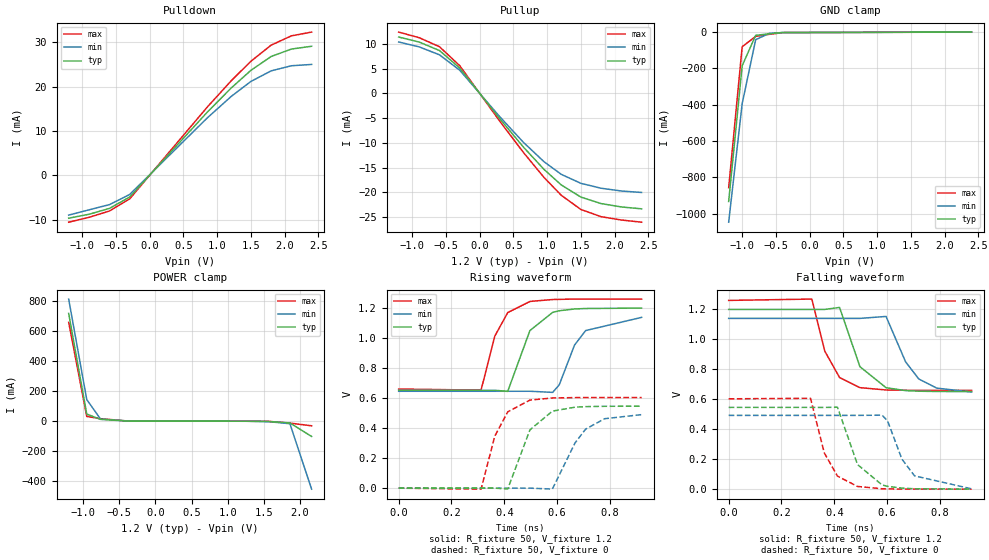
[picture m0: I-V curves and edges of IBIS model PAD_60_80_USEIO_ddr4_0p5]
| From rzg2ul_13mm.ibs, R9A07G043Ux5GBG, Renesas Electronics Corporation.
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[Model] PAD_60_80_USEIO_ddr4_0p5
Model_type I/O
Polarity   Non-Inverting
Vinl = 0.5070
Vinh = 0.6930
Vmeas= 0.600
| Capacitance   typ   min   max
C_comp   2.102e-12   2.013e-12   2.214e-12
[Model Spec]
| Subparameter   typ   min   max
Vmeas   0.600   0.570   0.630
Vinh   0.6930   0.6630   0.7230
Vinl   0.5070   0.4770   0.5370
| Variables   typ   min   max
[GND Clamp Reference]   0   0   0
[POWER Clamp Reference]   1.2   1.14   1.26
[Pulldown Reference]   0   0   0
[Pullup Reference]   1.2   1.14   1.26
[Temperature Range]   25   125   -40
[Voltage Range]   1.2   1.14   1.26
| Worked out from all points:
|   slope of the pulldown table from 0 to 0.18 V, typ, clamps not added: 58.8 ohm
|   slope of the pullup table from 0 to 0.18 V, typ, clamps not added: 58 ohm
|   GND clamp passes 1 mA (typ) near -0.30 V on its own axis
|   POWER clamp passes 1 mA (typ) near -0.38 V on its own axis
|   rising waveform, R_fixture 50, V_fixture 1.2: 20-80 % time 73ps typ, 80.7ps min, 66.5ps max; typ from 0.652 V to 1.2 V
|   rising waveform, R_fixture 50, V_fixture 0: 20-80 % time 77.5ps typ, 87.3ps min, 69.9ps max; typ from 0 V to 0.546 V
|   falling waveform, R_fixture 50, V_fixture 1.2: 20-80 % time 75.5ps typ, 84.8ps min, 69.6ps max; typ from 1.2 V to 0.651 V
|   falling waveform, R_fixture 50, V_fixture 0: 20-80 % time 74.1ps typ, 82.6ps min, 67.9ps max; typ from 0.546 V to 0 V
[GND Clamp]
| Voltage   I(typ)   I(min)   I(max)
-1.2V     -932.7mA   -1.047A    -857.4mA
-1V       -185.5mA   -394.3mA   -80.64mA
-800mV    -17.89mA   -41.9mA    -23.65mA
-600mV    -9.04mA    -7.411mA   -12.44mA
-400mV    -2.454mA   -2.378mA   -3.185mA
2.4V      0A         0A         0A
[POWER Clamp]
| Voltage   I(typ)   I(min)   I(max)
-1.2V     719.7mA    815.2mA    660.1mA
-950mV    48.1mA     144.6mA    32.07mA
-760mV    12.41mA    14.91mA    17.11mA
-360mV    527.4uA    791.2uA    575.5uA
1.26V     -115.5nA   -12.89uA   -796.6pA
1.56V     -1.53mA    -2.776mA   -549.4uA
1.86V     -11.39mA   -16.33mA   -12.44mA
2.16V     -101.5mA   -453.2mA   -30.39mA
[Pulldown]
| Voltage   I(typ)   I(min)   I(max)
-1.2V     -9.7mA     -9mA       -10.6mA
-895mV    -8.8mA     -7.8mA     -9.49mA
-595mV    -7.491mA   -6.628mA   -8.07mA
-295mV    -4.902mA   -4.336mA   -5.322mA
855mV     14.25mA    12.95mA    15.4mA
1.21V     19.7mA     17.8mA     21.34mA
1.5V      23.66mA    21.16mA    25.71mA
1.8V      26.79mA    23.55mA    29.35mA
2.1V      28.47mA    24.7mA     31.45mA
2.4V      29.1mA     25mA       32.3mA
[Pullup]
| Voltage   I(typ)   I(min)   I(max)
-1.2V     11.4mA     10.4mA     12.4mA
-895mV    10.38mA    9.41mA     11.26mA
-595mV    8.671mA    7.804mA    9.444mA
-295mV    5.138mA    4.696mA    5.61mA
300mV     -5.138mA   -4.726mA   -5.631mA
650mV     -10.85mA   -9.889mA   -11.94mA
955mV     -15.35mA   -13.8mA    -16.98mA
1.21V     -18.48mA   -16.34mA   -20.57mA
1.5V      -20.93mA   -18.15mA   -23.43mA
1.8V      -22.24mA   -19.14mA   -24.89mA
2.1V      -22.92mA   -19.7mA    -25.56mA
2.4V      -23.3mA    -20mA      -26mA
[Ramp]
dV/dt_r   0.3288/7.302e-11   0.2952/8.066e-11   0.3597/6.654e-11
dV/dt_f   0.3274/7.410e-11   0.2943/8.259e-11   0.3619/6.787e-11
R_load= 50
[Rising Waveform]
R_fixture = 50
V_fixture = 1.2
V_fixture_min = 1.14
V_fixture_max = 1.26
| Time   V(typ)   V(min)   V(max)
0s        651.9mV    645.6mV    660.5mV
312ps     651.9mV    645.6mV    653.2mV
364ps     652.2mV    645.6mV    1.013V
413ps     645mV      645.6mV    1.17V
497ps     1.05V      645.7mV    1.244V
583ps     1.171V     638.2mV    1.257V
608ps     1.182V     688.1mV    1.258V
666ps     1.194V     953.4mV    1.26V
708ps     1.197V     1.05V      1.26V
920ps     1.2V       1.138V     1.26V
[Rising Waveform]
R_fixture = 50
V_fixture = 0
V_fixture_min = 0
V_fixture_max = 0
| Time   V(typ)   V(min)   V(max)
0s        118.2nV    4.925uV    20.55nV
312ps     -1.593uV   4.822uV    -6.708mV
364ps     263.6uV    4.746uV    346.7mV
413ps     -5.676mV   12.71uV    508.5mV
497ps     388.6mV    41.46uV    586.8mV
582ps     513.2mV    -6.19mV    600.9mV
668ps     539.6mV    301.7mV    603.4mV
708ps     543.2mV    393.5mV    603.7mV
780ps     545.5mV    462.7mV    603.9mV
920ps     546.2mV    490mV      603.9mV
[Falling Waveform]
R_fixture = 50
V_fixture = 1.2
V_fixture_min = 1.14
V_fixture_max = 1.26
| Time   V(typ)   V(min)   V(max)
0s        1.2V       1.14V      1.26V
315ps     1.2V       1.14V      1.269V
364ps     1.2V       1.14V      921.3mV
420ps     1.213V     1.14V      745.3mV
497ps     817.9mV    1.14V      677.7mV
596ps     677.3mV    1.153V     662.1mV
670ps     657.9mV    850mV      660.2mV
720ps     653.9mV    735.5mV    659.8mV
788ps     652.1mV    674.5mV    659.7mV
920ps     651.4mV    648.6mV    659.7mV
[Falling Waveform]
R_fixture = 50
V_fixture = 0
V_fixture_min = 0
V_fixture_max = 0
| Time   V(typ)   V(min)   V(max)
0s        545.8mV    492.6mV    603.1mV
310ps     545.8mV    492.6mV    606.4mV
362ps     545.6mV    492.6mV    242.5mV
412ps     547.1mV    492.6mV    87.29mV
488ps     164.2mV    492.5mV    18.1mV
581ps     28.17mV    494mV      2.687mV
602ps     18.98mV    454.9mV    1.67mV
656ps     6.96mV     200.7mV    592.7uV
704ps     2.712mV    88.68mV    189.6uV
920ps     37.71uV    2.199mV    1.697uV
[Add Submodel]
| Submodel Name Mode
PAD_60_80_0p5_T Non-Driving
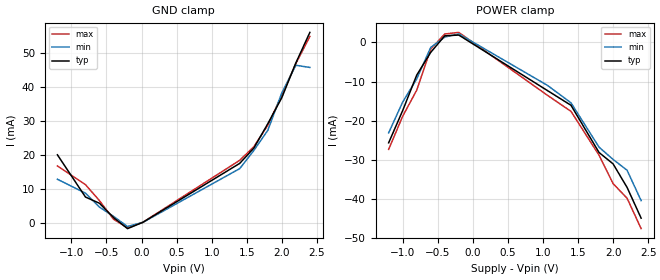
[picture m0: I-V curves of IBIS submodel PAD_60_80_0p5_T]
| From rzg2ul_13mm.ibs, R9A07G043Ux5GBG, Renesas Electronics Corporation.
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[Submodel]  PAD_60_80_0p5_T
Submodel_type Dynamic_clamp
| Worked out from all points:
|   POWER clamp passes 1 mA (typ) near -0.11 V on its own axis
[GND Clamp]
| Voltage   I(typ)   I(min)   I(max)
-1.2V     20.02mA    12.82mA    16.74mA
-800mV    7.593mA    8.737mA    11.24mA
-600mV    5.76mA     4.626mA    6.529mA
-400mV    1.56mA     1.909mA    1.051mA
-200mV    -1.71mA    -1.079mA   -1.443mA
20mV      170.7uA    153.3uA    188.3uA
1.4V      17.5mA     15.96mA    18.4mA
1.6V      21.96mA    21.26mA    22.37mA
1.8V      29.15mA    27.21mA    28.7mA
2V        36.83mA    38.25mA    37.52mA
2.2V      47.04mA    46.35mA    46.83mA
2.4V      56.02mA    45.71mA    54.84mA
[POWER Clamp]
| Voltage   I(typ)   I(min)   I(max)
-1.2V     -25.61mA   -23.06mA   -27.28mA
-1V       -17.38mA   -15.21mA   -18.83mA
-800mV    -8.333mA   -9.291mA   -12.18mA
-600mV    -2.515mA   -1.253mA   -1.667mA
-400mV    1.71mA     1.382mA    2.171mA
-200mV    1.9mA      2.195mA    2.579mA
1.065V    -12.28mA   -10.95mA   -13.49mA
1.4V      -16.03mA   -15.4mA    -17.58mA
1.8V      -28.08mA   -26.72mA   -28.77mA
2V        -30.98mA   -29.84mA   -36.02mA
2.2V      -37mA      -32.61mA   -39.76mA
2.4V      -44.84mA   -40.36mA   -47.52mA
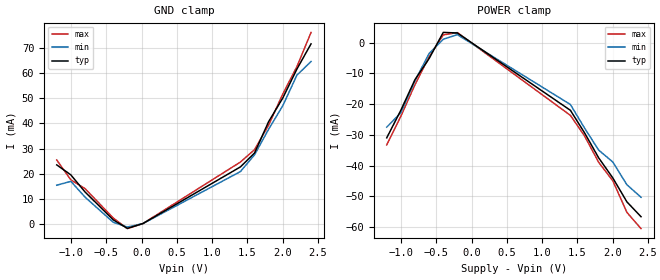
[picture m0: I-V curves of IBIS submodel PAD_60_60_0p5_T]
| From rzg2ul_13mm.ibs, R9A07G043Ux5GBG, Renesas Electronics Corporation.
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[Submodel]  PAD_60_60_0p5_T
Submodel_type Dynamic_clamp
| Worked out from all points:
|   POWER clamp passes 1 mA (typ) near -0.06 V on its own axis
[GND Clamp]
| Voltage   I(typ)   I(min)   I(max)
-1.2V     23.5mA     15.45mA    25.45mA
-1V       19.53mA    16.99mA    17.56mA
-800mV    12.79mA    10.74mA    14.11mA
-400mV    1.727mA    747.4uA    2.454mA
-200mV    -1.658mA   -1.126mA   -1.77mA
20mV      253.8uA    243.7uA    264.1uA
1.4V      22.7mA     20.85mA    24.63mA
1.6V      28.2mA     27.48mA    29.54mA
1.8V      40.67mA    37.67mA    39.3mA
2V        50mA       46.96mA    51.6mA
2.2V      61.49mA    59.07mA    62.44mA
2.4V      71.48mA    64.48mA    76.02mA
[POWER Clamp]
| Voltage   I(typ)   I(min)   I(max)
-1.2V     -30.94mA   -27.46mA   -33.24mA
-1V       -21.95mA   -22.79mA   -23.91mA
-800mV    -12mA      -12.39mA   -13.63mA
-600mV    -5.155mA   -3.505mA   -4.586mA
-400mV    3.35mA     1.123mA    2.543mA
-200mV    3.157mA    2.612mA    3.284mA
1.4V      -21.99mA   -20.1mA    -23.64mA
1.6V      -29.31mA   -27.75mA   -30.32mA
1.8V      -37.44mA   -34.93mA   -38.89mA
2V        -43.97mA   -38.79mA   -44.9mA
2.2V      -51.77mA   -46.2mA    -55.19mA
2.4V      -56.6mA    -50.27mA   -60.48mA
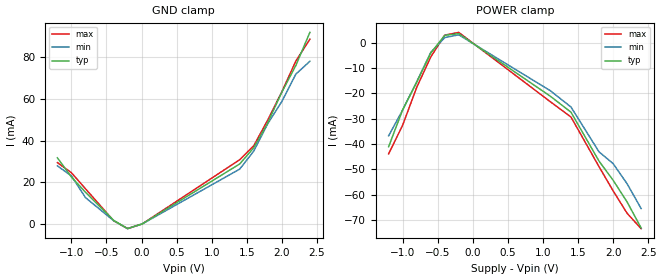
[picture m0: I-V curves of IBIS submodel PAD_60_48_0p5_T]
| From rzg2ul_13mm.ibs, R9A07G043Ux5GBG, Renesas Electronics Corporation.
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[Submodel]  PAD_60_48_0p5_T
Submodel_type Dynamic_clamp
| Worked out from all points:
|   POWER clamp passes 1 mA (typ) near -0.06 V on its own axis
[GND Clamp]
| Voltage   I(typ)   I(min)   I(max)
-1.2V     31.77mA    27.93mA    29.47mA
-1V       22.59mA    23.11mA    24.63mA
-800mV    15.32mA    12.75mA    16.99mA
-400mV    1.89mA     1.744mA    1.752mA
-200mV    -2.073mA   -2.112mA   -2.097mA
10mV      168.5uA    147.5uA    150.2uA
1.4V      28.85mA    26.39mA    30.88mA
1.6V      36.59mA    35mA       37.57mA
1.8V      48.57mA    48.13mA    49.9mA
2V        63.18mA    58.7mA     63.33mA
2.2V      75.95mA    71.79mA    78.05mA
2.4V      91.76mA    77.96mA    88.5mA
[POWER Clamp]
| Voltage   I(typ)   I(min)   I(max)
-1.2V     -41.08mA   -36.8mA    -43.9mA
-1V       -26.53mA   -26.61mA   -32.59mA
-800mV    -15.67mA   -15.49mA   -17.69mA
-600mV    -4.19mA    -3.921mA   -5.733mA
-400mV    2.853mA    1.944mA    2.914mA
-200mV    3.478mA    3.03mA     3.989mA
1.105V    -21.18mA   -19.01mA   -23.35mA
1.4V      -27.49mA   -25.45mA   -29.4mA
1.8V      -46.8mA    -43.14mA   -48.99mA
2V        -54.3mA    -47.74mA   -58.48mA
2.2V      -62.9mA    -55.71mA   -67.36mA
2.4V      -73.14mA   -65.49mA   -73.43mA
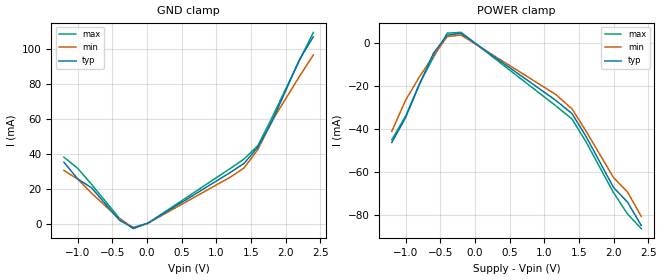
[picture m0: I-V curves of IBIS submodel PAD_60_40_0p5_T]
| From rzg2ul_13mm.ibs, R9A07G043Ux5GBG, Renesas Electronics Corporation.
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[Submodel]  PAD_60_40_0p5_T
Submodel_type Dynamic_clamp
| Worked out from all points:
|   POWER clamp passes 1 mA (typ) near -0.05 V on its own axis
[GND Clamp]
| Voltage   I(typ)   I(min)   I(max)
-1.2V     35.25mA    30.56mA    38.17mA
-1V       25.64mA    25.48mA    31.71mA
-800mV    20.51mA    17.47mA    22.48mA
-400mV    2.057mA    2.74mA     3.156mA
-200mV    -2.488mA   -2.16mA    -2.886mA
10mV      190.3uA    173uA      207.9uA
1.21V     29.57mA    26.86mA    31.86mA
1.4V      34.52mA    31.93mA    37.11mA
1.6V      43.91mA    42.53mA    44.74mA
1.8V      58.29mA    58.59mA    60.5mA
2.2V      94.09mA    84.51mA    93.66mA
2.4V      107.2mA    96.74mA    109.7mA
[POWER Clamp]
| Voltage   I(typ)   I(min)   I(max)
-1.2V     -46.41mA   -41.2mA    -45.17mA
-1V       -34.77mA   -26.67mA   -34.08mA
-800mV    -19.34mA   -15.86mA   -19.13mA
-600mV    -5.03mA    -6.174mA   -6.881mA
-400mV    3.423mA    2.765mA    4.343mA
-200mV    4.268mA    3.447mA    4.694mA
1.165V    -26.82mA   -24.09mA   -29.35mA
1.4V      -32.98mA   -30.79mA   -35.47mA
1.6V      -43.43mA   -40.98mA   -45.92mA
2V        -67.28mA   -62.7mA    -69.7mA
2.2V      -74.01mA   -69.3mA    -79.51mA
2.4V      -84.9mA    -80.72mA   -86.38mA
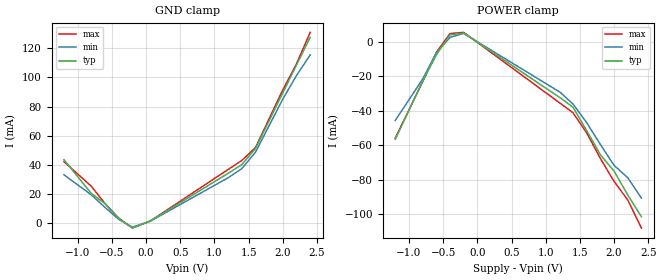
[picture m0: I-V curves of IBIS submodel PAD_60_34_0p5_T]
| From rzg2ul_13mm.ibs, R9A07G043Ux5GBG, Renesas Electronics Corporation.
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[Submodel]  PAD_60_34_0p5_T
Submodel_type Dynamic_clamp
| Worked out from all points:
|   POWER clamp passes 1 mA (typ) near -0.04 V on its own axis
[GND Clamp]
| Voltage   I(typ)   I(min)   I(max)
-1.2V     43.52mA    33.19mA    42.19mA
-800mV    20.38mA    19.48mA    25.35mA
-600mV    13.44mA    10.8mA     13.46mA
-400mV    3.287mA    2.656mA    3.505mA
-200mV    -3.368mA   -2.675mA   -3.213mA
60mV      1.504mA    1.305mA    1.474mA
1.21V     34.51mA    31.44mA    37.15mA
1.4V      40.2mA     37.46mA    43.03mA
1.6V      51.23mA    48.74mA    51.91mA
2V        89.52mA    85.21mA    91.49mA
2.2V      108.5mA    101.3mA    109.3mA
2.4V      127.5mA    115.5mA    130.9mA
[POWER Clamp]
| Voltage   I(typ)   I(min)   I(max)
-1.2V     -56.55mA   -45.6mA    -55.83mA
-800mV    -23.01mA   -21.68mA   -23.19mA
-600mV    -7.67mA    -6.589mA   -6.252mA
-400mV    3.993mA    2.505mA    4.714mA
-200mV    5.057mA    4.807mA    5.398mA
1.21V     -32.43mA   -29.26mA   -35.61mA
1.4V      -38.02mA   -36.13mA   -41.22mA
1.6V      -51.55mA   -46.96mA   -52.85mA
1.8V      -65.52mA   -59.56mA   -67.66mA
2V        -74.95mA   -71.65mA   -80.92mA
2.2V      -88.79mA   -78.81mA   -91.68mA
2.4V      -101.4mA   -90.63mA   -108mA
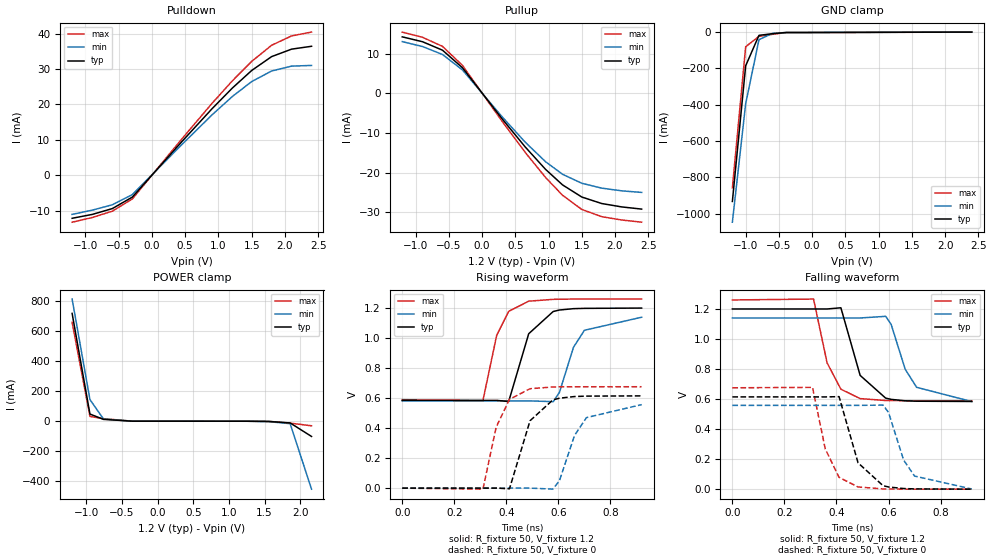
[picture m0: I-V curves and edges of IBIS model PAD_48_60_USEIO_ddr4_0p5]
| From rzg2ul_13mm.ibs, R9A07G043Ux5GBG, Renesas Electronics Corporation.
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[Model] PAD_48_60_USEIO_ddr4_0p5
Model_type I/O
Polarity   Non-Inverting
Vinl = 0.5070
Vinh = 0.6930
Vmeas= 0.600
| Capacitance   typ   min   max
C_comp   2.102e-12   2.013e-12   2.214e-12
[Model Spec]
| Subparameter   typ   min   max
Vmeas   0.600   0.570   0.630
Vinh   0.6930   0.6630   0.7230
Vinl   0.5070   0.4770   0.5370
| Variables   typ   min   max
[GND Clamp Reference]   0   0   0
[POWER Clamp Reference]   1.2   1.14   1.26
[Pulldown Reference]   0   0   0
[Pullup Reference]   1.2   1.14   1.26
[Temperature Range]   25   125   -40
[Voltage Range]   1.2   1.14   1.26
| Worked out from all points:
|   slope of the pulldown table from 0 to 0.18 V, typ, clamps not added: 47.1 ohm
|   slope of the pullup table from 0 to 0.18 V, typ, clamps not added: 46.4 ohm
|   GND clamp passes 1 mA (typ) near -0.30 V on its own axis
|   POWER clamp passes 1 mA (typ) near -0.38 V on its own axis
|   rising waveform, R_fixture 50, V_fixture 1.2: 20-80 % time 65.5ps typ, 73.3ps min, 59.2ps max; typ from 0.584 V to 1.2 V
|   rising waveform, R_fixture 50, V_fixture 0: 20-80 % time 69ps typ, 78.8ps min, 61.9ps max; typ from 0 V to 0.615 V
|   falling waveform, R_fixture 50, V_fixture 1.2: 20-80 % time 67.7ps typ, 76.9ps min, 61.8ps max; typ from 1.2 V to 0.584 V
|   falling waveform, R_fixture 50, V_fixture 0: 20-80 % time 66.6ps typ, 75.4ps min, 60.6ps max; typ from 0.614 V to 0 V
[GND Clamp]
| Voltage   I(typ)   I(min)   I(max)
-1.2V     -932.7mA   -1.047A    -857.4mA
-1V       -185.5mA   -394.3mA   -80.64mA
-800mV    -17.89mA   -41.9mA    -23.65mA
-600mV    -9.04mA    -7.411mA   -12.44mA
-400mV    -2.454mA   -2.378mA   -3.185mA
2.4V      0A         0A         0A
[POWER Clamp]
| Voltage   I(typ)   I(min)   I(max)
-1.2V     719.7mA    815.2mA    660.1mA
-950mV    48.1mA     144.6mA    32.07mA
-760mV    12.41mA    14.91mA    17.11mA
-360mV    527.4uA    791.2uA    575.5uA
1.26V     -115.5nA   -12.89uA   -796.6pA
1.56V     -1.53mA    -2.776mA   -549.4uA
1.86V     -11.39mA   -16.33mA   -12.44mA
2.16V     -101.5mA   -453.2mA   -30.39mA
[Pulldown]
| Voltage   I(typ)   I(min)   I(max)
-1.2V     -12.1mA    -11mA      -13.2mA
-895mV    -11mA      -9.8mA     -11.87mA
-595mV    -9.361mA   -8.288mA   -10.09mA
-295mV    -6.128mA   -5.421mA   -6.652mA
450mV     9.52mA     8.682mA    10.28mA
905mV     18.81mA    17.08mA    20.33mA
1.21V     24.63mA    22.25mA    26.67mA
1.5V      29.57mA    26.45mA    32.13mA
1.8V      33.49mA    29.43mA    36.69mA
2.1V      35.59mA    30.8mA     39.32mA
2.4V      36.4mA     31mA       40.4mA
[Pullup]
| Voltage   I(typ)   I(min)   I(max)
-1.2V     14.2mA     13mA       15.4mA
-895mV    12.97mA    11.76mA    14.08mA
-595mV    10.84mA    9.754mA    11.8mA
-295mV    6.423mA    5.87mA     7.012mA
300mV     -6.422mA   -5.908mA   -7.039mA
650mV     -13.56mA   -12.36mA   -14.93mA
955mV     -19.19mA   -17.26mA   -21.23mA
1.21V     -23.1mA    -20.43mA   -25.71mA
1.5V      -26.16mA   -22.69mA   -29.29mA
1.8V      -27.8mA    -23.92mA   -31.11mA
2.1V      -28.65mA   -24.6mA    -31.95mA
2.4V      -29.2mA    -25mA      -32.5mA
[Ramp]
dV/dt_r   0.3694/6.554e-11   0.3342/7.334e-11   0.4023/5.923e-11
dV/dt_f   0.3687/6.656e-11   0.3340/7.536e-11   0.4050/6.059e-11
R_load= 50
[Rising Waveform]
R_fixture = 50
V_fixture = 1.2
V_fixture_min = 1.14
V_fixture_max = 1.26
| Time   V(typ)   V(min)   V(max)
0s        584.4mV    581.7mV    589.5mV
310ps     584.4mV    581.7mV    583.4mV
363ps     584.8mV    581.7mV    1.019V
409ps     577.3mV    581.7mV    1.178V
486ps     1.029V     581.7mV    1.246V
580ps     1.177V     576.3mV    1.258V
604ps     1.187V     637.9mV    1.259V
658ps     1.196V     938.4mV    1.26V
700ps     1.198V     1.052V     1.26V
920ps     1.2V       1.139V     1.26V
[Rising Waveform]
R_fixture = 50
V_fixture = 0
V_fixture_min = 0
V_fixture_max = 0
| Time   V(typ)   V(min)   V(max)
0s        106.5nV    4.439uV    18.18nV
310ps     282.3nV    4.298uV    -6.86mV
361ps     338.8uV    4.044uV    406.7mV
412ps     -4.476mV   15.49uV    591.8mV
491ps     448.9mV    33.7uV     662.5mV
579ps     588.2mV    -6.451mV   674mV
604ps     599.4mV    49.49mV    674.8mV
662ps     610.4mV    351mV      675.5mV
708ps     613.2mV    470.1mV    675.6mV
920ps     614.8mV    556.6mV    675.7mV
[Falling Waveform]
R_fixture = 50
V_fixture = 1.2
V_fixture_min = 1.14
V_fixture_max = 1.26
| Time   V(typ)   V(min)   V(max)
0s        1.2V       1.14V      1.26V
312ps     1.2V       1.14V      1.266V
364ps     1.2V       1.14V      841.2mV
417ps     1.208V     1.14V      665.7mV
491ps     757.7mV    1.14V      603.2mV
589ps     606.3mV    1.151V     590.4mV
610ps     598.1mV    1.098V     589.8mV
664ps     588.5mV    799.1mV    589.2mV
708ps     585.7mV    678.3mV    589mV
920ps     584mV      583.4mV    588.9mV
[Falling Waveform]
R_fixture = 50
V_fixture = 0
V_fixture_min = 0
V_fixture_max = 0
| Time   V(typ)   V(min)   V(max)
0s        614.4mV    558mV      675.1mV
308ps     614.4mV    558mV      677.8mV
357ps     614.2mV    558mV      267.8mV
410ps     616.2mV    558mV      78.67mV
483ps     175.2mV    557.9mV    14.59mV
579ps     23.16mV    560mV      1.535mV
600ps     14.54mV    511.5mV    939.4uV
658ps     4.301mV    194.4mV    269.8uV
700ps     1.697mV    87.28mV    82.37uV
920ps     11.92uV    1.303mV    348.5nV
[Add Submodel]
| Submodel Name Mode
PAD_48_60_0p5_T Non-Driving
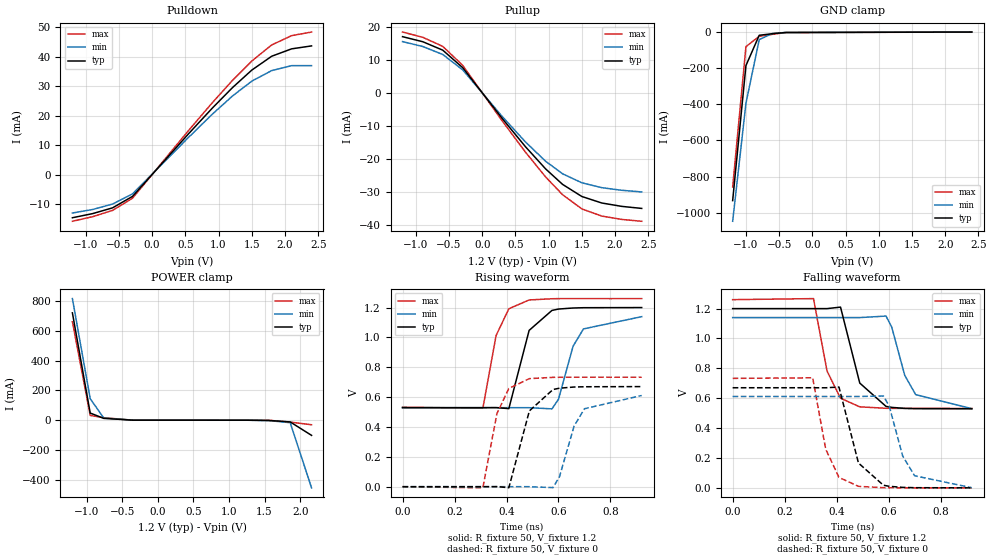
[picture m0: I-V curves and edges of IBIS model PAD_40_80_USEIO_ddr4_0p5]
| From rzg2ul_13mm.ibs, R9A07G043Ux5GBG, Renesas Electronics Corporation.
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[Model] PAD_40_80_USEIO_ddr4_0p5
Model_type I/O
Polarity   Non-Inverting
Vinl = 0.5070
Vinh = 0.6930
Vmeas= 0.600
| Capacitance   typ   min   max
C_comp   2.102e-12   2.013e-12   2.214e-12
[Model Spec]
| Subparameter   typ   min   max
Vmeas   0.600   0.570   0.630
Vinh   0.6930   0.6630   0.7230
Vinl   0.5070   0.4770   0.5370
| Variables   typ   min   max
[GND Clamp Reference]   0   0   0
[POWER Clamp Reference]   1.2   1.14   1.26
[Pulldown Reference]   0   0   0
[Pullup Reference]   1.2   1.14   1.26
[Temperature Range]   25   125   -40
[Voltage Range]   1.2   1.14   1.26
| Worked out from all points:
|   slope of the pulldown table from 0 to 0.18 V, typ, clamps not added: 39.2 ohm
|   slope of the pullup table from 0 to 0.18 V, typ, clamps not added: 38.7 ohm
|   GND clamp passes 1 mA (typ) near -0.30 V on its own axis
|   POWER clamp passes 1 mA (typ) near -0.38 V on its own axis
|   rising waveform, R_fixture 50, V_fixture 1.2: 20-80 % time 59.4ps typ, 67.5ps min, 53.2ps max; typ from 0.529 V to 1.2 V
|   rising waveform, R_fixture 50, V_fixture 0: 20-80 % time 62ps typ, 71.8ps min, 55.4ps max; typ from 0 V to 0.671 V
|   falling waveform, R_fixture 50, V_fixture 1.2: 20-80 % time 61.2ps typ, 70.6ps min, 55.8ps max; typ from 1.2 V to 0.529 V
|   falling waveform, R_fixture 50, V_fixture 0: 20-80 % time 60.3ps typ, 69.1ps min, 54.6ps max; typ from 0.67 V to 0 V
[GND Clamp]
| Voltage   I(typ)   I(min)   I(max)
-1.2V     -932.7mA   -1.047A    -857.4mA
-1V       -185.5mA   -394.3mA   -80.64mA
-800mV    -17.89mA   -41.9mA    -23.65mA
-600mV    -9.04mA    -7.411mA   -12.44mA
-400mV    -2.454mA   -2.378mA   -3.185mA
2.4V      0A         0A         0A
[POWER Clamp]
| Voltage   I(typ)   I(min)   I(max)
-1.2V     719.7mA    815.2mA    660.1mA
-950mV    48.1mA     144.6mA    32.07mA
-760mV    12.41mA    14.91mA    17.11mA
-360mV    527.4uA    791.2uA    575.5uA
1.26V     -115.5nA   -12.89uA   -796.6pA
1.56V     -1.53mA    -2.776mA   -549.4uA
1.86V     -11.39mA   -16.33mA   -12.44mA
2.16V     -101.5mA   -453.2mA   -30.39mA
[Pulldown]
| Voltage   I(typ)   I(min)   I(max)
-1.2V     -14.6mA    -13mA      -15.8mA
-895mV    -13.2mA    -11.8mA    -14.24mA
-595mV    -11.24mA   -9.948mA   -12.1mA
-295mV    -7.353mA   -6.505mA   -7.982mA
550mV     13.92mA    12.69mA    15.03mA
905mV     22.57mA    20.5mA     24.39mA
1.21V     29.55mA    26.7mA     32mA
1.5V      35.48mA    31.74mA    38.56mA
1.8V      40.19mA    35.32mA    44.02mA
2.1V      42.7mA     37mA       47.18mA
2.4V      43.7mA     37mA       48.4mA
[Pullup]
| Voltage   I(typ)   I(min)   I(max)
-1.2V     17.1mA     15.6mA     18.5mA
-895mV    15.56mA    14.11mA    16.9mA
-595mV    13.01mA    11.7mA     14.16mA
-295mV    7.708mA    7.044mA    8.414mA
300mV     -7.706mA   -7.09mA    -8.447mA
650mV     -16.27mA   -14.83mA   -17.91mA
955mV     -23.03mA   -20.71mA   -25.48mA
1.21V     -27.72mA   -24.51mA   -30.85mA
1.5V      -31.39mA   -27.23mA   -35.15mA
1.8V      -33.36mA   -28.71mA   -37.33mA
2.1V      -34.38mA   -29.5mA    -38.34mA
2.4V      -35mA      -30mA      -38.9mA
[Ramp]
dV/dt_r   0.4023/5.940e-11   0.3660/6.746e-11   0.4366/5.320e-11
dV/dt_f   0.4021/6.028e-11   0.3665/6.908e-11   0.4397/5.460e-11
R_load= 50
[Rising Waveform]
R_fixture = 50
V_fixture = 1.2
V_fixture_min = 1.14
V_fixture_max = 1.26
| Time   V(typ)   V(min)   V(max)
0s        529.5mV    529.2mV    532.3mV
309ps     529.5mV    529.2mV    525.5mV
360ps     529.9mV    529.2mV    1.013V
409ps     523mV      529.2mV    1.192V
487ps     1.047V     529.2mV    1.251V
575ps     1.181V     521.4mV    1.259V
600ps     1.19V      585.6mV    1.26V
656ps     1.197V     940.7mV    1.26V
696ps     1.199V     1.057V     1.26V
920ps     1.2V       1.139V     1.26V
[Rising Waveform]
R_fixture = 50
V_fixture = 0
V_fixture_min = 0
V_fixture_max = 0
| Time   V(typ)   V(min)   V(max)
0s        96.58nV    4.04uV     16.71nV
309ps     2.627uV    3.855uV    -7.648mV
363ps     616uV      3.659uV    488.9mV
409ps     -6.873mV   18.77uV    658.3mV
488ps     507.9mV    26.23uV    723.9mV
579ps     651.1mV    -6.116mV   732.5mV
604ps     659.9mV    67.45mV    733mV
660ps     667.7mV    405.7mV    733.3mV
700ps     669.5mV    522.3mV    733.4mV
920ps     670.5mV    610.9mV    733.4mV
[Falling Waveform]
R_fixture = 50
V_fixture = 1.2
V_fixture_min = 1.14
V_fixture_max = 1.26
| Time   V(typ)   V(min)   V(max)
0s        1.2V       1.14V      1.26V
311ps     1.2V       1.14V      1.267V
363ps     1.2V       1.14V      782.3mV
415ps     1.21V      1.14V      600.1mV
489ps     701.4mV    1.14V      542.3mV
590ps     545.3mV    1.15V      532.6mV
612ps     538.7mV    1.076V     532.2mV
662ps     532mV      753.3mV    531.9mV
704ps     530.2mV    624.2mV    531.8mV
920ps     529.1mV    530.2mV    531.8mV
[Falling Waveform]
R_fixture = 50
V_fixture = 0
V_fixture_min = 0
V_fixture_max = 0
| Time   V(typ)   V(min)   V(max)
0s        670.2mV    611.6mV    732.9mV
308ps     670.2mV    611.6mV    736.7mV
358ps     669.9mV    611.6mV    258.7mV
409ps     674.9mV    611.6mV    69.91mV
484ps     166.1mV    611.5mV    10.04mV
580ps     17.39mV    614.9mV    836.2uV
602ps     10.32mV    549.6mV    445.3uV
654ps     3.105mV    213.4mV    128.7uV
700ps     988.6uV    80.86mV    29.94uV
920ps     3.715uV    791uV      72.58nV
[Add Submodel]
| Submodel Name Mode
PAD_40_80_0p5_T Non-Driving
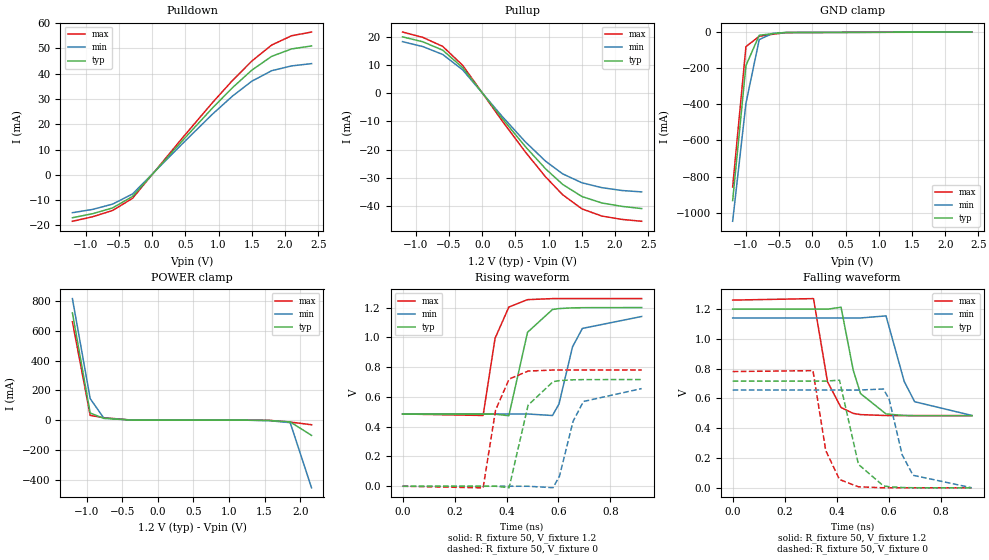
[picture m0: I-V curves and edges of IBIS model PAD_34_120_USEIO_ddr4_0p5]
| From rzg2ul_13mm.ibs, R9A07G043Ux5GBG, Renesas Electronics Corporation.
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[Model] PAD_34_120_USEIO_ddr4_0p5
Model_type I/O
Polarity   Non-Inverting
Vinl = 0.5070
Vinh = 0.6930
Vmeas= 0.600
| Capacitance   typ   min   max
C_comp   2.102e-12   2.013e-12   2.214e-12
[Model Spec]
| Subparameter   typ   min   max
Vmeas   0.600   0.570   0.630
Vinh   0.6930   0.6630   0.7230
Vinl   0.5070   0.4770   0.5370
| Variables   typ   min   max
[GND Clamp Reference]   0   0   0
[POWER Clamp Reference]   1.2   1.14   1.26
[Pulldown Reference]   0   0   0
[Pullup Reference]   1.2   1.14   1.26
[Temperature Range]   25   125   -40
[Voltage Range]   1.2   1.14   1.26
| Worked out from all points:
|   slope of the pulldown table from 0 to 0.18 V, typ, clamps not added: 33.6 ohm
|   slope of the pullup table from 0 to 0.18 V, typ, clamps not added: 33.2 ohm
|   GND clamp passes 1 mA (typ) near -0.30 V on its own axis
|   POWER clamp passes 1 mA (typ) near -0.38 V on its own axis
|   rising waveform, R_fixture 50, V_fixture 1.2: 20-80 % time 53.8ps typ, 61.1ps min, 48.1ps max; typ from 0.484 V to 1.2 V
|   rising waveform, R_fixture 50, V_fixture 0: 20-80 % time 56.3ps typ, 65.4ps min, 50ps max; typ from 0 V to 0.717 V
|   falling waveform, R_fixture 50, V_fixture 1.2: 20-80 % time 55.6ps typ, 64.6ps min, 50.6ps max; typ from 1.2 V to 0.484 V
|   falling waveform, R_fixture 50, V_fixture 0: 20-80 % time 55.2ps typ, 63.4ps min, 49.6ps max; typ from 0.716 V to 0 V
[GND Clamp]
| Voltage   I(typ)   I(min)   I(max)
-1.2V     -932.7mA   -1.047A    -857.4mA
-1V       -185.5mA   -394.3mA   -80.64mA
-800mV    -17.89mA   -41.9mA    -23.65mA
-600mV    -9.04mA    -7.411mA   -12.44mA
-400mV    -2.454mA   -2.378mA   -3.185mA
2.4V      0A         0A         0A
[POWER Clamp]
| Voltage   I(typ)   I(min)   I(max)
-1.2V     719.7mA    815.2mA    660.1mA
-950mV    48.1mA     144.6mA    32.07mA
-760mV    12.41mA    14.91mA    17.11mA
-360mV    527.4uA    791.2uA    575.5uA
1.26V     -115.5nA   -12.89uA   -796.6pA
1.56V     -1.53mA    -2.776mA   -549.4uA
1.86V     -11.39mA   -16.33mA   -12.44mA
2.16V     -101.5mA   -453.2mA   -30.39mA
[Pulldown]
| Voltage   I(typ)   I(min)   I(max)
-1.2V     -17mA      -15mA      -18.4mA
-895mV    -15.4mA    -13.7mA    -16.61mA
-595mV    -13.11mA   -11.61mA   -14.12mA
-295mV    -8.579mA   -7.589mA   -9.313mA
450mV     13.33mA    12.15mA    14.39mA
905mV     26.33mA    23.91mA    28.46mA
1.21V     34.48mA    31.15mA    37.34mA
1.5V      41.4mA     37.03mA    44.99mA
1.8V      46.89mA    41.2mA     51.36mA
2.1V      49.82mA    43.1mA     55.04mA
2.4V      51mA       44mA       56.5mA
[Pullup]
| Voltage   I(typ)   I(min)   I(max)
-1.2V     19.9mA     18.2mA     21.6mA
-895mV    18.16mA    16.46mA    19.71mA
-595mV    15.18mA    13.66mA    16.52mA
-295mV    8.993mA    8.219mA    9.816mA
300mV     -8.991mA   -8.272mA   -9.855mA
650mV     -18.99mA   -17.31mA   -20.9mA
955mV     -26.87mA   -24.16mA   -29.72mA
1.21V     -32.34mA   -28.6mA    -35.99mA
1.5V      -36.63mA   -31.77mA   -41mA
1.8V      -38.92mA   -33.49mA   -43.55mA
2.1V      -40.11mA   -34.5mA    -44.73mA
2.4V      -40.9mA    -35mA      -45.4mA
[Ramp]
dV/dt_r   0.4296/5.383e-11   0.3925/6.114e-11   0.4649/4.808e-11
dV/dt_f   0.4298/5.520e-11   0.3935/6.340e-11   0.4682/4.958e-11
R_load= 50
[Rising Waveform]
R_fixture = 50
V_fixture = 1.2
V_fixture_min = 1.14
V_fixture_max = 1.26
| Time   V(typ)   V(min)   V(max)
0s        484mV      485.3mV    485.2mV
310ps     484mV      485.3mV    475.3mV
356ps     484.2mV    485.3mV    993.5mV
409ps     473.4mV    485.3mV    1.203V
481ps     1.034V     485.3mV    1.253V
577ps     1.187V     475mV      1.26V
602ps     1.193V     553.1mV    1.26V
654ps     1.198V     936.4mV    1.26V
692ps     1.199V     1.06V      1.26V
920ps     1.2V       1.14V      1.26V
[Rising Waveform]
R_fixture = 50
V_fixture = 0
V_fixture_min = 0
V_fixture_max = 0
| Time   V(typ)   V(min)   V(max)
0s        88.32nV    3.707uV    12.95nV
310ps     -1.399uV   3.487uV    -10.64mV
358ps     303.7uV    3.223uV    511.8mV
410ps     -9.847mV   17.09uV    719.6mV
483ps     544.1mV    -82.17uV   773.4mV
579ps     702.1mV    -9.723mV   780.4mV
604ps     709.3mV    68.85mV    780.6mV
656ps     714.7mV    436mV      780.7mV
696ps     716mV      569.3mV    780.8mV
920ps     716.6mV    655.9mV    780.8mV
[Falling Waveform]
R_fixture = 50
V_fixture = 1.2
V_fixture_min = 1.14
V_fixture_max = 1.26
| Time   V(typ)   V(min)   V(max)
0s        1.2V       1.14V      1.26V
311ps     1.2V       1.14V      1.27V
365ps     1.199V     1.14V      711.5mV
417ps     1.212V     1.14V      539mV
464ps     788.6mV    1.14V      499.6mV
492ps     632.5mV    1.14V      491.5mV
590ps     495.8mV    1.154V     485.2mV
660ps     485.6mV    714.2mV    484.8mV
700ps     484.3mV    578.1mV    484.8mV
920ps     483.7mV    485.9mV    484.8mV
[Falling Waveform]
R_fixture = 50
V_fixture = 0
V_fixture_min = 0
V_fixture_max = 0
| Time   V(typ)   V(min)   V(max)
0s        716.3mV    656.3mV    780.4mV
309ps     716.3mV    656.3mV    786.5mV
358ps     716mV      656.3mV    251mV
411ps     722.8mV    656.2mV    55.78mV
484ps     157.3mV    656.1mV    6.923mV
580ps     13mV       663.2mV    405.7uV
602ps     7.334mV    595.6mV    215.6uV
652ps     2.069mV    222.3mV    57.66uV
694ps     642.2uV    84.23mV    12.64uV
920ps     1.101uV    452.2uV    28.75nV
[Add Submodel]
| Submodel Name Mode
PAD_34_120_0p5_T Non-Driving
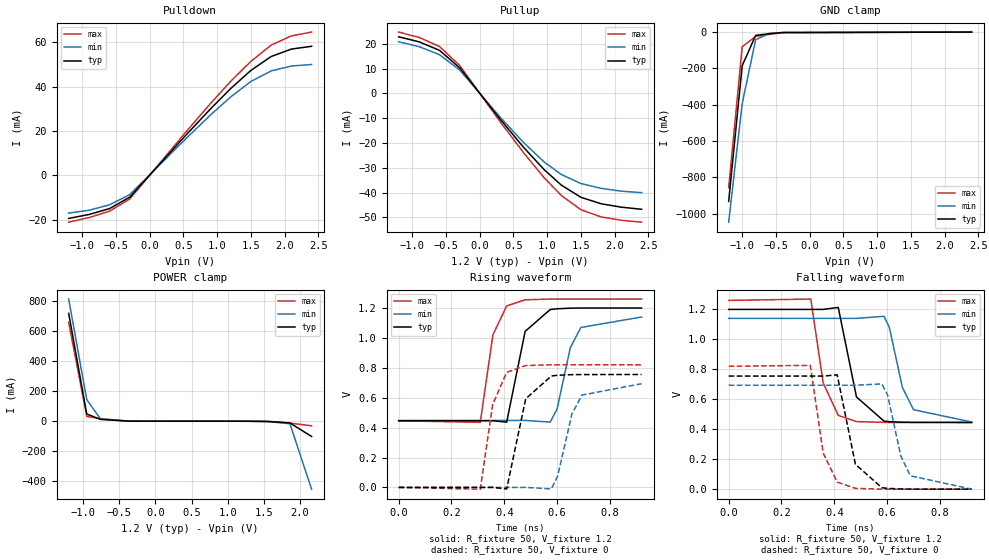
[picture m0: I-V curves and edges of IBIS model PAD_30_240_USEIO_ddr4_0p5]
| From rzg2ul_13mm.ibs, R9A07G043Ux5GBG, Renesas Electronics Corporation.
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[Model] PAD_30_240_USEIO_ddr4_0p5
Model_type I/O
Polarity   Non-Inverting
Vinl = 0.5070
Vinh = 0.6930
Vmeas= 0.600
| Capacitance   typ   min   max
C_comp   2.102e-12   2.013e-12   2.214e-12
[Model Spec]
| Subparameter   typ   min   max
Vmeas   0.600   0.570   0.630
Vinh   0.6930   0.6630   0.7230
Vinl   0.5070   0.4770   0.5370
| Variables   typ   min   max
[GND Clamp Reference]   0   0   0
[POWER Clamp Reference]   1.2   1.14   1.26
[Pulldown Reference]   0   0   0
[Pullup Reference]   1.2   1.14   1.26
[Temperature Range]   25   125   -40
[Voltage Range]   1.2   1.14   1.26
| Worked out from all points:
|   slope of the pulldown table from 0 to 0.18 V, typ, clamps not added: 29.4 ohm
|   slope of the pullup table from 0 to 0.18 V, typ, clamps not added: 29 ohm
|   GND clamp passes 1 mA (typ) near -0.30 V on its own axis
|   POWER clamp passes 1 mA (typ) near -0.38 V on its own axis
|   rising waveform, R_fixture 50, V_fixture 1.2: 20-80 % time 49.6ps typ, 56.9ps min, 44.2ps max; typ from 0.446 V to 1.2 V
|   rising waveform, R_fixture 50, V_fixture 0: 20-80 % time 51.7ps typ, 60.3ps min, 45.5ps max; typ from 0 V to 0.755 V
|   falling waveform, R_fixture 50, V_fixture 1.2: 20-80 % time 51.5ps typ, 60.4ps min, 46.3ps max; typ from 1.2 V to 0.445 V
|   falling waveform, R_fixture 50, V_fixture 0: 20-80 % time 51ps typ, 59.4ps min, 45.7ps max; typ from 0.755 V to 0 V
[GND Clamp]
| Voltage   I(typ)   I(min)   I(max)
-1.2V     -932.7mA   -1.047A    -857.4mA
-1V       -185.5mA   -394.3mA   -80.64mA
-800mV    -17.89mA   -41.9mA    -23.65mA
-600mV    -9.04mA    -7.411mA   -12.44mA
-400mV    -2.454mA   -2.378mA   -3.185mA
2.4V      0A         0A         0A
[POWER Clamp]
| Voltage   I(typ)   I(min)   I(max)
-1.2V     719.7mA    815.2mA    660.1mA
-950mV    48.1mA     144.6mA    32.07mA
-760mV    12.41mA    14.91mA    17.11mA
-360mV    527.4uA    791.2uA    575.5uA
1.26V     -115.5nA   -12.89uA   -796.6pA
1.56V     -1.53mA    -2.776mA   -549.4uA
1.86V     -11.39mA   -16.33mA   -12.44mA
2.16V     -101.5mA   -453.2mA   -30.39mA
[Pulldown]
| Voltage   I(typ)   I(min)   I(max)
-1.2V     -19.4mA    -17mA      -21.1mA
-895mV    -17.6mA    -15.7mA    -18.99mA
-595mV    -14.98mA   -13.26mA   -16.14mA
-295mV    -9.808mA   -8.673mA   -10.64mA
550mV     18.56mA    16.92mA    20.04mA
905mV     30.09mA    27.33mA    32.52mA
1.21V     39.41mA    35.6mA     42.67mA
1.5V      47.31mA    42.32mA    51.41mA
1.8V      53.58mA    47.09mA    58.7mA
2.1V      56.94mA    49.3mA     62.9mA
2.4V      58.2mA     50mA       64.6mA
[Pullup]
| Voltage   I(typ)   I(min)   I(max)
-1.2V     22.8mA     20.8mA     24.7mA
-895mV    20.75mA    18.81mA    22.53mA
-595mV    17.35mA    15.61mA    18.89mA
-295mV    10.28mA    9.393mA    11.22mA
300mV     -10.28mA   -9.453mA   -11.26mA
650mV     -21.7mA    -19.78mA   -23.89mA
955mV     -30.7mA    -27.61mA   -33.97mA
1.21V     -36.96mA   -32.68mA   -41.14mA
1.5V      -41.86mA   -36.31mA   -46.86mA
1.8V      -44.48mA   -38.27mA   -49.78mA
2.1V      -45.85mA   -39.4mA    -51.12mA
2.4V      -46.7mA    -40mA      -51.9mA
[Ramp]
dV/dt_r   0.4526/4.957e-11   0.4149/5.693e-11   0.4886/4.416e-11
dV/dt_f   0.4531/5.105e-11   0.4162/5.942e-11   0.4920/4.570e-11
R_load= 50
[Rising Waveform]
R_fixture = 50
V_fixture = 1.2
V_fixture_min = 1.14
V_fixture_max = 1.26
| Time   V(typ)   V(min)   V(max)
0s        445.7mV    448.2mV    445.7mV
309ps     445.7mV    448.2mV    435.3mV
357ps     446.1mV    448.2mV    1.021V
409ps     436.6mV    448.2mV    1.214V
479ps     1.044V     448.1mV    1.255V
574ps     1.19V      436.9mV    1.26V
600ps     1.195V     525.2mV    1.26V
650ps     1.199V     934.1mV    1.26V
690ps     1.2V       1.07V      1.26V
920ps     1.2V       1.14V      1.26V
[Rising Waveform]
R_fixture = 50
V_fixture = 0
V_fixture_min = 0
V_fixture_max = 0
| Time   V(typ)   V(min)   V(max)
0s        80.5nV     3.425uV    14nV
309ps     632.3nV    3.171uV    -11.67mV
356ps     310.6uV    2.805uV    555.2mV
409ps     -10.53mV   20.16uV    769.8mV
481ps     592.7mV    -87uV      815.3mV
578ps     745.1mV    -9.987mV   820.2mV
602ps     750.3mV    74.68mV    820.3mV
656ps     754.3mV    491.4mV    820.4mV
694ps     755mV      617.7mV    820.4mV
920ps     755.3mV    693.9mV    820.4mV
[Falling Waveform]
R_fixture = 50
V_fixture = 1.2
V_fixture_min = 1.14
V_fixture_max = 1.26
| Time   V(typ)   V(min)   V(max)
0s        1.2V       1.14V      1.26V
311ps     1.2V       1.14V      1.269V
358ps     1.2V       1.14V      708.4mV
415ps     1.213V     1.14V      492.5mV
484ps     615.6mV    1.14V      451.1mV
588ps     454.6mV    1.154V     445.6mV
608ps     450.6mV    1.083V     445.5mV
658ps     446.7mV    679.1mV    445.4mV
700ps     445.8mV    530.4mV    445.4mV
920ps     445.4mV    448.5mV    445.4mV
[Falling Waveform]
R_fixture = 50
V_fixture = 0
V_fixture_min = 0
V_fixture_max = 0
| Time   V(typ)   V(min)   V(max)
0s        755.1mV    694mV      820mV
309ps     755.1mV    694mV      826.4mV
358ps     754.8mV    694mV      241.3mV
411ps     763.1mV    694mV      47.14mV
480ps     165.9mV    694mV      5.527mV
580ps     9.76mV     702.5mV    276.7uV
602ps     5.27mV     628.2mV    115.3uV
652ps     1.325mV    220.6mV    27.31uV
688ps     463.1uV    89.39mV    5.741uV
920ps     358.2nV    271.3uV    14.84nV
[Add Submodel]
| Submodel Name Mode
PAD_30_240_0p5_T Non-Driving
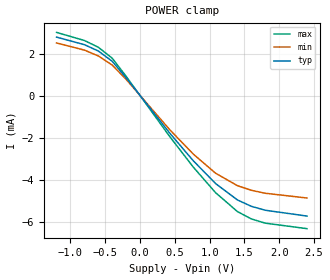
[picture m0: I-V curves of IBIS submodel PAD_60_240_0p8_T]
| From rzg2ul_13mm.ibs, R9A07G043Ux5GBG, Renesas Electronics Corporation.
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[Submodel]  PAD_60_240_0p8_T
Submodel_type Dynamic_clamp
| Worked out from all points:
|   POWER clamp passes 1 mA (typ) near -0.24 V on its own axis
[POWER Clamp]
| Voltage   I(typ)   I(min)   I(max)
-1.2V     2.797mA    2.519mA    3.022mA
-800mV    2.437mA    2.178mA    2.636mA
-600mV    2.136mA    1.901mA    2.315mA
-400mV    1.646mA    1.466mA    1.792mA
-200mV    856.8uA    783.8uA    929.4uA
425mV     -1.771mA   -1.607mA   -1.934mA
765mV     -3.093mA   -2.777mA   -3.395mA
1.085V    -4.179mA   -3.687mA   -4.613mA
1.4V      -4.962mA   -4.282mA   -5.517mA
1.6V      -5.266mA   -4.502mA   -5.867mA
1.8V      -5.453mA   -4.643mA   -6.068mA
2.4V      -5.73mA    -4.87mA    -6.33mA
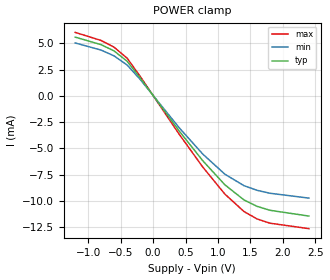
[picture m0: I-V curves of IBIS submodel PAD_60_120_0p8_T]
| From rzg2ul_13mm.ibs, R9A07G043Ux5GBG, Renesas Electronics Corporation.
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[Submodel]  PAD_60_120_0p8_T
Submodel_type Dynamic_clamp
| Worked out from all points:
|   POWER clamp passes 1 mA (typ) near -0.12 V on its own axis
[POWER Clamp]
| Voltage   I(typ)   I(min)   I(max)
-1.2V     5.594mA    5.038mA    6.045mA
-800mV    4.874mA    4.357mA    5.272mA
-600mV    4.273mA    3.801mA    4.63mA
-400mV    3.292mA    2.932mA    3.585mA
-200mV    1.714mA    1.568mA    1.859mA
405mV     -3.379mA   -3.068mA   -3.691mA
765mV     -6.187mA   -5.553mA   -6.789mA
1.105V    -8.477mA   -7.469mA   -9.363mA
1.4V      -9.924mA   -8.564mA   -11.03mA
1.6V      -10.53mA   -9.003mA   -11.73mA
1.8V      -10.91mA   -9.286mA   -12.14mA
2.4V      -11.46mA   -9.75mA    -12.66mA
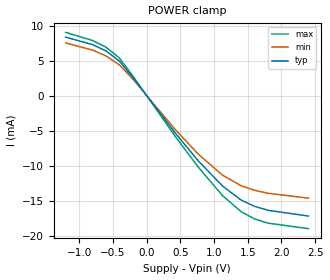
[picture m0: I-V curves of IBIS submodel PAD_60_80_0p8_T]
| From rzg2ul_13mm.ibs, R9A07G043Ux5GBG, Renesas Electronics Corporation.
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[Submodel]  PAD_60_80_0p8_T
Submodel_type Dynamic_clamp
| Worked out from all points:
|   POWER clamp passes 1 mA (typ) near -0.08 V on its own axis
[POWER Clamp]
| Voltage   I(typ)   I(min)   I(max)
-1.2V     8.391mA    7.557mA    9.068mA
-800mV    7.311mA    6.535mA    7.907mA
-600mV    6.409mA    5.702mA    6.945mA
-400mV    4.939mA    4.398mA    5.377mA
-200mV    2.57mA     2.352mA    2.788mA
425mV     -5.312mA   -4.82mA    -5.803mA
765mV     -9.28mA    -8.33mA    -10.18mA
1.125V    -12.89mA   -11.34mA   -14.25mA
1.4V      -14.89mA   -12.85mA   -16.55mA
1.6V      -15.8mA    -13.5mA    -17.6mA
1.8V      -16.36mA   -13.93mA   -18.2mA
2.4V      -17.19mA   -14.63mA   -18.99mA
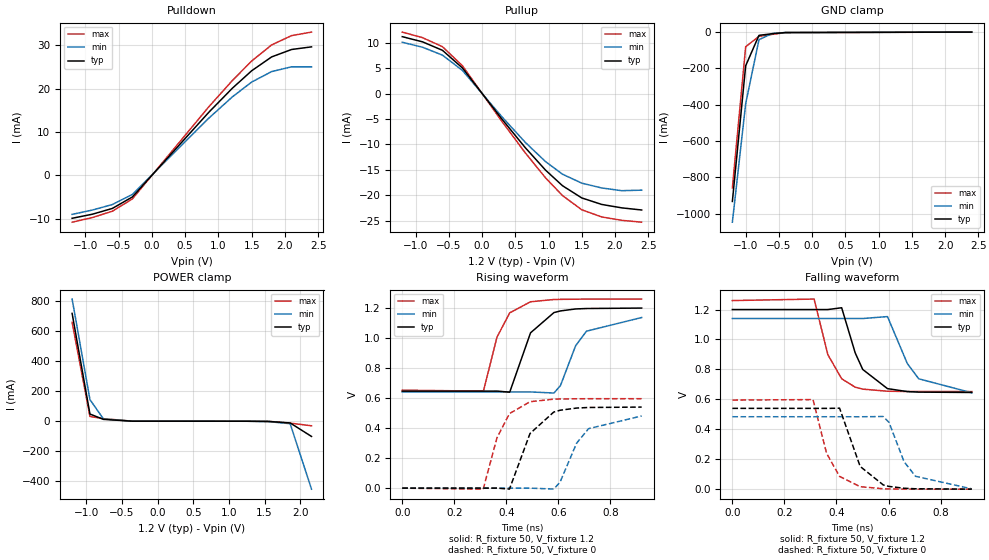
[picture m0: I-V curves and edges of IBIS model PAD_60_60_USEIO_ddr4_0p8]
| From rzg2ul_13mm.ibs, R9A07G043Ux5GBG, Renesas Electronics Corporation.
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[Model] PAD_60_60_USEIO_ddr4_0p8
Model_type I/O
Polarity   Non-Inverting
Vinl = 0.8670
Vinh = 1.0530
Vmeas= 0.960
| Capacitance   typ   min   max
C_comp   2.102e-12   2.013e-12   2.216e-12
[Model Spec]
| Subparameter   typ   min   max
Vmeas   0.960   0.912   1.008
Vinh   1.0530   1.0050   1.1010
Vinl   0.8670   0.8190   0.9150
| Variables   typ   min   max
[GND Clamp Reference]   0   0   0
[POWER Clamp Reference]   1.2   1.14   1.26
[Pulldown Reference]   0   0   0
[Pullup Reference]   1.2   1.14   1.26
[Temperature Range]   25   125   -40
[Voltage Range]   1.2   1.14   1.26
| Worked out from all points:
|   slope of the pulldown table from 0 to 0.18 V, typ, clamps not added: 57.7 ohm
|   slope of the pullup table from 0 to 0.18 V, typ, clamps not added: 59.2 ohm
|   GND clamp passes 1 mA (typ) near -0.30 V on its own axis
|   POWER clamp passes 1 mA (typ) near -0.38 V on its own axis
|   rising waveform, R_fixture 50, V_fixture 1.2: 20-80 % time 73.4ps typ, 82ps min, 66.5ps max; typ from 0.646 V to 1.2 V
|   rising waveform, R_fixture 50, V_fixture 0: 20-80 % time 78.4ps typ, 88.6ps min, 70.3ps max; typ from 0 V to 0.54 V
|   falling waveform, R_fixture 50, V_fixture 1.2: 20-80 % time 74.9ps typ, 84ps min, 68.9ps max; typ from 1.2 V to 0.646 V
|   falling waveform, R_fixture 50, V_fixture 0: 20-80 % time 73.8ps typ, 82.3ps min, 67.3ps max; typ from 0.54 V to 0 V
[GND Clamp]
| Voltage   I(typ)   I(min)   I(max)
-1.2V     -932.7mA   -1.047A    -857.4mA
-1V       -185.5mA   -394.3mA   -80.64mA
-800mV    -17.89mA   -41.9mA    -23.65mA
-600mV    -9.04mA    -7.411mA   -12.44mA
-400mV    -2.454mA   -2.378mA   -3.185mA
2.4V      0A         0A         0A
[POWER Clamp]
| Voltage   I(typ)   I(min)   I(max)
-1.2V     719.7mA    815.2mA    660.1mA
-950mV    48.1mA     144.6mA    32.07mA
-760mV    12.41mA    14.91mA    17.11mA
-360mV    527.4uA    791.2uA    575.5uA
1.26V     -115.5nA   -12.89uA   -796.6pA
1.56V     -1.53mA    -2.776mA   -549.4uA
1.86V     -11.39mA   -16.33mA   -12.44mA
2.16V     -101.5mA   -453.2mA   -30.39mA
[Pulldown]
| Voltage   I(typ)   I(min)   I(max)
-1.2V     -9.9mA     -9mA       -10.8mA
-895mV    -8.96mA    -8mA       -9.73mA
-595mV    -7.631mA   -6.738mA   -8.27mA
-295mV    -4.994mA   -4.407mA   -5.452mA
855mV     14.52mA    13.16mA    15.78mA
1.21V     20.07mA    18.08mA    21.85mA
1.5V      24.09mA    21.49mA    26.33mA
1.8V      27.28mA    23.9mA     30.05mA
2.1V      28.99mA    25mA       32.19mA
2.4V      29.6mA     25mA       33mA
[Pullup]
| Voltage   I(typ)   I(min)   I(max)
-1.2V     11.2mA     10.1mA     12.1mA
-895mV    10.18mA    9.12mA     11mA
-595mV    8.511mA    7.564mA    9.224mA
-295mV    5.039mA    4.554mA    5.475mA
300mV     -5.038mA   -4.584mA   -5.496mA
650mV     -10.64mA   -9.591mA   -11.66mA
955mV     -15.06mA   -13.39mA   -16.58mA
1.21V     -18.13mA   -15.86mA   -20.07mA
1.5V      -20.53mA   -17.62mA   -22.86mA
1.8V      -21.81mA   -18.57mA   -24.27mA
2.1V      -22.48mA   -19.1mA    -24.93mA
2.4V      -22.9mA    -19mA      -25.3mA
[Ramp]
dV/dt_r   0.3322/7.338e-11   0.2978/8.203e-11   0.3643/6.654e-11
dV/dt_f   0.3239/7.385e-11   0.2890/8.232e-11   0.3572/6.728e-11
R_load= 50
[Rising Waveform]
R_fixture = 50
V_fixture = 1.2
V_fixture_min = 1.14
V_fixture_max = 1.26
| Time   V(typ)   V(min)   V(max)
0s        646.4mV    641.1mV    652.8mV
312ps     646.4mV    641.1mV    646.5mV
364ps     646.7mV    641.1mV    1.006V
413ps     639.6mV    641.1mV    1.168V
493ps     1.035V     641.1mV    1.242V
583ps     1.17V      633.9mV    1.257V
608ps     1.181V     683.8mV    1.258V
666ps     1.194V     947.9mV    1.259V
708ps     1.197V     1.046V     1.26V
920ps     1.2V       1.137V     1.26V
[Rising Waveform]
R_fixture = 50
V_fixture = 0
V_fixture_min = 0
V_fixture_max = 0
| Time   V(typ)   V(min)   V(max)
0s        117.3nV    4.889uV    20.46nV
311ps     -237nV     4.778uV    -6.834mV
364ps     266.2uV    4.708uV    335.3mV
412ps     -6.394mV   12.92uV    496.4mV
491ps     364mV      -26.03uV   576mV
582ps     506.8mV    -5.953mV   592.9mV
606ps     518.9mV    38.49mV    594.2mV
670ps     533.7mV    299.7mV    595.5mV
716ps     537.5mV    396.4mV    595.9mV
920ps     540.2mV    480.9mV    596mV
[Falling Waveform]
R_fixture = 50
V_fixture = 1.2
V_fixture_min = 1.14
V_fixture_max = 1.26
| Time   V(typ)   V(min)   V(max)
0s        1.2V       1.14V      1.26V
314ps     1.2V       1.14V      1.27V
367ps     1.2V       1.14V      898.4mV
420ps     1.212V     1.14V      737.7mV
472ps     910.5mV    1.14V      681.3mV
501ps     799.7mV    1.14V      668.3mV
596ps     671.6mV    1.153V     654.3mV
672ps     652mV      840.5mV    652.5mV
716ps     648.4mV    737.4mV    652.2mV
920ps     645.9mV    644mV      652mV
[Falling Waveform]
R_fixture = 50
V_fixture = 0
V_fixture_min = 0
V_fixture_max = 0
| Time   V(typ)   V(min)   V(max)
0s        539.8mV    483.8mV    595.3mV
310ps     539.8mV    483.8mV    598.3mV
362ps     539.6mV    483.8mV    239.6mV
412ps     540.9mV    483.8mV    85.13mV
491ps     151.9mV    483.6mV    16.57mV
580ps     28.11mV    485.3mV    2.611mV
602ps     18.33mV    445.5mV    1.561mV
660ps     6.115mV    182.6mV    507.8uV
704ps     2.581mV    85.89mV    173.2uV
920ps     34.66uV    2.09mV     1.472uV
[Add Submodel]
| Submodel Name Mode
PAD_60_60_0p8_T Non-Driving
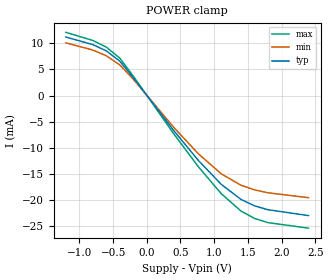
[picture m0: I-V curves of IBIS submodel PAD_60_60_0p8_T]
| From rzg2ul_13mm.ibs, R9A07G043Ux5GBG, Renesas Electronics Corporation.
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[Submodel]  PAD_60_60_0p8_T
Submodel_type Dynamic_clamp
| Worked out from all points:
|   POWER clamp passes 1 mA (typ) near -0.06 V on its own axis
[POWER Clamp]
| Voltage   I(typ)   I(min)   I(max)
-1.2V     11.19mA    10.08mA    12.09mA
-800mV    9.748mA    8.714mA    10.54mA
-600mV    8.546mA    7.603mA    9.261mA
-400mV    6.585mA    5.864mA    7.17mA
-200mV    3.427mA    3.135mA    3.718mA
405mV     -6.759mA   -6.135mA   -7.382mA
765mV     -12.37mA   -11.11mA   -13.58mA
1.105V    -16.95mA   -14.94mA   -18.73mA
1.4V      -19.85mA   -17.13mA   -22.07mA
1.6V      -21.06mA   -18.01mA   -23.47mA
1.8V      -21.81mA   -18.57mA   -24.27mA
2.4V      -22.92mA   -19.5mA    -25.32mA
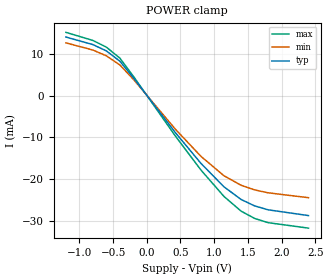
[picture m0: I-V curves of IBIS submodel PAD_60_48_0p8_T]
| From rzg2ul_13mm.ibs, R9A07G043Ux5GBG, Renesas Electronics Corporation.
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[Submodel]  PAD_60_48_0p8_T
Submodel_type Dynamic_clamp
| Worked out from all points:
|   POWER clamp passes 1 mA (typ) near -0.05 V on its own axis
[POWER Clamp]
| Voltage   I(typ)   I(min)   I(max)
-1.2V     13.99mA    12.6mA     15.11mA
-800mV    12.19mA    10.89mA    13.18mA
-600mV    10.68mA    9.504mA    11.58mA
-400mV    8.231mA    7.33mA     8.962mA
-200mV    4.284mA    3.919mA    4.647mA
425mV     -8.854mA   -8.033mA   -9.672mA
805mV     -16.2mA    -14.52mA   -17.79mA
1.145V    -21.77mA   -19.13mA   -24.07mA
1.4V      -24.81mA   -21.41mA   -27.59mA
1.6V      -26.33mA   -22.51mA   -29.33mA
1.8V      -27.27mA   -23.21mA   -30.34mA
2.4V      -28.65mA   -24.38mA   -31.65mA
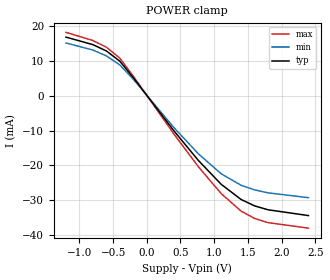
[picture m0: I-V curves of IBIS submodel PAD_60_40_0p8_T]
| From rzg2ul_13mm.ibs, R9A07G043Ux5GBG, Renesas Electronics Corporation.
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[Submodel]  PAD_60_40_0p8_T
Submodel_type Dynamic_clamp
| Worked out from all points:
|   POWER clamp passes 1 mA (typ) near -0.04 V on its own axis
[POWER Clamp]
| Voltage   I(typ)   I(min)   I(max)
-1.2V     16.78mA    15.11mA    18.14mA
-800mV    14.62mA    13.07mA    15.81mA
-600mV    12.82mA    11.4mA     13.89mA
-400mV    9.877mA    8.796mA    10.75mA
-200mV    5.141mA    4.703mA    5.577mA
405mV     -10.14mA   -9.203mA   -11.07mA
765mV     -18.56mA   -16.66mA   -20.37mA
1.105V    -25.43mA   -22.41mA   -28.09mA
1.4V      -29.77mA   -25.69mA   -33.1mA
1.6V      -31.6mA    -27.01mA   -35.2mA
1.8V      -32.72mA   -27.86mA   -36.41mA
2.4V      -34.38mA   -29.25mA   -37.98mA
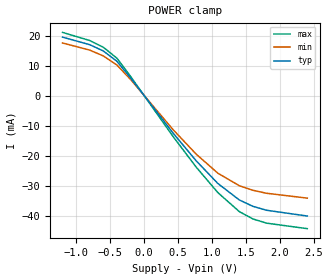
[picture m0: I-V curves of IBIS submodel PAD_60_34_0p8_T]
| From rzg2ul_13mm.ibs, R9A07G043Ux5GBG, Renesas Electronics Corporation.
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[Submodel]  PAD_60_34_0p8_T
Submodel_type Dynamic_clamp
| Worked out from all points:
|   POWER clamp passes 1 mA (typ) near -0.03 V on its own axis
[POWER Clamp]
| Voltage   I(typ)   I(min)   I(max)
-1.2V     19.58mA    17.63mA    21.16mA
-800mV    17.06mA    15.25mA    18.45mA
-600mV    14.96mA    13.31mA    16.21mA
-400mV    11.52mA    10.26mA    12.55mA
-200mV    5.998mA    5.487mA    6.506mA
425mV     -12.4mA    -11.25mA   -13.54mA
765mV     -21.65mA   -19.44mA   -23.76mA
1.085V    -29.25mA   -25.81mA   -32.29mA
1.4V      -34.73mA   -29.98mA   -38.62mA
1.6V      -36.86mA   -31.51mA   -41.07mA
1.8V      -38.17mA   -32.5mA    -42.47mA
2.4V      -40.1mA    -34.13mA   -44.31mA
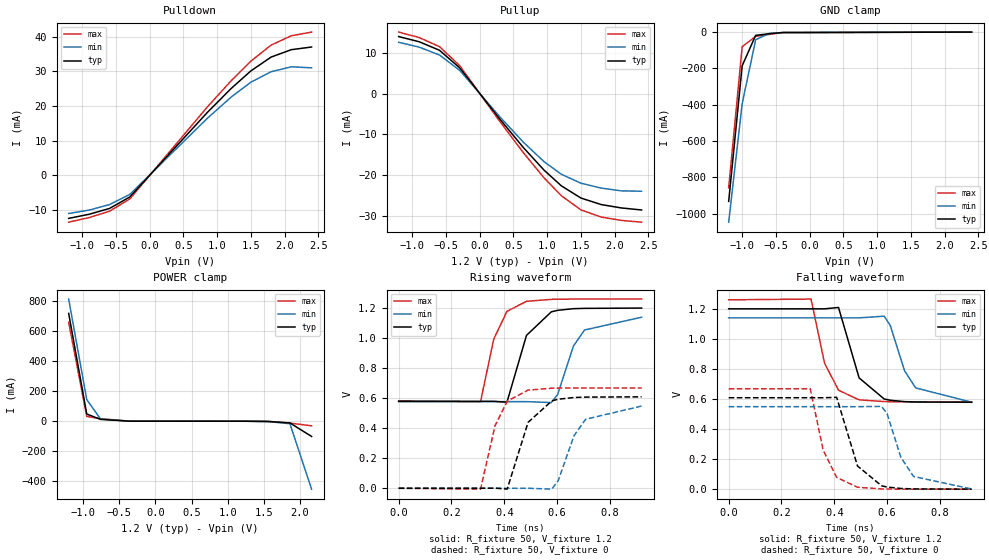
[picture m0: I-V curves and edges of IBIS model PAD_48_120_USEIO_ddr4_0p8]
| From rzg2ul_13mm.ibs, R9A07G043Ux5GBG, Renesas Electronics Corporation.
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[Model] PAD_48_120_USEIO_ddr4_0p8
Model_type I/O
Polarity   Non-Inverting
Vinl = 0.8670
Vinh = 1.0530
Vmeas= 0.960
| Capacitance   typ   min   max
C_comp   2.102e-12   2.013e-12   2.216e-12
[Model Spec]
| Subparameter   typ   min   max
Vmeas   0.960   0.912   1.008
Vinh   1.0530   1.0050   1.1010
Vinl   0.8670   0.8190   0.9150
| Variables   typ   min   max
[GND Clamp Reference]   0   0   0
[POWER Clamp Reference]   1.2   1.14   1.26
[Pulldown Reference]   0   0   0
[Pullup Reference]   1.2   1.14   1.26
[Temperature Range]   25   125   -40
[Voltage Range]   1.2   1.14   1.26
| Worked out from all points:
|   slope of the pulldown table from 0 to 0.18 V, typ, clamps not added: 46.2 ohm
|   slope of the pullup table from 0 to 0.18 V, typ, clamps not added: 47.3 ohm
|   GND clamp passes 1 mA (typ) near -0.30 V on its own axis
|   POWER clamp passes 1 mA (typ) near -0.38 V on its own axis
|   rising waveform, R_fixture 50, V_fixture 1.2: 20-80 % time 65.9ps typ, 74.8ps min, 59.4ps max; typ from 0.579 V to 1.2 V
|   rising waveform, R_fixture 50, V_fixture 0: 20-80 % time 69.7ps typ, 80.2ps min, 62.3ps max; typ from 0 V to 0.609 V
|   falling waveform, R_fixture 50, V_fixture 1.2: 20-80 % time 67.1ps typ, 76.6ps min, 61.5ps max; typ from 1.2 V to 0.578 V
|   falling waveform, R_fixture 50, V_fixture 0: 20-80 % time 66.3ps typ, 75ps min, 60.2ps max; typ from 0.608 V to 0 V
[GND Clamp]
| Voltage   I(typ)   I(min)   I(max)
-1.2V     -932.7mA   -1.047A    -857.4mA
-1V       -185.5mA   -394.3mA   -80.64mA
-800mV    -17.89mA   -41.9mA    -23.65mA
-600mV    -9.04mA    -7.411mA   -12.44mA
-400mV    -2.454mA   -2.378mA   -3.185mA
2.4V      0A         0A         0A
[POWER Clamp]
| Voltage   I(typ)   I(min)   I(max)
-1.2V     719.7mA    815.2mA    660.1mA
-950mV    48.1mA     144.6mA    32.07mA
-760mV    12.41mA    14.91mA    17.11mA
-360mV    527.4uA    791.2uA    575.5uA
1.26V     -115.5nA   -12.89uA   -796.6pA
1.56V     -1.53mA    -2.776mA   -549.4uA
1.86V     -11.39mA   -16.33mA   -12.44mA
2.16V     -101.5mA   -453.2mA   -30.39mA
[Pulldown]
| Voltage   I(typ)   I(min)   I(max)
-1.2V     -12.4mA    -11mA      -13.5mA
-895mV    -11.21mA   -10mA      -12.16mA
-595mV    -9.541mA   -8.428mA   -10.34mA
-295mV    -6.242mA   -5.509mA   -6.815mA
855mV     18.14mA    16.45mA    19.72mA
1.21V     25.08mA    22.6mA     27.32mA
1.5V      30.11mA    26.86mA    32.91mA
1.8V      34.1mA     29.87mA    37.56mA
2.1V      36.23mA    31.3mA     40.24mA
2.4V      37mA       31mA       41.3mA
[Pullup]
| Voltage   I(typ)   I(min)   I(max)
-1.2V     14mA       12.6mA     15.1mA
-895mV    12.72mA    11.4mA     13.75mA
-595mV    10.63mA    9.464mA    11.52mA
-295mV    6.299mA    5.693mA    6.844mA
300mV     -6.298mA   -5.73mA    -6.87mA
650mV     -13.3mA    -11.99mA   -14.57mA
955mV     -18.82mA   -16.74mA   -20.72mA
1.21V     -22.66mA   -19.82mA   -25.09mA
1.5V      -25.66mA   -22.02mA   -28.57mA
1.8V      -27.27mA   -23.22mA   -30.34mA
2.1V      -28.1mA    -23.9mA    -31.16mA
2.4V      -28.6mA    -24mA      -31.6mA
[Ramp]
dV/dt_r   0.3727/6.592e-11   0.3369/7.480e-11   0.4069/5.944e-11
dV/dt_f   0.3651/6.628e-11   0.3287/7.502e-11   0.4004/6.022e-11
R_load= 50
[Rising Waveform]
R_fixture = 50
V_fixture = 1.2
V_fixture_min = 1.14
V_fixture_max = 1.26
| Time   V(typ)   V(min)   V(max)
0s        578.8mV    577mV      581.9mV
310ps     578.8mV    577mV      576.4mV
360ps     579.1mV    577mV      992.9mV
410ps     572.7mV    577mV      1.178V
484ps     1.018V     577mV      1.245V
578ps     1.175V     570.6mV    1.258V
602ps     1.185V     624.5mV    1.259V
662ps     1.196V     947.7mV    1.26V
704ps     1.198V     1.054V     1.26V
920ps     1.2V       1.139V     1.26V
[Rising Waveform]
R_fixture = 50
V_fixture = 0
V_fixture_min = 0
V_fixture_max = 0
| Time   V(typ)   V(min)   V(max)
0s        105.5nV    4.403uV    18.25nV
310ps     383.6nV    4.256uV    -6.041mV
365ps     544.4uV    4.179uV    417.3mV
411ps     -5.361mV   15.68uV    579.4mV
490ps     438.7mV    20.53uV    653.7mV
580ps     582mV      -5.666mV   666.2mV
604ps     593mV      49.98mV    667mV
664ps     604.3mV    349.7mV    667.7mV
708ps     607.1mV    459.7mV    667.8mV
920ps     608.8mV    547.4mV    667.9mV
[Falling Waveform]
R_fixture = 50
V_fixture = 1.2
V_fixture_min = 1.14
V_fixture_max = 1.26
| Time   V(typ)   V(min)   V(max)
0s        1.2V       1.14V      1.26V
312ps     1.2V       1.14V      1.265V
363ps     1.2V       1.14V      838.5mV
416ps     1.209V     1.14V      658.3mV
494ps     740.3mV    1.14V      594.3mV
589ps     599.9mV    1.151V     582.7mV
612ps     591.6mV    1.089V     582.1mV
666ps     582.6mV    788.5mV    581.5mV
708ps     580mV      674mV      581.3mV
920ps     578.4mV    578.7mV    581.3mV
[Falling Waveform]
R_fixture = 50
V_fixture = 0
V_fixture_min = 0
V_fixture_max = 0
| Time   V(typ)   V(min)   V(max)
0s        608.4mV    549mV      667.3mV
309ps     608.4mV    549mV      668.3mV
358ps     608.2mV    549mV      258.9mV
409ps     611mV      549mV      78.36mV
488ps     154.2mV    548.9mV    12.66mV
579ps     22.39mV    550.8mV    1.442mV
600ps     14.08mV    502mV      848.6uV
652ps     4.753mV    212.3mV    271.9uV
700ps     1.615mV    84.61mV    72.28uV
920ps     10.87uV    1.24mV     289nV
[Add Submodel]
| Submodel Name Mode
PAD_48_120_0p8_T Non-Driving
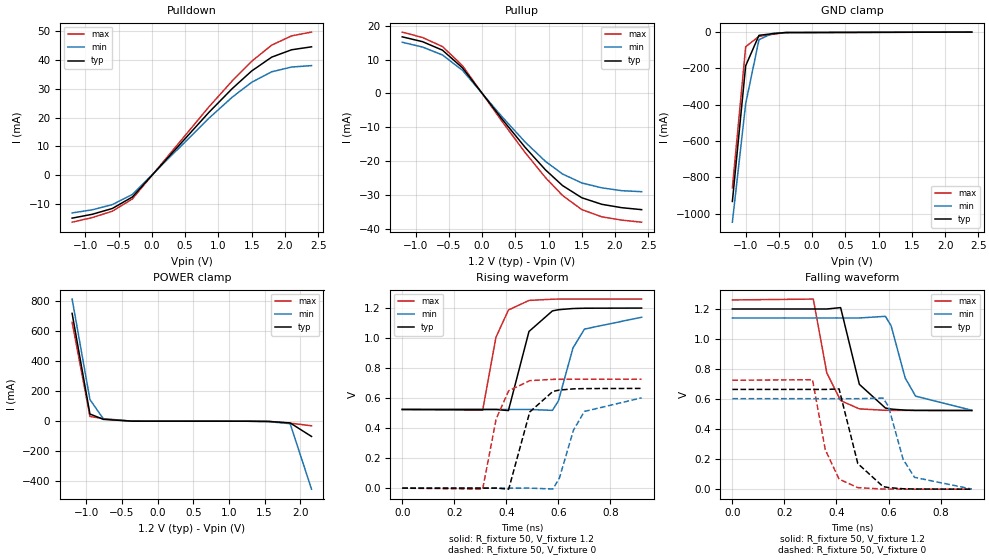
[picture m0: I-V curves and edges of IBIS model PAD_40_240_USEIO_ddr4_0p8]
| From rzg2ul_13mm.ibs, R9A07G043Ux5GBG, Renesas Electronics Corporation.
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[Model] PAD_40_240_USEIO_ddr4_0p8
Model_type I/O
Polarity   Non-Inverting
Vinl = 0.8670
Vinh = 1.0530
Vmeas= 0.960
| Capacitance   typ   min   max
C_comp   2.102e-12   2.013e-12   2.216e-12
[Model Spec]
| Subparameter   typ   min   max
Vmeas   0.960   0.912   1.008
Vinh   1.0530   1.0050   1.1010
Vinl   0.8670   0.8190   0.9150
| Variables   typ   min   max
[GND Clamp Reference]   0   0   0
[POWER Clamp Reference]   1.2   1.14   1.26
[Pulldown Reference]   0   0   0
[Pullup Reference]   1.2   1.14   1.26
[Temperature Range]   25   125   -40
[Voltage Range]   1.2   1.14   1.26
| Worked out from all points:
|   slope of the pulldown table from 0 to 0.18 V, typ, clamps not added: 38.5 ohm
|   slope of the pullup table from 0 to 0.18 V, typ, clamps not added: 39.5 ohm
|   GND clamp passes 1 mA (typ) near -0.30 V on its own axis
|   POWER clamp passes 1 mA (typ) near -0.38 V on its own axis
|   rising waveform, R_fixture 50, V_fixture 1.2: 20-80 % time 59.9ps typ, 68.7ps min, 53.3ps max; typ from 0.524 V to 1.2 V
|   rising waveform, R_fixture 50, V_fixture 0: 20-80 % time 62.9ps typ, 73.3ps min, 55.7ps max; typ from 0 V to 0.665 V
|   falling waveform, R_fixture 50, V_fixture 1.2: 20-80 % time 60.7ps typ, 70.2ps min, 55.4ps max; typ from 1.2 V to 0.524 V
|   falling waveform, R_fixture 50, V_fixture 0: 20-80 % time 60.2ps typ, 68.7ps min, 54.5ps max; typ from 0.664 V to 0 V
[GND Clamp]
| Voltage   I(typ)   I(min)   I(max)
-1.2V     -932.7mA   -1.047A    -857.4mA
-1V       -185.5mA   -394.3mA   -80.64mA
-800mV    -17.89mA   -41.9mA    -23.65mA
-600mV    -9.04mA    -7.411mA   -12.44mA
-400mV    -2.454mA   -2.378mA   -3.185mA
2.4V      0A         0A         0A
[POWER Clamp]
| Voltage   I(typ)   I(min)   I(max)
-1.2V     719.7mA    815.2mA    660.1mA
-950mV    48.1mA     144.6mA    32.07mA
-760mV    12.41mA    14.91mA    17.11mA
-360mV    527.4uA    791.2uA    575.5uA
1.26V     -115.5nA   -12.89uA   -796.6pA
1.56V     -1.53mA    -2.776mA   -549.4uA
1.86V     -11.39mA   -16.33mA   -12.44mA
2.16V     -101.5mA   -453.2mA   -30.39mA
[Pulldown]
| Voltage   I(typ)   I(min)   I(max)
-1.2V     -14.8mA    -13mA      -16.2mA
-895mV    -13.45mA   -11.9mA    -14.59mA
-595mV    -11.45mA   -10.11mA   -12.4mA
-295mV    -7.491mA   -6.611mA   -8.178mA
855mV     21.77mA    19.74mA    23.66mA
1.21V     30.1mA     27.12mA    32.78mA
1.5V      36.14mA    32.23mA    39.49mA
1.8V      40.92mA    35.85mA    45.07mA
2.1V      43.48mA    37.5mA     48.29mA
2.4V      44.5mA     38mA       49.6mA
[Pullup]
| Voltage   I(typ)   I(min)   I(max)
-1.2V     16.7mA     15.1mA     18.1mA
-895mV    15.27mA    13.68mA    16.5mA
-595mV    12.76mA    11.35mA    13.83mA
-295mV    7.559mA    6.831mA    8.212mA
300mV     -7.557mA   -6.876mA   -8.244mA
650mV     -15.96mA   -14.39mA   -17.49mA
955mV     -22.58mA   -20.08mA   -24.87mA
1.21V     -27.19mA   -23.78mA   -30.11mA
1.5V      -30.79mA   -26.42mA   -34.29mA
1.8V      -32.72mA   -27.86mA   -36.41mA
2.1V      -33.72mA   -28.7mA    -37.39mA
2.4V      -34.3mA    -29mA      -38mA
[Ramp]
dV/dt_r   0.4056/5.987e-11   0.3687/6.871e-11   0.4411/5.333e-11
dV/dt_f   0.3986/6.018e-11   0.3611/6.868e-11   0.4352/5.451e-11
R_load= 50
[Rising Waveform]
R_fixture = 50
V_fixture = 1.2
V_fixture_min = 1.14
V_fixture_max = 1.26
| Time   V(typ)   V(min)   V(max)
0s        524mV      524.6mV    524.8mV
309ps     524mV      524.6mV    519mV
360ps     524.4mV    524.6mV    1.005V
408ps     516.8mV    524.6mV    1.187V
487ps     1.044V     524.6mV    1.251V
577ps     1.181V     518.1mV    1.259V
600ps     1.189V     581mV      1.26V
656ps     1.197V     933.6mV    1.26V
700ps     1.199V     1.06V      1.26V
920ps     1.2V       1.139V     1.26V
[Rising Waveform]
R_fixture = 50
V_fixture = 0
V_fixture_min = 0
V_fixture_max = 0
| Time   V(typ)   V(min)   V(max)
0s        95.57nV    4.005uV    16.46nV
309ps     2.574uV    3.821uV    -6.795mV
361ps     483.8uV    3.533uV    462.2mV
409ps     -6.81mV    18.61uV    648.6mV
490ps     507.6mV    63.86uV    716.4mV
579ps     644.6mV    -5.651mV   724.9mV
604ps     653.7mV    67.37mV    725.3mV
658ps     661.5mV    387mV      725.7mV
700ps     663.5mV    511.2mV    725.8mV
920ps     664.6mV    601.8mV    725.8mV
[Falling Waveform]
R_fixture = 50
V_fixture = 1.2
V_fixture_min = 1.14
V_fixture_max = 1.26
| Time   V(typ)   V(min)   V(max)
0s        1.2V       1.14V      1.26V
311ps     1.2V       1.14V      1.266V
363ps     1.2V       1.14V      773.6mV
416ps     1.209V     1.14V      589.5mV
488ps     698mV      1.14V      534.7mV
588ps     540.4mV    1.151V     525.1mV
610ps     533.4mV    1.088V     524.7mV
664ps     526.3mV    740.9mV    524.4mV
704ps     524.6mV    619.5mV    524.4mV
920ps     523.6mV    525.5mV    524.3mV
[Falling Waveform]
R_fixture = 50
V_fixture = 0
V_fixture_min = 0
V_fixture_max = 0
| Time   V(typ)   V(min)   V(max)
0s        664.3mV    602.6mV    725.3mV
308ps     664.3mV    602.6mV    728.9mV
357ps     664mV      602.6mV    262.6mV
410ps     667.6mV    602.6mV    66.82mV
482ps     170.4mV    602.5mV    10.09mV
579ps     17.29mV    606.4mV    769.9uV
600ps     10.38mV    551mV      452.7uV
656ps     2.802mV    199.4mV    117.3uV
700ps     930.6uV    78.51mV    27.93uV
920ps     3.327uV    740.1uV    64.29nV
[Add Submodel]
| Submodel Name Mode
PAD_40_240_0p8_T Non-Driving
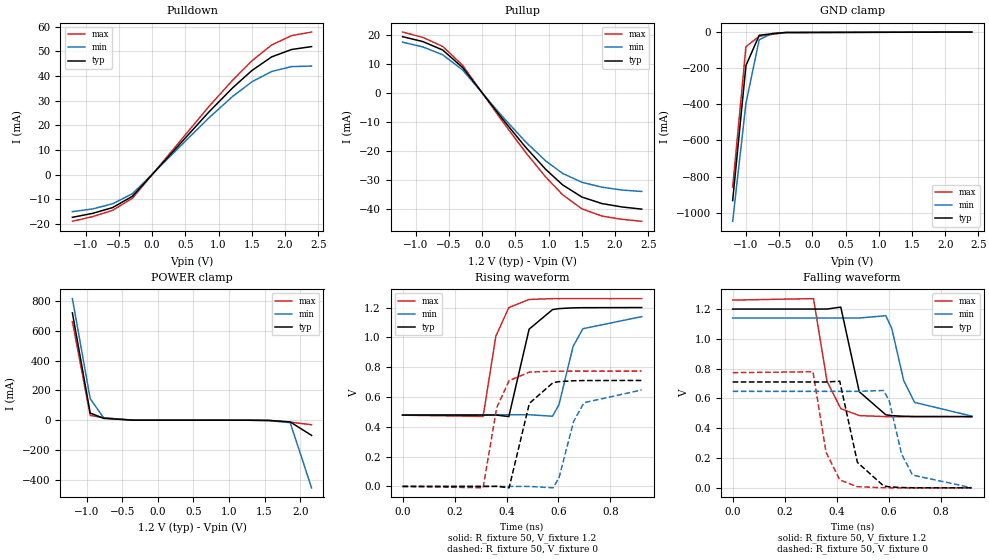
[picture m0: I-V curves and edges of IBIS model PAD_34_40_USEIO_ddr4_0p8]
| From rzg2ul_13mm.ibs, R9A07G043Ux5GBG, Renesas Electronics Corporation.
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[Model] PAD_34_40_USEIO_ddr4_0p8
Model_type I/O
Polarity   Non-Inverting
Vinl = 0.8670
Vinh = 1.0530
Vmeas= 0.960
| Capacitance   typ   min   max
C_comp   2.102e-12   2.013e-12   2.216e-12
[Model Spec]
| Subparameter   typ   min   max
Vmeas   0.960   0.912   1.008
Vinh   1.0530   1.0050   1.1010
Vinl   0.8670   0.8190   0.9150
| Variables   typ   min   max
[GND Clamp Reference]   0   0   0
[POWER Clamp Reference]   1.2   1.14   1.26
[Pulldown Reference]   0   0   0
[Pullup Reference]   1.2   1.14   1.26
[Temperature Range]   25   125   -40
[Voltage Range]   1.2   1.14   1.26
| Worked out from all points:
|   slope of the pulldown table from 0 to 0.18 V, typ, clamps not added: 33 ohm
|   slope of the pullup table from 0 to 0.18 V, typ, clamps not added: 33.8 ohm
|   GND clamp passes 1 mA (typ) near -0.30 V on its own axis
|   POWER clamp passes 1 mA (typ) near -0.38 V on its own axis
|   rising waveform, R_fixture 50, V_fixture 1.2: 20-80 % time 54.2ps typ, 62.6ps min, 48.2ps max; typ from 0.479 V to 1.2 V
|   rising waveform, R_fixture 50, V_fixture 0: 20-80 % time 57ps typ, 66.8ps min, 50.4ps max; typ from 0 V to 0.711 V
|   falling waveform, R_fixture 50, V_fixture 1.2: 20-80 % time 55.3ps typ, 64.4ps min, 50.2ps max; typ from 1.2 V to 0.478 V
|   falling waveform, R_fixture 50, V_fixture 0: 20-80 % time 54.7ps typ, 63ps min, 49.7ps max; typ from 0.711 V to 0 V
[GND Clamp]
| Voltage   I(typ)   I(min)   I(max)
-1.2V     -932.7mA   -1.047A    -857.4mA
-1V       -185.5mA   -394.3mA   -80.64mA
-800mV    -17.89mA   -41.9mA    -23.65mA
-600mV    -9.04mA    -7.411mA   -12.44mA
-400mV    -2.454mA   -2.378mA   -3.185mA
2.4V      0A         0A         0A
[POWER Clamp]
| Voltage   I(typ)   I(min)   I(max)
-1.2V     719.7mA    815.2mA    660.1mA
-950mV    48.1mA     144.6mA    32.07mA
-760mV    12.41mA    14.91mA    17.11mA
-360mV    527.4uA    791.2uA    575.5uA
1.26V     -115.5nA   -12.89uA   -796.6pA
1.56V     -1.53mA    -2.776mA   -549.4uA
1.86V     -11.39mA   -16.33mA   -12.44mA
2.16V     -101.5mA   -453.2mA   -30.39mA
[Pulldown]
| Voltage   I(typ)   I(min)   I(max)
-1.2V     -17.3mA    -15mA      -18.9mA
-895mV    -15.69mA   -13.9mA    -17.02mA
-595mV    -13.36mA   -11.8mA    -14.47mA
-295mV    -8.739mA   -7.713mA   -9.543mA
855mV     25.4mA     23.03mA    27.61mA
1.21V     35.12mA    31.64mA    38.24mA
1.5V      42.16mA    37.6mA     46.07mA
1.8V      47.74mA    41.82mA    52.58mA
2.1V      50.73mA    43.8mA     56.34mA
2.4V      51.9mA     44mA       57.8mA
[Pullup]
| Voltage   I(typ)   I(min)   I(max)
-1.2V     19.5mA     17.6mA     21.1mA
-895mV    17.81mA    15.96mA    19.25mA
-595mV    14.89mA    13.24mA    16.13mA
-295mV    8.818mA    7.97mA     9.581mA
300mV     -8.817mA   -8.022mA   -9.618mA
650mV     -18.62mA   -16.78mA   -20.4mA
955mV     -26.35mA   -23.43mA   -29.01mA
1.21V     -31.72mA   -27.75mA   -35.13mA
1.5V      -35.92mA   -30.83mA   -40mA
1.8V      -38.17mA   -32.5mA    -42.48mA
2.1V      -39.34mA   -33.5mA    -43.62mA
2.4V      -40.1mA    -34mA      -44.3mA
[Ramp]
dV/dt_r   0.4328/5.417e-11   0.3952/6.265e-11   0.4692/4.820e-11
dV/dt_f   0.4263/5.474e-11   0.3882/6.303e-11   0.4638/4.974e-11
R_load= 50
[Rising Waveform]
R_fixture = 50
V_fixture = 1.2
V_fixture_min = 1.14
V_fixture_max = 1.26
| Time   V(typ)   V(min)   V(max)
0s        478.6mV    480.8mV    477.9mV
310ps     478.6mV    480.8mV    469.4mV
359ps     479mV      480.8mV    1.008V
409ps     468.5mV    480.8mV    1.2V
487ps     1.055V     480.9mV    1.254V
577ps     1.186V     470.8mV    1.26V
602ps     1.193V     548.7mV    1.26V
656ps     1.198V     938.5mV    1.26V
694ps     1.199V     1.058V     1.26V
920ps     1.2V       1.139V     1.26V
[Rising Waveform]
R_fixture = 50
V_fixture = 0
V_fixture_min = 0
V_fixture_max = 0
| Time   V(typ)   V(min)   V(max)
0s        87.34nV    3.671uV    14.49nV
310ps     -1.605uV   3.455uV    -9.216mV
362ps     563.9uV    3.377uV    526.2mV
410ps     -9.57mV    16.96uV    709.6mV
488ps     557.3mV    -8.309uV   766.7mV
579ps     696mV      -9.346mV   773mV
602ps     702.8mV    57.53mV    773.2mV
658ps     708.9mV    434.7mV    773.4mV
698ps     710.2mV    561.6mV    773.4mV
920ps     710.8mV    647.1mV    773.4mV
[Falling Waveform]
R_fixture = 50
V_fixture = 1.2
V_fixture_min = 1.14
V_fixture_max = 1.26
| Time   V(typ)   V(min)   V(max)
0s        1.2V       1.14V      1.26V
311ps     1.2V       1.14V      1.27V
363ps     1.2V       1.14V      715.3mV
416ps     1.213V     1.14V      532mV
487ps     645.3mV    1.14V      484.9mV
589ps     490.3mV    1.155V     477.9mV
612ps     484.8mV    1.071V     477.7mV
658ps     480.3mV    720.8mV    477.6mV
700ps     478.9mV    573.6mV    477.5mV
920ps     478.3mV    481.4mV    477.5mV
[Falling Waveform]
R_fixture = 50
V_fixture = 0
V_fixture_min = 0
V_fixture_max = 0
| Time   V(typ)   V(min)   V(max)
0s        710.5mV    647.5mV    773mV
309ps     710.5mV    647.5mV    778.9mV
359ps     710.2mV    647.5mV    241mV
412ps     715.7mV    647.4mV    52.67mV
480ps     170.6mV    647.4mV    7.657mV
581ps     12.56mV    653.4mV    407.9uV
602ps     7.064mV    586.1mV    216.2uV
650ps     2.081mV    226.8mV    59.56uV
692ps     643.9uV    85.67mV    12.91uV
920ps     984.4nV    427.4uV    22.71nV
[Add Submodel]
| Submodel Name Mode
PAD_34_40_0p8_T Non-Driving
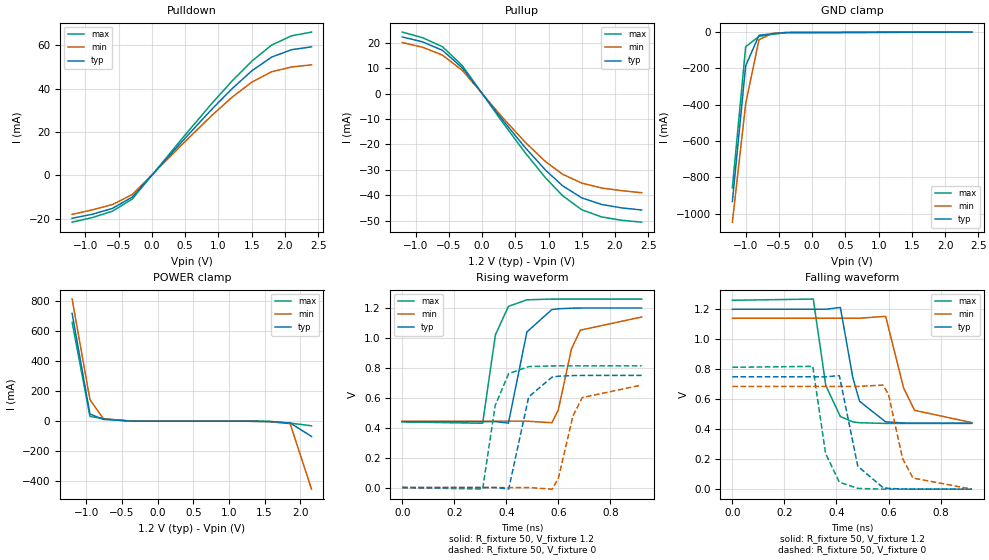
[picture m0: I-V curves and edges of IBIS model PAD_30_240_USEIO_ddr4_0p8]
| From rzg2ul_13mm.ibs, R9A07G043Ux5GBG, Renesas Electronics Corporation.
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[Model] PAD_30_240_USEIO_ddr4_0p8
Model_type I/O
Polarity   Non-Inverting
Vinl = 0.8670
Vinh = 1.0530
Vmeas= 0.960
| Capacitance   typ   min   max
C_comp   2.102e-12   2.013e-12   2.216e-12
[Model Spec]
| Subparameter   typ   min   max
Vmeas   0.960   0.912   1.008
Vinh   1.0530   1.0050   1.1010
Vinl   0.8670   0.8190   0.9150
| Variables   typ   min   max
[GND Clamp Reference]   0   0   0
[POWER Clamp Reference]   1.2   1.14   1.26
[Pulldown Reference]   0   0   0
[Pullup Reference]   1.2   1.14   1.26
[Temperature Range]   25   125   -40
[Voltage Range]   1.2   1.14   1.26
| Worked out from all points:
|   slope of the pulldown table from 0 to 0.18 V, typ, clamps not added: 28.9 ohm
|   slope of the pullup table from 0 to 0.18 V, typ, clamps not added: 29.6 ohm
|   GND clamp passes 1 mA (typ) near -0.30 V on its own axis
|   POWER clamp passes 1 mA (typ) near -0.38 V on its own axis
|   rising waveform, R_fixture 50, V_fixture 1.2: 20-80 % time 50.2ps typ, 58.4ps min, 44.3ps max; typ from 0.44 V to 1.2 V
|   rising waveform, R_fixture 50, V_fixture 0: 20-80 % time 52.3ps typ, 61.8ps min, 46.1ps max; typ from 0 V to 0.75 V
|   falling waveform, R_fixture 50, V_fixture 1.2: 20-80 % time 51ps typ, 60.1ps min, 46.1ps max; typ from 1.2 V to 0.44 V
|   falling waveform, R_fixture 50, V_fixture 0: 20-80 % time 50.7ps typ, 59.1ps min, 45.9ps max; typ from 0.749 V to 0 V
[GND Clamp]
| Voltage   I(typ)   I(min)   I(max)
-1.2V     -932.7mA   -1.047A    -857.4mA
-1V       -185.5mA   -394.3mA   -80.64mA
-800mV    -17.89mA   -41.9mA    -23.65mA
-600mV    -9.04mA    -7.411mA   -12.44mA
-400mV    -2.454mA   -2.378mA   -3.185mA
2.4V      0A         0A         0A
[POWER Clamp]
| Voltage   I(typ)   I(min)   I(max)
-1.2V     719.7mA    815.2mA    660.1mA
-950mV    48.1mA     144.6mA    32.07mA
-760mV    12.41mA    14.91mA    17.11mA
-360mV    527.4uA    791.2uA    575.5uA
1.26V     -115.5nA   -12.89uA   -796.6pA
1.56V     -1.53mA    -2.776mA   -549.4uA
1.86V     -11.39mA   -16.33mA   -12.44mA
2.16V     -101.5mA   -453.2mA   -30.39mA
[Pulldown]
| Voltage   I(typ)   I(min)   I(max)
-1.2V     -19.8mA    -18mA      -21.6mA
-895mV    -17.93mA   -15.9mA    -19.45mA
-595mV    -15.26mA   -13.48mA   -16.54mA
-295mV    -9.988mA   -8.815mA   -10.9mA
500mV     17.21mA    15.66mA    18.69mA
905mV     30.65mA    27.77mA    33.32mA
1.21V     40.14mA    36.16mA    43.71mA
1.5V      48.18mA    42.97mA    52.66mA
1.8V      54.57mA    47.8mA     60.1mA
2.1V      57.97mA    50mA       64.38mA
2.4V      59.3mA     51mA       66.1mA
[Pullup]
| Voltage   I(typ)   I(min)   I(max)
-1.2V     22.3mA     20.1mA     24.2mA
-895mV    20.36mA    18.24mA    22mA
-595mV    17.02mA    15.13mA    18.44mA
-295mV    10.08mA    9.108mA    10.95mA
300mV     -10.08mA   -9.168mA   -10.99mA
650mV     -21.28mA   -19.18mA   -23.31mA
955mV     -30.11mA   -26.78mA   -33.15mA
1.21V     -36.25mA   -31.71mA   -40.14mA
1.5V      -41.05mA   -35.23mA   -45.72mA
1.8V      -43.63mA   -37.14mA   -48.55mA
2.1V      -44.97mA   -38.2mA    -49.85mA
2.4V      -45.8mA    -39mA      -50.6mA
[Ramp]
dV/dt_r   0.4557/5.017e-11   0.4176/5.841e-11   0.4928/4.434e-11
dV/dt_f   0.4497/5.073e-11   0.4111/5.907e-11   0.4878/4.590e-11
R_load= 50
[Rising Waveform]
R_fixture = 50
V_fixture = 1.2
V_fixture_min = 1.14
V_fixture_max = 1.26
| Time   V(typ)   V(min)   V(max)
0s        440.5mV    443.8mV    438.7mV
309ps     440.5mV    443.8mV    429.6mV
358ps     440.9mV    443.8mV    1.021V
408ps     430.3mV    443.8mV    1.211V
479ps     1.04V      443.7mV    1.255V
575ps     1.19V      433.3mV    1.26V
600ps     1.195V     520.7mV    1.26V
650ps     1.199V     925.4mV    1.26V
684ps     1.2V       1.052V     1.26V
920ps     1.2V       1.14V      1.26V
[Rising Waveform]
R_fixture = 50
V_fixture = 0
V_fixture_min = 0
V_fixture_max = 0
| Time   V(typ)   V(min)   V(max)
0s        80.42nV    3.391uV    13.78nV
309ps     619.3nV    3.136uV    -10.31mV
357ps     375.7uV    2.79uV     547.5mV
409ps     -10.07mV   19.9uV     761.8mV
486ps     606.3mV    -1.655uV   808.7mV
576ps     738.5mV    -10.95mV   813mV
600ps     744.2mV    62.21mV    813.2mV
656ps     748.6mV    479.2mV    813.3mV
692ps     749.4mV    601.6mV    813.3mV
920ps     749.7mV    685.3mV    813.3mV
[Falling Waveform]
R_fixture = 50
V_fixture = 1.2
V_fixture_min = 1.14
V_fixture_max = 1.26
| Time   V(typ)   V(min)   V(max)
0s        1.2V       1.14V      1.26V
311ps     1.2V       1.14V      1.268V
359ps     1.2V       1.14V      691.3mV
415ps     1.212V     1.14V      484.1mV
463ps     742.9mV    1.14V      448.9mV
489ps     585.6mV    1.14V      443.1mV
589ps     448.9mV    1.153V     438.6mV
658ps     441.4mV    675.4mV    438.4mV
700ps     440.5mV    525.9mV    438.4mV
920ps     440.2mV    444.1mV    438.4mV
[Falling Waveform]
R_fixture = 50
V_fixture = 0
V_fixture_min = 0
V_fixture_max = 0
| Time   V(typ)   V(min)   V(max)
0s        749.5mV    685.4mV    812.9mV
309ps     749.5mV    685.4mV    819mV
358ps     749.2mV    685.4mV    238.8mV
411ps     757.2mV    685.4mV    46.37mV
482ps     153mV      685.4mV    5.016mV
579ps     9.892mV    694.2mV    204.2uV
600ps     5.303mV    632mV      100.5uV
654ps     1.176mV    204.4mV    20.98uV
694ps     338.4uV    74.44mV    3.761uV
920ps     319.5nV    250.1uV    15.29nV
[Add Submodel]
| Submodel Name Mode
PAD_30_240_0p8_T Non-Driving
